VERSION 5.7 ;
BUSBITCHARS "[]" ;
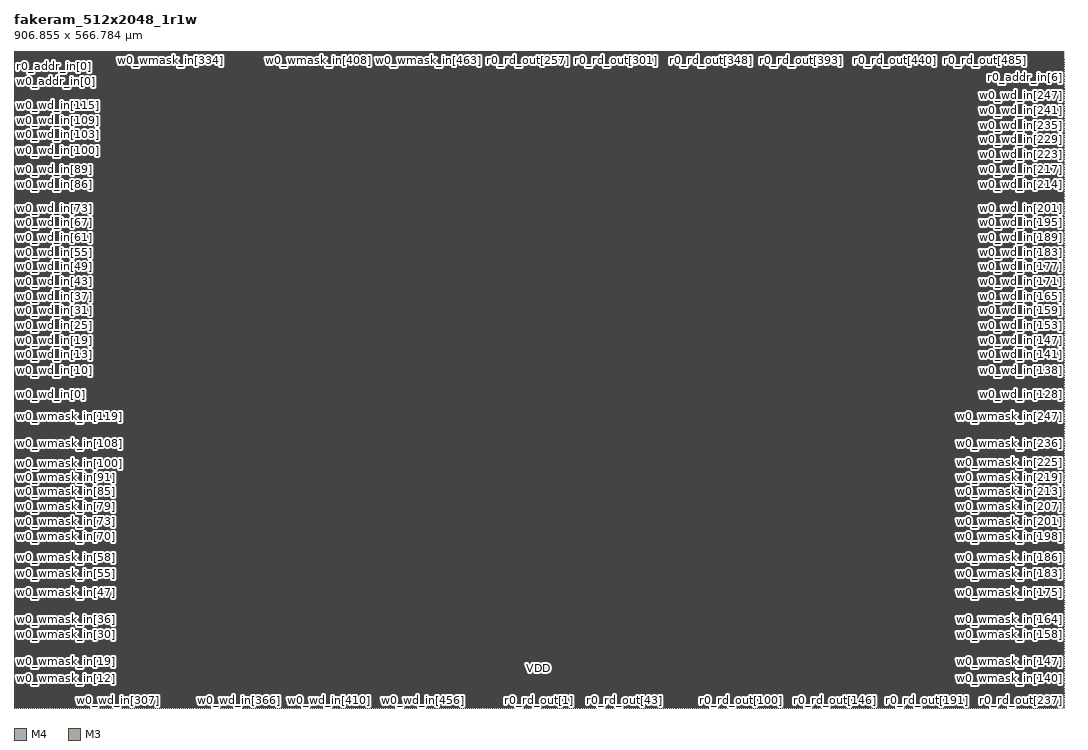
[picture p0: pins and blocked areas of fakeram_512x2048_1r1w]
MACRO fakeram_512x2048_1r1w
  FOREIGN fakeram_512x2048_1r1w 0 0 ;
  SYMMETRY X Y R90 ;
  SIZE 906.855 BY 566.784 ;
  CLASS BLOCK ;
  PIN w0_wmask_in[0]
    DIRECTION INPUT ;
    USE SIGNAL ;
    SHAPE ABUTMENT ;
    PORT
      LAYER M4 ;
      RECT 0.000 0.276 0.072 0.300 ;
    END
  END w0_wmask_in[0]
  PIN w0_wmask_in[1]
    DIRECTION INPUT ;
    USE SIGNAL ;
    SHAPE ABUTMENT ;
    PORT
      LAYER M4 ;
      RECT 0.000 2.388 0.072 2.412 ;
    END
  END w0_wmask_in[1]
  PIN w0_wmask_in[2]
    DIRECTION INPUT ;
    USE SIGNAL ;
    SHAPE ABUTMENT ;
    PORT
      LAYER M4 ;
      RECT 0.000 4.500 0.072 4.524 ;
    END
  END w0_wmask_in[2]
  PIN w0_wmask_in[3]
    DIRECTION INPUT ;
    USE SIGNAL ;
    SHAPE ABUTMENT ;
    PORT
      LAYER M4 ;
      RECT 0.000 6.612 0.072 6.636 ;
    END
  END w0_wmask_in[3]
  PIN w0_wmask_in[4]
    DIRECTION INPUT ;
    USE SIGNAL ;
    SHAPE ABUTMENT ;
    PORT
      LAYER M4 ;
      RECT 0.000 8.724 0.072 8.748 ;
    END
  END w0_wmask_in[4]
  PIN w0_wmask_in[5]
    DIRECTION INPUT ;
    USE SIGNAL ;
    SHAPE ABUTMENT ;
    PORT
      LAYER M4 ;
      RECT 0.000 10.836 0.072 10.860 ;
    END
  END w0_wmask_in[5]
  PIN w0_wmask_in[6]
    DIRECTION INPUT ;
    USE SIGNAL ;
    SHAPE ABUTMENT ;
    PORT
      LAYER M4 ;
      RECT 0.000 12.948 0.072 12.972 ;
    END
  END w0_wmask_in[6]
  PIN w0_wmask_in[7]
    DIRECTION INPUT ;
    USE SIGNAL ;
    SHAPE ABUTMENT ;
    PORT
      LAYER M4 ;
      RECT 0.000 15.060 0.072 15.084 ;
    END
  END w0_wmask_in[7]
  PIN w0_wmask_in[8]
    DIRECTION INPUT ;
    USE SIGNAL ;
    SHAPE ABUTMENT ;
    PORT
      LAYER M4 ;
      RECT 0.000 17.172 0.072 17.196 ;
    END
  END w0_wmask_in[8]
  PIN w0_wmask_in[9]
    DIRECTION INPUT ;
    USE SIGNAL ;
    SHAPE ABUTMENT ;
    PORT
      LAYER M4 ;
      RECT 0.000 19.284 0.072 19.308 ;
    END
  END w0_wmask_in[9]
  PIN w0_wmask_in[10]
    DIRECTION INPUT ;
    USE SIGNAL ;
    SHAPE ABUTMENT ;
    PORT
      LAYER M4 ;
      RECT 0.000 21.396 0.072 21.420 ;
    END
  END w0_wmask_in[10]
  PIN w0_wmask_in[11]
    DIRECTION INPUT ;
    USE SIGNAL ;
    SHAPE ABUTMENT ;
    PORT
      LAYER M4 ;
      RECT 0.000 23.508 0.072 23.532 ;
    END
  END w0_wmask_in[11]
  PIN w0_wmask_in[12]
    DIRECTION INPUT ;
    USE SIGNAL ;
    SHAPE ABUTMENT ;
    PORT
      LAYER M4 ;
      RECT 0.000 25.620 0.072 25.644 ;
    END
  END w0_wmask_in[12]
  PIN w0_wmask_in[13]
    DIRECTION INPUT ;
    USE SIGNAL ;
    SHAPE ABUTMENT ;
    PORT
      LAYER M4 ;
      RECT 0.000 27.732 0.072 27.756 ;
    END
  END w0_wmask_in[13]
  PIN w0_wmask_in[14]
    DIRECTION INPUT ;
    USE SIGNAL ;
    SHAPE ABUTMENT ;
    PORT
      LAYER M4 ;
      RECT 0.000 29.844 0.072 29.868 ;
    END
  END w0_wmask_in[14]
  PIN w0_wmask_in[15]
    DIRECTION INPUT ;
    USE SIGNAL ;
    SHAPE ABUTMENT ;
    PORT
      LAYER M4 ;
      RECT 0.000 31.956 0.072 31.980 ;
    END
  END w0_wmask_in[15]
  PIN w0_wmask_in[16]
    DIRECTION INPUT ;
    USE SIGNAL ;
    SHAPE ABUTMENT ;
    PORT
      LAYER M4 ;
      RECT 0.000 34.068 0.072 34.092 ;
    END
  END w0_wmask_in[16]
  PIN w0_wmask_in[17]
    DIRECTION INPUT ;
    USE SIGNAL ;
    SHAPE ABUTMENT ;
    PORT
      LAYER M4 ;
      RECT 0.000 36.180 0.072 36.204 ;
    END
  END w0_wmask_in[17]
  PIN w0_wmask_in[18]
    DIRECTION INPUT ;
    USE SIGNAL ;
    SHAPE ABUTMENT ;
    PORT
      LAYER M4 ;
      RECT 0.000 38.292 0.072 38.316 ;
    END
  END w0_wmask_in[18]
  PIN w0_wmask_in[19]
    DIRECTION INPUT ;
    USE SIGNAL ;
    SHAPE ABUTMENT ;
    PORT
      LAYER M4 ;
      RECT 0.000 40.404 0.072 40.428 ;
    END
  END w0_wmask_in[19]
  PIN w0_wmask_in[20]
    DIRECTION INPUT ;
    USE SIGNAL ;
    SHAPE ABUTMENT ;
    PORT
      LAYER M4 ;
      RECT 0.000 42.516 0.072 42.540 ;
    END
  END w0_wmask_in[20]
  PIN w0_wmask_in[21]
    DIRECTION INPUT ;
    USE SIGNAL ;
    SHAPE ABUTMENT ;
    PORT
      LAYER M4 ;
      RECT 0.000 44.628 0.072 44.652 ;
    END
  END w0_wmask_in[21]
  PIN w0_wmask_in[22]
    DIRECTION INPUT ;
    USE SIGNAL ;
    SHAPE ABUTMENT ;
    PORT
      LAYER M4 ;
      RECT 0.000 46.740 0.072 46.764 ;
    END
  END w0_wmask_in[22]
  PIN w0_wmask_in[23]
    DIRECTION INPUT ;
    USE SIGNAL ;
    SHAPE ABUTMENT ;
    PORT
      LAYER M4 ;
      RECT 0.000 48.852 0.072 48.876 ;
    END
  END w0_wmask_in[23]
  PIN w0_wmask_in[24]
    DIRECTION INPUT ;
    USE SIGNAL ;
    SHAPE ABUTMENT ;
    PORT
      LAYER M4 ;
      RECT 0.000 50.964 0.072 50.988 ;
    END
  END w0_wmask_in[24]
  PIN w0_wmask_in[25]
    DIRECTION INPUT ;
    USE SIGNAL ;
    SHAPE ABUTMENT ;
    PORT
      LAYER M4 ;
      RECT 0.000 53.076 0.072 53.100 ;
    END
  END w0_wmask_in[25]
  PIN w0_wmask_in[26]
    DIRECTION INPUT ;
    USE SIGNAL ;
    SHAPE ABUTMENT ;
    PORT
      LAYER M4 ;
      RECT 0.000 55.188 0.072 55.212 ;
    END
  END w0_wmask_in[26]
  PIN w0_wmask_in[27]
    DIRECTION INPUT ;
    USE SIGNAL ;
    SHAPE ABUTMENT ;
    PORT
      LAYER M4 ;
      RECT 0.000 57.300 0.072 57.324 ;
    END
  END w0_wmask_in[27]
  PIN w0_wmask_in[28]
    DIRECTION INPUT ;
    USE SIGNAL ;
    SHAPE ABUTMENT ;
    PORT
      LAYER M4 ;
      RECT 0.000 59.412 0.072 59.436 ;
    END
  END w0_wmask_in[28]
  PIN w0_wmask_in[29]
    DIRECTION INPUT ;
    USE SIGNAL ;
    SHAPE ABUTMENT ;
    PORT
      LAYER M4 ;
      RECT 0.000 61.524 0.072 61.548 ;
    END
  END w0_wmask_in[29]
  PIN w0_wmask_in[30]
    DIRECTION INPUT ;
    USE SIGNAL ;
    SHAPE ABUTMENT ;
    PORT
      LAYER M4 ;
      RECT 0.000 63.636 0.072 63.660 ;
    END
  END w0_wmask_in[30]
  PIN w0_wmask_in[31]
    DIRECTION INPUT ;
    USE SIGNAL ;
    SHAPE ABUTMENT ;
    PORT
      LAYER M4 ;
      RECT 0.000 65.748 0.072 65.772 ;
    END
  END w0_wmask_in[31]
  PIN w0_wmask_in[32]
    DIRECTION INPUT ;
    USE SIGNAL ;
    SHAPE ABUTMENT ;
    PORT
      LAYER M4 ;
      RECT 0.000 67.860 0.072 67.884 ;
    END
  END w0_wmask_in[32]
  PIN w0_wmask_in[33]
    DIRECTION INPUT ;
    USE SIGNAL ;
    SHAPE ABUTMENT ;
    PORT
      LAYER M4 ;
      RECT 0.000 69.972 0.072 69.996 ;
    END
  END w0_wmask_in[33]
  PIN w0_wmask_in[34]
    DIRECTION INPUT ;
    USE SIGNAL ;
    SHAPE ABUTMENT ;
    PORT
      LAYER M4 ;
      RECT 0.000 72.084 0.072 72.108 ;
    END
  END w0_wmask_in[34]
  PIN w0_wmask_in[35]
    DIRECTION INPUT ;
    USE SIGNAL ;
    SHAPE ABUTMENT ;
    PORT
      LAYER M4 ;
      RECT 0.000 74.196 0.072 74.220 ;
    END
  END w0_wmask_in[35]
  PIN w0_wmask_in[36]
    DIRECTION INPUT ;
    USE SIGNAL ;
    SHAPE ABUTMENT ;
    PORT
      LAYER M4 ;
      RECT 0.000 76.308 0.072 76.332 ;
    END
  END w0_wmask_in[36]
  PIN w0_wmask_in[37]
    DIRECTION INPUT ;
    USE SIGNAL ;
    SHAPE ABUTMENT ;
    PORT
      LAYER M4 ;
      RECT 0.000 78.420 0.072 78.444 ;
    END
  END w0_wmask_in[37]
  PIN w0_wmask_in[38]
    DIRECTION INPUT ;
    USE SIGNAL ;
    SHAPE ABUTMENT ;
    PORT
      LAYER M4 ;
      RECT 0.000 80.532 0.072 80.556 ;
    END
  END w0_wmask_in[38]
  PIN w0_wmask_in[39]
    DIRECTION INPUT ;
    USE SIGNAL ;
    SHAPE ABUTMENT ;
    PORT
      LAYER M4 ;
      RECT 0.000 82.644 0.072 82.668 ;
    END
  END w0_wmask_in[39]
  PIN w0_wmask_in[40]
    DIRECTION INPUT ;
    USE SIGNAL ;
    SHAPE ABUTMENT ;
    PORT
      LAYER M4 ;
      RECT 0.000 84.756 0.072 84.780 ;
    END
  END w0_wmask_in[40]
  PIN w0_wmask_in[41]
    DIRECTION INPUT ;
    USE SIGNAL ;
    SHAPE ABUTMENT ;
    PORT
      LAYER M4 ;
      RECT 0.000 86.868 0.072 86.892 ;
    END
  END w0_wmask_in[41]
  PIN w0_wmask_in[42]
    DIRECTION INPUT ;
    USE SIGNAL ;
    SHAPE ABUTMENT ;
    PORT
      LAYER M4 ;
      RECT 0.000 88.980 0.072 89.004 ;
    END
  END w0_wmask_in[42]
  PIN w0_wmask_in[43]
    DIRECTION INPUT ;
    USE SIGNAL ;
    SHAPE ABUTMENT ;
    PORT
      LAYER M4 ;
      RECT 0.000 91.092 0.072 91.116 ;
    END
  END w0_wmask_in[43]
  PIN w0_wmask_in[44]
    DIRECTION INPUT ;
    USE SIGNAL ;
    SHAPE ABUTMENT ;
    PORT
      LAYER M4 ;
      RECT 0.000 93.204 0.072 93.228 ;
    END
  END w0_wmask_in[44]
  PIN w0_wmask_in[45]
    DIRECTION INPUT ;
    USE SIGNAL ;
    SHAPE ABUTMENT ;
    PORT
      LAYER M4 ;
      RECT 0.000 95.316 0.072 95.340 ;
    END
  END w0_wmask_in[45]
  PIN w0_wmask_in[46]
    DIRECTION INPUT ;
    USE SIGNAL ;
    SHAPE ABUTMENT ;
    PORT
      LAYER M4 ;
      RECT 0.000 97.428 0.072 97.452 ;
    END
  END w0_wmask_in[46]
  PIN w0_wmask_in[47]
    DIRECTION INPUT ;
    USE SIGNAL ;
    SHAPE ABUTMENT ;
    PORT
      LAYER M4 ;
      RECT 0.000 99.540 0.072 99.564 ;
    END
  END w0_wmask_in[47]
  PIN w0_wmask_in[48]
    DIRECTION INPUT ;
    USE SIGNAL ;
    SHAPE ABUTMENT ;
    PORT
      LAYER M4 ;
      RECT 0.000 101.652 0.072 101.676 ;
    END
  END w0_wmask_in[48]
  PIN w0_wmask_in[49]
    DIRECTION INPUT ;
    USE SIGNAL ;
    SHAPE ABUTMENT ;
    PORT
      LAYER M4 ;
      RECT 0.000 103.764 0.072 103.788 ;
    END
  END w0_wmask_in[49]
  PIN w0_wmask_in[50]
    DIRECTION INPUT ;
    USE SIGNAL ;
    SHAPE ABUTMENT ;
    PORT
      LAYER M4 ;
      RECT 0.000 105.876 0.072 105.900 ;
    END
  END w0_wmask_in[50]
  PIN w0_wmask_in[51]
    DIRECTION INPUT ;
    USE SIGNAL ;
    SHAPE ABUTMENT ;
    PORT
      LAYER M4 ;
      RECT 0.000 107.988 0.072 108.012 ;
    END
  END w0_wmask_in[51]
  PIN w0_wmask_in[52]
    DIRECTION INPUT ;
    USE SIGNAL ;
    SHAPE ABUTMENT ;
    PORT
      LAYER M4 ;
      RECT 0.000 110.100 0.072 110.124 ;
    END
  END w0_wmask_in[52]
  PIN w0_wmask_in[53]
    DIRECTION INPUT ;
    USE SIGNAL ;
    SHAPE ABUTMENT ;
    PORT
      LAYER M4 ;
      RECT 0.000 112.212 0.072 112.236 ;
    END
  END w0_wmask_in[53]
  PIN w0_wmask_in[54]
    DIRECTION INPUT ;
    USE SIGNAL ;
    SHAPE ABUTMENT ;
    PORT
      LAYER M4 ;
      RECT 0.000 114.324 0.072 114.348 ;
    END
  END w0_wmask_in[54]
  PIN w0_wmask_in[55]
    DIRECTION INPUT ;
    USE SIGNAL ;
    SHAPE ABUTMENT ;
    PORT
      LAYER M4 ;
      RECT 0.000 116.436 0.072 116.460 ;
    END
  END w0_wmask_in[55]
  PIN w0_wmask_in[56]
    DIRECTION INPUT ;
    USE SIGNAL ;
    SHAPE ABUTMENT ;
    PORT
      LAYER M4 ;
      RECT 0.000 118.548 0.072 118.572 ;
    END
  END w0_wmask_in[56]
  PIN w0_wmask_in[57]
    DIRECTION INPUT ;
    USE SIGNAL ;
    SHAPE ABUTMENT ;
    PORT
      LAYER M4 ;
      RECT 0.000 120.660 0.072 120.684 ;
    END
  END w0_wmask_in[57]
  PIN w0_wmask_in[58]
    DIRECTION INPUT ;
    USE SIGNAL ;
    SHAPE ABUTMENT ;
    PORT
      LAYER M4 ;
      RECT 0.000 122.772 0.072 122.796 ;
    END
  END w0_wmask_in[58]
  PIN w0_wmask_in[59]
    DIRECTION INPUT ;
    USE SIGNAL ;
    SHAPE ABUTMENT ;
    PORT
      LAYER M4 ;
      RECT 0.000 124.884 0.072 124.908 ;
    END
  END w0_wmask_in[59]
  PIN w0_wmask_in[60]
    DIRECTION INPUT ;
    USE SIGNAL ;
    SHAPE ABUTMENT ;
    PORT
      LAYER M4 ;
      RECT 0.000 126.996 0.072 127.020 ;
    END
  END w0_wmask_in[60]
  PIN w0_wmask_in[61]
    DIRECTION INPUT ;
    USE SIGNAL ;
    SHAPE ABUTMENT ;
    PORT
      LAYER M4 ;
      RECT 0.000 129.108 0.072 129.132 ;
    END
  END w0_wmask_in[61]
  PIN w0_wmask_in[62]
    DIRECTION INPUT ;
    USE SIGNAL ;
    SHAPE ABUTMENT ;
    PORT
      LAYER M4 ;
      RECT 0.000 131.220 0.072 131.244 ;
    END
  END w0_wmask_in[62]
  PIN w0_wmask_in[63]
    DIRECTION INPUT ;
    USE SIGNAL ;
    SHAPE ABUTMENT ;
    PORT
      LAYER M4 ;
      RECT 0.000 133.332 0.072 133.356 ;
    END
  END w0_wmask_in[63]
  PIN w0_wmask_in[64]
    DIRECTION INPUT ;
    USE SIGNAL ;
    SHAPE ABUTMENT ;
    PORT
      LAYER M4 ;
      RECT 0.000 135.444 0.072 135.468 ;
    END
  END w0_wmask_in[64]
  PIN w0_wmask_in[65]
    DIRECTION INPUT ;
    USE SIGNAL ;
    SHAPE ABUTMENT ;
    PORT
      LAYER M4 ;
      RECT 0.000 137.556 0.072 137.580 ;
    END
  END w0_wmask_in[65]
  PIN w0_wmask_in[66]
    DIRECTION INPUT ;
    USE SIGNAL ;
    SHAPE ABUTMENT ;
    PORT
      LAYER M4 ;
      RECT 0.000 139.668 0.072 139.692 ;
    END
  END w0_wmask_in[66]
  PIN w0_wmask_in[67]
    DIRECTION INPUT ;
    USE SIGNAL ;
    SHAPE ABUTMENT ;
    PORT
      LAYER M4 ;
      RECT 0.000 141.780 0.072 141.804 ;
    END
  END w0_wmask_in[67]
  PIN w0_wmask_in[68]
    DIRECTION INPUT ;
    USE SIGNAL ;
    SHAPE ABUTMENT ;
    PORT
      LAYER M4 ;
      RECT 0.000 143.892 0.072 143.916 ;
    END
  END w0_wmask_in[68]
  PIN w0_wmask_in[69]
    DIRECTION INPUT ;
    USE SIGNAL ;
    SHAPE ABUTMENT ;
    PORT
      LAYER M4 ;
      RECT 0.000 146.004 0.072 146.028 ;
    END
  END w0_wmask_in[69]
  PIN w0_wmask_in[70]
    DIRECTION INPUT ;
    USE SIGNAL ;
    SHAPE ABUTMENT ;
    PORT
      LAYER M4 ;
      RECT 0.000 148.116 0.072 148.140 ;
    END
  END w0_wmask_in[70]
  PIN w0_wmask_in[71]
    DIRECTION INPUT ;
    USE SIGNAL ;
    SHAPE ABUTMENT ;
    PORT
      LAYER M4 ;
      RECT 0.000 150.228 0.072 150.252 ;
    END
  END w0_wmask_in[71]
  PIN w0_wmask_in[72]
    DIRECTION INPUT ;
    USE SIGNAL ;
    SHAPE ABUTMENT ;
    PORT
      LAYER M4 ;
      RECT 0.000 152.340 0.072 152.364 ;
    END
  END w0_wmask_in[72]
  PIN w0_wmask_in[73]
    DIRECTION INPUT ;
    USE SIGNAL ;
    SHAPE ABUTMENT ;
    PORT
      LAYER M4 ;
      RECT 0.000 154.452 0.072 154.476 ;
    END
  END w0_wmask_in[73]
  PIN w0_wmask_in[74]
    DIRECTION INPUT ;
    USE SIGNAL ;
    SHAPE ABUTMENT ;
    PORT
      LAYER M4 ;
      RECT 0.000 156.564 0.072 156.588 ;
    END
  END w0_wmask_in[74]
  PIN w0_wmask_in[75]
    DIRECTION INPUT ;
    USE SIGNAL ;
    SHAPE ABUTMENT ;
    PORT
      LAYER M4 ;
      RECT 0.000 158.676 0.072 158.700 ;
    END
  END w0_wmask_in[75]
  PIN w0_wmask_in[76]
    DIRECTION INPUT ;
    USE SIGNAL ;
    SHAPE ABUTMENT ;
    PORT
      LAYER M4 ;
      RECT 0.000 160.788 0.072 160.812 ;
    END
  END w0_wmask_in[76]
  PIN w0_wmask_in[77]
    DIRECTION INPUT ;
    USE SIGNAL ;
    SHAPE ABUTMENT ;
    PORT
      LAYER M4 ;
      RECT 0.000 162.900 0.072 162.924 ;
    END
  END w0_wmask_in[77]
  PIN w0_wmask_in[78]
    DIRECTION INPUT ;
    USE SIGNAL ;
    SHAPE ABUTMENT ;
    PORT
      LAYER M4 ;
      RECT 0.000 165.012 0.072 165.036 ;
    END
  END w0_wmask_in[78]
  PIN w0_wmask_in[79]
    DIRECTION INPUT ;
    USE SIGNAL ;
    SHAPE ABUTMENT ;
    PORT
      LAYER M4 ;
      RECT 0.000 167.124 0.072 167.148 ;
    END
  END w0_wmask_in[79]
  PIN w0_wmask_in[80]
    DIRECTION INPUT ;
    USE SIGNAL ;
    SHAPE ABUTMENT ;
    PORT
      LAYER M4 ;
      RECT 0.000 169.236 0.072 169.260 ;
    END
  END w0_wmask_in[80]
  PIN w0_wmask_in[81]
    DIRECTION INPUT ;
    USE SIGNAL ;
    SHAPE ABUTMENT ;
    PORT
      LAYER M4 ;
      RECT 0.000 171.348 0.072 171.372 ;
    END
  END w0_wmask_in[81]
  PIN w0_wmask_in[82]
    DIRECTION INPUT ;
    USE SIGNAL ;
    SHAPE ABUTMENT ;
    PORT
      LAYER M4 ;
      RECT 0.000 173.460 0.072 173.484 ;
    END
  END w0_wmask_in[82]
  PIN w0_wmask_in[83]
    DIRECTION INPUT ;
    USE SIGNAL ;
    SHAPE ABUTMENT ;
    PORT
      LAYER M4 ;
      RECT 0.000 175.572 0.072 175.596 ;
    END
  END w0_wmask_in[83]
  PIN w0_wmask_in[84]
    DIRECTION INPUT ;
    USE SIGNAL ;
    SHAPE ABUTMENT ;
    PORT
      LAYER M4 ;
      RECT 0.000 177.684 0.072 177.708 ;
    END
  END w0_wmask_in[84]
  PIN w0_wmask_in[85]
    DIRECTION INPUT ;
    USE SIGNAL ;
    SHAPE ABUTMENT ;
    PORT
      LAYER M4 ;
      RECT 0.000 179.796 0.072 179.820 ;
    END
  END w0_wmask_in[85]
  PIN w0_wmask_in[86]
    DIRECTION INPUT ;
    USE SIGNAL ;
    SHAPE ABUTMENT ;
    PORT
      LAYER M4 ;
      RECT 0.000 181.908 0.072 181.932 ;
    END
  END w0_wmask_in[86]
  PIN w0_wmask_in[87]
    DIRECTION INPUT ;
    USE SIGNAL ;
    SHAPE ABUTMENT ;
    PORT
      LAYER M4 ;
      RECT 0.000 184.020 0.072 184.044 ;
    END
  END w0_wmask_in[87]
  PIN w0_wmask_in[88]
    DIRECTION INPUT ;
    USE SIGNAL ;
    SHAPE ABUTMENT ;
    PORT
      LAYER M4 ;
      RECT 0.000 186.132 0.072 186.156 ;
    END
  END w0_wmask_in[88]
  PIN w0_wmask_in[89]
    DIRECTION INPUT ;
    USE SIGNAL ;
    SHAPE ABUTMENT ;
    PORT
      LAYER M4 ;
      RECT 0.000 188.244 0.072 188.268 ;
    END
  END w0_wmask_in[89]
  PIN w0_wmask_in[90]
    DIRECTION INPUT ;
    USE SIGNAL ;
    SHAPE ABUTMENT ;
    PORT
      LAYER M4 ;
      RECT 0.000 190.356 0.072 190.380 ;
    END
  END w0_wmask_in[90]
  PIN w0_wmask_in[91]
    DIRECTION INPUT ;
    USE SIGNAL ;
    SHAPE ABUTMENT ;
    PORT
      LAYER M4 ;
      RECT 0.000 192.468 0.072 192.492 ;
    END
  END w0_wmask_in[91]
  PIN w0_wmask_in[92]
    DIRECTION INPUT ;
    USE SIGNAL ;
    SHAPE ABUTMENT ;
    PORT
      LAYER M4 ;
      RECT 0.000 194.580 0.072 194.604 ;
    END
  END w0_wmask_in[92]
  PIN w0_wmask_in[93]
    DIRECTION INPUT ;
    USE SIGNAL ;
    SHAPE ABUTMENT ;
    PORT
      LAYER M4 ;
      RECT 0.000 196.692 0.072 196.716 ;
    END
  END w0_wmask_in[93]
  PIN w0_wmask_in[94]
    DIRECTION INPUT ;
    USE SIGNAL ;
    SHAPE ABUTMENT ;
    PORT
      LAYER M4 ;
      RECT 0.000 198.804 0.072 198.828 ;
    END
  END w0_wmask_in[94]
  PIN w0_wmask_in[95]
    DIRECTION INPUT ;
    USE SIGNAL ;
    SHAPE ABUTMENT ;
    PORT
      LAYER M4 ;
      RECT 0.000 200.916 0.072 200.940 ;
    END
  END w0_wmask_in[95]
  PIN w0_wmask_in[96]
    DIRECTION INPUT ;
    USE SIGNAL ;
    SHAPE ABUTMENT ;
    PORT
      LAYER M4 ;
      RECT 0.000 203.028 0.072 203.052 ;
    END
  END w0_wmask_in[96]
  PIN w0_wmask_in[97]
    DIRECTION INPUT ;
    USE SIGNAL ;
    SHAPE ABUTMENT ;
    PORT
      LAYER M4 ;
      RECT 0.000 205.140 0.072 205.164 ;
    END
  END w0_wmask_in[97]
  PIN w0_wmask_in[98]
    DIRECTION INPUT ;
    USE SIGNAL ;
    SHAPE ABUTMENT ;
    PORT
      LAYER M4 ;
      RECT 0.000 207.252 0.072 207.276 ;
    END
  END w0_wmask_in[98]
  PIN w0_wmask_in[99]
    DIRECTION INPUT ;
    USE SIGNAL ;
    SHAPE ABUTMENT ;
    PORT
      LAYER M4 ;
      RECT 0.000 209.364 0.072 209.388 ;
    END
  END w0_wmask_in[99]
  PIN w0_wmask_in[100]
    DIRECTION INPUT ;
    USE SIGNAL ;
    SHAPE ABUTMENT ;
    PORT
      LAYER M4 ;
      RECT 0.000 211.476 0.072 211.500 ;
    END
  END w0_wmask_in[100]
  PIN w0_wmask_in[101]
    DIRECTION INPUT ;
    USE SIGNAL ;
    SHAPE ABUTMENT ;
    PORT
      LAYER M4 ;
      RECT 0.000 213.588 0.072 213.612 ;
    END
  END w0_wmask_in[101]
  PIN w0_wmask_in[102]
    DIRECTION INPUT ;
    USE SIGNAL ;
    SHAPE ABUTMENT ;
    PORT
      LAYER M4 ;
      RECT 0.000 215.700 0.072 215.724 ;
    END
  END w0_wmask_in[102]
  PIN w0_wmask_in[103]
    DIRECTION INPUT ;
    USE SIGNAL ;
    SHAPE ABUTMENT ;
    PORT
      LAYER M4 ;
      RECT 0.000 217.812 0.072 217.836 ;
    END
  END w0_wmask_in[103]
  PIN w0_wmask_in[104]
    DIRECTION INPUT ;
    USE SIGNAL ;
    SHAPE ABUTMENT ;
    PORT
      LAYER M4 ;
      RECT 0.000 219.924 0.072 219.948 ;
    END
  END w0_wmask_in[104]
  PIN w0_wmask_in[105]
    DIRECTION INPUT ;
    USE SIGNAL ;
    SHAPE ABUTMENT ;
    PORT
      LAYER M4 ;
      RECT 0.000 222.036 0.072 222.060 ;
    END
  END w0_wmask_in[105]
  PIN w0_wmask_in[106]
    DIRECTION INPUT ;
    USE SIGNAL ;
    SHAPE ABUTMENT ;
    PORT
      LAYER M4 ;
      RECT 0.000 224.148 0.072 224.172 ;
    END
  END w0_wmask_in[106]
  PIN w0_wmask_in[107]
    DIRECTION INPUT ;
    USE SIGNAL ;
    SHAPE ABUTMENT ;
    PORT
      LAYER M4 ;
      RECT 0.000 226.260 0.072 226.284 ;
    END
  END w0_wmask_in[107]
  PIN w0_wmask_in[108]
    DIRECTION INPUT ;
    USE SIGNAL ;
    SHAPE ABUTMENT ;
    PORT
      LAYER M4 ;
      RECT 0.000 228.372 0.072 228.396 ;
    END
  END w0_wmask_in[108]
  PIN w0_wmask_in[109]
    DIRECTION INPUT ;
    USE SIGNAL ;
    SHAPE ABUTMENT ;
    PORT
      LAYER M4 ;
      RECT 0.000 230.484 0.072 230.508 ;
    END
  END w0_wmask_in[109]
  PIN w0_wmask_in[110]
    DIRECTION INPUT ;
    USE SIGNAL ;
    SHAPE ABUTMENT ;
    PORT
      LAYER M4 ;
      RECT 0.000 232.596 0.072 232.620 ;
    END
  END w0_wmask_in[110]
  PIN w0_wmask_in[111]
    DIRECTION INPUT ;
    USE SIGNAL ;
    SHAPE ABUTMENT ;
    PORT
      LAYER M4 ;
      RECT 0.000 234.708 0.072 234.732 ;
    END
  END w0_wmask_in[111]
  PIN w0_wmask_in[112]
    DIRECTION INPUT ;
    USE SIGNAL ;
    SHAPE ABUTMENT ;
    PORT
      LAYER M4 ;
      RECT 0.000 236.820 0.072 236.844 ;
    END
  END w0_wmask_in[112]
  PIN w0_wmask_in[113]
    DIRECTION INPUT ;
    USE SIGNAL ;
    SHAPE ABUTMENT ;
    PORT
      LAYER M4 ;
      RECT 0.000 238.932 0.072 238.956 ;
    END
  END w0_wmask_in[113]
  PIN w0_wmask_in[114]
    DIRECTION INPUT ;
    USE SIGNAL ;
    SHAPE ABUTMENT ;
    PORT
      LAYER M4 ;
      RECT 0.000 241.044 0.072 241.068 ;
    END
  END w0_wmask_in[114]
  PIN w0_wmask_in[115]
    DIRECTION INPUT ;
    USE SIGNAL ;
    SHAPE ABUTMENT ;
    PORT
      LAYER M4 ;
      RECT 0.000 243.156 0.072 243.180 ;
    END
  END w0_wmask_in[115]
  PIN w0_wmask_in[116]
    DIRECTION INPUT ;
    USE SIGNAL ;
    SHAPE ABUTMENT ;
    PORT
      LAYER M4 ;
      RECT 0.000 245.268 0.072 245.292 ;
    END
  END w0_wmask_in[116]
  PIN w0_wmask_in[117]
    DIRECTION INPUT ;
    USE SIGNAL ;
    SHAPE ABUTMENT ;
    PORT
      LAYER M4 ;
      RECT 0.000 247.380 0.072 247.404 ;
    END
  END w0_wmask_in[117]
  PIN w0_wmask_in[118]
    DIRECTION INPUT ;
    USE SIGNAL ;
    SHAPE ABUTMENT ;
    PORT
      LAYER M4 ;
      RECT 0.000 249.492 0.072 249.516 ;
    END
  END w0_wmask_in[118]
  PIN w0_wmask_in[119]
    DIRECTION INPUT ;
    USE SIGNAL ;
    SHAPE ABUTMENT ;
    PORT
      LAYER M4 ;
      RECT 0.000 251.604 0.072 251.628 ;
    END
  END w0_wmask_in[119]
  PIN w0_wmask_in[120]
    DIRECTION INPUT ;
    USE SIGNAL ;
    SHAPE ABUTMENT ;
    PORT
      LAYER M4 ;
      RECT 0.000 253.716 0.072 253.740 ;
    END
  END w0_wmask_in[120]
  PIN w0_wmask_in[121]
    DIRECTION INPUT ;
    USE SIGNAL ;
    SHAPE ABUTMENT ;
    PORT
      LAYER M4 ;
      RECT 0.000 255.828 0.072 255.852 ;
    END
  END w0_wmask_in[121]
  PIN w0_wmask_in[122]
    DIRECTION INPUT ;
    USE SIGNAL ;
    SHAPE ABUTMENT ;
    PORT
      LAYER M4 ;
      RECT 0.000 257.940 0.072 257.964 ;
    END
  END w0_wmask_in[122]
  PIN w0_wmask_in[123]
    DIRECTION INPUT ;
    USE SIGNAL ;
    SHAPE ABUTMENT ;
    PORT
      LAYER M4 ;
      RECT 0.000 260.052 0.072 260.076 ;
    END
  END w0_wmask_in[123]
  PIN w0_wmask_in[124]
    DIRECTION INPUT ;
    USE SIGNAL ;
    SHAPE ABUTMENT ;
    PORT
      LAYER M4 ;
      RECT 0.000 262.164 0.072 262.188 ;
    END
  END w0_wmask_in[124]
  PIN w0_wmask_in[125]
    DIRECTION INPUT ;
    USE SIGNAL ;
    SHAPE ABUTMENT ;
    PORT
      LAYER M4 ;
      RECT 0.000 264.276 0.072 264.300 ;
    END
  END w0_wmask_in[125]
  PIN w0_wmask_in[126]
    DIRECTION INPUT ;
    USE SIGNAL ;
    SHAPE ABUTMENT ;
    PORT
      LAYER M4 ;
      RECT 0.000 266.388 0.072 266.412 ;
    END
  END w0_wmask_in[126]
  PIN w0_wmask_in[127]
    DIRECTION INPUT ;
    USE SIGNAL ;
    SHAPE ABUTMENT ;
    PORT
      LAYER M4 ;
      RECT 0.000 268.500 0.072 268.524 ;
    END
  END w0_wmask_in[127]
  PIN w0_wmask_in[128]
    DIRECTION INPUT ;
    USE SIGNAL ;
    SHAPE ABUTMENT ;
    PORT
      LAYER M4 ;
      RECT 906.783 0.276 906.855 0.300 ;
    END
  END w0_wmask_in[128]
  PIN w0_wmask_in[129]
    DIRECTION INPUT ;
    USE SIGNAL ;
    SHAPE ABUTMENT ;
    PORT
      LAYER M4 ;
      RECT 906.783 2.388 906.855 2.412 ;
    END
  END w0_wmask_in[129]
  PIN w0_wmask_in[130]
    DIRECTION INPUT ;
    USE SIGNAL ;
    SHAPE ABUTMENT ;
    PORT
      LAYER M4 ;
      RECT 906.783 4.500 906.855 4.524 ;
    END
  END w0_wmask_in[130]
  PIN w0_wmask_in[131]
    DIRECTION INPUT ;
    USE SIGNAL ;
    SHAPE ABUTMENT ;
    PORT
      LAYER M4 ;
      RECT 906.783 6.612 906.855 6.636 ;
    END
  END w0_wmask_in[131]
  PIN w0_wmask_in[132]
    DIRECTION INPUT ;
    USE SIGNAL ;
    SHAPE ABUTMENT ;
    PORT
      LAYER M4 ;
      RECT 906.783 8.724 906.855 8.748 ;
    END
  END w0_wmask_in[132]
  PIN w0_wmask_in[133]
    DIRECTION INPUT ;
    USE SIGNAL ;
    SHAPE ABUTMENT ;
    PORT
      LAYER M4 ;
      RECT 906.783 10.836 906.855 10.860 ;
    END
  END w0_wmask_in[133]
  PIN w0_wmask_in[134]
    DIRECTION INPUT ;
    USE SIGNAL ;
    SHAPE ABUTMENT ;
    PORT
      LAYER M4 ;
      RECT 906.783 12.948 906.855 12.972 ;
    END
  END w0_wmask_in[134]
  PIN w0_wmask_in[135]
    DIRECTION INPUT ;
    USE SIGNAL ;
    SHAPE ABUTMENT ;
    PORT
      LAYER M4 ;
      RECT 906.783 15.060 906.855 15.084 ;
    END
  END w0_wmask_in[135]
  PIN w0_wmask_in[136]
    DIRECTION INPUT ;
    USE SIGNAL ;
    SHAPE ABUTMENT ;
    PORT
      LAYER M4 ;
      RECT 906.783 17.172 906.855 17.196 ;
    END
  END w0_wmask_in[136]
  PIN w0_wmask_in[137]
    DIRECTION INPUT ;
    USE SIGNAL ;
    SHAPE ABUTMENT ;
    PORT
      LAYER M4 ;
      RECT 906.783 19.284 906.855 19.308 ;
    END
  END w0_wmask_in[137]
  PIN w0_wmask_in[138]
    DIRECTION INPUT ;
    USE SIGNAL ;
    SHAPE ABUTMENT ;
    PORT
      LAYER M4 ;
      RECT 906.783 21.396 906.855 21.420 ;
    END
  END w0_wmask_in[138]
  PIN w0_wmask_in[139]
    DIRECTION INPUT ;
    USE SIGNAL ;
    SHAPE ABUTMENT ;
    PORT
      LAYER M4 ;
      RECT 906.783 23.508 906.855 23.532 ;
    END
  END w0_wmask_in[139]
  PIN w0_wmask_in[140]
    DIRECTION INPUT ;
    USE SIGNAL ;
    SHAPE ABUTMENT ;
    PORT
      LAYER M4 ;
      RECT 906.783 25.620 906.855 25.644 ;
    END
  END w0_wmask_in[140]
  PIN w0_wmask_in[141]
    DIRECTION INPUT ;
    USE SIGNAL ;
    SHAPE ABUTMENT ;
    PORT
      LAYER M4 ;
      RECT 906.783 27.732 906.855 27.756 ;
    END
  END w0_wmask_in[141]
  PIN w0_wmask_in[142]
    DIRECTION INPUT ;
    USE SIGNAL ;
    SHAPE ABUTMENT ;
    PORT
      LAYER M4 ;
      RECT 906.783 29.844 906.855 29.868 ;
    END
  END w0_wmask_in[142]
  PIN w0_wmask_in[143]
    DIRECTION INPUT ;
    USE SIGNAL ;
    SHAPE ABUTMENT ;
    PORT
      LAYER M4 ;
      RECT 906.783 31.956 906.855 31.980 ;
    END
  END w0_wmask_in[143]
  PIN w0_wmask_in[144]
    DIRECTION INPUT ;
    USE SIGNAL ;
    SHAPE ABUTMENT ;
    PORT
      LAYER M4 ;
      RECT 906.783 34.068 906.855 34.092 ;
    END
  END w0_wmask_in[144]
  PIN w0_wmask_in[145]
    DIRECTION INPUT ;
    USE SIGNAL ;
    SHAPE ABUTMENT ;
    PORT
      LAYER M4 ;
      RECT 906.783 36.180 906.855 36.204 ;
    END
  END w0_wmask_in[145]
  PIN w0_wmask_in[146]
    DIRECTION INPUT ;
    USE SIGNAL ;
    SHAPE ABUTMENT ;
    PORT
      LAYER M4 ;
      RECT 906.783 38.292 906.855 38.316 ;
    END
  END w0_wmask_in[146]
  PIN w0_wmask_in[147]
    DIRECTION INPUT ;
    USE SIGNAL ;
    SHAPE ABUTMENT ;
    PORT
      LAYER M4 ;
      RECT 906.783 40.404 906.855 40.428 ;
    END
  END w0_wmask_in[147]
  PIN w0_wmask_in[148]
    DIRECTION INPUT ;
    USE SIGNAL ;
    SHAPE ABUTMENT ;
    PORT
      LAYER M4 ;
      RECT 906.783 42.516 906.855 42.540 ;
    END
  END w0_wmask_in[148]
  PIN w0_wmask_in[149]
    DIRECTION INPUT ;
    USE SIGNAL ;
    SHAPE ABUTMENT ;
    PORT
      LAYER M4 ;
      RECT 906.783 44.628 906.855 44.652 ;
    END
  END w0_wmask_in[149]
  PIN w0_wmask_in[150]
    DIRECTION INPUT ;
    USE SIGNAL ;
    SHAPE ABUTMENT ;
    PORT
      LAYER M4 ;
      RECT 906.783 46.740 906.855 46.764 ;
    END
  END w0_wmask_in[150]
  PIN w0_wmask_in[151]
    DIRECTION INPUT ;
    USE SIGNAL ;
    SHAPE ABUTMENT ;
    PORT
      LAYER M4 ;
      RECT 906.783 48.852 906.855 48.876 ;
    END
  END w0_wmask_in[151]
  PIN w0_wmask_in[152]
    DIRECTION INPUT ;
    USE SIGNAL ;
    SHAPE ABUTMENT ;
    PORT
      LAYER M4 ;
      RECT 906.783 50.964 906.855 50.988 ;
    END
  END w0_wmask_in[152]
  PIN w0_wmask_in[153]
    DIRECTION INPUT ;
    USE SIGNAL ;
    SHAPE ABUTMENT ;
    PORT
      LAYER M4 ;
      RECT 906.783 53.076 906.855 53.100 ;
    END
  END w0_wmask_in[153]
  PIN w0_wmask_in[154]
    DIRECTION INPUT ;
    USE SIGNAL ;
    SHAPE ABUTMENT ;
    PORT
      LAYER M4 ;
      RECT 906.783 55.188 906.855 55.212 ;
    END
  END w0_wmask_in[154]
  PIN w0_wmask_in[155]
    DIRECTION INPUT ;
    USE SIGNAL ;
    SHAPE ABUTMENT ;
    PORT
      LAYER M4 ;
      RECT 906.783 57.300 906.855 57.324 ;
    END
  END w0_wmask_in[155]
  PIN w0_wmask_in[156]
    DIRECTION INPUT ;
    USE SIGNAL ;
    SHAPE ABUTMENT ;
    PORT
      LAYER M4 ;
      RECT 906.783 59.412 906.855 59.436 ;
    END
  END w0_wmask_in[156]
  PIN w0_wmask_in[157]
    DIRECTION INPUT ;
    USE SIGNAL ;
    SHAPE ABUTMENT ;
    PORT
      LAYER M4 ;
      RECT 906.783 61.524 906.855 61.548 ;
    END
  END w0_wmask_in[157]
  PIN w0_wmask_in[158]
    DIRECTION INPUT ;
    USE SIGNAL ;
    SHAPE ABUTMENT ;
    PORT
      LAYER M4 ;
      RECT 906.783 63.636 906.855 63.660 ;
    END
  END w0_wmask_in[158]
  PIN w0_wmask_in[159]
    DIRECTION INPUT ;
    USE SIGNAL ;
    SHAPE ABUTMENT ;
    PORT
      LAYER M4 ;
      RECT 906.783 65.748 906.855 65.772 ;
    END
  END w0_wmask_in[159]
  PIN w0_wmask_in[160]
    DIRECTION INPUT ;
    USE SIGNAL ;
    SHAPE ABUTMENT ;
    PORT
      LAYER M4 ;
      RECT 906.783 67.860 906.855 67.884 ;
    END
  END w0_wmask_in[160]
  PIN w0_wmask_in[161]
    DIRECTION INPUT ;
    USE SIGNAL ;
    SHAPE ABUTMENT ;
    PORT
      LAYER M4 ;
      RECT 906.783 69.972 906.855 69.996 ;
    END
  END w0_wmask_in[161]
  PIN w0_wmask_in[162]
    DIRECTION INPUT ;
    USE SIGNAL ;
    SHAPE ABUTMENT ;
    PORT
      LAYER M4 ;
      RECT 906.783 72.084 906.855 72.108 ;
    END
  END w0_wmask_in[162]
  PIN w0_wmask_in[163]
    DIRECTION INPUT ;
    USE SIGNAL ;
    SHAPE ABUTMENT ;
    PORT
      LAYER M4 ;
      RECT 906.783 74.196 906.855 74.220 ;
    END
  END w0_wmask_in[163]
  PIN w0_wmask_in[164]
    DIRECTION INPUT ;
    USE SIGNAL ;
    SHAPE ABUTMENT ;
    PORT
      LAYER M4 ;
      RECT 906.783 76.308 906.855 76.332 ;
    END
  END w0_wmask_in[164]
  PIN w0_wmask_in[165]
    DIRECTION INPUT ;
    USE SIGNAL ;
    SHAPE ABUTMENT ;
    PORT
      LAYER M4 ;
      RECT 906.783 78.420 906.855 78.444 ;
    END
  END w0_wmask_in[165]
  PIN w0_wmask_in[166]
    DIRECTION INPUT ;
    USE SIGNAL ;
    SHAPE ABUTMENT ;
    PORT
      LAYER M4 ;
      RECT 906.783 80.532 906.855 80.556 ;
    END
  END w0_wmask_in[166]
  PIN w0_wmask_in[167]
    DIRECTION INPUT ;
    USE SIGNAL ;
    SHAPE ABUTMENT ;
    PORT
      LAYER M4 ;
      RECT 906.783 82.644 906.855 82.668 ;
    END
  END w0_wmask_in[167]
  PIN w0_wmask_in[168]
    DIRECTION INPUT ;
    USE SIGNAL ;
    SHAPE ABUTMENT ;
    PORT
      LAYER M4 ;
      RECT 906.783 84.756 906.855 84.780 ;
    END
  END w0_wmask_in[168]
  PIN w0_wmask_in[169]
    DIRECTION INPUT ;
    USE SIGNAL ;
    SHAPE ABUTMENT ;
    PORT
      LAYER M4 ;
      RECT 906.783 86.868 906.855 86.892 ;
    END
  END w0_wmask_in[169]
  PIN w0_wmask_in[170]
    DIRECTION INPUT ;
    USE SIGNAL ;
    SHAPE ABUTMENT ;
    PORT
      LAYER M4 ;
      RECT 906.783 88.980 906.855 89.004 ;
    END
  END w0_wmask_in[170]
  PIN w0_wmask_in[171]
    DIRECTION INPUT ;
    USE SIGNAL ;
    SHAPE ABUTMENT ;
    PORT
      LAYER M4 ;
      RECT 906.783 91.092 906.855 91.116 ;
    END
  END w0_wmask_in[171]
  PIN w0_wmask_in[172]
    DIRECTION INPUT ;
    USE SIGNAL ;
    SHAPE ABUTMENT ;
    PORT
      LAYER M4 ;
      RECT 906.783 93.204 906.855 93.228 ;
    END
  END w0_wmask_in[172]
  PIN w0_wmask_in[173]
    DIRECTION INPUT ;
    USE SIGNAL ;
    SHAPE ABUTMENT ;
    PORT
      LAYER M4 ;
      RECT 906.783 95.316 906.855 95.340 ;
    END
  END w0_wmask_in[173]
  PIN w0_wmask_in[174]
    DIRECTION INPUT ;
    USE SIGNAL ;
    SHAPE ABUTMENT ;
    PORT
      LAYER M4 ;
      RECT 906.783 97.428 906.855 97.452 ;
    END
  END w0_wmask_in[174]
  PIN w0_wmask_in[175]
    DIRECTION INPUT ;
    USE SIGNAL ;
    SHAPE ABUTMENT ;
    PORT
      LAYER M4 ;
      RECT 906.783 99.540 906.855 99.564 ;
    END
  END w0_wmask_in[175]
  PIN w0_wmask_in[176]
    DIRECTION INPUT ;
    USE SIGNAL ;
    SHAPE ABUTMENT ;
    PORT
      LAYER M4 ;
      RECT 906.783 101.652 906.855 101.676 ;
    END
  END w0_wmask_in[176]
  PIN w0_wmask_in[177]
    DIRECTION INPUT ;
    USE SIGNAL ;
    SHAPE ABUTMENT ;
    PORT
      LAYER M4 ;
      RECT 906.783 103.764 906.855 103.788 ;
    END
  END w0_wmask_in[177]
  PIN w0_wmask_in[178]
    DIRECTION INPUT ;
    USE SIGNAL ;
    SHAPE ABUTMENT ;
    PORT
      LAYER M4 ;
      RECT 906.783 105.876 906.855 105.900 ;
    END
  END w0_wmask_in[178]
  PIN w0_wmask_in[179]
    DIRECTION INPUT ;
    USE SIGNAL ;
    SHAPE ABUTMENT ;
    PORT
      LAYER M4 ;
      RECT 906.783 107.988 906.855 108.012 ;
    END
  END w0_wmask_in[179]
  PIN w0_wmask_in[180]
    DIRECTION INPUT ;
    USE SIGNAL ;
    SHAPE ABUTMENT ;
    PORT
      LAYER M4 ;
      RECT 906.783 110.100 906.855 110.124 ;
    END
  END w0_wmask_in[180]
  PIN w0_wmask_in[181]
    DIRECTION INPUT ;
    USE SIGNAL ;
    SHAPE ABUTMENT ;
    PORT
      LAYER M4 ;
      RECT 906.783 112.212 906.855 112.236 ;
    END
  END w0_wmask_in[181]
  PIN w0_wmask_in[182]
    DIRECTION INPUT ;
    USE SIGNAL ;
    SHAPE ABUTMENT ;
    PORT
      LAYER M4 ;
      RECT 906.783 114.324 906.855 114.348 ;
    END
  END w0_wmask_in[182]
  PIN w0_wmask_in[183]
    DIRECTION INPUT ;
    USE SIGNAL ;
    SHAPE ABUTMENT ;
    PORT
      LAYER M4 ;
      RECT 906.783 116.436 906.855 116.460 ;
    END
  END w0_wmask_in[183]
  PIN w0_wmask_in[184]
    DIRECTION INPUT ;
    USE SIGNAL ;
    SHAPE ABUTMENT ;
    PORT
      LAYER M4 ;
      RECT 906.783 118.548 906.855 118.572 ;
    END
  END w0_wmask_in[184]
  PIN w0_wmask_in[185]
    DIRECTION INPUT ;
    USE SIGNAL ;
    SHAPE ABUTMENT ;
    PORT
      LAYER M4 ;
      RECT 906.783 120.660 906.855 120.684 ;
    END
  END w0_wmask_in[185]
  PIN w0_wmask_in[186]
    DIRECTION INPUT ;
    USE SIGNAL ;
    SHAPE ABUTMENT ;
    PORT
      LAYER M4 ;
      RECT 906.783 122.772 906.855 122.796 ;
    END
  END w0_wmask_in[186]
  PIN w0_wmask_in[187]
    DIRECTION INPUT ;
    USE SIGNAL ;
    SHAPE ABUTMENT ;
    PORT
      LAYER M4 ;
      RECT 906.783 124.884 906.855 124.908 ;
    END
  END w0_wmask_in[187]
  PIN w0_wmask_in[188]
    DIRECTION INPUT ;
    USE SIGNAL ;
    SHAPE ABUTMENT ;
    PORT
      LAYER M4 ;
      RECT 906.783 126.996 906.855 127.020 ;
    END
  END w0_wmask_in[188]
  PIN w0_wmask_in[189]
    DIRECTION INPUT ;
    USE SIGNAL ;
    SHAPE ABUTMENT ;
    PORT
      LAYER M4 ;
      RECT 906.783 129.108 906.855 129.132 ;
    END
  END w0_wmask_in[189]
  PIN w0_wmask_in[190]
    DIRECTION INPUT ;
    USE SIGNAL ;
    SHAPE ABUTMENT ;
    PORT
      LAYER M4 ;
      RECT 906.783 131.220 906.855 131.244 ;
    END
  END w0_wmask_in[190]
  PIN w0_wmask_in[191]
    DIRECTION INPUT ;
    USE SIGNAL ;
    SHAPE ABUTMENT ;
    PORT
      LAYER M4 ;
      RECT 906.783 133.332 906.855 133.356 ;
    END
  END w0_wmask_in[191]
  PIN w0_wmask_in[192]
    DIRECTION INPUT ;
    USE SIGNAL ;
    SHAPE ABUTMENT ;
    PORT
      LAYER M4 ;
      RECT 906.783 135.444 906.855 135.468 ;
    END
  END w0_wmask_in[192]
  PIN w0_wmask_in[193]
    DIRECTION INPUT ;
    USE SIGNAL ;
    SHAPE ABUTMENT ;
    PORT
      LAYER M4 ;
      RECT 906.783 137.556 906.855 137.580 ;
    END
  END w0_wmask_in[193]
  PIN w0_wmask_in[194]
    DIRECTION INPUT ;
    USE SIGNAL ;
    SHAPE ABUTMENT ;
    PORT
      LAYER M4 ;
      RECT 906.783 139.668 906.855 139.692 ;
    END
  END w0_wmask_in[194]
  PIN w0_wmask_in[195]
    DIRECTION INPUT ;
    USE SIGNAL ;
    SHAPE ABUTMENT ;
    PORT
      LAYER M4 ;
      RECT 906.783 141.780 906.855 141.804 ;
    END
  END w0_wmask_in[195]
  PIN w0_wmask_in[196]
    DIRECTION INPUT ;
    USE SIGNAL ;
    SHAPE ABUTMENT ;
    PORT
      LAYER M4 ;
      RECT 906.783 143.892 906.855 143.916 ;
    END
  END w0_wmask_in[196]
  PIN w0_wmask_in[197]
    DIRECTION INPUT ;
    USE SIGNAL ;
    SHAPE ABUTMENT ;
    PORT
      LAYER M4 ;
      RECT 906.783 146.004 906.855 146.028 ;
    END
  END w0_wmask_in[197]
  PIN w0_wmask_in[198]
    DIRECTION INPUT ;
    USE SIGNAL ;
    SHAPE ABUTMENT ;
    PORT
      LAYER M4 ;
      RECT 906.783 148.116 906.855 148.140 ;
    END
  END w0_wmask_in[198]
  PIN w0_wmask_in[199]
    DIRECTION INPUT ;
    USE SIGNAL ;
    SHAPE ABUTMENT ;
    PORT
      LAYER M4 ;
      RECT 906.783 150.228 906.855 150.252 ;
    END
  END w0_wmask_in[199]
  PIN w0_wmask_in[200]
    DIRECTION INPUT ;
    USE SIGNAL ;
    SHAPE ABUTMENT ;
    PORT
      LAYER M4 ;
      RECT 906.783 152.340 906.855 152.364 ;
    END
  END w0_wmask_in[200]
  PIN w0_wmask_in[201]
    DIRECTION INPUT ;
    USE SIGNAL ;
    SHAPE ABUTMENT ;
    PORT
      LAYER M4 ;
      RECT 906.783 154.452 906.855 154.476 ;
    END
  END w0_wmask_in[201]
  PIN w0_wmask_in[202]
    DIRECTION INPUT ;
    USE SIGNAL ;
    SHAPE ABUTMENT ;
    PORT
      LAYER M4 ;
      RECT 906.783 156.564 906.855 156.588 ;
    END
  END w0_wmask_in[202]
  PIN w0_wmask_in[203]
    DIRECTION INPUT ;
    USE SIGNAL ;
    SHAPE ABUTMENT ;
    PORT
      LAYER M4 ;
      RECT 906.783 158.676 906.855 158.700 ;
    END
  END w0_wmask_in[203]
  PIN w0_wmask_in[204]
    DIRECTION INPUT ;
    USE SIGNAL ;
    SHAPE ABUTMENT ;
    PORT
      LAYER M4 ;
      RECT 906.783 160.788 906.855 160.812 ;
    END
  END w0_wmask_in[204]
  PIN w0_wmask_in[205]
    DIRECTION INPUT ;
    USE SIGNAL ;
    SHAPE ABUTMENT ;
    PORT
      LAYER M4 ;
      RECT 906.783 162.900 906.855 162.924 ;
    END
  END w0_wmask_in[205]
  PIN w0_wmask_in[206]
    DIRECTION INPUT ;
    USE SIGNAL ;
    SHAPE ABUTMENT ;
    PORT
      LAYER M4 ;
      RECT 906.783 165.012 906.855 165.036 ;
    END
  END w0_wmask_in[206]
  PIN w0_wmask_in[207]
    DIRECTION INPUT ;
    USE SIGNAL ;
    SHAPE ABUTMENT ;
    PORT
      LAYER M4 ;
      RECT 906.783 167.124 906.855 167.148 ;
    END
  END w0_wmask_in[207]
  PIN w0_wmask_in[208]
    DIRECTION INPUT ;
    USE SIGNAL ;
    SHAPE ABUTMENT ;
    PORT
      LAYER M4 ;
      RECT 906.783 169.236 906.855 169.260 ;
    END
  END w0_wmask_in[208]
  PIN w0_wmask_in[209]
    DIRECTION INPUT ;
    USE SIGNAL ;
    SHAPE ABUTMENT ;
    PORT
      LAYER M4 ;
      RECT 906.783 171.348 906.855 171.372 ;
    END
  END w0_wmask_in[209]
  PIN w0_wmask_in[210]
    DIRECTION INPUT ;
    USE SIGNAL ;
    SHAPE ABUTMENT ;
    PORT
      LAYER M4 ;
      RECT 906.783 173.460 906.855 173.484 ;
    END
  END w0_wmask_in[210]
  PIN w0_wmask_in[211]
    DIRECTION INPUT ;
    USE SIGNAL ;
    SHAPE ABUTMENT ;
    PORT
      LAYER M4 ;
      RECT 906.783 175.572 906.855 175.596 ;
    END
  END w0_wmask_in[211]
  PIN w0_wmask_in[212]
    DIRECTION INPUT ;
    USE SIGNAL ;
    SHAPE ABUTMENT ;
    PORT
      LAYER M4 ;
      RECT 906.783 177.684 906.855 177.708 ;
    END
  END w0_wmask_in[212]
  PIN w0_wmask_in[213]
    DIRECTION INPUT ;
    USE SIGNAL ;
    SHAPE ABUTMENT ;
    PORT
      LAYER M4 ;
      RECT 906.783 179.796 906.855 179.820 ;
    END
  END w0_wmask_in[213]
  PIN w0_wmask_in[214]
    DIRECTION INPUT ;
    USE SIGNAL ;
    SHAPE ABUTMENT ;
    PORT
      LAYER M4 ;
      RECT 906.783 181.908 906.855 181.932 ;
    END
  END w0_wmask_in[214]
  PIN w0_wmask_in[215]
    DIRECTION INPUT ;
    USE SIGNAL ;
    SHAPE ABUTMENT ;
    PORT
      LAYER M4 ;
      RECT 906.783 184.020 906.855 184.044 ;
    END
  END w0_wmask_in[215]
  PIN w0_wmask_in[216]
    DIRECTION INPUT ;
    USE SIGNAL ;
    SHAPE ABUTMENT ;
    PORT
      LAYER M4 ;
      RECT 906.783 186.132 906.855 186.156 ;
    END
  END w0_wmask_in[216]
  PIN w0_wmask_in[217]
    DIRECTION INPUT ;
    USE SIGNAL ;
    SHAPE ABUTMENT ;
    PORT
      LAYER M4 ;
      RECT 906.783 188.244 906.855 188.268 ;
    END
  END w0_wmask_in[217]
  PIN w0_wmask_in[218]
    DIRECTION INPUT ;
    USE SIGNAL ;
    SHAPE ABUTMENT ;
    PORT
      LAYER M4 ;
      RECT 906.783 190.356 906.855 190.380 ;
    END
  END w0_wmask_in[218]
  PIN w0_wmask_in[219]
    DIRECTION INPUT ;
    USE SIGNAL ;
    SHAPE ABUTMENT ;
    PORT
      LAYER M4 ;
      RECT 906.783 192.468 906.855 192.492 ;
    END
  END w0_wmask_in[219]
  PIN w0_wmask_in[220]
    DIRECTION INPUT ;
    USE SIGNAL ;
    SHAPE ABUTMENT ;
    PORT
      LAYER M4 ;
      RECT 906.783 194.580 906.855 194.604 ;
    END
  END w0_wmask_in[220]
  PIN w0_wmask_in[221]
    DIRECTION INPUT ;
    USE SIGNAL ;
    SHAPE ABUTMENT ;
    PORT
      LAYER M4 ;
      RECT 906.783 196.692 906.855 196.716 ;
    END
  END w0_wmask_in[221]
  PIN w0_wmask_in[222]
    DIRECTION INPUT ;
    USE SIGNAL ;
    SHAPE ABUTMENT ;
    PORT
      LAYER M4 ;
      RECT 906.783 198.804 906.855 198.828 ;
    END
  END w0_wmask_in[222]
  PIN w0_wmask_in[223]
    DIRECTION INPUT ;
    USE SIGNAL ;
    SHAPE ABUTMENT ;
    PORT
      LAYER M4 ;
      RECT 906.783 200.916 906.855 200.940 ;
    END
  END w0_wmask_in[223]
  PIN w0_wmask_in[224]
    DIRECTION INPUT ;
    USE SIGNAL ;
    SHAPE ABUTMENT ;
    PORT
      LAYER M4 ;
      RECT 906.783 203.028 906.855 203.052 ;
    END
  END w0_wmask_in[224]
  PIN w0_wmask_in[225]
    DIRECTION INPUT ;
    USE SIGNAL ;
    SHAPE ABUTMENT ;
    PORT
      LAYER M4 ;
      RECT 906.783 205.140 906.855 205.164 ;
    END
  END w0_wmask_in[225]
  PIN w0_wmask_in[226]
    DIRECTION INPUT ;
    USE SIGNAL ;
    SHAPE ABUTMENT ;
    PORT
      LAYER M4 ;
      RECT 906.783 207.252 906.855 207.276 ;
    END
  END w0_wmask_in[226]
  PIN w0_wmask_in[227]
    DIRECTION INPUT ;
    USE SIGNAL ;
    SHAPE ABUTMENT ;
    PORT
      LAYER M4 ;
      RECT 906.783 209.364 906.855 209.388 ;
    END
  END w0_wmask_in[227]
  PIN w0_wmask_in[228]
    DIRECTION INPUT ;
    USE SIGNAL ;
    SHAPE ABUTMENT ;
    PORT
      LAYER M4 ;
      RECT 906.783 211.476 906.855 211.500 ;
    END
  END w0_wmask_in[228]
  PIN w0_wmask_in[229]
    DIRECTION INPUT ;
    USE SIGNAL ;
    SHAPE ABUTMENT ;
    PORT
      LAYER M4 ;
      RECT 906.783 213.588 906.855 213.612 ;
    END
  END w0_wmask_in[229]
  PIN w0_wmask_in[230]
    DIRECTION INPUT ;
    USE SIGNAL ;
    SHAPE ABUTMENT ;
    PORT
      LAYER M4 ;
      RECT 906.783 215.700 906.855 215.724 ;
    END
  END w0_wmask_in[230]
  PIN w0_wmask_in[231]
    DIRECTION INPUT ;
    USE SIGNAL ;
    SHAPE ABUTMENT ;
    PORT
      LAYER M4 ;
      RECT 906.783 217.812 906.855 217.836 ;
    END
  END w0_wmask_in[231]
  PIN w0_wmask_in[232]
    DIRECTION INPUT ;
    USE SIGNAL ;
    SHAPE ABUTMENT ;
    PORT
      LAYER M4 ;
      RECT 906.783 219.924 906.855 219.948 ;
    END
  END w0_wmask_in[232]
  PIN w0_wmask_in[233]
    DIRECTION INPUT ;
    USE SIGNAL ;
    SHAPE ABUTMENT ;
    PORT
      LAYER M4 ;
      RECT 906.783 222.036 906.855 222.060 ;
    END
  END w0_wmask_in[233]
  PIN w0_wmask_in[234]
    DIRECTION INPUT ;
    USE SIGNAL ;
    SHAPE ABUTMENT ;
    PORT
      LAYER M4 ;
      RECT 906.783 224.148 906.855 224.172 ;
    END
  END w0_wmask_in[234]
  PIN w0_wmask_in[235]
    DIRECTION INPUT ;
    USE SIGNAL ;
    SHAPE ABUTMENT ;
    PORT
      LAYER M4 ;
      RECT 906.783 226.260 906.855 226.284 ;
    END
  END w0_wmask_in[235]
  PIN w0_wmask_in[236]
    DIRECTION INPUT ;
    USE SIGNAL ;
    SHAPE ABUTMENT ;
    PORT
      LAYER M4 ;
      RECT 906.783 228.372 906.855 228.396 ;
    END
  END w0_wmask_in[236]
  PIN w0_wmask_in[237]
    DIRECTION INPUT ;
    USE SIGNAL ;
    SHAPE ABUTMENT ;
    PORT
      LAYER M4 ;
      RECT 906.783 230.484 906.855 230.508 ;
    END
  END w0_wmask_in[237]
  PIN w0_wmask_in[238]
    DIRECTION INPUT ;
    USE SIGNAL ;
    SHAPE ABUTMENT ;
    PORT
      LAYER M4 ;
      RECT 906.783 232.596 906.855 232.620 ;
    END
  END w0_wmask_in[238]
  PIN w0_wmask_in[239]
    DIRECTION INPUT ;
    USE SIGNAL ;
    SHAPE ABUTMENT ;
    PORT
      LAYER M4 ;
      RECT 906.783 234.708 906.855 234.732 ;
    END
  END w0_wmask_in[239]
  PIN w0_wmask_in[240]
    DIRECTION INPUT ;
    USE SIGNAL ;
    SHAPE ABUTMENT ;
    PORT
      LAYER M4 ;
      RECT 906.783 236.820 906.855 236.844 ;
    END
  END w0_wmask_in[240]
  PIN w0_wmask_in[241]
    DIRECTION INPUT ;
    USE SIGNAL ;
    SHAPE ABUTMENT ;
    PORT
      LAYER M4 ;
      RECT 906.783 238.932 906.855 238.956 ;
    END
  END w0_wmask_in[241]
  PIN w0_wmask_in[242]
    DIRECTION INPUT ;
    USE SIGNAL ;
    SHAPE ABUTMENT ;
    PORT
      LAYER M4 ;
      RECT 906.783 241.044 906.855 241.068 ;
    END
  END w0_wmask_in[242]
  PIN w0_wmask_in[243]
    DIRECTION INPUT ;
    USE SIGNAL ;
    SHAPE ABUTMENT ;
    PORT
      LAYER M4 ;
      RECT 906.783 243.156 906.855 243.180 ;
    END
  END w0_wmask_in[243]
  PIN w0_wmask_in[244]
    DIRECTION INPUT ;
    USE SIGNAL ;
    SHAPE ABUTMENT ;
    PORT
      LAYER M4 ;
      RECT 906.783 245.268 906.855 245.292 ;
    END
  END w0_wmask_in[244]
  PIN w0_wmask_in[245]
    DIRECTION INPUT ;
    USE SIGNAL ;
    SHAPE ABUTMENT ;
    PORT
      LAYER M4 ;
      RECT 906.783 247.380 906.855 247.404 ;
    END
  END w0_wmask_in[245]
  PIN w0_wmask_in[246]
    DIRECTION INPUT ;
    USE SIGNAL ;
    SHAPE ABUTMENT ;
    PORT
      LAYER M4 ;
      RECT 906.783 249.492 906.855 249.516 ;
    END
  END w0_wmask_in[246]
  PIN w0_wmask_in[247]
    DIRECTION INPUT ;
    USE SIGNAL ;
    SHAPE ABUTMENT ;
    PORT
      LAYER M4 ;
      RECT 906.783 251.604 906.855 251.628 ;
    END
  END w0_wmask_in[247]
  PIN w0_wmask_in[248]
    DIRECTION INPUT ;
    USE SIGNAL ;
    SHAPE ABUTMENT ;
    PORT
      LAYER M4 ;
      RECT 906.783 253.716 906.855 253.740 ;
    END
  END w0_wmask_in[248]
  PIN w0_wmask_in[249]
    DIRECTION INPUT ;
    USE SIGNAL ;
    SHAPE ABUTMENT ;
    PORT
      LAYER M4 ;
      RECT 906.783 255.828 906.855 255.852 ;
    END
  END w0_wmask_in[249]
  PIN w0_wmask_in[250]
    DIRECTION INPUT ;
    USE SIGNAL ;
    SHAPE ABUTMENT ;
    PORT
      LAYER M4 ;
      RECT 906.783 257.940 906.855 257.964 ;
    END
  END w0_wmask_in[250]
  PIN w0_wmask_in[251]
    DIRECTION INPUT ;
    USE SIGNAL ;
    SHAPE ABUTMENT ;
    PORT
      LAYER M4 ;
      RECT 906.783 260.052 906.855 260.076 ;
    END
  END w0_wmask_in[251]
  PIN w0_wmask_in[252]
    DIRECTION INPUT ;
    USE SIGNAL ;
    SHAPE ABUTMENT ;
    PORT
      LAYER M4 ;
      RECT 906.783 262.164 906.855 262.188 ;
    END
  END w0_wmask_in[252]
  PIN w0_wmask_in[253]
    DIRECTION INPUT ;
    USE SIGNAL ;
    SHAPE ABUTMENT ;
    PORT
      LAYER M4 ;
      RECT 906.783 264.276 906.855 264.300 ;
    END
  END w0_wmask_in[253]
  PIN w0_wmask_in[254]
    DIRECTION INPUT ;
    USE SIGNAL ;
    SHAPE ABUTMENT ;
    PORT
      LAYER M4 ;
      RECT 906.783 266.388 906.855 266.412 ;
    END
  END w0_wmask_in[254]
  PIN w0_wmask_in[255]
    DIRECTION INPUT ;
    USE SIGNAL ;
    SHAPE ABUTMENT ;
    PORT
      LAYER M4 ;
      RECT 906.783 268.500 906.855 268.524 ;
    END
  END w0_wmask_in[255]
  PIN w0_wmask_in[256]
    DIRECTION INPUT ;
    USE SIGNAL ;
    SHAPE ABUTMENT ;
    PORT
      LAYER M3 ;
      RECT 0.207 566.730 0.225 566.784 ;
    END
  END w0_wmask_in[256]
  PIN w0_wmask_in[257]
    DIRECTION INPUT ;
    USE SIGNAL ;
    SHAPE ABUTMENT ;
    PORT
      LAYER M3 ;
      RECT 1.935 566.730 1.953 566.784 ;
    END
  END w0_wmask_in[257]
  PIN w0_wmask_in[258]
    DIRECTION INPUT ;
    USE SIGNAL ;
    SHAPE ABUTMENT ;
    PORT
      LAYER M3 ;
      RECT 3.663 566.730 3.681 566.784 ;
    END
  END w0_wmask_in[258]
  PIN w0_wmask_in[259]
    DIRECTION INPUT ;
    USE SIGNAL ;
    SHAPE ABUTMENT ;
    PORT
      LAYER M3 ;
      RECT 5.391 566.730 5.409 566.784 ;
    END
  END w0_wmask_in[259]
  PIN w0_wmask_in[260]
    DIRECTION INPUT ;
    USE SIGNAL ;
    SHAPE ABUTMENT ;
    PORT
      LAYER M3 ;
      RECT 7.119 566.730 7.137 566.784 ;
    END
  END w0_wmask_in[260]
  PIN w0_wmask_in[261]
    DIRECTION INPUT ;
    USE SIGNAL ;
    SHAPE ABUTMENT ;
    PORT
      LAYER M3 ;
      RECT 8.847 566.730 8.865 566.784 ;
    END
  END w0_wmask_in[261]
  PIN w0_wmask_in[262]
    DIRECTION INPUT ;
    USE SIGNAL ;
    SHAPE ABUTMENT ;
    PORT
      LAYER M3 ;
      RECT 10.575 566.730 10.593 566.784 ;
    END
  END w0_wmask_in[262]
  PIN w0_wmask_in[263]
    DIRECTION INPUT ;
    USE SIGNAL ;
    SHAPE ABUTMENT ;
    PORT
      LAYER M3 ;
      RECT 12.303 566.730 12.321 566.784 ;
    END
  END w0_wmask_in[263]
  PIN w0_wmask_in[264]
    DIRECTION INPUT ;
    USE SIGNAL ;
    SHAPE ABUTMENT ;
    PORT
      LAYER M3 ;
      RECT 14.031 566.730 14.049 566.784 ;
    END
  END w0_wmask_in[264]
  PIN w0_wmask_in[265]
    DIRECTION INPUT ;
    USE SIGNAL ;
    SHAPE ABUTMENT ;
    PORT
      LAYER M3 ;
      RECT 15.759 566.730 15.777 566.784 ;
    END
  END w0_wmask_in[265]
  PIN w0_wmask_in[266]
    DIRECTION INPUT ;
    USE SIGNAL ;
    SHAPE ABUTMENT ;
    PORT
      LAYER M3 ;
      RECT 17.487 566.730 17.505 566.784 ;
    END
  END w0_wmask_in[266]
  PIN w0_wmask_in[267]
    DIRECTION INPUT ;
    USE SIGNAL ;
    SHAPE ABUTMENT ;
    PORT
      LAYER M3 ;
      RECT 19.215 566.730 19.233 566.784 ;
    END
  END w0_wmask_in[267]
  PIN w0_wmask_in[268]
    DIRECTION INPUT ;
    USE SIGNAL ;
    SHAPE ABUTMENT ;
    PORT
      LAYER M3 ;
      RECT 20.943 566.730 20.961 566.784 ;
    END
  END w0_wmask_in[268]
  PIN w0_wmask_in[269]
    DIRECTION INPUT ;
    USE SIGNAL ;
    SHAPE ABUTMENT ;
    PORT
      LAYER M3 ;
      RECT 22.671 566.730 22.689 566.784 ;
    END
  END w0_wmask_in[269]
  PIN w0_wmask_in[270]
    DIRECTION INPUT ;
    USE SIGNAL ;
    SHAPE ABUTMENT ;
    PORT
      LAYER M3 ;
      RECT 24.399 566.730 24.417 566.784 ;
    END
  END w0_wmask_in[270]
  PIN w0_wmask_in[271]
    DIRECTION INPUT ;
    USE SIGNAL ;
    SHAPE ABUTMENT ;
    PORT
      LAYER M3 ;
      RECT 26.127 566.730 26.145 566.784 ;
    END
  END w0_wmask_in[271]
  PIN w0_wmask_in[272]
    DIRECTION INPUT ;
    USE SIGNAL ;
    SHAPE ABUTMENT ;
    PORT
      LAYER M3 ;
      RECT 27.855 566.730 27.873 566.784 ;
    END
  END w0_wmask_in[272]
  PIN w0_wmask_in[273]
    DIRECTION INPUT ;
    USE SIGNAL ;
    SHAPE ABUTMENT ;
    PORT
      LAYER M3 ;
      RECT 29.583 566.730 29.601 566.784 ;
    END
  END w0_wmask_in[273]
  PIN w0_wmask_in[274]
    DIRECTION INPUT ;
    USE SIGNAL ;
    SHAPE ABUTMENT ;
    PORT
      LAYER M3 ;
      RECT 31.311 566.730 31.329 566.784 ;
    END
  END w0_wmask_in[274]
  PIN w0_wmask_in[275]
    DIRECTION INPUT ;
    USE SIGNAL ;
    SHAPE ABUTMENT ;
    PORT
      LAYER M3 ;
      RECT 33.039 566.730 33.057 566.784 ;
    END
  END w0_wmask_in[275]
  PIN w0_wmask_in[276]
    DIRECTION INPUT ;
    USE SIGNAL ;
    SHAPE ABUTMENT ;
    PORT
      LAYER M3 ;
      RECT 34.767 566.730 34.785 566.784 ;
    END
  END w0_wmask_in[276]
  PIN w0_wmask_in[277]
    DIRECTION INPUT ;
    USE SIGNAL ;
    SHAPE ABUTMENT ;
    PORT
      LAYER M3 ;
      RECT 36.495 566.730 36.513 566.784 ;
    END
  END w0_wmask_in[277]
  PIN w0_wmask_in[278]
    DIRECTION INPUT ;
    USE SIGNAL ;
    SHAPE ABUTMENT ;
    PORT
      LAYER M3 ;
      RECT 38.223 566.730 38.241 566.784 ;
    END
  END w0_wmask_in[278]
  PIN w0_wmask_in[279]
    DIRECTION INPUT ;
    USE SIGNAL ;
    SHAPE ABUTMENT ;
    PORT
      LAYER M3 ;
      RECT 39.951 566.730 39.969 566.784 ;
    END
  END w0_wmask_in[279]
  PIN w0_wmask_in[280]
    DIRECTION INPUT ;
    USE SIGNAL ;
    SHAPE ABUTMENT ;
    PORT
      LAYER M3 ;
      RECT 41.679 566.730 41.697 566.784 ;
    END
  END w0_wmask_in[280]
  PIN w0_wmask_in[281]
    DIRECTION INPUT ;
    USE SIGNAL ;
    SHAPE ABUTMENT ;
    PORT
      LAYER M3 ;
      RECT 43.407 566.730 43.425 566.784 ;
    END
  END w0_wmask_in[281]
  PIN w0_wmask_in[282]
    DIRECTION INPUT ;
    USE SIGNAL ;
    SHAPE ABUTMENT ;
    PORT
      LAYER M3 ;
      RECT 45.135 566.730 45.153 566.784 ;
    END
  END w0_wmask_in[282]
  PIN w0_wmask_in[283]
    DIRECTION INPUT ;
    USE SIGNAL ;
    SHAPE ABUTMENT ;
    PORT
      LAYER M3 ;
      RECT 46.863 566.730 46.881 566.784 ;
    END
  END w0_wmask_in[283]
  PIN w0_wmask_in[284]
    DIRECTION INPUT ;
    USE SIGNAL ;
    SHAPE ABUTMENT ;
    PORT
      LAYER M3 ;
      RECT 48.591 566.730 48.609 566.784 ;
    END
  END w0_wmask_in[284]
  PIN w0_wmask_in[285]
    DIRECTION INPUT ;
    USE SIGNAL ;
    SHAPE ABUTMENT ;
    PORT
      LAYER M3 ;
      RECT 50.319 566.730 50.337 566.784 ;
    END
  END w0_wmask_in[285]
  PIN w0_wmask_in[286]
    DIRECTION INPUT ;
    USE SIGNAL ;
    SHAPE ABUTMENT ;
    PORT
      LAYER M3 ;
      RECT 52.047 566.730 52.065 566.784 ;
    END
  END w0_wmask_in[286]
  PIN w0_wmask_in[287]
    DIRECTION INPUT ;
    USE SIGNAL ;
    SHAPE ABUTMENT ;
    PORT
      LAYER M3 ;
      RECT 53.775 566.730 53.793 566.784 ;
    END
  END w0_wmask_in[287]
  PIN w0_wmask_in[288]
    DIRECTION INPUT ;
    USE SIGNAL ;
    SHAPE ABUTMENT ;
    PORT
      LAYER M3 ;
      RECT 55.503 566.730 55.521 566.784 ;
    END
  END w0_wmask_in[288]
  PIN w0_wmask_in[289]
    DIRECTION INPUT ;
    USE SIGNAL ;
    SHAPE ABUTMENT ;
    PORT
      LAYER M3 ;
      RECT 57.231 566.730 57.249 566.784 ;
    END
  END w0_wmask_in[289]
  PIN w0_wmask_in[290]
    DIRECTION INPUT ;
    USE SIGNAL ;
    SHAPE ABUTMENT ;
    PORT
      LAYER M3 ;
      RECT 58.959 566.730 58.977 566.784 ;
    END
  END w0_wmask_in[290]
  PIN w0_wmask_in[291]
    DIRECTION INPUT ;
    USE SIGNAL ;
    SHAPE ABUTMENT ;
    PORT
      LAYER M3 ;
      RECT 60.687 566.730 60.705 566.784 ;
    END
  END w0_wmask_in[291]
  PIN w0_wmask_in[292]
    DIRECTION INPUT ;
    USE SIGNAL ;
    SHAPE ABUTMENT ;
    PORT
      LAYER M3 ;
      RECT 62.415 566.730 62.433 566.784 ;
    END
  END w0_wmask_in[292]
  PIN w0_wmask_in[293]
    DIRECTION INPUT ;
    USE SIGNAL ;
    SHAPE ABUTMENT ;
    PORT
      LAYER M3 ;
      RECT 64.143 566.730 64.161 566.784 ;
    END
  END w0_wmask_in[293]
  PIN w0_wmask_in[294]
    DIRECTION INPUT ;
    USE SIGNAL ;
    SHAPE ABUTMENT ;
    PORT
      LAYER M3 ;
      RECT 65.871 566.730 65.889 566.784 ;
    END
  END w0_wmask_in[294]
  PIN w0_wmask_in[295]
    DIRECTION INPUT ;
    USE SIGNAL ;
    SHAPE ABUTMENT ;
    PORT
      LAYER M3 ;
      RECT 67.599 566.730 67.617 566.784 ;
    END
  END w0_wmask_in[295]
  PIN w0_wmask_in[296]
    DIRECTION INPUT ;
    USE SIGNAL ;
    SHAPE ABUTMENT ;
    PORT
      LAYER M3 ;
      RECT 69.327 566.730 69.345 566.784 ;
    END
  END w0_wmask_in[296]
  PIN w0_wmask_in[297]
    DIRECTION INPUT ;
    USE SIGNAL ;
    SHAPE ABUTMENT ;
    PORT
      LAYER M3 ;
      RECT 71.055 566.730 71.073 566.784 ;
    END
  END w0_wmask_in[297]
  PIN w0_wmask_in[298]
    DIRECTION INPUT ;
    USE SIGNAL ;
    SHAPE ABUTMENT ;
    PORT
      LAYER M3 ;
      RECT 72.783 566.730 72.801 566.784 ;
    END
  END w0_wmask_in[298]
  PIN w0_wmask_in[299]
    DIRECTION INPUT ;
    USE SIGNAL ;
    SHAPE ABUTMENT ;
    PORT
      LAYER M3 ;
      RECT 74.511 566.730 74.529 566.784 ;
    END
  END w0_wmask_in[299]
  PIN w0_wmask_in[300]
    DIRECTION INPUT ;
    USE SIGNAL ;
    SHAPE ABUTMENT ;
    PORT
      LAYER M3 ;
      RECT 76.239 566.730 76.257 566.784 ;
    END
  END w0_wmask_in[300]
  PIN w0_wmask_in[301]
    DIRECTION INPUT ;
    USE SIGNAL ;
    SHAPE ABUTMENT ;
    PORT
      LAYER M3 ;
      RECT 77.967 566.730 77.985 566.784 ;
    END
  END w0_wmask_in[301]
  PIN w0_wmask_in[302]
    DIRECTION INPUT ;
    USE SIGNAL ;
    SHAPE ABUTMENT ;
    PORT
      LAYER M3 ;
      RECT 79.695 566.730 79.713 566.784 ;
    END
  END w0_wmask_in[302]
  PIN w0_wmask_in[303]
    DIRECTION INPUT ;
    USE SIGNAL ;
    SHAPE ABUTMENT ;
    PORT
      LAYER M3 ;
      RECT 81.423 566.730 81.441 566.784 ;
    END
  END w0_wmask_in[303]
  PIN w0_wmask_in[304]
    DIRECTION INPUT ;
    USE SIGNAL ;
    SHAPE ABUTMENT ;
    PORT
      LAYER M3 ;
      RECT 83.151 566.730 83.169 566.784 ;
    END
  END w0_wmask_in[304]
  PIN w0_wmask_in[305]
    DIRECTION INPUT ;
    USE SIGNAL ;
    SHAPE ABUTMENT ;
    PORT
      LAYER M3 ;
      RECT 84.879 566.730 84.897 566.784 ;
    END
  END w0_wmask_in[305]
  PIN w0_wmask_in[306]
    DIRECTION INPUT ;
    USE SIGNAL ;
    SHAPE ABUTMENT ;
    PORT
      LAYER M3 ;
      RECT 86.607 566.730 86.625 566.784 ;
    END
  END w0_wmask_in[306]
  PIN w0_wmask_in[307]
    DIRECTION INPUT ;
    USE SIGNAL ;
    SHAPE ABUTMENT ;
    PORT
      LAYER M3 ;
      RECT 88.335 566.730 88.353 566.784 ;
    END
  END w0_wmask_in[307]
  PIN w0_wmask_in[308]
    DIRECTION INPUT ;
    USE SIGNAL ;
    SHAPE ABUTMENT ;
    PORT
      LAYER M3 ;
      RECT 90.063 566.730 90.081 566.784 ;
    END
  END w0_wmask_in[308]
  PIN w0_wmask_in[309]
    DIRECTION INPUT ;
    USE SIGNAL ;
    SHAPE ABUTMENT ;
    PORT
      LAYER M3 ;
      RECT 91.791 566.730 91.809 566.784 ;
    END
  END w0_wmask_in[309]
  PIN w0_wmask_in[310]
    DIRECTION INPUT ;
    USE SIGNAL ;
    SHAPE ABUTMENT ;
    PORT
      LAYER M3 ;
      RECT 93.519 566.730 93.537 566.784 ;
    END
  END w0_wmask_in[310]
  PIN w0_wmask_in[311]
    DIRECTION INPUT ;
    USE SIGNAL ;
    SHAPE ABUTMENT ;
    PORT
      LAYER M3 ;
      RECT 95.247 566.730 95.265 566.784 ;
    END
  END w0_wmask_in[311]
  PIN w0_wmask_in[312]
    DIRECTION INPUT ;
    USE SIGNAL ;
    SHAPE ABUTMENT ;
    PORT
      LAYER M3 ;
      RECT 96.975 566.730 96.993 566.784 ;
    END
  END w0_wmask_in[312]
  PIN w0_wmask_in[313]
    DIRECTION INPUT ;
    USE SIGNAL ;
    SHAPE ABUTMENT ;
    PORT
      LAYER M3 ;
      RECT 98.703 566.730 98.721 566.784 ;
    END
  END w0_wmask_in[313]
  PIN w0_wmask_in[314]
    DIRECTION INPUT ;
    USE SIGNAL ;
    SHAPE ABUTMENT ;
    PORT
      LAYER M3 ;
      RECT 100.431 566.730 100.449 566.784 ;
    END
  END w0_wmask_in[314]
  PIN w0_wmask_in[315]
    DIRECTION INPUT ;
    USE SIGNAL ;
    SHAPE ABUTMENT ;
    PORT
      LAYER M3 ;
      RECT 102.159 566.730 102.177 566.784 ;
    END
  END w0_wmask_in[315]
  PIN w0_wmask_in[316]
    DIRECTION INPUT ;
    USE SIGNAL ;
    SHAPE ABUTMENT ;
    PORT
      LAYER M3 ;
      RECT 103.887 566.730 103.905 566.784 ;
    END
  END w0_wmask_in[316]
  PIN w0_wmask_in[317]
    DIRECTION INPUT ;
    USE SIGNAL ;
    SHAPE ABUTMENT ;
    PORT
      LAYER M3 ;
      RECT 105.615 566.730 105.633 566.784 ;
    END
  END w0_wmask_in[317]
  PIN w0_wmask_in[318]
    DIRECTION INPUT ;
    USE SIGNAL ;
    SHAPE ABUTMENT ;
    PORT
      LAYER M3 ;
      RECT 107.343 566.730 107.361 566.784 ;
    END
  END w0_wmask_in[318]
  PIN w0_wmask_in[319]
    DIRECTION INPUT ;
    USE SIGNAL ;
    SHAPE ABUTMENT ;
    PORT
      LAYER M3 ;
      RECT 109.071 566.730 109.089 566.784 ;
    END
  END w0_wmask_in[319]
  PIN w0_wmask_in[320]
    DIRECTION INPUT ;
    USE SIGNAL ;
    SHAPE ABUTMENT ;
    PORT
      LAYER M3 ;
      RECT 110.799 566.730 110.817 566.784 ;
    END
  END w0_wmask_in[320]
  PIN w0_wmask_in[321]
    DIRECTION INPUT ;
    USE SIGNAL ;
    SHAPE ABUTMENT ;
    PORT
      LAYER M3 ;
      RECT 112.527 566.730 112.545 566.784 ;
    END
  END w0_wmask_in[321]
  PIN w0_wmask_in[322]
    DIRECTION INPUT ;
    USE SIGNAL ;
    SHAPE ABUTMENT ;
    PORT
      LAYER M3 ;
      RECT 114.255 566.730 114.273 566.784 ;
    END
  END w0_wmask_in[322]
  PIN w0_wmask_in[323]
    DIRECTION INPUT ;
    USE SIGNAL ;
    SHAPE ABUTMENT ;
    PORT
      LAYER M3 ;
      RECT 115.983 566.730 116.001 566.784 ;
    END
  END w0_wmask_in[323]
  PIN w0_wmask_in[324]
    DIRECTION INPUT ;
    USE SIGNAL ;
    SHAPE ABUTMENT ;
    PORT
      LAYER M3 ;
      RECT 117.711 566.730 117.729 566.784 ;
    END
  END w0_wmask_in[324]
  PIN w0_wmask_in[325]
    DIRECTION INPUT ;
    USE SIGNAL ;
    SHAPE ABUTMENT ;
    PORT
      LAYER M3 ;
      RECT 119.439 566.730 119.457 566.784 ;
    END
  END w0_wmask_in[325]
  PIN w0_wmask_in[326]
    DIRECTION INPUT ;
    USE SIGNAL ;
    SHAPE ABUTMENT ;
    PORT
      LAYER M3 ;
      RECT 121.167 566.730 121.185 566.784 ;
    END
  END w0_wmask_in[326]
  PIN w0_wmask_in[327]
    DIRECTION INPUT ;
    USE SIGNAL ;
    SHAPE ABUTMENT ;
    PORT
      LAYER M3 ;
      RECT 122.895 566.730 122.913 566.784 ;
    END
  END w0_wmask_in[327]
  PIN w0_wmask_in[328]
    DIRECTION INPUT ;
    USE SIGNAL ;
    SHAPE ABUTMENT ;
    PORT
      LAYER M3 ;
      RECT 124.623 566.730 124.641 566.784 ;
    END
  END w0_wmask_in[328]
  PIN w0_wmask_in[329]
    DIRECTION INPUT ;
    USE SIGNAL ;
    SHAPE ABUTMENT ;
    PORT
      LAYER M3 ;
      RECT 126.351 566.730 126.369 566.784 ;
    END
  END w0_wmask_in[329]
  PIN w0_wmask_in[330]
    DIRECTION INPUT ;
    USE SIGNAL ;
    SHAPE ABUTMENT ;
    PORT
      LAYER M3 ;
      RECT 128.079 566.730 128.097 566.784 ;
    END
  END w0_wmask_in[330]
  PIN w0_wmask_in[331]
    DIRECTION INPUT ;
    USE SIGNAL ;
    SHAPE ABUTMENT ;
    PORT
      LAYER M3 ;
      RECT 129.807 566.730 129.825 566.784 ;
    END
  END w0_wmask_in[331]
  PIN w0_wmask_in[332]
    DIRECTION INPUT ;
    USE SIGNAL ;
    SHAPE ABUTMENT ;
    PORT
      LAYER M3 ;
      RECT 131.535 566.730 131.553 566.784 ;
    END
  END w0_wmask_in[332]
  PIN w0_wmask_in[333]
    DIRECTION INPUT ;
    USE SIGNAL ;
    SHAPE ABUTMENT ;
    PORT
      LAYER M3 ;
      RECT 133.263 566.730 133.281 566.784 ;
    END
  END w0_wmask_in[333]
  PIN w0_wmask_in[334]
    DIRECTION INPUT ;
    USE SIGNAL ;
    SHAPE ABUTMENT ;
    PORT
      LAYER M3 ;
      RECT 134.991 566.730 135.009 566.784 ;
    END
  END w0_wmask_in[334]
  PIN w0_wmask_in[335]
    DIRECTION INPUT ;
    USE SIGNAL ;
    SHAPE ABUTMENT ;
    PORT
      LAYER M3 ;
      RECT 136.719 566.730 136.737 566.784 ;
    END
  END w0_wmask_in[335]
  PIN w0_wmask_in[336]
    DIRECTION INPUT ;
    USE SIGNAL ;
    SHAPE ABUTMENT ;
    PORT
      LAYER M3 ;
      RECT 138.447 566.730 138.465 566.784 ;
    END
  END w0_wmask_in[336]
  PIN w0_wmask_in[337]
    DIRECTION INPUT ;
    USE SIGNAL ;
    SHAPE ABUTMENT ;
    PORT
      LAYER M3 ;
      RECT 140.175 566.730 140.193 566.784 ;
    END
  END w0_wmask_in[337]
  PIN w0_wmask_in[338]
    DIRECTION INPUT ;
    USE SIGNAL ;
    SHAPE ABUTMENT ;
    PORT
      LAYER M3 ;
      RECT 141.903 566.730 141.921 566.784 ;
    END
  END w0_wmask_in[338]
  PIN w0_wmask_in[339]
    DIRECTION INPUT ;
    USE SIGNAL ;
    SHAPE ABUTMENT ;
    PORT
      LAYER M3 ;
      RECT 143.631 566.730 143.649 566.784 ;
    END
  END w0_wmask_in[339]
  PIN w0_wmask_in[340]
    DIRECTION INPUT ;
    USE SIGNAL ;
    SHAPE ABUTMENT ;
    PORT
      LAYER M3 ;
      RECT 145.359 566.730 145.377 566.784 ;
    END
  END w0_wmask_in[340]
  PIN w0_wmask_in[341]
    DIRECTION INPUT ;
    USE SIGNAL ;
    SHAPE ABUTMENT ;
    PORT
      LAYER M3 ;
      RECT 147.087 566.730 147.105 566.784 ;
    END
  END w0_wmask_in[341]
  PIN w0_wmask_in[342]
    DIRECTION INPUT ;
    USE SIGNAL ;
    SHAPE ABUTMENT ;
    PORT
      LAYER M3 ;
      RECT 148.815 566.730 148.833 566.784 ;
    END
  END w0_wmask_in[342]
  PIN w0_wmask_in[343]
    DIRECTION INPUT ;
    USE SIGNAL ;
    SHAPE ABUTMENT ;
    PORT
      LAYER M3 ;
      RECT 150.543 566.730 150.561 566.784 ;
    END
  END w0_wmask_in[343]
  PIN w0_wmask_in[344]
    DIRECTION INPUT ;
    USE SIGNAL ;
    SHAPE ABUTMENT ;
    PORT
      LAYER M3 ;
      RECT 152.271 566.730 152.289 566.784 ;
    END
  END w0_wmask_in[344]
  PIN w0_wmask_in[345]
    DIRECTION INPUT ;
    USE SIGNAL ;
    SHAPE ABUTMENT ;
    PORT
      LAYER M3 ;
      RECT 153.999 566.730 154.017 566.784 ;
    END
  END w0_wmask_in[345]
  PIN w0_wmask_in[346]
    DIRECTION INPUT ;
    USE SIGNAL ;
    SHAPE ABUTMENT ;
    PORT
      LAYER M3 ;
      RECT 155.727 566.730 155.745 566.784 ;
    END
  END w0_wmask_in[346]
  PIN w0_wmask_in[347]
    DIRECTION INPUT ;
    USE SIGNAL ;
    SHAPE ABUTMENT ;
    PORT
      LAYER M3 ;
      RECT 157.455 566.730 157.473 566.784 ;
    END
  END w0_wmask_in[347]
  PIN w0_wmask_in[348]
    DIRECTION INPUT ;
    USE SIGNAL ;
    SHAPE ABUTMENT ;
    PORT
      LAYER M3 ;
      RECT 159.183 566.730 159.201 566.784 ;
    END
  END w0_wmask_in[348]
  PIN w0_wmask_in[349]
    DIRECTION INPUT ;
    USE SIGNAL ;
    SHAPE ABUTMENT ;
    PORT
      LAYER M3 ;
      RECT 160.911 566.730 160.929 566.784 ;
    END
  END w0_wmask_in[349]
  PIN w0_wmask_in[350]
    DIRECTION INPUT ;
    USE SIGNAL ;
    SHAPE ABUTMENT ;
    PORT
      LAYER M3 ;
      RECT 162.639 566.730 162.657 566.784 ;
    END
  END w0_wmask_in[350]
  PIN w0_wmask_in[351]
    DIRECTION INPUT ;
    USE SIGNAL ;
    SHAPE ABUTMENT ;
    PORT
      LAYER M3 ;
      RECT 164.367 566.730 164.385 566.784 ;
    END
  END w0_wmask_in[351]
  PIN w0_wmask_in[352]
    DIRECTION INPUT ;
    USE SIGNAL ;
    SHAPE ABUTMENT ;
    PORT
      LAYER M3 ;
      RECT 166.095 566.730 166.113 566.784 ;
    END
  END w0_wmask_in[352]
  PIN w0_wmask_in[353]
    DIRECTION INPUT ;
    USE SIGNAL ;
    SHAPE ABUTMENT ;
    PORT
      LAYER M3 ;
      RECT 167.823 566.730 167.841 566.784 ;
    END
  END w0_wmask_in[353]
  PIN w0_wmask_in[354]
    DIRECTION INPUT ;
    USE SIGNAL ;
    SHAPE ABUTMENT ;
    PORT
      LAYER M3 ;
      RECT 169.551 566.730 169.569 566.784 ;
    END
  END w0_wmask_in[354]
  PIN w0_wmask_in[355]
    DIRECTION INPUT ;
    USE SIGNAL ;
    SHAPE ABUTMENT ;
    PORT
      LAYER M3 ;
      RECT 171.279 566.730 171.297 566.784 ;
    END
  END w0_wmask_in[355]
  PIN w0_wmask_in[356]
    DIRECTION INPUT ;
    USE SIGNAL ;
    SHAPE ABUTMENT ;
    PORT
      LAYER M3 ;
      RECT 173.007 566.730 173.025 566.784 ;
    END
  END w0_wmask_in[356]
  PIN w0_wmask_in[357]
    DIRECTION INPUT ;
    USE SIGNAL ;
    SHAPE ABUTMENT ;
    PORT
      LAYER M3 ;
      RECT 174.735 566.730 174.753 566.784 ;
    END
  END w0_wmask_in[357]
  PIN w0_wmask_in[358]
    DIRECTION INPUT ;
    USE SIGNAL ;
    SHAPE ABUTMENT ;
    PORT
      LAYER M3 ;
      RECT 176.463 566.730 176.481 566.784 ;
    END
  END w0_wmask_in[358]
  PIN w0_wmask_in[359]
    DIRECTION INPUT ;
    USE SIGNAL ;
    SHAPE ABUTMENT ;
    PORT
      LAYER M3 ;
      RECT 178.191 566.730 178.209 566.784 ;
    END
  END w0_wmask_in[359]
  PIN w0_wmask_in[360]
    DIRECTION INPUT ;
    USE SIGNAL ;
    SHAPE ABUTMENT ;
    PORT
      LAYER M3 ;
      RECT 179.919 566.730 179.937 566.784 ;
    END
  END w0_wmask_in[360]
  PIN w0_wmask_in[361]
    DIRECTION INPUT ;
    USE SIGNAL ;
    SHAPE ABUTMENT ;
    PORT
      LAYER M3 ;
      RECT 181.647 566.730 181.665 566.784 ;
    END
  END w0_wmask_in[361]
  PIN w0_wmask_in[362]
    DIRECTION INPUT ;
    USE SIGNAL ;
    SHAPE ABUTMENT ;
    PORT
      LAYER M3 ;
      RECT 183.375 566.730 183.393 566.784 ;
    END
  END w0_wmask_in[362]
  PIN w0_wmask_in[363]
    DIRECTION INPUT ;
    USE SIGNAL ;
    SHAPE ABUTMENT ;
    PORT
      LAYER M3 ;
      RECT 185.103 566.730 185.121 566.784 ;
    END
  END w0_wmask_in[363]
  PIN w0_wmask_in[364]
    DIRECTION INPUT ;
    USE SIGNAL ;
    SHAPE ABUTMENT ;
    PORT
      LAYER M3 ;
      RECT 186.831 566.730 186.849 566.784 ;
    END
  END w0_wmask_in[364]
  PIN w0_wmask_in[365]
    DIRECTION INPUT ;
    USE SIGNAL ;
    SHAPE ABUTMENT ;
    PORT
      LAYER M3 ;
      RECT 188.559 566.730 188.577 566.784 ;
    END
  END w0_wmask_in[365]
  PIN w0_wmask_in[366]
    DIRECTION INPUT ;
    USE SIGNAL ;
    SHAPE ABUTMENT ;
    PORT
      LAYER M3 ;
      RECT 190.287 566.730 190.305 566.784 ;
    END
  END w0_wmask_in[366]
  PIN w0_wmask_in[367]
    DIRECTION INPUT ;
    USE SIGNAL ;
    SHAPE ABUTMENT ;
    PORT
      LAYER M3 ;
      RECT 192.015 566.730 192.033 566.784 ;
    END
  END w0_wmask_in[367]
  PIN w0_wmask_in[368]
    DIRECTION INPUT ;
    USE SIGNAL ;
    SHAPE ABUTMENT ;
    PORT
      LAYER M3 ;
      RECT 193.743 566.730 193.761 566.784 ;
    END
  END w0_wmask_in[368]
  PIN w0_wmask_in[369]
    DIRECTION INPUT ;
    USE SIGNAL ;
    SHAPE ABUTMENT ;
    PORT
      LAYER M3 ;
      RECT 195.471 566.730 195.489 566.784 ;
    END
  END w0_wmask_in[369]
  PIN w0_wmask_in[370]
    DIRECTION INPUT ;
    USE SIGNAL ;
    SHAPE ABUTMENT ;
    PORT
      LAYER M3 ;
      RECT 197.199 566.730 197.217 566.784 ;
    END
  END w0_wmask_in[370]
  PIN w0_wmask_in[371]
    DIRECTION INPUT ;
    USE SIGNAL ;
    SHAPE ABUTMENT ;
    PORT
      LAYER M3 ;
      RECT 198.927 566.730 198.945 566.784 ;
    END
  END w0_wmask_in[371]
  PIN w0_wmask_in[372]
    DIRECTION INPUT ;
    USE SIGNAL ;
    SHAPE ABUTMENT ;
    PORT
      LAYER M3 ;
      RECT 200.655 566.730 200.673 566.784 ;
    END
  END w0_wmask_in[372]
  PIN w0_wmask_in[373]
    DIRECTION INPUT ;
    USE SIGNAL ;
    SHAPE ABUTMENT ;
    PORT
      LAYER M3 ;
      RECT 202.383 566.730 202.401 566.784 ;
    END
  END w0_wmask_in[373]
  PIN w0_wmask_in[374]
    DIRECTION INPUT ;
    USE SIGNAL ;
    SHAPE ABUTMENT ;
    PORT
      LAYER M3 ;
      RECT 204.111 566.730 204.129 566.784 ;
    END
  END w0_wmask_in[374]
  PIN w0_wmask_in[375]
    DIRECTION INPUT ;
    USE SIGNAL ;
    SHAPE ABUTMENT ;
    PORT
      LAYER M3 ;
      RECT 205.839 566.730 205.857 566.784 ;
    END
  END w0_wmask_in[375]
  PIN w0_wmask_in[376]
    DIRECTION INPUT ;
    USE SIGNAL ;
    SHAPE ABUTMENT ;
    PORT
      LAYER M3 ;
      RECT 207.567 566.730 207.585 566.784 ;
    END
  END w0_wmask_in[376]
  PIN w0_wmask_in[377]
    DIRECTION INPUT ;
    USE SIGNAL ;
    SHAPE ABUTMENT ;
    PORT
      LAYER M3 ;
      RECT 209.295 566.730 209.313 566.784 ;
    END
  END w0_wmask_in[377]
  PIN w0_wmask_in[378]
    DIRECTION INPUT ;
    USE SIGNAL ;
    SHAPE ABUTMENT ;
    PORT
      LAYER M3 ;
      RECT 211.023 566.730 211.041 566.784 ;
    END
  END w0_wmask_in[378]
  PIN w0_wmask_in[379]
    DIRECTION INPUT ;
    USE SIGNAL ;
    SHAPE ABUTMENT ;
    PORT
      LAYER M3 ;
      RECT 212.751 566.730 212.769 566.784 ;
    END
  END w0_wmask_in[379]
  PIN w0_wmask_in[380]
    DIRECTION INPUT ;
    USE SIGNAL ;
    SHAPE ABUTMENT ;
    PORT
      LAYER M3 ;
      RECT 214.479 566.730 214.497 566.784 ;
    END
  END w0_wmask_in[380]
  PIN w0_wmask_in[381]
    DIRECTION INPUT ;
    USE SIGNAL ;
    SHAPE ABUTMENT ;
    PORT
      LAYER M3 ;
      RECT 216.207 566.730 216.225 566.784 ;
    END
  END w0_wmask_in[381]
  PIN w0_wmask_in[382]
    DIRECTION INPUT ;
    USE SIGNAL ;
    SHAPE ABUTMENT ;
    PORT
      LAYER M3 ;
      RECT 217.935 566.730 217.953 566.784 ;
    END
  END w0_wmask_in[382]
  PIN w0_wmask_in[383]
    DIRECTION INPUT ;
    USE SIGNAL ;
    SHAPE ABUTMENT ;
    PORT
      LAYER M3 ;
      RECT 219.663 566.730 219.681 566.784 ;
    END
  END w0_wmask_in[383]
  PIN w0_wmask_in[384]
    DIRECTION INPUT ;
    USE SIGNAL ;
    SHAPE ABUTMENT ;
    PORT
      LAYER M3 ;
      RECT 221.391 566.730 221.409 566.784 ;
    END
  END w0_wmask_in[384]
  PIN w0_wmask_in[385]
    DIRECTION INPUT ;
    USE SIGNAL ;
    SHAPE ABUTMENT ;
    PORT
      LAYER M3 ;
      RECT 223.119 566.730 223.137 566.784 ;
    END
  END w0_wmask_in[385]
  PIN w0_wmask_in[386]
    DIRECTION INPUT ;
    USE SIGNAL ;
    SHAPE ABUTMENT ;
    PORT
      LAYER M3 ;
      RECT 224.847 566.730 224.865 566.784 ;
    END
  END w0_wmask_in[386]
  PIN w0_wmask_in[387]
    DIRECTION INPUT ;
    USE SIGNAL ;
    SHAPE ABUTMENT ;
    PORT
      LAYER M3 ;
      RECT 226.575 566.730 226.593 566.784 ;
    END
  END w0_wmask_in[387]
  PIN w0_wmask_in[388]
    DIRECTION INPUT ;
    USE SIGNAL ;
    SHAPE ABUTMENT ;
    PORT
      LAYER M3 ;
      RECT 228.303 566.730 228.321 566.784 ;
    END
  END w0_wmask_in[388]
  PIN w0_wmask_in[389]
    DIRECTION INPUT ;
    USE SIGNAL ;
    SHAPE ABUTMENT ;
    PORT
      LAYER M3 ;
      RECT 230.031 566.730 230.049 566.784 ;
    END
  END w0_wmask_in[389]
  PIN w0_wmask_in[390]
    DIRECTION INPUT ;
    USE SIGNAL ;
    SHAPE ABUTMENT ;
    PORT
      LAYER M3 ;
      RECT 231.759 566.730 231.777 566.784 ;
    END
  END w0_wmask_in[390]
  PIN w0_wmask_in[391]
    DIRECTION INPUT ;
    USE SIGNAL ;
    SHAPE ABUTMENT ;
    PORT
      LAYER M3 ;
      RECT 233.487 566.730 233.505 566.784 ;
    END
  END w0_wmask_in[391]
  PIN w0_wmask_in[392]
    DIRECTION INPUT ;
    USE SIGNAL ;
    SHAPE ABUTMENT ;
    PORT
      LAYER M3 ;
      RECT 235.215 566.730 235.233 566.784 ;
    END
  END w0_wmask_in[392]
  PIN w0_wmask_in[393]
    DIRECTION INPUT ;
    USE SIGNAL ;
    SHAPE ABUTMENT ;
    PORT
      LAYER M3 ;
      RECT 236.943 566.730 236.961 566.784 ;
    END
  END w0_wmask_in[393]
  PIN w0_wmask_in[394]
    DIRECTION INPUT ;
    USE SIGNAL ;
    SHAPE ABUTMENT ;
    PORT
      LAYER M3 ;
      RECT 238.671 566.730 238.689 566.784 ;
    END
  END w0_wmask_in[394]
  PIN w0_wmask_in[395]
    DIRECTION INPUT ;
    USE SIGNAL ;
    SHAPE ABUTMENT ;
    PORT
      LAYER M3 ;
      RECT 240.399 566.730 240.417 566.784 ;
    END
  END w0_wmask_in[395]
  PIN w0_wmask_in[396]
    DIRECTION INPUT ;
    USE SIGNAL ;
    SHAPE ABUTMENT ;
    PORT
      LAYER M3 ;
      RECT 242.127 566.730 242.145 566.784 ;
    END
  END w0_wmask_in[396]
  PIN w0_wmask_in[397]
    DIRECTION INPUT ;
    USE SIGNAL ;
    SHAPE ABUTMENT ;
    PORT
      LAYER M3 ;
      RECT 243.855 566.730 243.873 566.784 ;
    END
  END w0_wmask_in[397]
  PIN w0_wmask_in[398]
    DIRECTION INPUT ;
    USE SIGNAL ;
    SHAPE ABUTMENT ;
    PORT
      LAYER M3 ;
      RECT 245.583 566.730 245.601 566.784 ;
    END
  END w0_wmask_in[398]
  PIN w0_wmask_in[399]
    DIRECTION INPUT ;
    USE SIGNAL ;
    SHAPE ABUTMENT ;
    PORT
      LAYER M3 ;
      RECT 247.311 566.730 247.329 566.784 ;
    END
  END w0_wmask_in[399]
  PIN w0_wmask_in[400]
    DIRECTION INPUT ;
    USE SIGNAL ;
    SHAPE ABUTMENT ;
    PORT
      LAYER M3 ;
      RECT 249.039 566.730 249.057 566.784 ;
    END
  END w0_wmask_in[400]
  PIN w0_wmask_in[401]
    DIRECTION INPUT ;
    USE SIGNAL ;
    SHAPE ABUTMENT ;
    PORT
      LAYER M3 ;
      RECT 250.767 566.730 250.785 566.784 ;
    END
  END w0_wmask_in[401]
  PIN w0_wmask_in[402]
    DIRECTION INPUT ;
    USE SIGNAL ;
    SHAPE ABUTMENT ;
    PORT
      LAYER M3 ;
      RECT 252.495 566.730 252.513 566.784 ;
    END
  END w0_wmask_in[402]
  PIN w0_wmask_in[403]
    DIRECTION INPUT ;
    USE SIGNAL ;
    SHAPE ABUTMENT ;
    PORT
      LAYER M3 ;
      RECT 254.223 566.730 254.241 566.784 ;
    END
  END w0_wmask_in[403]
  PIN w0_wmask_in[404]
    DIRECTION INPUT ;
    USE SIGNAL ;
    SHAPE ABUTMENT ;
    PORT
      LAYER M3 ;
      RECT 255.951 566.730 255.969 566.784 ;
    END
  END w0_wmask_in[404]
  PIN w0_wmask_in[405]
    DIRECTION INPUT ;
    USE SIGNAL ;
    SHAPE ABUTMENT ;
    PORT
      LAYER M3 ;
      RECT 257.679 566.730 257.697 566.784 ;
    END
  END w0_wmask_in[405]
  PIN w0_wmask_in[406]
    DIRECTION INPUT ;
    USE SIGNAL ;
    SHAPE ABUTMENT ;
    PORT
      LAYER M3 ;
      RECT 259.407 566.730 259.425 566.784 ;
    END
  END w0_wmask_in[406]
  PIN w0_wmask_in[407]
    DIRECTION INPUT ;
    USE SIGNAL ;
    SHAPE ABUTMENT ;
    PORT
      LAYER M3 ;
      RECT 261.135 566.730 261.153 566.784 ;
    END
  END w0_wmask_in[407]
  PIN w0_wmask_in[408]
    DIRECTION INPUT ;
    USE SIGNAL ;
    SHAPE ABUTMENT ;
    PORT
      LAYER M3 ;
      RECT 262.863 566.730 262.881 566.784 ;
    END
  END w0_wmask_in[408]
  PIN w0_wmask_in[409]
    DIRECTION INPUT ;
    USE SIGNAL ;
    SHAPE ABUTMENT ;
    PORT
      LAYER M3 ;
      RECT 264.591 566.730 264.609 566.784 ;
    END
  END w0_wmask_in[409]
  PIN w0_wmask_in[410]
    DIRECTION INPUT ;
    USE SIGNAL ;
    SHAPE ABUTMENT ;
    PORT
      LAYER M3 ;
      RECT 266.319 566.730 266.337 566.784 ;
    END
  END w0_wmask_in[410]
  PIN w0_wmask_in[411]
    DIRECTION INPUT ;
    USE SIGNAL ;
    SHAPE ABUTMENT ;
    PORT
      LAYER M3 ;
      RECT 268.047 566.730 268.065 566.784 ;
    END
  END w0_wmask_in[411]
  PIN w0_wmask_in[412]
    DIRECTION INPUT ;
    USE SIGNAL ;
    SHAPE ABUTMENT ;
    PORT
      LAYER M3 ;
      RECT 269.775 566.730 269.793 566.784 ;
    END
  END w0_wmask_in[412]
  PIN w0_wmask_in[413]
    DIRECTION INPUT ;
    USE SIGNAL ;
    SHAPE ABUTMENT ;
    PORT
      LAYER M3 ;
      RECT 271.503 566.730 271.521 566.784 ;
    END
  END w0_wmask_in[413]
  PIN w0_wmask_in[414]
    DIRECTION INPUT ;
    USE SIGNAL ;
    SHAPE ABUTMENT ;
    PORT
      LAYER M3 ;
      RECT 273.231 566.730 273.249 566.784 ;
    END
  END w0_wmask_in[414]
  PIN w0_wmask_in[415]
    DIRECTION INPUT ;
    USE SIGNAL ;
    SHAPE ABUTMENT ;
    PORT
      LAYER M3 ;
      RECT 274.959 566.730 274.977 566.784 ;
    END
  END w0_wmask_in[415]
  PIN w0_wmask_in[416]
    DIRECTION INPUT ;
    USE SIGNAL ;
    SHAPE ABUTMENT ;
    PORT
      LAYER M3 ;
      RECT 276.687 566.730 276.705 566.784 ;
    END
  END w0_wmask_in[416]
  PIN w0_wmask_in[417]
    DIRECTION INPUT ;
    USE SIGNAL ;
    SHAPE ABUTMENT ;
    PORT
      LAYER M3 ;
      RECT 278.415 566.730 278.433 566.784 ;
    END
  END w0_wmask_in[417]
  PIN w0_wmask_in[418]
    DIRECTION INPUT ;
    USE SIGNAL ;
    SHAPE ABUTMENT ;
    PORT
      LAYER M3 ;
      RECT 280.143 566.730 280.161 566.784 ;
    END
  END w0_wmask_in[418]
  PIN w0_wmask_in[419]
    DIRECTION INPUT ;
    USE SIGNAL ;
    SHAPE ABUTMENT ;
    PORT
      LAYER M3 ;
      RECT 281.871 566.730 281.889 566.784 ;
    END
  END w0_wmask_in[419]
  PIN w0_wmask_in[420]
    DIRECTION INPUT ;
    USE SIGNAL ;
    SHAPE ABUTMENT ;
    PORT
      LAYER M3 ;
      RECT 283.599 566.730 283.617 566.784 ;
    END
  END w0_wmask_in[420]
  PIN w0_wmask_in[421]
    DIRECTION INPUT ;
    USE SIGNAL ;
    SHAPE ABUTMENT ;
    PORT
      LAYER M3 ;
      RECT 285.327 566.730 285.345 566.784 ;
    END
  END w0_wmask_in[421]
  PIN w0_wmask_in[422]
    DIRECTION INPUT ;
    USE SIGNAL ;
    SHAPE ABUTMENT ;
    PORT
      LAYER M3 ;
      RECT 287.055 566.730 287.073 566.784 ;
    END
  END w0_wmask_in[422]
  PIN w0_wmask_in[423]
    DIRECTION INPUT ;
    USE SIGNAL ;
    SHAPE ABUTMENT ;
    PORT
      LAYER M3 ;
      RECT 288.783 566.730 288.801 566.784 ;
    END
  END w0_wmask_in[423]
  PIN w0_wmask_in[424]
    DIRECTION INPUT ;
    USE SIGNAL ;
    SHAPE ABUTMENT ;
    PORT
      LAYER M3 ;
      RECT 290.511 566.730 290.529 566.784 ;
    END
  END w0_wmask_in[424]
  PIN w0_wmask_in[425]
    DIRECTION INPUT ;
    USE SIGNAL ;
    SHAPE ABUTMENT ;
    PORT
      LAYER M3 ;
      RECT 292.239 566.730 292.257 566.784 ;
    END
  END w0_wmask_in[425]
  PIN w0_wmask_in[426]
    DIRECTION INPUT ;
    USE SIGNAL ;
    SHAPE ABUTMENT ;
    PORT
      LAYER M3 ;
      RECT 293.967 566.730 293.985 566.784 ;
    END
  END w0_wmask_in[426]
  PIN w0_wmask_in[427]
    DIRECTION INPUT ;
    USE SIGNAL ;
    SHAPE ABUTMENT ;
    PORT
      LAYER M3 ;
      RECT 295.695 566.730 295.713 566.784 ;
    END
  END w0_wmask_in[427]
  PIN w0_wmask_in[428]
    DIRECTION INPUT ;
    USE SIGNAL ;
    SHAPE ABUTMENT ;
    PORT
      LAYER M3 ;
      RECT 297.423 566.730 297.441 566.784 ;
    END
  END w0_wmask_in[428]
  PIN w0_wmask_in[429]
    DIRECTION INPUT ;
    USE SIGNAL ;
    SHAPE ABUTMENT ;
    PORT
      LAYER M3 ;
      RECT 299.151 566.730 299.169 566.784 ;
    END
  END w0_wmask_in[429]
  PIN w0_wmask_in[430]
    DIRECTION INPUT ;
    USE SIGNAL ;
    SHAPE ABUTMENT ;
    PORT
      LAYER M3 ;
      RECT 300.879 566.730 300.897 566.784 ;
    END
  END w0_wmask_in[430]
  PIN w0_wmask_in[431]
    DIRECTION INPUT ;
    USE SIGNAL ;
    SHAPE ABUTMENT ;
    PORT
      LAYER M3 ;
      RECT 302.607 566.730 302.625 566.784 ;
    END
  END w0_wmask_in[431]
  PIN w0_wmask_in[432]
    DIRECTION INPUT ;
    USE SIGNAL ;
    SHAPE ABUTMENT ;
    PORT
      LAYER M3 ;
      RECT 304.335 566.730 304.353 566.784 ;
    END
  END w0_wmask_in[432]
  PIN w0_wmask_in[433]
    DIRECTION INPUT ;
    USE SIGNAL ;
    SHAPE ABUTMENT ;
    PORT
      LAYER M3 ;
      RECT 306.063 566.730 306.081 566.784 ;
    END
  END w0_wmask_in[433]
  PIN w0_wmask_in[434]
    DIRECTION INPUT ;
    USE SIGNAL ;
    SHAPE ABUTMENT ;
    PORT
      LAYER M3 ;
      RECT 307.791 566.730 307.809 566.784 ;
    END
  END w0_wmask_in[434]
  PIN w0_wmask_in[435]
    DIRECTION INPUT ;
    USE SIGNAL ;
    SHAPE ABUTMENT ;
    PORT
      LAYER M3 ;
      RECT 309.519 566.730 309.537 566.784 ;
    END
  END w0_wmask_in[435]
  PIN w0_wmask_in[436]
    DIRECTION INPUT ;
    USE SIGNAL ;
    SHAPE ABUTMENT ;
    PORT
      LAYER M3 ;
      RECT 311.247 566.730 311.265 566.784 ;
    END
  END w0_wmask_in[436]
  PIN w0_wmask_in[437]
    DIRECTION INPUT ;
    USE SIGNAL ;
    SHAPE ABUTMENT ;
    PORT
      LAYER M3 ;
      RECT 312.975 566.730 312.993 566.784 ;
    END
  END w0_wmask_in[437]
  PIN w0_wmask_in[438]
    DIRECTION INPUT ;
    USE SIGNAL ;
    SHAPE ABUTMENT ;
    PORT
      LAYER M3 ;
      RECT 314.703 566.730 314.721 566.784 ;
    END
  END w0_wmask_in[438]
  PIN w0_wmask_in[439]
    DIRECTION INPUT ;
    USE SIGNAL ;
    SHAPE ABUTMENT ;
    PORT
      LAYER M3 ;
      RECT 316.431 566.730 316.449 566.784 ;
    END
  END w0_wmask_in[439]
  PIN w0_wmask_in[440]
    DIRECTION INPUT ;
    USE SIGNAL ;
    SHAPE ABUTMENT ;
    PORT
      LAYER M3 ;
      RECT 318.159 566.730 318.177 566.784 ;
    END
  END w0_wmask_in[440]
  PIN w0_wmask_in[441]
    DIRECTION INPUT ;
    USE SIGNAL ;
    SHAPE ABUTMENT ;
    PORT
      LAYER M3 ;
      RECT 319.887 566.730 319.905 566.784 ;
    END
  END w0_wmask_in[441]
  PIN w0_wmask_in[442]
    DIRECTION INPUT ;
    USE SIGNAL ;
    SHAPE ABUTMENT ;
    PORT
      LAYER M3 ;
      RECT 321.615 566.730 321.633 566.784 ;
    END
  END w0_wmask_in[442]
  PIN w0_wmask_in[443]
    DIRECTION INPUT ;
    USE SIGNAL ;
    SHAPE ABUTMENT ;
    PORT
      LAYER M3 ;
      RECT 323.343 566.730 323.361 566.784 ;
    END
  END w0_wmask_in[443]
  PIN w0_wmask_in[444]
    DIRECTION INPUT ;
    USE SIGNAL ;
    SHAPE ABUTMENT ;
    PORT
      LAYER M3 ;
      RECT 325.071 566.730 325.089 566.784 ;
    END
  END w0_wmask_in[444]
  PIN w0_wmask_in[445]
    DIRECTION INPUT ;
    USE SIGNAL ;
    SHAPE ABUTMENT ;
    PORT
      LAYER M3 ;
      RECT 326.799 566.730 326.817 566.784 ;
    END
  END w0_wmask_in[445]
  PIN w0_wmask_in[446]
    DIRECTION INPUT ;
    USE SIGNAL ;
    SHAPE ABUTMENT ;
    PORT
      LAYER M3 ;
      RECT 328.527 566.730 328.545 566.784 ;
    END
  END w0_wmask_in[446]
  PIN w0_wmask_in[447]
    DIRECTION INPUT ;
    USE SIGNAL ;
    SHAPE ABUTMENT ;
    PORT
      LAYER M3 ;
      RECT 330.255 566.730 330.273 566.784 ;
    END
  END w0_wmask_in[447]
  PIN w0_wmask_in[448]
    DIRECTION INPUT ;
    USE SIGNAL ;
    SHAPE ABUTMENT ;
    PORT
      LAYER M3 ;
      RECT 331.983 566.730 332.001 566.784 ;
    END
  END w0_wmask_in[448]
  PIN w0_wmask_in[449]
    DIRECTION INPUT ;
    USE SIGNAL ;
    SHAPE ABUTMENT ;
    PORT
      LAYER M3 ;
      RECT 333.711 566.730 333.729 566.784 ;
    END
  END w0_wmask_in[449]
  PIN w0_wmask_in[450]
    DIRECTION INPUT ;
    USE SIGNAL ;
    SHAPE ABUTMENT ;
    PORT
      LAYER M3 ;
      RECT 335.439 566.730 335.457 566.784 ;
    END
  END w0_wmask_in[450]
  PIN w0_wmask_in[451]
    DIRECTION INPUT ;
    USE SIGNAL ;
    SHAPE ABUTMENT ;
    PORT
      LAYER M3 ;
      RECT 337.167 566.730 337.185 566.784 ;
    END
  END w0_wmask_in[451]
  PIN w0_wmask_in[452]
    DIRECTION INPUT ;
    USE SIGNAL ;
    SHAPE ABUTMENT ;
    PORT
      LAYER M3 ;
      RECT 338.895 566.730 338.913 566.784 ;
    END
  END w0_wmask_in[452]
  PIN w0_wmask_in[453]
    DIRECTION INPUT ;
    USE SIGNAL ;
    SHAPE ABUTMENT ;
    PORT
      LAYER M3 ;
      RECT 340.623 566.730 340.641 566.784 ;
    END
  END w0_wmask_in[453]
  PIN w0_wmask_in[454]
    DIRECTION INPUT ;
    USE SIGNAL ;
    SHAPE ABUTMENT ;
    PORT
      LAYER M3 ;
      RECT 342.351 566.730 342.369 566.784 ;
    END
  END w0_wmask_in[454]
  PIN w0_wmask_in[455]
    DIRECTION INPUT ;
    USE SIGNAL ;
    SHAPE ABUTMENT ;
    PORT
      LAYER M3 ;
      RECT 344.079 566.730 344.097 566.784 ;
    END
  END w0_wmask_in[455]
  PIN w0_wmask_in[456]
    DIRECTION INPUT ;
    USE SIGNAL ;
    SHAPE ABUTMENT ;
    PORT
      LAYER M3 ;
      RECT 345.807 566.730 345.825 566.784 ;
    END
  END w0_wmask_in[456]
  PIN w0_wmask_in[457]
    DIRECTION INPUT ;
    USE SIGNAL ;
    SHAPE ABUTMENT ;
    PORT
      LAYER M3 ;
      RECT 347.535 566.730 347.553 566.784 ;
    END
  END w0_wmask_in[457]
  PIN w0_wmask_in[458]
    DIRECTION INPUT ;
    USE SIGNAL ;
    SHAPE ABUTMENT ;
    PORT
      LAYER M3 ;
      RECT 349.263 566.730 349.281 566.784 ;
    END
  END w0_wmask_in[458]
  PIN w0_wmask_in[459]
    DIRECTION INPUT ;
    USE SIGNAL ;
    SHAPE ABUTMENT ;
    PORT
      LAYER M3 ;
      RECT 350.991 566.730 351.009 566.784 ;
    END
  END w0_wmask_in[459]
  PIN w0_wmask_in[460]
    DIRECTION INPUT ;
    USE SIGNAL ;
    SHAPE ABUTMENT ;
    PORT
      LAYER M3 ;
      RECT 352.719 566.730 352.737 566.784 ;
    END
  END w0_wmask_in[460]
  PIN w0_wmask_in[461]
    DIRECTION INPUT ;
    USE SIGNAL ;
    SHAPE ABUTMENT ;
    PORT
      LAYER M3 ;
      RECT 354.447 566.730 354.465 566.784 ;
    END
  END w0_wmask_in[461]
  PIN w0_wmask_in[462]
    DIRECTION INPUT ;
    USE SIGNAL ;
    SHAPE ABUTMENT ;
    PORT
      LAYER M3 ;
      RECT 356.175 566.730 356.193 566.784 ;
    END
  END w0_wmask_in[462]
  PIN w0_wmask_in[463]
    DIRECTION INPUT ;
    USE SIGNAL ;
    SHAPE ABUTMENT ;
    PORT
      LAYER M3 ;
      RECT 357.903 566.730 357.921 566.784 ;
    END
  END w0_wmask_in[463]
  PIN w0_wmask_in[464]
    DIRECTION INPUT ;
    USE SIGNAL ;
    SHAPE ABUTMENT ;
    PORT
      LAYER M3 ;
      RECT 359.631 566.730 359.649 566.784 ;
    END
  END w0_wmask_in[464]
  PIN w0_wmask_in[465]
    DIRECTION INPUT ;
    USE SIGNAL ;
    SHAPE ABUTMENT ;
    PORT
      LAYER M3 ;
      RECT 361.359 566.730 361.377 566.784 ;
    END
  END w0_wmask_in[465]
  PIN w0_wmask_in[466]
    DIRECTION INPUT ;
    USE SIGNAL ;
    SHAPE ABUTMENT ;
    PORT
      LAYER M3 ;
      RECT 363.087 566.730 363.105 566.784 ;
    END
  END w0_wmask_in[466]
  PIN w0_wmask_in[467]
    DIRECTION INPUT ;
    USE SIGNAL ;
    SHAPE ABUTMENT ;
    PORT
      LAYER M3 ;
      RECT 364.815 566.730 364.833 566.784 ;
    END
  END w0_wmask_in[467]
  PIN w0_wmask_in[468]
    DIRECTION INPUT ;
    USE SIGNAL ;
    SHAPE ABUTMENT ;
    PORT
      LAYER M3 ;
      RECT 366.543 566.730 366.561 566.784 ;
    END
  END w0_wmask_in[468]
  PIN w0_wmask_in[469]
    DIRECTION INPUT ;
    USE SIGNAL ;
    SHAPE ABUTMENT ;
    PORT
      LAYER M3 ;
      RECT 368.271 566.730 368.289 566.784 ;
    END
  END w0_wmask_in[469]
  PIN w0_wmask_in[470]
    DIRECTION INPUT ;
    USE SIGNAL ;
    SHAPE ABUTMENT ;
    PORT
      LAYER M3 ;
      RECT 369.999 566.730 370.017 566.784 ;
    END
  END w0_wmask_in[470]
  PIN w0_wmask_in[471]
    DIRECTION INPUT ;
    USE SIGNAL ;
    SHAPE ABUTMENT ;
    PORT
      LAYER M3 ;
      RECT 371.727 566.730 371.745 566.784 ;
    END
  END w0_wmask_in[471]
  PIN w0_wmask_in[472]
    DIRECTION INPUT ;
    USE SIGNAL ;
    SHAPE ABUTMENT ;
    PORT
      LAYER M3 ;
      RECT 373.455 566.730 373.473 566.784 ;
    END
  END w0_wmask_in[472]
  PIN w0_wmask_in[473]
    DIRECTION INPUT ;
    USE SIGNAL ;
    SHAPE ABUTMENT ;
    PORT
      LAYER M3 ;
      RECT 375.183 566.730 375.201 566.784 ;
    END
  END w0_wmask_in[473]
  PIN w0_wmask_in[474]
    DIRECTION INPUT ;
    USE SIGNAL ;
    SHAPE ABUTMENT ;
    PORT
      LAYER M3 ;
      RECT 376.911 566.730 376.929 566.784 ;
    END
  END w0_wmask_in[474]
  PIN w0_wmask_in[475]
    DIRECTION INPUT ;
    USE SIGNAL ;
    SHAPE ABUTMENT ;
    PORT
      LAYER M3 ;
      RECT 378.639 566.730 378.657 566.784 ;
    END
  END w0_wmask_in[475]
  PIN w0_wmask_in[476]
    DIRECTION INPUT ;
    USE SIGNAL ;
    SHAPE ABUTMENT ;
    PORT
      LAYER M3 ;
      RECT 380.367 566.730 380.385 566.784 ;
    END
  END w0_wmask_in[476]
  PIN w0_wmask_in[477]
    DIRECTION INPUT ;
    USE SIGNAL ;
    SHAPE ABUTMENT ;
    PORT
      LAYER M3 ;
      RECT 382.095 566.730 382.113 566.784 ;
    END
  END w0_wmask_in[477]
  PIN w0_wmask_in[478]
    DIRECTION INPUT ;
    USE SIGNAL ;
    SHAPE ABUTMENT ;
    PORT
      LAYER M3 ;
      RECT 383.823 566.730 383.841 566.784 ;
    END
  END w0_wmask_in[478]
  PIN w0_wmask_in[479]
    DIRECTION INPUT ;
    USE SIGNAL ;
    SHAPE ABUTMENT ;
    PORT
      LAYER M3 ;
      RECT 385.551 566.730 385.569 566.784 ;
    END
  END w0_wmask_in[479]
  PIN w0_wmask_in[480]
    DIRECTION INPUT ;
    USE SIGNAL ;
    SHAPE ABUTMENT ;
    PORT
      LAYER M3 ;
      RECT 387.279 566.730 387.297 566.784 ;
    END
  END w0_wmask_in[480]
  PIN w0_wmask_in[481]
    DIRECTION INPUT ;
    USE SIGNAL ;
    SHAPE ABUTMENT ;
    PORT
      LAYER M3 ;
      RECT 389.007 566.730 389.025 566.784 ;
    END
  END w0_wmask_in[481]
  PIN w0_wmask_in[482]
    DIRECTION INPUT ;
    USE SIGNAL ;
    SHAPE ABUTMENT ;
    PORT
      LAYER M3 ;
      RECT 390.735 566.730 390.753 566.784 ;
    END
  END w0_wmask_in[482]
  PIN w0_wmask_in[483]
    DIRECTION INPUT ;
    USE SIGNAL ;
    SHAPE ABUTMENT ;
    PORT
      LAYER M3 ;
      RECT 392.463 566.730 392.481 566.784 ;
    END
  END w0_wmask_in[483]
  PIN w0_wmask_in[484]
    DIRECTION INPUT ;
    USE SIGNAL ;
    SHAPE ABUTMENT ;
    PORT
      LAYER M3 ;
      RECT 394.191 566.730 394.209 566.784 ;
    END
  END w0_wmask_in[484]
  PIN w0_wmask_in[485]
    DIRECTION INPUT ;
    USE SIGNAL ;
    SHAPE ABUTMENT ;
    PORT
      LAYER M3 ;
      RECT 395.919 566.730 395.937 566.784 ;
    END
  END w0_wmask_in[485]
  PIN w0_wmask_in[486]
    DIRECTION INPUT ;
    USE SIGNAL ;
    SHAPE ABUTMENT ;
    PORT
      LAYER M3 ;
      RECT 397.647 566.730 397.665 566.784 ;
    END
  END w0_wmask_in[486]
  PIN w0_wmask_in[487]
    DIRECTION INPUT ;
    USE SIGNAL ;
    SHAPE ABUTMENT ;
    PORT
      LAYER M3 ;
      RECT 399.375 566.730 399.393 566.784 ;
    END
  END w0_wmask_in[487]
  PIN w0_wmask_in[488]
    DIRECTION INPUT ;
    USE SIGNAL ;
    SHAPE ABUTMENT ;
    PORT
      LAYER M3 ;
      RECT 401.103 566.730 401.121 566.784 ;
    END
  END w0_wmask_in[488]
  PIN w0_wmask_in[489]
    DIRECTION INPUT ;
    USE SIGNAL ;
    SHAPE ABUTMENT ;
    PORT
      LAYER M3 ;
      RECT 402.831 566.730 402.849 566.784 ;
    END
  END w0_wmask_in[489]
  PIN w0_wmask_in[490]
    DIRECTION INPUT ;
    USE SIGNAL ;
    SHAPE ABUTMENT ;
    PORT
      LAYER M3 ;
      RECT 404.559 566.730 404.577 566.784 ;
    END
  END w0_wmask_in[490]
  PIN w0_wmask_in[491]
    DIRECTION INPUT ;
    USE SIGNAL ;
    SHAPE ABUTMENT ;
    PORT
      LAYER M3 ;
      RECT 406.287 566.730 406.305 566.784 ;
    END
  END w0_wmask_in[491]
  PIN w0_wmask_in[492]
    DIRECTION INPUT ;
    USE SIGNAL ;
    SHAPE ABUTMENT ;
    PORT
      LAYER M3 ;
      RECT 408.015 566.730 408.033 566.784 ;
    END
  END w0_wmask_in[492]
  PIN w0_wmask_in[493]
    DIRECTION INPUT ;
    USE SIGNAL ;
    SHAPE ABUTMENT ;
    PORT
      LAYER M3 ;
      RECT 409.743 566.730 409.761 566.784 ;
    END
  END w0_wmask_in[493]
  PIN w0_wmask_in[494]
    DIRECTION INPUT ;
    USE SIGNAL ;
    SHAPE ABUTMENT ;
    PORT
      LAYER M3 ;
      RECT 411.471 566.730 411.489 566.784 ;
    END
  END w0_wmask_in[494]
  PIN w0_wmask_in[495]
    DIRECTION INPUT ;
    USE SIGNAL ;
    SHAPE ABUTMENT ;
    PORT
      LAYER M3 ;
      RECT 413.199 566.730 413.217 566.784 ;
    END
  END w0_wmask_in[495]
  PIN w0_wmask_in[496]
    DIRECTION INPUT ;
    USE SIGNAL ;
    SHAPE ABUTMENT ;
    PORT
      LAYER M3 ;
      RECT 414.927 566.730 414.945 566.784 ;
    END
  END w0_wmask_in[496]
  PIN w0_wmask_in[497]
    DIRECTION INPUT ;
    USE SIGNAL ;
    SHAPE ABUTMENT ;
    PORT
      LAYER M3 ;
      RECT 416.655 566.730 416.673 566.784 ;
    END
  END w0_wmask_in[497]
  PIN w0_wmask_in[498]
    DIRECTION INPUT ;
    USE SIGNAL ;
    SHAPE ABUTMENT ;
    PORT
      LAYER M3 ;
      RECT 418.383 566.730 418.401 566.784 ;
    END
  END w0_wmask_in[498]
  PIN w0_wmask_in[499]
    DIRECTION INPUT ;
    USE SIGNAL ;
    SHAPE ABUTMENT ;
    PORT
      LAYER M3 ;
      RECT 420.111 566.730 420.129 566.784 ;
    END
  END w0_wmask_in[499]
  PIN w0_wmask_in[500]
    DIRECTION INPUT ;
    USE SIGNAL ;
    SHAPE ABUTMENT ;
    PORT
      LAYER M3 ;
      RECT 421.839 566.730 421.857 566.784 ;
    END
  END w0_wmask_in[500]
  PIN w0_wmask_in[501]
    DIRECTION INPUT ;
    USE SIGNAL ;
    SHAPE ABUTMENT ;
    PORT
      LAYER M3 ;
      RECT 423.567 566.730 423.585 566.784 ;
    END
  END w0_wmask_in[501]
  PIN w0_wmask_in[502]
    DIRECTION INPUT ;
    USE SIGNAL ;
    SHAPE ABUTMENT ;
    PORT
      LAYER M3 ;
      RECT 425.295 566.730 425.313 566.784 ;
    END
  END w0_wmask_in[502]
  PIN w0_wmask_in[503]
    DIRECTION INPUT ;
    USE SIGNAL ;
    SHAPE ABUTMENT ;
    PORT
      LAYER M3 ;
      RECT 427.023 566.730 427.041 566.784 ;
    END
  END w0_wmask_in[503]
  PIN w0_wmask_in[504]
    DIRECTION INPUT ;
    USE SIGNAL ;
    SHAPE ABUTMENT ;
    PORT
      LAYER M3 ;
      RECT 428.751 566.730 428.769 566.784 ;
    END
  END w0_wmask_in[504]
  PIN w0_wmask_in[505]
    DIRECTION INPUT ;
    USE SIGNAL ;
    SHAPE ABUTMENT ;
    PORT
      LAYER M3 ;
      RECT 430.479 566.730 430.497 566.784 ;
    END
  END w0_wmask_in[505]
  PIN w0_wmask_in[506]
    DIRECTION INPUT ;
    USE SIGNAL ;
    SHAPE ABUTMENT ;
    PORT
      LAYER M3 ;
      RECT 432.207 566.730 432.225 566.784 ;
    END
  END w0_wmask_in[506]
  PIN w0_wmask_in[507]
    DIRECTION INPUT ;
    USE SIGNAL ;
    SHAPE ABUTMENT ;
    PORT
      LAYER M3 ;
      RECT 433.935 566.730 433.953 566.784 ;
    END
  END w0_wmask_in[507]
  PIN w0_wmask_in[508]
    DIRECTION INPUT ;
    USE SIGNAL ;
    SHAPE ABUTMENT ;
    PORT
      LAYER M3 ;
      RECT 435.663 566.730 435.681 566.784 ;
    END
  END w0_wmask_in[508]
  PIN w0_wmask_in[509]
    DIRECTION INPUT ;
    USE SIGNAL ;
    SHAPE ABUTMENT ;
    PORT
      LAYER M3 ;
      RECT 437.391 566.730 437.409 566.784 ;
    END
  END w0_wmask_in[509]
  PIN w0_wmask_in[510]
    DIRECTION INPUT ;
    USE SIGNAL ;
    SHAPE ABUTMENT ;
    PORT
      LAYER M3 ;
      RECT 439.119 566.730 439.137 566.784 ;
    END
  END w0_wmask_in[510]
  PIN w0_wmask_in[511]
    DIRECTION INPUT ;
    USE SIGNAL ;
    SHAPE ABUTMENT ;
    PORT
      LAYER M3 ;
      RECT 440.847 566.730 440.865 566.784 ;
    END
  END w0_wmask_in[511]
  PIN w0_wd_in[0]
    DIRECTION INPUT ;
    USE SIGNAL ;
    SHAPE ABUTMENT ;
    PORT
      LAYER M4 ;
      RECT 0.000 270.612 0.072 270.636 ;
    END
  END w0_wd_in[0]
  PIN w0_wd_in[1]
    DIRECTION INPUT ;
    USE SIGNAL ;
    SHAPE ABUTMENT ;
    PORT
      LAYER M4 ;
      RECT 0.000 272.724 0.072 272.748 ;
    END
  END w0_wd_in[1]
  PIN w0_wd_in[2]
    DIRECTION INPUT ;
    USE SIGNAL ;
    SHAPE ABUTMENT ;
    PORT
      LAYER M4 ;
      RECT 0.000 274.836 0.072 274.860 ;
    END
  END w0_wd_in[2]
  PIN w0_wd_in[3]
    DIRECTION INPUT ;
    USE SIGNAL ;
    SHAPE ABUTMENT ;
    PORT
      LAYER M4 ;
      RECT 0.000 276.948 0.072 276.972 ;
    END
  END w0_wd_in[3]
  PIN w0_wd_in[4]
    DIRECTION INPUT ;
    USE SIGNAL ;
    SHAPE ABUTMENT ;
    PORT
      LAYER M4 ;
      RECT 0.000 279.060 0.072 279.084 ;
    END
  END w0_wd_in[4]
  PIN w0_wd_in[5]
    DIRECTION INPUT ;
    USE SIGNAL ;
    SHAPE ABUTMENT ;
    PORT
      LAYER M4 ;
      RECT 0.000 281.172 0.072 281.196 ;
    END
  END w0_wd_in[5]
  PIN w0_wd_in[6]
    DIRECTION INPUT ;
    USE SIGNAL ;
    SHAPE ABUTMENT ;
    PORT
      LAYER M4 ;
      RECT 0.000 283.284 0.072 283.308 ;
    END
  END w0_wd_in[6]
  PIN w0_wd_in[7]
    DIRECTION INPUT ;
    USE SIGNAL ;
    SHAPE ABUTMENT ;
    PORT
      LAYER M4 ;
      RECT 0.000 285.396 0.072 285.420 ;
    END
  END w0_wd_in[7]
  PIN w0_wd_in[8]
    DIRECTION INPUT ;
    USE SIGNAL ;
    SHAPE ABUTMENT ;
    PORT
      LAYER M4 ;
      RECT 0.000 287.508 0.072 287.532 ;
    END
  END w0_wd_in[8]
  PIN w0_wd_in[9]
    DIRECTION INPUT ;
    USE SIGNAL ;
    SHAPE ABUTMENT ;
    PORT
      LAYER M4 ;
      RECT 0.000 289.620 0.072 289.644 ;
    END
  END w0_wd_in[9]
  PIN w0_wd_in[10]
    DIRECTION INPUT ;
    USE SIGNAL ;
    SHAPE ABUTMENT ;
    PORT
      LAYER M4 ;
      RECT 0.000 291.732 0.072 291.756 ;
    END
  END w0_wd_in[10]
  PIN w0_wd_in[11]
    DIRECTION INPUT ;
    USE SIGNAL ;
    SHAPE ABUTMENT ;
    PORT
      LAYER M4 ;
      RECT 0.000 293.844 0.072 293.868 ;
    END
  END w0_wd_in[11]
  PIN w0_wd_in[12]
    DIRECTION INPUT ;
    USE SIGNAL ;
    SHAPE ABUTMENT ;
    PORT
      LAYER M4 ;
      RECT 0.000 295.956 0.072 295.980 ;
    END
  END w0_wd_in[12]
  PIN w0_wd_in[13]
    DIRECTION INPUT ;
    USE SIGNAL ;
    SHAPE ABUTMENT ;
    PORT
      LAYER M4 ;
      RECT 0.000 298.068 0.072 298.092 ;
    END
  END w0_wd_in[13]
  PIN w0_wd_in[14]
    DIRECTION INPUT ;
    USE SIGNAL ;
    SHAPE ABUTMENT ;
    PORT
      LAYER M4 ;
      RECT 0.000 300.180 0.072 300.204 ;
    END
  END w0_wd_in[14]
  PIN w0_wd_in[15]
    DIRECTION INPUT ;
    USE SIGNAL ;
    SHAPE ABUTMENT ;
    PORT
      LAYER M4 ;
      RECT 0.000 302.292 0.072 302.316 ;
    END
  END w0_wd_in[15]
  PIN w0_wd_in[16]
    DIRECTION INPUT ;
    USE SIGNAL ;
    SHAPE ABUTMENT ;
    PORT
      LAYER M4 ;
      RECT 0.000 304.404 0.072 304.428 ;
    END
  END w0_wd_in[16]
  PIN w0_wd_in[17]
    DIRECTION INPUT ;
    USE SIGNAL ;
    SHAPE ABUTMENT ;
    PORT
      LAYER M4 ;
      RECT 0.000 306.516 0.072 306.540 ;
    END
  END w0_wd_in[17]
  PIN w0_wd_in[18]
    DIRECTION INPUT ;
    USE SIGNAL ;
    SHAPE ABUTMENT ;
    PORT
      LAYER M4 ;
      RECT 0.000 308.628 0.072 308.652 ;
    END
  END w0_wd_in[18]
  PIN w0_wd_in[19]
    DIRECTION INPUT ;
    USE SIGNAL ;
    SHAPE ABUTMENT ;
    PORT
      LAYER M4 ;
      RECT 0.000 310.740 0.072 310.764 ;
    END
  END w0_wd_in[19]
  PIN w0_wd_in[20]
    DIRECTION INPUT ;
    USE SIGNAL ;
    SHAPE ABUTMENT ;
    PORT
      LAYER M4 ;
      RECT 0.000 312.852 0.072 312.876 ;
    END
  END w0_wd_in[20]
  PIN w0_wd_in[21]
    DIRECTION INPUT ;
    USE SIGNAL ;
    SHAPE ABUTMENT ;
    PORT
      LAYER M4 ;
      RECT 0.000 314.964 0.072 314.988 ;
    END
  END w0_wd_in[21]
  PIN w0_wd_in[22]
    DIRECTION INPUT ;
    USE SIGNAL ;
    SHAPE ABUTMENT ;
    PORT
      LAYER M4 ;
      RECT 0.000 317.076 0.072 317.100 ;
    END
  END w0_wd_in[22]
  PIN w0_wd_in[23]
    DIRECTION INPUT ;
    USE SIGNAL ;
    SHAPE ABUTMENT ;
    PORT
      LAYER M4 ;
      RECT 0.000 319.188 0.072 319.212 ;
    END
  END w0_wd_in[23]
  PIN w0_wd_in[24]
    DIRECTION INPUT ;
    USE SIGNAL ;
    SHAPE ABUTMENT ;
    PORT
      LAYER M4 ;
      RECT 0.000 321.300 0.072 321.324 ;
    END
  END w0_wd_in[24]
  PIN w0_wd_in[25]
    DIRECTION INPUT ;
    USE SIGNAL ;
    SHAPE ABUTMENT ;
    PORT
      LAYER M4 ;
      RECT 0.000 323.412 0.072 323.436 ;
    END
  END w0_wd_in[25]
  PIN w0_wd_in[26]
    DIRECTION INPUT ;
    USE SIGNAL ;
    SHAPE ABUTMENT ;
    PORT
      LAYER M4 ;
      RECT 0.000 325.524 0.072 325.548 ;
    END
  END w0_wd_in[26]
  PIN w0_wd_in[27]
    DIRECTION INPUT ;
    USE SIGNAL ;
    SHAPE ABUTMENT ;
    PORT
      LAYER M4 ;
      RECT 0.000 327.636 0.072 327.660 ;
    END
  END w0_wd_in[27]
  PIN w0_wd_in[28]
    DIRECTION INPUT ;
    USE SIGNAL ;
    SHAPE ABUTMENT ;
    PORT
      LAYER M4 ;
      RECT 0.000 329.748 0.072 329.772 ;
    END
  END w0_wd_in[28]
  PIN w0_wd_in[29]
    DIRECTION INPUT ;
    USE SIGNAL ;
    SHAPE ABUTMENT ;
    PORT
      LAYER M4 ;
      RECT 0.000 331.860 0.072 331.884 ;
    END
  END w0_wd_in[29]
  PIN w0_wd_in[30]
    DIRECTION INPUT ;
    USE SIGNAL ;
    SHAPE ABUTMENT ;
    PORT
      LAYER M4 ;
      RECT 0.000 333.972 0.072 333.996 ;
    END
  END w0_wd_in[30]
  PIN w0_wd_in[31]
    DIRECTION INPUT ;
    USE SIGNAL ;
    SHAPE ABUTMENT ;
    PORT
      LAYER M4 ;
      RECT 0.000 336.084 0.072 336.108 ;
    END
  END w0_wd_in[31]
  PIN w0_wd_in[32]
    DIRECTION INPUT ;
    USE SIGNAL ;
    SHAPE ABUTMENT ;
    PORT
      LAYER M4 ;
      RECT 0.000 338.196 0.072 338.220 ;
    END
  END w0_wd_in[32]
  PIN w0_wd_in[33]
    DIRECTION INPUT ;
    USE SIGNAL ;
    SHAPE ABUTMENT ;
    PORT
      LAYER M4 ;
      RECT 0.000 340.308 0.072 340.332 ;
    END
  END w0_wd_in[33]
  PIN w0_wd_in[34]
    DIRECTION INPUT ;
    USE SIGNAL ;
    SHAPE ABUTMENT ;
    PORT
      LAYER M4 ;
      RECT 0.000 342.420 0.072 342.444 ;
    END
  END w0_wd_in[34]
  PIN w0_wd_in[35]
    DIRECTION INPUT ;
    USE SIGNAL ;
    SHAPE ABUTMENT ;
    PORT
      LAYER M4 ;
      RECT 0.000 344.532 0.072 344.556 ;
    END
  END w0_wd_in[35]
  PIN w0_wd_in[36]
    DIRECTION INPUT ;
    USE SIGNAL ;
    SHAPE ABUTMENT ;
    PORT
      LAYER M4 ;
      RECT 0.000 346.644 0.072 346.668 ;
    END
  END w0_wd_in[36]
  PIN w0_wd_in[37]
    DIRECTION INPUT ;
    USE SIGNAL ;
    SHAPE ABUTMENT ;
    PORT
      LAYER M4 ;
      RECT 0.000 348.756 0.072 348.780 ;
    END
  END w0_wd_in[37]
  PIN w0_wd_in[38]
    DIRECTION INPUT ;
    USE SIGNAL ;
    SHAPE ABUTMENT ;
    PORT
      LAYER M4 ;
      RECT 0.000 350.868 0.072 350.892 ;
    END
  END w0_wd_in[38]
  PIN w0_wd_in[39]
    DIRECTION INPUT ;
    USE SIGNAL ;
    SHAPE ABUTMENT ;
    PORT
      LAYER M4 ;
      RECT 0.000 352.980 0.072 353.004 ;
    END
  END w0_wd_in[39]
  PIN w0_wd_in[40]
    DIRECTION INPUT ;
    USE SIGNAL ;
    SHAPE ABUTMENT ;
    PORT
      LAYER M4 ;
      RECT 0.000 355.092 0.072 355.116 ;
    END
  END w0_wd_in[40]
  PIN w0_wd_in[41]
    DIRECTION INPUT ;
    USE SIGNAL ;
    SHAPE ABUTMENT ;
    PORT
      LAYER M4 ;
      RECT 0.000 357.204 0.072 357.228 ;
    END
  END w0_wd_in[41]
  PIN w0_wd_in[42]
    DIRECTION INPUT ;
    USE SIGNAL ;
    SHAPE ABUTMENT ;
    PORT
      LAYER M4 ;
      RECT 0.000 359.316 0.072 359.340 ;
    END
  END w0_wd_in[42]
  PIN w0_wd_in[43]
    DIRECTION INPUT ;
    USE SIGNAL ;
    SHAPE ABUTMENT ;
    PORT
      LAYER M4 ;
      RECT 0.000 361.428 0.072 361.452 ;
    END
  END w0_wd_in[43]
  PIN w0_wd_in[44]
    DIRECTION INPUT ;
    USE SIGNAL ;
    SHAPE ABUTMENT ;
    PORT
      LAYER M4 ;
      RECT 0.000 363.540 0.072 363.564 ;
    END
  END w0_wd_in[44]
  PIN w0_wd_in[45]
    DIRECTION INPUT ;
    USE SIGNAL ;
    SHAPE ABUTMENT ;
    PORT
      LAYER M4 ;
      RECT 0.000 365.652 0.072 365.676 ;
    END
  END w0_wd_in[45]
  PIN w0_wd_in[46]
    DIRECTION INPUT ;
    USE SIGNAL ;
    SHAPE ABUTMENT ;
    PORT
      LAYER M4 ;
      RECT 0.000 367.764 0.072 367.788 ;
    END
  END w0_wd_in[46]
  PIN w0_wd_in[47]
    DIRECTION INPUT ;
    USE SIGNAL ;
    SHAPE ABUTMENT ;
    PORT
      LAYER M4 ;
      RECT 0.000 369.876 0.072 369.900 ;
    END
  END w0_wd_in[47]
  PIN w0_wd_in[48]
    DIRECTION INPUT ;
    USE SIGNAL ;
    SHAPE ABUTMENT ;
    PORT
      LAYER M4 ;
      RECT 0.000 371.988 0.072 372.012 ;
    END
  END w0_wd_in[48]
  PIN w0_wd_in[49]
    DIRECTION INPUT ;
    USE SIGNAL ;
    SHAPE ABUTMENT ;
    PORT
      LAYER M4 ;
      RECT 0.000 374.100 0.072 374.124 ;
    END
  END w0_wd_in[49]
  PIN w0_wd_in[50]
    DIRECTION INPUT ;
    USE SIGNAL ;
    SHAPE ABUTMENT ;
    PORT
      LAYER M4 ;
      RECT 0.000 376.212 0.072 376.236 ;
    END
  END w0_wd_in[50]
  PIN w0_wd_in[51]
    DIRECTION INPUT ;
    USE SIGNAL ;
    SHAPE ABUTMENT ;
    PORT
      LAYER M4 ;
      RECT 0.000 378.324 0.072 378.348 ;
    END
  END w0_wd_in[51]
  PIN w0_wd_in[52]
    DIRECTION INPUT ;
    USE SIGNAL ;
    SHAPE ABUTMENT ;
    PORT
      LAYER M4 ;
      RECT 0.000 380.436 0.072 380.460 ;
    END
  END w0_wd_in[52]
  PIN w0_wd_in[53]
    DIRECTION INPUT ;
    USE SIGNAL ;
    SHAPE ABUTMENT ;
    PORT
      LAYER M4 ;
      RECT 0.000 382.548 0.072 382.572 ;
    END
  END w0_wd_in[53]
  PIN w0_wd_in[54]
    DIRECTION INPUT ;
    USE SIGNAL ;
    SHAPE ABUTMENT ;
    PORT
      LAYER M4 ;
      RECT 0.000 384.660 0.072 384.684 ;
    END
  END w0_wd_in[54]
  PIN w0_wd_in[55]
    DIRECTION INPUT ;
    USE SIGNAL ;
    SHAPE ABUTMENT ;
    PORT
      LAYER M4 ;
      RECT 0.000 386.772 0.072 386.796 ;
    END
  END w0_wd_in[55]
  PIN w0_wd_in[56]
    DIRECTION INPUT ;
    USE SIGNAL ;
    SHAPE ABUTMENT ;
    PORT
      LAYER M4 ;
      RECT 0.000 388.884 0.072 388.908 ;
    END
  END w0_wd_in[56]
  PIN w0_wd_in[57]
    DIRECTION INPUT ;
    USE SIGNAL ;
    SHAPE ABUTMENT ;
    PORT
      LAYER M4 ;
      RECT 0.000 390.996 0.072 391.020 ;
    END
  END w0_wd_in[57]
  PIN w0_wd_in[58]
    DIRECTION INPUT ;
    USE SIGNAL ;
    SHAPE ABUTMENT ;
    PORT
      LAYER M4 ;
      RECT 0.000 393.108 0.072 393.132 ;
    END
  END w0_wd_in[58]
  PIN w0_wd_in[59]
    DIRECTION INPUT ;
    USE SIGNAL ;
    SHAPE ABUTMENT ;
    PORT
      LAYER M4 ;
      RECT 0.000 395.220 0.072 395.244 ;
    END
  END w0_wd_in[59]
  PIN w0_wd_in[60]
    DIRECTION INPUT ;
    USE SIGNAL ;
    SHAPE ABUTMENT ;
    PORT
      LAYER M4 ;
      RECT 0.000 397.332 0.072 397.356 ;
    END
  END w0_wd_in[60]
  PIN w0_wd_in[61]
    DIRECTION INPUT ;
    USE SIGNAL ;
    SHAPE ABUTMENT ;
    PORT
      LAYER M4 ;
      RECT 0.000 399.444 0.072 399.468 ;
    END
  END w0_wd_in[61]
  PIN w0_wd_in[62]
    DIRECTION INPUT ;
    USE SIGNAL ;
    SHAPE ABUTMENT ;
    PORT
      LAYER M4 ;
      RECT 0.000 401.556 0.072 401.580 ;
    END
  END w0_wd_in[62]
  PIN w0_wd_in[63]
    DIRECTION INPUT ;
    USE SIGNAL ;
    SHAPE ABUTMENT ;
    PORT
      LAYER M4 ;
      RECT 0.000 403.668 0.072 403.692 ;
    END
  END w0_wd_in[63]
  PIN w0_wd_in[64]
    DIRECTION INPUT ;
    USE SIGNAL ;
    SHAPE ABUTMENT ;
    PORT
      LAYER M4 ;
      RECT 0.000 405.780 0.072 405.804 ;
    END
  END w0_wd_in[64]
  PIN w0_wd_in[65]
    DIRECTION INPUT ;
    USE SIGNAL ;
    SHAPE ABUTMENT ;
    PORT
      LAYER M4 ;
      RECT 0.000 407.892 0.072 407.916 ;
    END
  END w0_wd_in[65]
  PIN w0_wd_in[66]
    DIRECTION INPUT ;
    USE SIGNAL ;
    SHAPE ABUTMENT ;
    PORT
      LAYER M4 ;
      RECT 0.000 410.004 0.072 410.028 ;
    END
  END w0_wd_in[66]
  PIN w0_wd_in[67]
    DIRECTION INPUT ;
    USE SIGNAL ;
    SHAPE ABUTMENT ;
    PORT
      LAYER M4 ;
      RECT 0.000 412.116 0.072 412.140 ;
    END
  END w0_wd_in[67]
  PIN w0_wd_in[68]
    DIRECTION INPUT ;
    USE SIGNAL ;
    SHAPE ABUTMENT ;
    PORT
      LAYER M4 ;
      RECT 0.000 414.228 0.072 414.252 ;
    END
  END w0_wd_in[68]
  PIN w0_wd_in[69]
    DIRECTION INPUT ;
    USE SIGNAL ;
    SHAPE ABUTMENT ;
    PORT
      LAYER M4 ;
      RECT 0.000 416.340 0.072 416.364 ;
    END
  END w0_wd_in[69]
  PIN w0_wd_in[70]
    DIRECTION INPUT ;
    USE SIGNAL ;
    SHAPE ABUTMENT ;
    PORT
      LAYER M4 ;
      RECT 0.000 418.452 0.072 418.476 ;
    END
  END w0_wd_in[70]
  PIN w0_wd_in[71]
    DIRECTION INPUT ;
    USE SIGNAL ;
    SHAPE ABUTMENT ;
    PORT
      LAYER M4 ;
      RECT 0.000 420.564 0.072 420.588 ;
    END
  END w0_wd_in[71]
  PIN w0_wd_in[72]
    DIRECTION INPUT ;
    USE SIGNAL ;
    SHAPE ABUTMENT ;
    PORT
      LAYER M4 ;
      RECT 0.000 422.676 0.072 422.700 ;
    END
  END w0_wd_in[72]
  PIN w0_wd_in[73]
    DIRECTION INPUT ;
    USE SIGNAL ;
    SHAPE ABUTMENT ;
    PORT
      LAYER M4 ;
      RECT 0.000 424.788 0.072 424.812 ;
    END
  END w0_wd_in[73]
  PIN w0_wd_in[74]
    DIRECTION INPUT ;
    USE SIGNAL ;
    SHAPE ABUTMENT ;
    PORT
      LAYER M4 ;
      RECT 0.000 426.900 0.072 426.924 ;
    END
  END w0_wd_in[74]
  PIN w0_wd_in[75]
    DIRECTION INPUT ;
    USE SIGNAL ;
    SHAPE ABUTMENT ;
    PORT
      LAYER M4 ;
      RECT 0.000 429.012 0.072 429.036 ;
    END
  END w0_wd_in[75]
  PIN w0_wd_in[76]
    DIRECTION INPUT ;
    USE SIGNAL ;
    SHAPE ABUTMENT ;
    PORT
      LAYER M4 ;
      RECT 0.000 431.124 0.072 431.148 ;
    END
  END w0_wd_in[76]
  PIN w0_wd_in[77]
    DIRECTION INPUT ;
    USE SIGNAL ;
    SHAPE ABUTMENT ;
    PORT
      LAYER M4 ;
      RECT 0.000 433.236 0.072 433.260 ;
    END
  END w0_wd_in[77]
  PIN w0_wd_in[78]
    DIRECTION INPUT ;
    USE SIGNAL ;
    SHAPE ABUTMENT ;
    PORT
      LAYER M4 ;
      RECT 0.000 435.348 0.072 435.372 ;
    END
  END w0_wd_in[78]
  PIN w0_wd_in[79]
    DIRECTION INPUT ;
    USE SIGNAL ;
    SHAPE ABUTMENT ;
    PORT
      LAYER M4 ;
      RECT 0.000 437.460 0.072 437.484 ;
    END
  END w0_wd_in[79]
  PIN w0_wd_in[80]
    DIRECTION INPUT ;
    USE SIGNAL ;
    SHAPE ABUTMENT ;
    PORT
      LAYER M4 ;
      RECT 0.000 439.572 0.072 439.596 ;
    END
  END w0_wd_in[80]
  PIN w0_wd_in[81]
    DIRECTION INPUT ;
    USE SIGNAL ;
    SHAPE ABUTMENT ;
    PORT
      LAYER M4 ;
      RECT 0.000 441.684 0.072 441.708 ;
    END
  END w0_wd_in[81]
  PIN w0_wd_in[82]
    DIRECTION INPUT ;
    USE SIGNAL ;
    SHAPE ABUTMENT ;
    PORT
      LAYER M4 ;
      RECT 0.000 443.796 0.072 443.820 ;
    END
  END w0_wd_in[82]
  PIN w0_wd_in[83]
    DIRECTION INPUT ;
    USE SIGNAL ;
    SHAPE ABUTMENT ;
    PORT
      LAYER M4 ;
      RECT 0.000 445.908 0.072 445.932 ;
    END
  END w0_wd_in[83]
  PIN w0_wd_in[84]
    DIRECTION INPUT ;
    USE SIGNAL ;
    SHAPE ABUTMENT ;
    PORT
      LAYER M4 ;
      RECT 0.000 448.020 0.072 448.044 ;
    END
  END w0_wd_in[84]
  PIN w0_wd_in[85]
    DIRECTION INPUT ;
    USE SIGNAL ;
    SHAPE ABUTMENT ;
    PORT
      LAYER M4 ;
      RECT 0.000 450.132 0.072 450.156 ;
    END
  END w0_wd_in[85]
  PIN w0_wd_in[86]
    DIRECTION INPUT ;
    USE SIGNAL ;
    SHAPE ABUTMENT ;
    PORT
      LAYER M4 ;
      RECT 0.000 452.244 0.072 452.268 ;
    END
  END w0_wd_in[86]
  PIN w0_wd_in[87]
    DIRECTION INPUT ;
    USE SIGNAL ;
    SHAPE ABUTMENT ;
    PORT
      LAYER M4 ;
      RECT 0.000 454.356 0.072 454.380 ;
    END
  END w0_wd_in[87]
  PIN w0_wd_in[88]
    DIRECTION INPUT ;
    USE SIGNAL ;
    SHAPE ABUTMENT ;
    PORT
      LAYER M4 ;
      RECT 0.000 456.468 0.072 456.492 ;
    END
  END w0_wd_in[88]
  PIN w0_wd_in[89]
    DIRECTION INPUT ;
    USE SIGNAL ;
    SHAPE ABUTMENT ;
    PORT
      LAYER M4 ;
      RECT 0.000 458.580 0.072 458.604 ;
    END
  END w0_wd_in[89]
  PIN w0_wd_in[90]
    DIRECTION INPUT ;
    USE SIGNAL ;
    SHAPE ABUTMENT ;
    PORT
      LAYER M4 ;
      RECT 0.000 460.692 0.072 460.716 ;
    END
  END w0_wd_in[90]
  PIN w0_wd_in[91]
    DIRECTION INPUT ;
    USE SIGNAL ;
    SHAPE ABUTMENT ;
    PORT
      LAYER M4 ;
      RECT 0.000 462.804 0.072 462.828 ;
    END
  END w0_wd_in[91]
  PIN w0_wd_in[92]
    DIRECTION INPUT ;
    USE SIGNAL ;
    SHAPE ABUTMENT ;
    PORT
      LAYER M4 ;
      RECT 0.000 464.916 0.072 464.940 ;
    END
  END w0_wd_in[92]
  PIN w0_wd_in[93]
    DIRECTION INPUT ;
    USE SIGNAL ;
    SHAPE ABUTMENT ;
    PORT
      LAYER M4 ;
      RECT 0.000 467.028 0.072 467.052 ;
    END
  END w0_wd_in[93]
  PIN w0_wd_in[94]
    DIRECTION INPUT ;
    USE SIGNAL ;
    SHAPE ABUTMENT ;
    PORT
      LAYER M4 ;
      RECT 0.000 469.140 0.072 469.164 ;
    END
  END w0_wd_in[94]
  PIN w0_wd_in[95]
    DIRECTION INPUT ;
    USE SIGNAL ;
    SHAPE ABUTMENT ;
    PORT
      LAYER M4 ;
      RECT 0.000 471.252 0.072 471.276 ;
    END
  END w0_wd_in[95]
  PIN w0_wd_in[96]
    DIRECTION INPUT ;
    USE SIGNAL ;
    SHAPE ABUTMENT ;
    PORT
      LAYER M4 ;
      RECT 0.000 473.364 0.072 473.388 ;
    END
  END w0_wd_in[96]
  PIN w0_wd_in[97]
    DIRECTION INPUT ;
    USE SIGNAL ;
    SHAPE ABUTMENT ;
    PORT
      LAYER M4 ;
      RECT 0.000 475.476 0.072 475.500 ;
    END
  END w0_wd_in[97]
  PIN w0_wd_in[98]
    DIRECTION INPUT ;
    USE SIGNAL ;
    SHAPE ABUTMENT ;
    PORT
      LAYER M4 ;
      RECT 0.000 477.588 0.072 477.612 ;
    END
  END w0_wd_in[98]
  PIN w0_wd_in[99]
    DIRECTION INPUT ;
    USE SIGNAL ;
    SHAPE ABUTMENT ;
    PORT
      LAYER M4 ;
      RECT 0.000 479.700 0.072 479.724 ;
    END
  END w0_wd_in[99]
  PIN w0_wd_in[100]
    DIRECTION INPUT ;
    USE SIGNAL ;
    SHAPE ABUTMENT ;
    PORT
      LAYER M4 ;
      RECT 0.000 481.812 0.072 481.836 ;
    END
  END w0_wd_in[100]
  PIN w0_wd_in[101]
    DIRECTION INPUT ;
    USE SIGNAL ;
    SHAPE ABUTMENT ;
    PORT
      LAYER M4 ;
      RECT 0.000 483.924 0.072 483.948 ;
    END
  END w0_wd_in[101]
  PIN w0_wd_in[102]
    DIRECTION INPUT ;
    USE SIGNAL ;
    SHAPE ABUTMENT ;
    PORT
      LAYER M4 ;
      RECT 0.000 486.036 0.072 486.060 ;
    END
  END w0_wd_in[102]
  PIN w0_wd_in[103]
    DIRECTION INPUT ;
    USE SIGNAL ;
    SHAPE ABUTMENT ;
    PORT
      LAYER M4 ;
      RECT 0.000 488.148 0.072 488.172 ;
    END
  END w0_wd_in[103]
  PIN w0_wd_in[104]
    DIRECTION INPUT ;
    USE SIGNAL ;
    SHAPE ABUTMENT ;
    PORT
      LAYER M4 ;
      RECT 0.000 490.260 0.072 490.284 ;
    END
  END w0_wd_in[104]
  PIN w0_wd_in[105]
    DIRECTION INPUT ;
    USE SIGNAL ;
    SHAPE ABUTMENT ;
    PORT
      LAYER M4 ;
      RECT 0.000 492.372 0.072 492.396 ;
    END
  END w0_wd_in[105]
  PIN w0_wd_in[106]
    DIRECTION INPUT ;
    USE SIGNAL ;
    SHAPE ABUTMENT ;
    PORT
      LAYER M4 ;
      RECT 0.000 494.484 0.072 494.508 ;
    END
  END w0_wd_in[106]
  PIN w0_wd_in[107]
    DIRECTION INPUT ;
    USE SIGNAL ;
    SHAPE ABUTMENT ;
    PORT
      LAYER M4 ;
      RECT 0.000 496.596 0.072 496.620 ;
    END
  END w0_wd_in[107]
  PIN w0_wd_in[108]
    DIRECTION INPUT ;
    USE SIGNAL ;
    SHAPE ABUTMENT ;
    PORT
      LAYER M4 ;
      RECT 0.000 498.708 0.072 498.732 ;
    END
  END w0_wd_in[108]
  PIN w0_wd_in[109]
    DIRECTION INPUT ;
    USE SIGNAL ;
    SHAPE ABUTMENT ;
    PORT
      LAYER M4 ;
      RECT 0.000 500.820 0.072 500.844 ;
    END
  END w0_wd_in[109]
  PIN w0_wd_in[110]
    DIRECTION INPUT ;
    USE SIGNAL ;
    SHAPE ABUTMENT ;
    PORT
      LAYER M4 ;
      RECT 0.000 502.932 0.072 502.956 ;
    END
  END w0_wd_in[110]
  PIN w0_wd_in[111]
    DIRECTION INPUT ;
    USE SIGNAL ;
    SHAPE ABUTMENT ;
    PORT
      LAYER M4 ;
      RECT 0.000 505.044 0.072 505.068 ;
    END
  END w0_wd_in[111]
  PIN w0_wd_in[112]
    DIRECTION INPUT ;
    USE SIGNAL ;
    SHAPE ABUTMENT ;
    PORT
      LAYER M4 ;
      RECT 0.000 507.156 0.072 507.180 ;
    END
  END w0_wd_in[112]
  PIN w0_wd_in[113]
    DIRECTION INPUT ;
    USE SIGNAL ;
    SHAPE ABUTMENT ;
    PORT
      LAYER M4 ;
      RECT 0.000 509.268 0.072 509.292 ;
    END
  END w0_wd_in[113]
  PIN w0_wd_in[114]
    DIRECTION INPUT ;
    USE SIGNAL ;
    SHAPE ABUTMENT ;
    PORT
      LAYER M4 ;
      RECT 0.000 511.380 0.072 511.404 ;
    END
  END w0_wd_in[114]
  PIN w0_wd_in[115]
    DIRECTION INPUT ;
    USE SIGNAL ;
    SHAPE ABUTMENT ;
    PORT
      LAYER M4 ;
      RECT 0.000 513.492 0.072 513.516 ;
    END
  END w0_wd_in[115]
  PIN w0_wd_in[116]
    DIRECTION INPUT ;
    USE SIGNAL ;
    SHAPE ABUTMENT ;
    PORT
      LAYER M4 ;
      RECT 0.000 515.604 0.072 515.628 ;
    END
  END w0_wd_in[116]
  PIN w0_wd_in[117]
    DIRECTION INPUT ;
    USE SIGNAL ;
    SHAPE ABUTMENT ;
    PORT
      LAYER M4 ;
      RECT 0.000 517.716 0.072 517.740 ;
    END
  END w0_wd_in[117]
  PIN w0_wd_in[118]
    DIRECTION INPUT ;
    USE SIGNAL ;
    SHAPE ABUTMENT ;
    PORT
      LAYER M4 ;
      RECT 0.000 519.828 0.072 519.852 ;
    END
  END w0_wd_in[118]
  PIN w0_wd_in[119]
    DIRECTION INPUT ;
    USE SIGNAL ;
    SHAPE ABUTMENT ;
    PORT
      LAYER M4 ;
      RECT 0.000 521.940 0.072 521.964 ;
    END
  END w0_wd_in[119]
  PIN w0_wd_in[120]
    DIRECTION INPUT ;
    USE SIGNAL ;
    SHAPE ABUTMENT ;
    PORT
      LAYER M4 ;
      RECT 0.000 524.052 0.072 524.076 ;
    END
  END w0_wd_in[120]
  PIN w0_wd_in[121]
    DIRECTION INPUT ;
    USE SIGNAL ;
    SHAPE ABUTMENT ;
    PORT
      LAYER M4 ;
      RECT 0.000 526.164 0.072 526.188 ;
    END
  END w0_wd_in[121]
  PIN w0_wd_in[122]
    DIRECTION INPUT ;
    USE SIGNAL ;
    SHAPE ABUTMENT ;
    PORT
      LAYER M4 ;
      RECT 0.000 528.276 0.072 528.300 ;
    END
  END w0_wd_in[122]
  PIN w0_wd_in[123]
    DIRECTION INPUT ;
    USE SIGNAL ;
    SHAPE ABUTMENT ;
    PORT
      LAYER M4 ;
      RECT 0.000 530.388 0.072 530.412 ;
    END
  END w0_wd_in[123]
  PIN w0_wd_in[124]
    DIRECTION INPUT ;
    USE SIGNAL ;
    SHAPE ABUTMENT ;
    PORT
      LAYER M4 ;
      RECT 0.000 532.500 0.072 532.524 ;
    END
  END w0_wd_in[124]
  PIN w0_wd_in[125]
    DIRECTION INPUT ;
    USE SIGNAL ;
    SHAPE ABUTMENT ;
    PORT
      LAYER M4 ;
      RECT 0.000 534.612 0.072 534.636 ;
    END
  END w0_wd_in[125]
  PIN w0_wd_in[126]
    DIRECTION INPUT ;
    USE SIGNAL ;
    SHAPE ABUTMENT ;
    PORT
      LAYER M4 ;
      RECT 0.000 536.724 0.072 536.748 ;
    END
  END w0_wd_in[126]
  PIN w0_wd_in[127]
    DIRECTION INPUT ;
    USE SIGNAL ;
    SHAPE ABUTMENT ;
    PORT
      LAYER M4 ;
      RECT 0.000 538.836 0.072 538.860 ;
    END
  END w0_wd_in[127]
  PIN w0_wd_in[128]
    DIRECTION INPUT ;
    USE SIGNAL ;
    SHAPE ABUTMENT ;
    PORT
      LAYER M4 ;
      RECT 906.783 270.612 906.855 270.636 ;
    END
  END w0_wd_in[128]
  PIN w0_wd_in[129]
    DIRECTION INPUT ;
    USE SIGNAL ;
    SHAPE ABUTMENT ;
    PORT
      LAYER M4 ;
      RECT 906.783 272.724 906.855 272.748 ;
    END
  END w0_wd_in[129]
  PIN w0_wd_in[130]
    DIRECTION INPUT ;
    USE SIGNAL ;
    SHAPE ABUTMENT ;
    PORT
      LAYER M4 ;
      RECT 906.783 274.836 906.855 274.860 ;
    END
  END w0_wd_in[130]
  PIN w0_wd_in[131]
    DIRECTION INPUT ;
    USE SIGNAL ;
    SHAPE ABUTMENT ;
    PORT
      LAYER M4 ;
      RECT 906.783 276.948 906.855 276.972 ;
    END
  END w0_wd_in[131]
  PIN w0_wd_in[132]
    DIRECTION INPUT ;
    USE SIGNAL ;
    SHAPE ABUTMENT ;
    PORT
      LAYER M4 ;
      RECT 906.783 279.060 906.855 279.084 ;
    END
  END w0_wd_in[132]
  PIN w0_wd_in[133]
    DIRECTION INPUT ;
    USE SIGNAL ;
    SHAPE ABUTMENT ;
    PORT
      LAYER M4 ;
      RECT 906.783 281.172 906.855 281.196 ;
    END
  END w0_wd_in[133]
  PIN w0_wd_in[134]
    DIRECTION INPUT ;
    USE SIGNAL ;
    SHAPE ABUTMENT ;
    PORT
      LAYER M4 ;
      RECT 906.783 283.284 906.855 283.308 ;
    END
  END w0_wd_in[134]
  PIN w0_wd_in[135]
    DIRECTION INPUT ;
    USE SIGNAL ;
    SHAPE ABUTMENT ;
    PORT
      LAYER M4 ;
      RECT 906.783 285.396 906.855 285.420 ;
    END
  END w0_wd_in[135]
  PIN w0_wd_in[136]
    DIRECTION INPUT ;
    USE SIGNAL ;
    SHAPE ABUTMENT ;
    PORT
      LAYER M4 ;
      RECT 906.783 287.508 906.855 287.532 ;
    END
  END w0_wd_in[136]
  PIN w0_wd_in[137]
    DIRECTION INPUT ;
    USE SIGNAL ;
    SHAPE ABUTMENT ;
    PORT
      LAYER M4 ;
      RECT 906.783 289.620 906.855 289.644 ;
    END
  END w0_wd_in[137]
  PIN w0_wd_in[138]
    DIRECTION INPUT ;
    USE SIGNAL ;
    SHAPE ABUTMENT ;
    PORT
      LAYER M4 ;
      RECT 906.783 291.732 906.855 291.756 ;
    END
  END w0_wd_in[138]
  PIN w0_wd_in[139]
    DIRECTION INPUT ;
    USE SIGNAL ;
    SHAPE ABUTMENT ;
    PORT
      LAYER M4 ;
      RECT 906.783 293.844 906.855 293.868 ;
    END
  END w0_wd_in[139]
  PIN w0_wd_in[140]
    DIRECTION INPUT ;
    USE SIGNAL ;
    SHAPE ABUTMENT ;
    PORT
      LAYER M4 ;
      RECT 906.783 295.956 906.855 295.980 ;
    END
  END w0_wd_in[140]
  PIN w0_wd_in[141]
    DIRECTION INPUT ;
    USE SIGNAL ;
    SHAPE ABUTMENT ;
    PORT
      LAYER M4 ;
      RECT 906.783 298.068 906.855 298.092 ;
    END
  END w0_wd_in[141]
  PIN w0_wd_in[142]
    DIRECTION INPUT ;
    USE SIGNAL ;
    SHAPE ABUTMENT ;
    PORT
      LAYER M4 ;
      RECT 906.783 300.180 906.855 300.204 ;
    END
  END w0_wd_in[142]
  PIN w0_wd_in[143]
    DIRECTION INPUT ;
    USE SIGNAL ;
    SHAPE ABUTMENT ;
    PORT
      LAYER M4 ;
      RECT 906.783 302.292 906.855 302.316 ;
    END
  END w0_wd_in[143]
  PIN w0_wd_in[144]
    DIRECTION INPUT ;
    USE SIGNAL ;
    SHAPE ABUTMENT ;
    PORT
      LAYER M4 ;
      RECT 906.783 304.404 906.855 304.428 ;
    END
  END w0_wd_in[144]
  PIN w0_wd_in[145]
    DIRECTION INPUT ;
    USE SIGNAL ;
    SHAPE ABUTMENT ;
    PORT
      LAYER M4 ;
      RECT 906.783 306.516 906.855 306.540 ;
    END
  END w0_wd_in[145]
  PIN w0_wd_in[146]
    DIRECTION INPUT ;
    USE SIGNAL ;
    SHAPE ABUTMENT ;
    PORT
      LAYER M4 ;
      RECT 906.783 308.628 906.855 308.652 ;
    END
  END w0_wd_in[146]
  PIN w0_wd_in[147]
    DIRECTION INPUT ;
    USE SIGNAL ;
    SHAPE ABUTMENT ;
    PORT
      LAYER M4 ;
      RECT 906.783 310.740 906.855 310.764 ;
    END
  END w0_wd_in[147]
  PIN w0_wd_in[148]
    DIRECTION INPUT ;
    USE SIGNAL ;
    SHAPE ABUTMENT ;
    PORT
      LAYER M4 ;
      RECT 906.783 312.852 906.855 312.876 ;
    END
  END w0_wd_in[148]
  PIN w0_wd_in[149]
    DIRECTION INPUT ;
    USE SIGNAL ;
    SHAPE ABUTMENT ;
    PORT
      LAYER M4 ;
      RECT 906.783 314.964 906.855 314.988 ;
    END
  END w0_wd_in[149]
  PIN w0_wd_in[150]
    DIRECTION INPUT ;
    USE SIGNAL ;
    SHAPE ABUTMENT ;
    PORT
      LAYER M4 ;
      RECT 906.783 317.076 906.855 317.100 ;
    END
  END w0_wd_in[150]
  PIN w0_wd_in[151]
    DIRECTION INPUT ;
    USE SIGNAL ;
    SHAPE ABUTMENT ;
    PORT
      LAYER M4 ;
      RECT 906.783 319.188 906.855 319.212 ;
    END
  END w0_wd_in[151]
  PIN w0_wd_in[152]
    DIRECTION INPUT ;
    USE SIGNAL ;
    SHAPE ABUTMENT ;
    PORT
      LAYER M4 ;
      RECT 906.783 321.300 906.855 321.324 ;
    END
  END w0_wd_in[152]
  PIN w0_wd_in[153]
    DIRECTION INPUT ;
    USE SIGNAL ;
    SHAPE ABUTMENT ;
    PORT
      LAYER M4 ;
      RECT 906.783 323.412 906.855 323.436 ;
    END
  END w0_wd_in[153]
  PIN w0_wd_in[154]
    DIRECTION INPUT ;
    USE SIGNAL ;
    SHAPE ABUTMENT ;
    PORT
      LAYER M4 ;
      RECT 906.783 325.524 906.855 325.548 ;
    END
  END w0_wd_in[154]
  PIN w0_wd_in[155]
    DIRECTION INPUT ;
    USE SIGNAL ;
    SHAPE ABUTMENT ;
    PORT
      LAYER M4 ;
      RECT 906.783 327.636 906.855 327.660 ;
    END
  END w0_wd_in[155]
  PIN w0_wd_in[156]
    DIRECTION INPUT ;
    USE SIGNAL ;
    SHAPE ABUTMENT ;
    PORT
      LAYER M4 ;
      RECT 906.783 329.748 906.855 329.772 ;
    END
  END w0_wd_in[156]
  PIN w0_wd_in[157]
    DIRECTION INPUT ;
    USE SIGNAL ;
    SHAPE ABUTMENT ;
    PORT
      LAYER M4 ;
      RECT 906.783 331.860 906.855 331.884 ;
    END
  END w0_wd_in[157]
  PIN w0_wd_in[158]
    DIRECTION INPUT ;
    USE SIGNAL ;
    SHAPE ABUTMENT ;
    PORT
      LAYER M4 ;
      RECT 906.783 333.972 906.855 333.996 ;
    END
  END w0_wd_in[158]
  PIN w0_wd_in[159]
    DIRECTION INPUT ;
    USE SIGNAL ;
    SHAPE ABUTMENT ;
    PORT
      LAYER M4 ;
      RECT 906.783 336.084 906.855 336.108 ;
    END
  END w0_wd_in[159]
  PIN w0_wd_in[160]
    DIRECTION INPUT ;
    USE SIGNAL ;
    SHAPE ABUTMENT ;
    PORT
      LAYER M4 ;
      RECT 906.783 338.196 906.855 338.220 ;
    END
  END w0_wd_in[160]
  PIN w0_wd_in[161]
    DIRECTION INPUT ;
    USE SIGNAL ;
    SHAPE ABUTMENT ;
    PORT
      LAYER M4 ;
      RECT 906.783 340.308 906.855 340.332 ;
    END
  END w0_wd_in[161]
  PIN w0_wd_in[162]
    DIRECTION INPUT ;
    USE SIGNAL ;
    SHAPE ABUTMENT ;
    PORT
      LAYER M4 ;
      RECT 906.783 342.420 906.855 342.444 ;
    END
  END w0_wd_in[162]
  PIN w0_wd_in[163]
    DIRECTION INPUT ;
    USE SIGNAL ;
    SHAPE ABUTMENT ;
    PORT
      LAYER M4 ;
      RECT 906.783 344.532 906.855 344.556 ;
    END
  END w0_wd_in[163]
  PIN w0_wd_in[164]
    DIRECTION INPUT ;
    USE SIGNAL ;
    SHAPE ABUTMENT ;
    PORT
      LAYER M4 ;
      RECT 906.783 346.644 906.855 346.668 ;
    END
  END w0_wd_in[164]
  PIN w0_wd_in[165]
    DIRECTION INPUT ;
    USE SIGNAL ;
    SHAPE ABUTMENT ;
    PORT
      LAYER M4 ;
      RECT 906.783 348.756 906.855 348.780 ;
    END
  END w0_wd_in[165]
  PIN w0_wd_in[166]
    DIRECTION INPUT ;
    USE SIGNAL ;
    SHAPE ABUTMENT ;
    PORT
      LAYER M4 ;
      RECT 906.783 350.868 906.855 350.892 ;
    END
  END w0_wd_in[166]
  PIN w0_wd_in[167]
    DIRECTION INPUT ;
    USE SIGNAL ;
    SHAPE ABUTMENT ;
    PORT
      LAYER M4 ;
      RECT 906.783 352.980 906.855 353.004 ;
    END
  END w0_wd_in[167]
  PIN w0_wd_in[168]
    DIRECTION INPUT ;
    USE SIGNAL ;
    SHAPE ABUTMENT ;
    PORT
      LAYER M4 ;
      RECT 906.783 355.092 906.855 355.116 ;
    END
  END w0_wd_in[168]
  PIN w0_wd_in[169]
    DIRECTION INPUT ;
    USE SIGNAL ;
    SHAPE ABUTMENT ;
    PORT
      LAYER M4 ;
      RECT 906.783 357.204 906.855 357.228 ;
    END
  END w0_wd_in[169]
  PIN w0_wd_in[170]
    DIRECTION INPUT ;
    USE SIGNAL ;
    SHAPE ABUTMENT ;
    PORT
      LAYER M4 ;
      RECT 906.783 359.316 906.855 359.340 ;
    END
  END w0_wd_in[170]
  PIN w0_wd_in[171]
    DIRECTION INPUT ;
    USE SIGNAL ;
    SHAPE ABUTMENT ;
    PORT
      LAYER M4 ;
      RECT 906.783 361.428 906.855 361.452 ;
    END
  END w0_wd_in[171]
  PIN w0_wd_in[172]
    DIRECTION INPUT ;
    USE SIGNAL ;
    SHAPE ABUTMENT ;
    PORT
      LAYER M4 ;
      RECT 906.783 363.540 906.855 363.564 ;
    END
  END w0_wd_in[172]
  PIN w0_wd_in[173]
    DIRECTION INPUT ;
    USE SIGNAL ;
    SHAPE ABUTMENT ;
    PORT
      LAYER M4 ;
      RECT 906.783 365.652 906.855 365.676 ;
    END
  END w0_wd_in[173]
  PIN w0_wd_in[174]
    DIRECTION INPUT ;
    USE SIGNAL ;
    SHAPE ABUTMENT ;
    PORT
      LAYER M4 ;
      RECT 906.783 367.764 906.855 367.788 ;
    END
  END w0_wd_in[174]
  PIN w0_wd_in[175]
    DIRECTION INPUT ;
    USE SIGNAL ;
    SHAPE ABUTMENT ;
    PORT
      LAYER M4 ;
      RECT 906.783 369.876 906.855 369.900 ;
    END
  END w0_wd_in[175]
  PIN w0_wd_in[176]
    DIRECTION INPUT ;
    USE SIGNAL ;
    SHAPE ABUTMENT ;
    PORT
      LAYER M4 ;
      RECT 906.783 371.988 906.855 372.012 ;
    END
  END w0_wd_in[176]
  PIN w0_wd_in[177]
    DIRECTION INPUT ;
    USE SIGNAL ;
    SHAPE ABUTMENT ;
    PORT
      LAYER M4 ;
      RECT 906.783 374.100 906.855 374.124 ;
    END
  END w0_wd_in[177]
  PIN w0_wd_in[178]
    DIRECTION INPUT ;
    USE SIGNAL ;
    SHAPE ABUTMENT ;
    PORT
      LAYER M4 ;
      RECT 906.783 376.212 906.855 376.236 ;
    END
  END w0_wd_in[178]
  PIN w0_wd_in[179]
    DIRECTION INPUT ;
    USE SIGNAL ;
    SHAPE ABUTMENT ;
    PORT
      LAYER M4 ;
      RECT 906.783 378.324 906.855 378.348 ;
    END
  END w0_wd_in[179]
  PIN w0_wd_in[180]
    DIRECTION INPUT ;
    USE SIGNAL ;
    SHAPE ABUTMENT ;
    PORT
      LAYER M4 ;
      RECT 906.783 380.436 906.855 380.460 ;
    END
  END w0_wd_in[180]
  PIN w0_wd_in[181]
    DIRECTION INPUT ;
    USE SIGNAL ;
    SHAPE ABUTMENT ;
    PORT
      LAYER M4 ;
      RECT 906.783 382.548 906.855 382.572 ;
    END
  END w0_wd_in[181]
  PIN w0_wd_in[182]
    DIRECTION INPUT ;
    USE SIGNAL ;
    SHAPE ABUTMENT ;
    PORT
      LAYER M4 ;
      RECT 906.783 384.660 906.855 384.684 ;
    END
  END w0_wd_in[182]
  PIN w0_wd_in[183]
    DIRECTION INPUT ;
    USE SIGNAL ;
    SHAPE ABUTMENT ;
    PORT
      LAYER M4 ;
      RECT 906.783 386.772 906.855 386.796 ;
    END
  END w0_wd_in[183]
  PIN w0_wd_in[184]
    DIRECTION INPUT ;
    USE SIGNAL ;
    SHAPE ABUTMENT ;
    PORT
      LAYER M4 ;
      RECT 906.783 388.884 906.855 388.908 ;
    END
  END w0_wd_in[184]
  PIN w0_wd_in[185]
    DIRECTION INPUT ;
    USE SIGNAL ;
    SHAPE ABUTMENT ;
    PORT
      LAYER M4 ;
      RECT 906.783 390.996 906.855 391.020 ;
    END
  END w0_wd_in[185]
  PIN w0_wd_in[186]
    DIRECTION INPUT ;
    USE SIGNAL ;
    SHAPE ABUTMENT ;
    PORT
      LAYER M4 ;
      RECT 906.783 393.108 906.855 393.132 ;
    END
  END w0_wd_in[186]
  PIN w0_wd_in[187]
    DIRECTION INPUT ;
    USE SIGNAL ;
    SHAPE ABUTMENT ;
    PORT
      LAYER M4 ;
      RECT 906.783 395.220 906.855 395.244 ;
    END
  END w0_wd_in[187]
  PIN w0_wd_in[188]
    DIRECTION INPUT ;
    USE SIGNAL ;
    SHAPE ABUTMENT ;
    PORT
      LAYER M4 ;
      RECT 906.783 397.332 906.855 397.356 ;
    END
  END w0_wd_in[188]
  PIN w0_wd_in[189]
    DIRECTION INPUT ;
    USE SIGNAL ;
    SHAPE ABUTMENT ;
    PORT
      LAYER M4 ;
      RECT 906.783 399.444 906.855 399.468 ;
    END
  END w0_wd_in[189]
  PIN w0_wd_in[190]
    DIRECTION INPUT ;
    USE SIGNAL ;
    SHAPE ABUTMENT ;
    PORT
      LAYER M4 ;
      RECT 906.783 401.556 906.855 401.580 ;
    END
  END w0_wd_in[190]
  PIN w0_wd_in[191]
    DIRECTION INPUT ;
    USE SIGNAL ;
    SHAPE ABUTMENT ;
    PORT
      LAYER M4 ;
      RECT 906.783 403.668 906.855 403.692 ;
    END
  END w0_wd_in[191]
  PIN w0_wd_in[192]
    DIRECTION INPUT ;
    USE SIGNAL ;
    SHAPE ABUTMENT ;
    PORT
      LAYER M4 ;
      RECT 906.783 405.780 906.855 405.804 ;
    END
  END w0_wd_in[192]
  PIN w0_wd_in[193]
    DIRECTION INPUT ;
    USE SIGNAL ;
    SHAPE ABUTMENT ;
    PORT
      LAYER M4 ;
      RECT 906.783 407.892 906.855 407.916 ;
    END
  END w0_wd_in[193]
  PIN w0_wd_in[194]
    DIRECTION INPUT ;
    USE SIGNAL ;
    SHAPE ABUTMENT ;
    PORT
      LAYER M4 ;
      RECT 906.783 410.004 906.855 410.028 ;
    END
  END w0_wd_in[194]
  PIN w0_wd_in[195]
    DIRECTION INPUT ;
    USE SIGNAL ;
    SHAPE ABUTMENT ;
    PORT
      LAYER M4 ;
      RECT 906.783 412.116 906.855 412.140 ;
    END
  END w0_wd_in[195]
  PIN w0_wd_in[196]
    DIRECTION INPUT ;
    USE SIGNAL ;
    SHAPE ABUTMENT ;
    PORT
      LAYER M4 ;
      RECT 906.783 414.228 906.855 414.252 ;
    END
  END w0_wd_in[196]
  PIN w0_wd_in[197]
    DIRECTION INPUT ;
    USE SIGNAL ;
    SHAPE ABUTMENT ;
    PORT
      LAYER M4 ;
      RECT 906.783 416.340 906.855 416.364 ;
    END
  END w0_wd_in[197]
  PIN w0_wd_in[198]
    DIRECTION INPUT ;
    USE SIGNAL ;
    SHAPE ABUTMENT ;
    PORT
      LAYER M4 ;
      RECT 906.783 418.452 906.855 418.476 ;
    END
  END w0_wd_in[198]
  PIN w0_wd_in[199]
    DIRECTION INPUT ;
    USE SIGNAL ;
    SHAPE ABUTMENT ;
    PORT
      LAYER M4 ;
      RECT 906.783 420.564 906.855 420.588 ;
    END
  END w0_wd_in[199]
  PIN w0_wd_in[200]
    DIRECTION INPUT ;
    USE SIGNAL ;
    SHAPE ABUTMENT ;
    PORT
      LAYER M4 ;
      RECT 906.783 422.676 906.855 422.700 ;
    END
  END w0_wd_in[200]
  PIN w0_wd_in[201]
    DIRECTION INPUT ;
    USE SIGNAL ;
    SHAPE ABUTMENT ;
    PORT
      LAYER M4 ;
      RECT 906.783 424.788 906.855 424.812 ;
    END
  END w0_wd_in[201]
  PIN w0_wd_in[202]
    DIRECTION INPUT ;
    USE SIGNAL ;
    SHAPE ABUTMENT ;
    PORT
      LAYER M4 ;
      RECT 906.783 426.900 906.855 426.924 ;
    END
  END w0_wd_in[202]
  PIN w0_wd_in[203]
    DIRECTION INPUT ;
    USE SIGNAL ;
    SHAPE ABUTMENT ;
    PORT
      LAYER M4 ;
      RECT 906.783 429.012 906.855 429.036 ;
    END
  END w0_wd_in[203]
  PIN w0_wd_in[204]
    DIRECTION INPUT ;
    USE SIGNAL ;
    SHAPE ABUTMENT ;
    PORT
      LAYER M4 ;
      RECT 906.783 431.124 906.855 431.148 ;
    END
  END w0_wd_in[204]
  PIN w0_wd_in[205]
    DIRECTION INPUT ;
    USE SIGNAL ;
    SHAPE ABUTMENT ;
    PORT
      LAYER M4 ;
      RECT 906.783 433.236 906.855 433.260 ;
    END
  END w0_wd_in[205]
  PIN w0_wd_in[206]
    DIRECTION INPUT ;
    USE SIGNAL ;
    SHAPE ABUTMENT ;
    PORT
      LAYER M4 ;
      RECT 906.783 435.348 906.855 435.372 ;
    END
  END w0_wd_in[206]
  PIN w0_wd_in[207]
    DIRECTION INPUT ;
    USE SIGNAL ;
    SHAPE ABUTMENT ;
    PORT
      LAYER M4 ;
      RECT 906.783 437.460 906.855 437.484 ;
    END
  END w0_wd_in[207]
  PIN w0_wd_in[208]
    DIRECTION INPUT ;
    USE SIGNAL ;
    SHAPE ABUTMENT ;
    PORT
      LAYER M4 ;
      RECT 906.783 439.572 906.855 439.596 ;
    END
  END w0_wd_in[208]
  PIN w0_wd_in[209]
    DIRECTION INPUT ;
    USE SIGNAL ;
    SHAPE ABUTMENT ;
    PORT
      LAYER M4 ;
      RECT 906.783 441.684 906.855 441.708 ;
    END
  END w0_wd_in[209]
  PIN w0_wd_in[210]
    DIRECTION INPUT ;
    USE SIGNAL ;
    SHAPE ABUTMENT ;
    PORT
      LAYER M4 ;
      RECT 906.783 443.796 906.855 443.820 ;
    END
  END w0_wd_in[210]
  PIN w0_wd_in[211]
    DIRECTION INPUT ;
    USE SIGNAL ;
    SHAPE ABUTMENT ;
    PORT
      LAYER M4 ;
      RECT 906.783 445.908 906.855 445.932 ;
    END
  END w0_wd_in[211]
  PIN w0_wd_in[212]
    DIRECTION INPUT ;
    USE SIGNAL ;
    SHAPE ABUTMENT ;
    PORT
      LAYER M4 ;
      RECT 906.783 448.020 906.855 448.044 ;
    END
  END w0_wd_in[212]
  PIN w0_wd_in[213]
    DIRECTION INPUT ;
    USE SIGNAL ;
    SHAPE ABUTMENT ;
    PORT
      LAYER M4 ;
      RECT 906.783 450.132 906.855 450.156 ;
    END
  END w0_wd_in[213]
  PIN w0_wd_in[214]
    DIRECTION INPUT ;
    USE SIGNAL ;
    SHAPE ABUTMENT ;
    PORT
      LAYER M4 ;
      RECT 906.783 452.244 906.855 452.268 ;
    END
  END w0_wd_in[214]
  PIN w0_wd_in[215]
    DIRECTION INPUT ;
    USE SIGNAL ;
    SHAPE ABUTMENT ;
    PORT
      LAYER M4 ;
      RECT 906.783 454.356 906.855 454.380 ;
    END
  END w0_wd_in[215]
  PIN w0_wd_in[216]
    DIRECTION INPUT ;
    USE SIGNAL ;
    SHAPE ABUTMENT ;
    PORT
      LAYER M4 ;
      RECT 906.783 456.468 906.855 456.492 ;
    END
  END w0_wd_in[216]
  PIN w0_wd_in[217]
    DIRECTION INPUT ;
    USE SIGNAL ;
    SHAPE ABUTMENT ;
    PORT
      LAYER M4 ;
      RECT 906.783 458.580 906.855 458.604 ;
    END
  END w0_wd_in[217]
  PIN w0_wd_in[218]
    DIRECTION INPUT ;
    USE SIGNAL ;
    SHAPE ABUTMENT ;
    PORT
      LAYER M4 ;
      RECT 906.783 460.692 906.855 460.716 ;
    END
  END w0_wd_in[218]
  PIN w0_wd_in[219]
    DIRECTION INPUT ;
    USE SIGNAL ;
    SHAPE ABUTMENT ;
    PORT
      LAYER M4 ;
      RECT 906.783 462.804 906.855 462.828 ;
    END
  END w0_wd_in[219]
  PIN w0_wd_in[220]
    DIRECTION INPUT ;
    USE SIGNAL ;
    SHAPE ABUTMENT ;
    PORT
      LAYER M4 ;
      RECT 906.783 464.916 906.855 464.940 ;
    END
  END w0_wd_in[220]
  PIN w0_wd_in[221]
    DIRECTION INPUT ;
    USE SIGNAL ;
    SHAPE ABUTMENT ;
    PORT
      LAYER M4 ;
      RECT 906.783 467.028 906.855 467.052 ;
    END
  END w0_wd_in[221]
  PIN w0_wd_in[222]
    DIRECTION INPUT ;
    USE SIGNAL ;
    SHAPE ABUTMENT ;
    PORT
      LAYER M4 ;
      RECT 906.783 469.140 906.855 469.164 ;
    END
  END w0_wd_in[222]
  PIN w0_wd_in[223]
    DIRECTION INPUT ;
    USE SIGNAL ;
    SHAPE ABUTMENT ;
    PORT
      LAYER M4 ;
      RECT 906.783 471.252 906.855 471.276 ;
    END
  END w0_wd_in[223]
  PIN w0_wd_in[224]
    DIRECTION INPUT ;
    USE SIGNAL ;
    SHAPE ABUTMENT ;
    PORT
      LAYER M4 ;
      RECT 906.783 473.364 906.855 473.388 ;
    END
  END w0_wd_in[224]
  PIN w0_wd_in[225]
    DIRECTION INPUT ;
    USE SIGNAL ;
    SHAPE ABUTMENT ;
    PORT
      LAYER M4 ;
      RECT 906.783 475.476 906.855 475.500 ;
    END
  END w0_wd_in[225]
  PIN w0_wd_in[226]
    DIRECTION INPUT ;
    USE SIGNAL ;
    SHAPE ABUTMENT ;
    PORT
      LAYER M4 ;
      RECT 906.783 477.588 906.855 477.612 ;
    END
  END w0_wd_in[226]
  PIN w0_wd_in[227]
    DIRECTION INPUT ;
    USE SIGNAL ;
    SHAPE ABUTMENT ;
    PORT
      LAYER M4 ;
      RECT 906.783 479.700 906.855 479.724 ;
    END
  END w0_wd_in[227]
  PIN w0_wd_in[228]
    DIRECTION INPUT ;
    USE SIGNAL ;
    SHAPE ABUTMENT ;
    PORT
      LAYER M4 ;
      RECT 906.783 481.812 906.855 481.836 ;
    END
  END w0_wd_in[228]
  PIN w0_wd_in[229]
    DIRECTION INPUT ;
    USE SIGNAL ;
    SHAPE ABUTMENT ;
    PORT
      LAYER M4 ;
      RECT 906.783 483.924 906.855 483.948 ;
    END
  END w0_wd_in[229]
  PIN w0_wd_in[230]
    DIRECTION INPUT ;
    USE SIGNAL ;
    SHAPE ABUTMENT ;
    PORT
      LAYER M4 ;
      RECT 906.783 486.036 906.855 486.060 ;
    END
  END w0_wd_in[230]
  PIN w0_wd_in[231]
    DIRECTION INPUT ;
    USE SIGNAL ;
    SHAPE ABUTMENT ;
    PORT
      LAYER M4 ;
      RECT 906.783 488.148 906.855 488.172 ;
    END
  END w0_wd_in[231]
  PIN w0_wd_in[232]
    DIRECTION INPUT ;
    USE SIGNAL ;
    SHAPE ABUTMENT ;
    PORT
      LAYER M4 ;
      RECT 906.783 490.260 906.855 490.284 ;
    END
  END w0_wd_in[232]
  PIN w0_wd_in[233]
    DIRECTION INPUT ;
    USE SIGNAL ;
    SHAPE ABUTMENT ;
    PORT
      LAYER M4 ;
      RECT 906.783 492.372 906.855 492.396 ;
    END
  END w0_wd_in[233]
  PIN w0_wd_in[234]
    DIRECTION INPUT ;
    USE SIGNAL ;
    SHAPE ABUTMENT ;
    PORT
      LAYER M4 ;
      RECT 906.783 494.484 906.855 494.508 ;
    END
  END w0_wd_in[234]
  PIN w0_wd_in[235]
    DIRECTION INPUT ;
    USE SIGNAL ;
    SHAPE ABUTMENT ;
    PORT
      LAYER M4 ;
      RECT 906.783 496.596 906.855 496.620 ;
    END
  END w0_wd_in[235]
  PIN w0_wd_in[236]
    DIRECTION INPUT ;
    USE SIGNAL ;
    SHAPE ABUTMENT ;
    PORT
      LAYER M4 ;
      RECT 906.783 498.708 906.855 498.732 ;
    END
  END w0_wd_in[236]
  PIN w0_wd_in[237]
    DIRECTION INPUT ;
    USE SIGNAL ;
    SHAPE ABUTMENT ;
    PORT
      LAYER M4 ;
      RECT 906.783 500.820 906.855 500.844 ;
    END
  END w0_wd_in[237]
  PIN w0_wd_in[238]
    DIRECTION INPUT ;
    USE SIGNAL ;
    SHAPE ABUTMENT ;
    PORT
      LAYER M4 ;
      RECT 906.783 502.932 906.855 502.956 ;
    END
  END w0_wd_in[238]
  PIN w0_wd_in[239]
    DIRECTION INPUT ;
    USE SIGNAL ;
    SHAPE ABUTMENT ;
    PORT
      LAYER M4 ;
      RECT 906.783 505.044 906.855 505.068 ;
    END
  END w0_wd_in[239]
  PIN w0_wd_in[240]
    DIRECTION INPUT ;
    USE SIGNAL ;
    SHAPE ABUTMENT ;
    PORT
      LAYER M4 ;
      RECT 906.783 507.156 906.855 507.180 ;
    END
  END w0_wd_in[240]
  PIN w0_wd_in[241]
    DIRECTION INPUT ;
    USE SIGNAL ;
    SHAPE ABUTMENT ;
    PORT
      LAYER M4 ;
      RECT 906.783 509.268 906.855 509.292 ;
    END
  END w0_wd_in[241]
  PIN w0_wd_in[242]
    DIRECTION INPUT ;
    USE SIGNAL ;
    SHAPE ABUTMENT ;
    PORT
      LAYER M4 ;
      RECT 906.783 511.380 906.855 511.404 ;
    END
  END w0_wd_in[242]
  PIN w0_wd_in[243]
    DIRECTION INPUT ;
    USE SIGNAL ;
    SHAPE ABUTMENT ;
    PORT
      LAYER M4 ;
      RECT 906.783 513.492 906.855 513.516 ;
    END
  END w0_wd_in[243]
  PIN w0_wd_in[244]
    DIRECTION INPUT ;
    USE SIGNAL ;
    SHAPE ABUTMENT ;
    PORT
      LAYER M4 ;
      RECT 906.783 515.604 906.855 515.628 ;
    END
  END w0_wd_in[244]
  PIN w0_wd_in[245]
    DIRECTION INPUT ;
    USE SIGNAL ;
    SHAPE ABUTMENT ;
    PORT
      LAYER M4 ;
      RECT 906.783 517.716 906.855 517.740 ;
    END
  END w0_wd_in[245]
  PIN w0_wd_in[246]
    DIRECTION INPUT ;
    USE SIGNAL ;
    SHAPE ABUTMENT ;
    PORT
      LAYER M4 ;
      RECT 906.783 519.828 906.855 519.852 ;
    END
  END w0_wd_in[246]
  PIN w0_wd_in[247]
    DIRECTION INPUT ;
    USE SIGNAL ;
    SHAPE ABUTMENT ;
    PORT
      LAYER M4 ;
      RECT 906.783 521.940 906.855 521.964 ;
    END
  END w0_wd_in[247]
  PIN w0_wd_in[248]
    DIRECTION INPUT ;
    USE SIGNAL ;
    SHAPE ABUTMENT ;
    PORT
      LAYER M4 ;
      RECT 906.783 524.052 906.855 524.076 ;
    END
  END w0_wd_in[248]
  PIN w0_wd_in[249]
    DIRECTION INPUT ;
    USE SIGNAL ;
    SHAPE ABUTMENT ;
    PORT
      LAYER M4 ;
      RECT 906.783 526.164 906.855 526.188 ;
    END
  END w0_wd_in[249]
  PIN w0_wd_in[250]
    DIRECTION INPUT ;
    USE SIGNAL ;
    SHAPE ABUTMENT ;
    PORT
      LAYER M4 ;
      RECT 906.783 528.276 906.855 528.300 ;
    END
  END w0_wd_in[250]
  PIN w0_wd_in[251]
    DIRECTION INPUT ;
    USE SIGNAL ;
    SHAPE ABUTMENT ;
    PORT
      LAYER M4 ;
      RECT 906.783 530.388 906.855 530.412 ;
    END
  END w0_wd_in[251]
  PIN w0_wd_in[252]
    DIRECTION INPUT ;
    USE SIGNAL ;
    SHAPE ABUTMENT ;
    PORT
      LAYER M4 ;
      RECT 906.783 532.500 906.855 532.524 ;
    END
  END w0_wd_in[252]
  PIN w0_wd_in[253]
    DIRECTION INPUT ;
    USE SIGNAL ;
    SHAPE ABUTMENT ;
    PORT
      LAYER M4 ;
      RECT 906.783 534.612 906.855 534.636 ;
    END
  END w0_wd_in[253]
  PIN w0_wd_in[254]
    DIRECTION INPUT ;
    USE SIGNAL ;
    SHAPE ABUTMENT ;
    PORT
      LAYER M4 ;
      RECT 906.783 536.724 906.855 536.748 ;
    END
  END w0_wd_in[254]
  PIN w0_wd_in[255]
    DIRECTION INPUT ;
    USE SIGNAL ;
    SHAPE ABUTMENT ;
    PORT
      LAYER M4 ;
      RECT 906.783 538.836 906.855 538.860 ;
    END
  END w0_wd_in[255]
  PIN w0_wd_in[256]
    DIRECTION INPUT ;
    USE SIGNAL ;
    SHAPE ABUTMENT ;
    PORT
      LAYER M3 ;
      RECT 0.207 0.000 0.225 0.054 ;
    END
  END w0_wd_in[256]
  PIN w0_wd_in[257]
    DIRECTION INPUT ;
    USE SIGNAL ;
    SHAPE ABUTMENT ;
    PORT
      LAYER M3 ;
      RECT 1.971 0.000 1.989 0.054 ;
    END
  END w0_wd_in[257]
  PIN w0_wd_in[258]
    DIRECTION INPUT ;
    USE SIGNAL ;
    SHAPE ABUTMENT ;
    PORT
      LAYER M3 ;
      RECT 3.735 0.000 3.753 0.054 ;
    END
  END w0_wd_in[258]
  PIN w0_wd_in[259]
    DIRECTION INPUT ;
    USE SIGNAL ;
    SHAPE ABUTMENT ;
    PORT
      LAYER M3 ;
      RECT 5.499 0.000 5.517 0.054 ;
    END
  END w0_wd_in[259]
  PIN w0_wd_in[260]
    DIRECTION INPUT ;
    USE SIGNAL ;
    SHAPE ABUTMENT ;
    PORT
      LAYER M3 ;
      RECT 7.263 0.000 7.281 0.054 ;
    END
  END w0_wd_in[260]
  PIN w0_wd_in[261]
    DIRECTION INPUT ;
    USE SIGNAL ;
    SHAPE ABUTMENT ;
    PORT
      LAYER M3 ;
      RECT 9.027 0.000 9.045 0.054 ;
    END
  END w0_wd_in[261]
  PIN w0_wd_in[262]
    DIRECTION INPUT ;
    USE SIGNAL ;
    SHAPE ABUTMENT ;
    PORT
      LAYER M3 ;
      RECT 10.791 0.000 10.809 0.054 ;
    END
  END w0_wd_in[262]
  PIN w0_wd_in[263]
    DIRECTION INPUT ;
    USE SIGNAL ;
    SHAPE ABUTMENT ;
    PORT
      LAYER M3 ;
      RECT 12.555 0.000 12.573 0.054 ;
    END
  END w0_wd_in[263]
  PIN w0_wd_in[264]
    DIRECTION INPUT ;
    USE SIGNAL ;
    SHAPE ABUTMENT ;
    PORT
      LAYER M3 ;
      RECT 14.319 0.000 14.337 0.054 ;
    END
  END w0_wd_in[264]
  PIN w0_wd_in[265]
    DIRECTION INPUT ;
    USE SIGNAL ;
    SHAPE ABUTMENT ;
    PORT
      LAYER M3 ;
      RECT 16.083 0.000 16.101 0.054 ;
    END
  END w0_wd_in[265]
  PIN w0_wd_in[266]
    DIRECTION INPUT ;
    USE SIGNAL ;
    SHAPE ABUTMENT ;
    PORT
      LAYER M3 ;
      RECT 17.847 0.000 17.865 0.054 ;
    END
  END w0_wd_in[266]
  PIN w0_wd_in[267]
    DIRECTION INPUT ;
    USE SIGNAL ;
    SHAPE ABUTMENT ;
    PORT
      LAYER M3 ;
      RECT 19.611 0.000 19.629 0.054 ;
    END
  END w0_wd_in[267]
  PIN w0_wd_in[268]
    DIRECTION INPUT ;
    USE SIGNAL ;
    SHAPE ABUTMENT ;
    PORT
      LAYER M3 ;
      RECT 21.375 0.000 21.393 0.054 ;
    END
  END w0_wd_in[268]
  PIN w0_wd_in[269]
    DIRECTION INPUT ;
    USE SIGNAL ;
    SHAPE ABUTMENT ;
    PORT
      LAYER M3 ;
      RECT 23.139 0.000 23.157 0.054 ;
    END
  END w0_wd_in[269]
  PIN w0_wd_in[270]
    DIRECTION INPUT ;
    USE SIGNAL ;
    SHAPE ABUTMENT ;
    PORT
      LAYER M3 ;
      RECT 24.903 0.000 24.921 0.054 ;
    END
  END w0_wd_in[270]
  PIN w0_wd_in[271]
    DIRECTION INPUT ;
    USE SIGNAL ;
    SHAPE ABUTMENT ;
    PORT
      LAYER M3 ;
      RECT 26.667 0.000 26.685 0.054 ;
    END
  END w0_wd_in[271]
  PIN w0_wd_in[272]
    DIRECTION INPUT ;
    USE SIGNAL ;
    SHAPE ABUTMENT ;
    PORT
      LAYER M3 ;
      RECT 28.431 0.000 28.449 0.054 ;
    END
  END w0_wd_in[272]
  PIN w0_wd_in[273]
    DIRECTION INPUT ;
    USE SIGNAL ;
    SHAPE ABUTMENT ;
    PORT
      LAYER M3 ;
      RECT 30.195 0.000 30.213 0.054 ;
    END
  END w0_wd_in[273]
  PIN w0_wd_in[274]
    DIRECTION INPUT ;
    USE SIGNAL ;
    SHAPE ABUTMENT ;
    PORT
      LAYER M3 ;
      RECT 31.959 0.000 31.977 0.054 ;
    END
  END w0_wd_in[274]
  PIN w0_wd_in[275]
    DIRECTION INPUT ;
    USE SIGNAL ;
    SHAPE ABUTMENT ;
    PORT
      LAYER M3 ;
      RECT 33.723 0.000 33.741 0.054 ;
    END
  END w0_wd_in[275]
  PIN w0_wd_in[276]
    DIRECTION INPUT ;
    USE SIGNAL ;
    SHAPE ABUTMENT ;
    PORT
      LAYER M3 ;
      RECT 35.487 0.000 35.505 0.054 ;
    END
  END w0_wd_in[276]
  PIN w0_wd_in[277]
    DIRECTION INPUT ;
    USE SIGNAL ;
    SHAPE ABUTMENT ;
    PORT
      LAYER M3 ;
      RECT 37.251 0.000 37.269 0.054 ;
    END
  END w0_wd_in[277]
  PIN w0_wd_in[278]
    DIRECTION INPUT ;
    USE SIGNAL ;
    SHAPE ABUTMENT ;
    PORT
      LAYER M3 ;
      RECT 39.015 0.000 39.033 0.054 ;
    END
  END w0_wd_in[278]
  PIN w0_wd_in[279]
    DIRECTION INPUT ;
    USE SIGNAL ;
    SHAPE ABUTMENT ;
    PORT
      LAYER M3 ;
      RECT 40.779 0.000 40.797 0.054 ;
    END
  END w0_wd_in[279]
  PIN w0_wd_in[280]
    DIRECTION INPUT ;
    USE SIGNAL ;
    SHAPE ABUTMENT ;
    PORT
      LAYER M3 ;
      RECT 42.543 0.000 42.561 0.054 ;
    END
  END w0_wd_in[280]
  PIN w0_wd_in[281]
    DIRECTION INPUT ;
    USE SIGNAL ;
    SHAPE ABUTMENT ;
    PORT
      LAYER M3 ;
      RECT 44.307 0.000 44.325 0.054 ;
    END
  END w0_wd_in[281]
  PIN w0_wd_in[282]
    DIRECTION INPUT ;
    USE SIGNAL ;
    SHAPE ABUTMENT ;
    PORT
      LAYER M3 ;
      RECT 46.071 0.000 46.089 0.054 ;
    END
  END w0_wd_in[282]
  PIN w0_wd_in[283]
    DIRECTION INPUT ;
    USE SIGNAL ;
    SHAPE ABUTMENT ;
    PORT
      LAYER M3 ;
      RECT 47.835 0.000 47.853 0.054 ;
    END
  END w0_wd_in[283]
  PIN w0_wd_in[284]
    DIRECTION INPUT ;
    USE SIGNAL ;
    SHAPE ABUTMENT ;
    PORT
      LAYER M3 ;
      RECT 49.599 0.000 49.617 0.054 ;
    END
  END w0_wd_in[284]
  PIN w0_wd_in[285]
    DIRECTION INPUT ;
    USE SIGNAL ;
    SHAPE ABUTMENT ;
    PORT
      LAYER M3 ;
      RECT 51.363 0.000 51.381 0.054 ;
    END
  END w0_wd_in[285]
  PIN w0_wd_in[286]
    DIRECTION INPUT ;
    USE SIGNAL ;
    SHAPE ABUTMENT ;
    PORT
      LAYER M3 ;
      RECT 53.127 0.000 53.145 0.054 ;
    END
  END w0_wd_in[286]
  PIN w0_wd_in[287]
    DIRECTION INPUT ;
    USE SIGNAL ;
    SHAPE ABUTMENT ;
    PORT
      LAYER M3 ;
      RECT 54.891 0.000 54.909 0.054 ;
    END
  END w0_wd_in[287]
  PIN w0_wd_in[288]
    DIRECTION INPUT ;
    USE SIGNAL ;
    SHAPE ABUTMENT ;
    PORT
      LAYER M3 ;
      RECT 56.655 0.000 56.673 0.054 ;
    END
  END w0_wd_in[288]
  PIN w0_wd_in[289]
    DIRECTION INPUT ;
    USE SIGNAL ;
    SHAPE ABUTMENT ;
    PORT
      LAYER M3 ;
      RECT 58.419 0.000 58.437 0.054 ;
    END
  END w0_wd_in[289]
  PIN w0_wd_in[290]
    DIRECTION INPUT ;
    USE SIGNAL ;
    SHAPE ABUTMENT ;
    PORT
      LAYER M3 ;
      RECT 60.183 0.000 60.201 0.054 ;
    END
  END w0_wd_in[290]
  PIN w0_wd_in[291]
    DIRECTION INPUT ;
    USE SIGNAL ;
    SHAPE ABUTMENT ;
    PORT
      LAYER M3 ;
      RECT 61.947 0.000 61.965 0.054 ;
    END
  END w0_wd_in[291]
  PIN w0_wd_in[292]
    DIRECTION INPUT ;
    USE SIGNAL ;
    SHAPE ABUTMENT ;
    PORT
      LAYER M3 ;
      RECT 63.711 0.000 63.729 0.054 ;
    END
  END w0_wd_in[292]
  PIN w0_wd_in[293]
    DIRECTION INPUT ;
    USE SIGNAL ;
    SHAPE ABUTMENT ;
    PORT
      LAYER M3 ;
      RECT 65.475 0.000 65.493 0.054 ;
    END
  END w0_wd_in[293]
  PIN w0_wd_in[294]
    DIRECTION INPUT ;
    USE SIGNAL ;
    SHAPE ABUTMENT ;
    PORT
      LAYER M3 ;
      RECT 67.239 0.000 67.257 0.054 ;
    END
  END w0_wd_in[294]
  PIN w0_wd_in[295]
    DIRECTION INPUT ;
    USE SIGNAL ;
    SHAPE ABUTMENT ;
    PORT
      LAYER M3 ;
      RECT 69.003 0.000 69.021 0.054 ;
    END
  END w0_wd_in[295]
  PIN w0_wd_in[296]
    DIRECTION INPUT ;
    USE SIGNAL ;
    SHAPE ABUTMENT ;
    PORT
      LAYER M3 ;
      RECT 70.767 0.000 70.785 0.054 ;
    END
  END w0_wd_in[296]
  PIN w0_wd_in[297]
    DIRECTION INPUT ;
    USE SIGNAL ;
    SHAPE ABUTMENT ;
    PORT
      LAYER M3 ;
      RECT 72.531 0.000 72.549 0.054 ;
    END
  END w0_wd_in[297]
  PIN w0_wd_in[298]
    DIRECTION INPUT ;
    USE SIGNAL ;
    SHAPE ABUTMENT ;
    PORT
      LAYER M3 ;
      RECT 74.295 0.000 74.313 0.054 ;
    END
  END w0_wd_in[298]
  PIN w0_wd_in[299]
    DIRECTION INPUT ;
    USE SIGNAL ;
    SHAPE ABUTMENT ;
    PORT
      LAYER M3 ;
      RECT 76.059 0.000 76.077 0.054 ;
    END
  END w0_wd_in[299]
  PIN w0_wd_in[300]
    DIRECTION INPUT ;
    USE SIGNAL ;
    SHAPE ABUTMENT ;
    PORT
      LAYER M3 ;
      RECT 77.823 0.000 77.841 0.054 ;
    END
  END w0_wd_in[300]
  PIN w0_wd_in[301]
    DIRECTION INPUT ;
    USE SIGNAL ;
    SHAPE ABUTMENT ;
    PORT
      LAYER M3 ;
      RECT 79.587 0.000 79.605 0.054 ;
    END
  END w0_wd_in[301]
  PIN w0_wd_in[302]
    DIRECTION INPUT ;
    USE SIGNAL ;
    SHAPE ABUTMENT ;
    PORT
      LAYER M3 ;
      RECT 81.351 0.000 81.369 0.054 ;
    END
  END w0_wd_in[302]
  PIN w0_wd_in[303]
    DIRECTION INPUT ;
    USE SIGNAL ;
    SHAPE ABUTMENT ;
    PORT
      LAYER M3 ;
      RECT 83.115 0.000 83.133 0.054 ;
    END
  END w0_wd_in[303]
  PIN w0_wd_in[304]
    DIRECTION INPUT ;
    USE SIGNAL ;
    SHAPE ABUTMENT ;
    PORT
      LAYER M3 ;
      RECT 84.879 0.000 84.897 0.054 ;
    END
  END w0_wd_in[304]
  PIN w0_wd_in[305]
    DIRECTION INPUT ;
    USE SIGNAL ;
    SHAPE ABUTMENT ;
    PORT
      LAYER M3 ;
      RECT 86.643 0.000 86.661 0.054 ;
    END
  END w0_wd_in[305]
  PIN w0_wd_in[306]
    DIRECTION INPUT ;
    USE SIGNAL ;
    SHAPE ABUTMENT ;
    PORT
      LAYER M3 ;
      RECT 88.407 0.000 88.425 0.054 ;
    END
  END w0_wd_in[306]
  PIN w0_wd_in[307]
    DIRECTION INPUT ;
    USE SIGNAL ;
    SHAPE ABUTMENT ;
    PORT
      LAYER M3 ;
      RECT 90.171 0.000 90.189 0.054 ;
    END
  END w0_wd_in[307]
  PIN w0_wd_in[308]
    DIRECTION INPUT ;
    USE SIGNAL ;
    SHAPE ABUTMENT ;
    PORT
      LAYER M3 ;
      RECT 91.935 0.000 91.953 0.054 ;
    END
  END w0_wd_in[308]
  PIN w0_wd_in[309]
    DIRECTION INPUT ;
    USE SIGNAL ;
    SHAPE ABUTMENT ;
    PORT
      LAYER M3 ;
      RECT 93.699 0.000 93.717 0.054 ;
    END
  END w0_wd_in[309]
  PIN w0_wd_in[310]
    DIRECTION INPUT ;
    USE SIGNAL ;
    SHAPE ABUTMENT ;
    PORT
      LAYER M3 ;
      RECT 95.463 0.000 95.481 0.054 ;
    END
  END w0_wd_in[310]
  PIN w0_wd_in[311]
    DIRECTION INPUT ;
    USE SIGNAL ;
    SHAPE ABUTMENT ;
    PORT
      LAYER M3 ;
      RECT 97.227 0.000 97.245 0.054 ;
    END
  END w0_wd_in[311]
  PIN w0_wd_in[312]
    DIRECTION INPUT ;
    USE SIGNAL ;
    SHAPE ABUTMENT ;
    PORT
      LAYER M3 ;
      RECT 98.991 0.000 99.009 0.054 ;
    END
  END w0_wd_in[312]
  PIN w0_wd_in[313]
    DIRECTION INPUT ;
    USE SIGNAL ;
    SHAPE ABUTMENT ;
    PORT
      LAYER M3 ;
      RECT 100.755 0.000 100.773 0.054 ;
    END
  END w0_wd_in[313]
  PIN w0_wd_in[314]
    DIRECTION INPUT ;
    USE SIGNAL ;
    SHAPE ABUTMENT ;
    PORT
      LAYER M3 ;
      RECT 102.519 0.000 102.537 0.054 ;
    END
  END w0_wd_in[314]
  PIN w0_wd_in[315]
    DIRECTION INPUT ;
    USE SIGNAL ;
    SHAPE ABUTMENT ;
    PORT
      LAYER M3 ;
      RECT 104.283 0.000 104.301 0.054 ;
    END
  END w0_wd_in[315]
  PIN w0_wd_in[316]
    DIRECTION INPUT ;
    USE SIGNAL ;
    SHAPE ABUTMENT ;
    PORT
      LAYER M3 ;
      RECT 106.047 0.000 106.065 0.054 ;
    END
  END w0_wd_in[316]
  PIN w0_wd_in[317]
    DIRECTION INPUT ;
    USE SIGNAL ;
    SHAPE ABUTMENT ;
    PORT
      LAYER M3 ;
      RECT 107.811 0.000 107.829 0.054 ;
    END
  END w0_wd_in[317]
  PIN w0_wd_in[318]
    DIRECTION INPUT ;
    USE SIGNAL ;
    SHAPE ABUTMENT ;
    PORT
      LAYER M3 ;
      RECT 109.575 0.000 109.593 0.054 ;
    END
  END w0_wd_in[318]
  PIN w0_wd_in[319]
    DIRECTION INPUT ;
    USE SIGNAL ;
    SHAPE ABUTMENT ;
    PORT
      LAYER M3 ;
      RECT 111.339 0.000 111.357 0.054 ;
    END
  END w0_wd_in[319]
  PIN w0_wd_in[320]
    DIRECTION INPUT ;
    USE SIGNAL ;
    SHAPE ABUTMENT ;
    PORT
      LAYER M3 ;
      RECT 113.103 0.000 113.121 0.054 ;
    END
  END w0_wd_in[320]
  PIN w0_wd_in[321]
    DIRECTION INPUT ;
    USE SIGNAL ;
    SHAPE ABUTMENT ;
    PORT
      LAYER M3 ;
      RECT 114.867 0.000 114.885 0.054 ;
    END
  END w0_wd_in[321]
  PIN w0_wd_in[322]
    DIRECTION INPUT ;
    USE SIGNAL ;
    SHAPE ABUTMENT ;
    PORT
      LAYER M3 ;
      RECT 116.631 0.000 116.649 0.054 ;
    END
  END w0_wd_in[322]
  PIN w0_wd_in[323]
    DIRECTION INPUT ;
    USE SIGNAL ;
    SHAPE ABUTMENT ;
    PORT
      LAYER M3 ;
      RECT 118.395 0.000 118.413 0.054 ;
    END
  END w0_wd_in[323]
  PIN w0_wd_in[324]
    DIRECTION INPUT ;
    USE SIGNAL ;
    SHAPE ABUTMENT ;
    PORT
      LAYER M3 ;
      RECT 120.159 0.000 120.177 0.054 ;
    END
  END w0_wd_in[324]
  PIN w0_wd_in[325]
    DIRECTION INPUT ;
    USE SIGNAL ;
    SHAPE ABUTMENT ;
    PORT
      LAYER M3 ;
      RECT 121.923 0.000 121.941 0.054 ;
    END
  END w0_wd_in[325]
  PIN w0_wd_in[326]
    DIRECTION INPUT ;
    USE SIGNAL ;
    SHAPE ABUTMENT ;
    PORT
      LAYER M3 ;
      RECT 123.687 0.000 123.705 0.054 ;
    END
  END w0_wd_in[326]
  PIN w0_wd_in[327]
    DIRECTION INPUT ;
    USE SIGNAL ;
    SHAPE ABUTMENT ;
    PORT
      LAYER M3 ;
      RECT 125.451 0.000 125.469 0.054 ;
    END
  END w0_wd_in[327]
  PIN w0_wd_in[328]
    DIRECTION INPUT ;
    USE SIGNAL ;
    SHAPE ABUTMENT ;
    PORT
      LAYER M3 ;
      RECT 127.215 0.000 127.233 0.054 ;
    END
  END w0_wd_in[328]
  PIN w0_wd_in[329]
    DIRECTION INPUT ;
    USE SIGNAL ;
    SHAPE ABUTMENT ;
    PORT
      LAYER M3 ;
      RECT 128.979 0.000 128.997 0.054 ;
    END
  END w0_wd_in[329]
  PIN w0_wd_in[330]
    DIRECTION INPUT ;
    USE SIGNAL ;
    SHAPE ABUTMENT ;
    PORT
      LAYER M3 ;
      RECT 130.743 0.000 130.761 0.054 ;
    END
  END w0_wd_in[330]
  PIN w0_wd_in[331]
    DIRECTION INPUT ;
    USE SIGNAL ;
    SHAPE ABUTMENT ;
    PORT
      LAYER M3 ;
      RECT 132.507 0.000 132.525 0.054 ;
    END
  END w0_wd_in[331]
  PIN w0_wd_in[332]
    DIRECTION INPUT ;
    USE SIGNAL ;
    SHAPE ABUTMENT ;
    PORT
      LAYER M3 ;
      RECT 134.271 0.000 134.289 0.054 ;
    END
  END w0_wd_in[332]
  PIN w0_wd_in[333]
    DIRECTION INPUT ;
    USE SIGNAL ;
    SHAPE ABUTMENT ;
    PORT
      LAYER M3 ;
      RECT 136.035 0.000 136.053 0.054 ;
    END
  END w0_wd_in[333]
  PIN w0_wd_in[334]
    DIRECTION INPUT ;
    USE SIGNAL ;
    SHAPE ABUTMENT ;
    PORT
      LAYER M3 ;
      RECT 137.799 0.000 137.817 0.054 ;
    END
  END w0_wd_in[334]
  PIN w0_wd_in[335]
    DIRECTION INPUT ;
    USE SIGNAL ;
    SHAPE ABUTMENT ;
    PORT
      LAYER M3 ;
      RECT 139.563 0.000 139.581 0.054 ;
    END
  END w0_wd_in[335]
  PIN w0_wd_in[336]
    DIRECTION INPUT ;
    USE SIGNAL ;
    SHAPE ABUTMENT ;
    PORT
      LAYER M3 ;
      RECT 141.327 0.000 141.345 0.054 ;
    END
  END w0_wd_in[336]
  PIN w0_wd_in[337]
    DIRECTION INPUT ;
    USE SIGNAL ;
    SHAPE ABUTMENT ;
    PORT
      LAYER M3 ;
      RECT 143.091 0.000 143.109 0.054 ;
    END
  END w0_wd_in[337]
  PIN w0_wd_in[338]
    DIRECTION INPUT ;
    USE SIGNAL ;
    SHAPE ABUTMENT ;
    PORT
      LAYER M3 ;
      RECT 144.855 0.000 144.873 0.054 ;
    END
  END w0_wd_in[338]
  PIN w0_wd_in[339]
    DIRECTION INPUT ;
    USE SIGNAL ;
    SHAPE ABUTMENT ;
    PORT
      LAYER M3 ;
      RECT 146.619 0.000 146.637 0.054 ;
    END
  END w0_wd_in[339]
  PIN w0_wd_in[340]
    DIRECTION INPUT ;
    USE SIGNAL ;
    SHAPE ABUTMENT ;
    PORT
      LAYER M3 ;
      RECT 148.383 0.000 148.401 0.054 ;
    END
  END w0_wd_in[340]
  PIN w0_wd_in[341]
    DIRECTION INPUT ;
    USE SIGNAL ;
    SHAPE ABUTMENT ;
    PORT
      LAYER M3 ;
      RECT 150.147 0.000 150.165 0.054 ;
    END
  END w0_wd_in[341]
  PIN w0_wd_in[342]
    DIRECTION INPUT ;
    USE SIGNAL ;
    SHAPE ABUTMENT ;
    PORT
      LAYER M3 ;
      RECT 151.911 0.000 151.929 0.054 ;
    END
  END w0_wd_in[342]
  PIN w0_wd_in[343]
    DIRECTION INPUT ;
    USE SIGNAL ;
    SHAPE ABUTMENT ;
    PORT
      LAYER M3 ;
      RECT 153.675 0.000 153.693 0.054 ;
    END
  END w0_wd_in[343]
  PIN w0_wd_in[344]
    DIRECTION INPUT ;
    USE SIGNAL ;
    SHAPE ABUTMENT ;
    PORT
      LAYER M3 ;
      RECT 155.439 0.000 155.457 0.054 ;
    END
  END w0_wd_in[344]
  PIN w0_wd_in[345]
    DIRECTION INPUT ;
    USE SIGNAL ;
    SHAPE ABUTMENT ;
    PORT
      LAYER M3 ;
      RECT 157.203 0.000 157.221 0.054 ;
    END
  END w0_wd_in[345]
  PIN w0_wd_in[346]
    DIRECTION INPUT ;
    USE SIGNAL ;
    SHAPE ABUTMENT ;
    PORT
      LAYER M3 ;
      RECT 158.967 0.000 158.985 0.054 ;
    END
  END w0_wd_in[346]
  PIN w0_wd_in[347]
    DIRECTION INPUT ;
    USE SIGNAL ;
    SHAPE ABUTMENT ;
    PORT
      LAYER M3 ;
      RECT 160.731 0.000 160.749 0.054 ;
    END
  END w0_wd_in[347]
  PIN w0_wd_in[348]
    DIRECTION INPUT ;
    USE SIGNAL ;
    SHAPE ABUTMENT ;
    PORT
      LAYER M3 ;
      RECT 162.495 0.000 162.513 0.054 ;
    END
  END w0_wd_in[348]
  PIN w0_wd_in[349]
    DIRECTION INPUT ;
    USE SIGNAL ;
    SHAPE ABUTMENT ;
    PORT
      LAYER M3 ;
      RECT 164.259 0.000 164.277 0.054 ;
    END
  END w0_wd_in[349]
  PIN w0_wd_in[350]
    DIRECTION INPUT ;
    USE SIGNAL ;
    SHAPE ABUTMENT ;
    PORT
      LAYER M3 ;
      RECT 166.023 0.000 166.041 0.054 ;
    END
  END w0_wd_in[350]
  PIN w0_wd_in[351]
    DIRECTION INPUT ;
    USE SIGNAL ;
    SHAPE ABUTMENT ;
    PORT
      LAYER M3 ;
      RECT 167.787 0.000 167.805 0.054 ;
    END
  END w0_wd_in[351]
  PIN w0_wd_in[352]
    DIRECTION INPUT ;
    USE SIGNAL ;
    SHAPE ABUTMENT ;
    PORT
      LAYER M3 ;
      RECT 169.551 0.000 169.569 0.054 ;
    END
  END w0_wd_in[352]
  PIN w0_wd_in[353]
    DIRECTION INPUT ;
    USE SIGNAL ;
    SHAPE ABUTMENT ;
    PORT
      LAYER M3 ;
      RECT 171.315 0.000 171.333 0.054 ;
    END
  END w0_wd_in[353]
  PIN w0_wd_in[354]
    DIRECTION INPUT ;
    USE SIGNAL ;
    SHAPE ABUTMENT ;
    PORT
      LAYER M3 ;
      RECT 173.079 0.000 173.097 0.054 ;
    END
  END w0_wd_in[354]
  PIN w0_wd_in[355]
    DIRECTION INPUT ;
    USE SIGNAL ;
    SHAPE ABUTMENT ;
    PORT
      LAYER M3 ;
      RECT 174.843 0.000 174.861 0.054 ;
    END
  END w0_wd_in[355]
  PIN w0_wd_in[356]
    DIRECTION INPUT ;
    USE SIGNAL ;
    SHAPE ABUTMENT ;
    PORT
      LAYER M3 ;
      RECT 176.607 0.000 176.625 0.054 ;
    END
  END w0_wd_in[356]
  PIN w0_wd_in[357]
    DIRECTION INPUT ;
    USE SIGNAL ;
    SHAPE ABUTMENT ;
    PORT
      LAYER M3 ;
      RECT 178.371 0.000 178.389 0.054 ;
    END
  END w0_wd_in[357]
  PIN w0_wd_in[358]
    DIRECTION INPUT ;
    USE SIGNAL ;
    SHAPE ABUTMENT ;
    PORT
      LAYER M3 ;
      RECT 180.135 0.000 180.153 0.054 ;
    END
  END w0_wd_in[358]
  PIN w0_wd_in[359]
    DIRECTION INPUT ;
    USE SIGNAL ;
    SHAPE ABUTMENT ;
    PORT
      LAYER M3 ;
      RECT 181.899 0.000 181.917 0.054 ;
    END
  END w0_wd_in[359]
  PIN w0_wd_in[360]
    DIRECTION INPUT ;
    USE SIGNAL ;
    SHAPE ABUTMENT ;
    PORT
      LAYER M3 ;
      RECT 183.663 0.000 183.681 0.054 ;
    END
  END w0_wd_in[360]
  PIN w0_wd_in[361]
    DIRECTION INPUT ;
    USE SIGNAL ;
    SHAPE ABUTMENT ;
    PORT
      LAYER M3 ;
      RECT 185.427 0.000 185.445 0.054 ;
    END
  END w0_wd_in[361]
  PIN w0_wd_in[362]
    DIRECTION INPUT ;
    USE SIGNAL ;
    SHAPE ABUTMENT ;
    PORT
      LAYER M3 ;
      RECT 187.191 0.000 187.209 0.054 ;
    END
  END w0_wd_in[362]
  PIN w0_wd_in[363]
    DIRECTION INPUT ;
    USE SIGNAL ;
    SHAPE ABUTMENT ;
    PORT
      LAYER M3 ;
      RECT 188.955 0.000 188.973 0.054 ;
    END
  END w0_wd_in[363]
  PIN w0_wd_in[364]
    DIRECTION INPUT ;
    USE SIGNAL ;
    SHAPE ABUTMENT ;
    PORT
      LAYER M3 ;
      RECT 190.719 0.000 190.737 0.054 ;
    END
  END w0_wd_in[364]
  PIN w0_wd_in[365]
    DIRECTION INPUT ;
    USE SIGNAL ;
    SHAPE ABUTMENT ;
    PORT
      LAYER M3 ;
      RECT 192.483 0.000 192.501 0.054 ;
    END
  END w0_wd_in[365]
  PIN w0_wd_in[366]
    DIRECTION INPUT ;
    USE SIGNAL ;
    SHAPE ABUTMENT ;
    PORT
      LAYER M3 ;
      RECT 194.247 0.000 194.265 0.054 ;
    END
  END w0_wd_in[366]
  PIN w0_wd_in[367]
    DIRECTION INPUT ;
    USE SIGNAL ;
    SHAPE ABUTMENT ;
    PORT
      LAYER M3 ;
      RECT 196.011 0.000 196.029 0.054 ;
    END
  END w0_wd_in[367]
  PIN w0_wd_in[368]
    DIRECTION INPUT ;
    USE SIGNAL ;
    SHAPE ABUTMENT ;
    PORT
      LAYER M3 ;
      RECT 197.775 0.000 197.793 0.054 ;
    END
  END w0_wd_in[368]
  PIN w0_wd_in[369]
    DIRECTION INPUT ;
    USE SIGNAL ;
    SHAPE ABUTMENT ;
    PORT
      LAYER M3 ;
      RECT 199.539 0.000 199.557 0.054 ;
    END
  END w0_wd_in[369]
  PIN w0_wd_in[370]
    DIRECTION INPUT ;
    USE SIGNAL ;
    SHAPE ABUTMENT ;
    PORT
      LAYER M3 ;
      RECT 201.303 0.000 201.321 0.054 ;
    END
  END w0_wd_in[370]
  PIN w0_wd_in[371]
    DIRECTION INPUT ;
    USE SIGNAL ;
    SHAPE ABUTMENT ;
    PORT
      LAYER M3 ;
      RECT 203.067 0.000 203.085 0.054 ;
    END
  END w0_wd_in[371]
  PIN w0_wd_in[372]
    DIRECTION INPUT ;
    USE SIGNAL ;
    SHAPE ABUTMENT ;
    PORT
      LAYER M3 ;
      RECT 204.831 0.000 204.849 0.054 ;
    END
  END w0_wd_in[372]
  PIN w0_wd_in[373]
    DIRECTION INPUT ;
    USE SIGNAL ;
    SHAPE ABUTMENT ;
    PORT
      LAYER M3 ;
      RECT 206.595 0.000 206.613 0.054 ;
    END
  END w0_wd_in[373]
  PIN w0_wd_in[374]
    DIRECTION INPUT ;
    USE SIGNAL ;
    SHAPE ABUTMENT ;
    PORT
      LAYER M3 ;
      RECT 208.359 0.000 208.377 0.054 ;
    END
  END w0_wd_in[374]
  PIN w0_wd_in[375]
    DIRECTION INPUT ;
    USE SIGNAL ;
    SHAPE ABUTMENT ;
    PORT
      LAYER M3 ;
      RECT 210.123 0.000 210.141 0.054 ;
    END
  END w0_wd_in[375]
  PIN w0_wd_in[376]
    DIRECTION INPUT ;
    USE SIGNAL ;
    SHAPE ABUTMENT ;
    PORT
      LAYER M3 ;
      RECT 211.887 0.000 211.905 0.054 ;
    END
  END w0_wd_in[376]
  PIN w0_wd_in[377]
    DIRECTION INPUT ;
    USE SIGNAL ;
    SHAPE ABUTMENT ;
    PORT
      LAYER M3 ;
      RECT 213.651 0.000 213.669 0.054 ;
    END
  END w0_wd_in[377]
  PIN w0_wd_in[378]
    DIRECTION INPUT ;
    USE SIGNAL ;
    SHAPE ABUTMENT ;
    PORT
      LAYER M3 ;
      RECT 215.415 0.000 215.433 0.054 ;
    END
  END w0_wd_in[378]
  PIN w0_wd_in[379]
    DIRECTION INPUT ;
    USE SIGNAL ;
    SHAPE ABUTMENT ;
    PORT
      LAYER M3 ;
      RECT 217.179 0.000 217.197 0.054 ;
    END
  END w0_wd_in[379]
  PIN w0_wd_in[380]
    DIRECTION INPUT ;
    USE SIGNAL ;
    SHAPE ABUTMENT ;
    PORT
      LAYER M3 ;
      RECT 218.943 0.000 218.961 0.054 ;
    END
  END w0_wd_in[380]
  PIN w0_wd_in[381]
    DIRECTION INPUT ;
    USE SIGNAL ;
    SHAPE ABUTMENT ;
    PORT
      LAYER M3 ;
      RECT 220.707 0.000 220.725 0.054 ;
    END
  END w0_wd_in[381]
  PIN w0_wd_in[382]
    DIRECTION INPUT ;
    USE SIGNAL ;
    SHAPE ABUTMENT ;
    PORT
      LAYER M3 ;
      RECT 222.471 0.000 222.489 0.054 ;
    END
  END w0_wd_in[382]
  PIN w0_wd_in[383]
    DIRECTION INPUT ;
    USE SIGNAL ;
    SHAPE ABUTMENT ;
    PORT
      LAYER M3 ;
      RECT 224.235 0.000 224.253 0.054 ;
    END
  END w0_wd_in[383]
  PIN w0_wd_in[384]
    DIRECTION INPUT ;
    USE SIGNAL ;
    SHAPE ABUTMENT ;
    PORT
      LAYER M3 ;
      RECT 225.999 0.000 226.017 0.054 ;
    END
  END w0_wd_in[384]
  PIN w0_wd_in[385]
    DIRECTION INPUT ;
    USE SIGNAL ;
    SHAPE ABUTMENT ;
    PORT
      LAYER M3 ;
      RECT 227.763 0.000 227.781 0.054 ;
    END
  END w0_wd_in[385]
  PIN w0_wd_in[386]
    DIRECTION INPUT ;
    USE SIGNAL ;
    SHAPE ABUTMENT ;
    PORT
      LAYER M3 ;
      RECT 229.527 0.000 229.545 0.054 ;
    END
  END w0_wd_in[386]
  PIN w0_wd_in[387]
    DIRECTION INPUT ;
    USE SIGNAL ;
    SHAPE ABUTMENT ;
    PORT
      LAYER M3 ;
      RECT 231.291 0.000 231.309 0.054 ;
    END
  END w0_wd_in[387]
  PIN w0_wd_in[388]
    DIRECTION INPUT ;
    USE SIGNAL ;
    SHAPE ABUTMENT ;
    PORT
      LAYER M3 ;
      RECT 233.055 0.000 233.073 0.054 ;
    END
  END w0_wd_in[388]
  PIN w0_wd_in[389]
    DIRECTION INPUT ;
    USE SIGNAL ;
    SHAPE ABUTMENT ;
    PORT
      LAYER M3 ;
      RECT 234.819 0.000 234.837 0.054 ;
    END
  END w0_wd_in[389]
  PIN w0_wd_in[390]
    DIRECTION INPUT ;
    USE SIGNAL ;
    SHAPE ABUTMENT ;
    PORT
      LAYER M3 ;
      RECT 236.583 0.000 236.601 0.054 ;
    END
  END w0_wd_in[390]
  PIN w0_wd_in[391]
    DIRECTION INPUT ;
    USE SIGNAL ;
    SHAPE ABUTMENT ;
    PORT
      LAYER M3 ;
      RECT 238.347 0.000 238.365 0.054 ;
    END
  END w0_wd_in[391]
  PIN w0_wd_in[392]
    DIRECTION INPUT ;
    USE SIGNAL ;
    SHAPE ABUTMENT ;
    PORT
      LAYER M3 ;
      RECT 240.111 0.000 240.129 0.054 ;
    END
  END w0_wd_in[392]
  PIN w0_wd_in[393]
    DIRECTION INPUT ;
    USE SIGNAL ;
    SHAPE ABUTMENT ;
    PORT
      LAYER M3 ;
      RECT 241.875 0.000 241.893 0.054 ;
    END
  END w0_wd_in[393]
  PIN w0_wd_in[394]
    DIRECTION INPUT ;
    USE SIGNAL ;
    SHAPE ABUTMENT ;
    PORT
      LAYER M3 ;
      RECT 243.639 0.000 243.657 0.054 ;
    END
  END w0_wd_in[394]
  PIN w0_wd_in[395]
    DIRECTION INPUT ;
    USE SIGNAL ;
    SHAPE ABUTMENT ;
    PORT
      LAYER M3 ;
      RECT 245.403 0.000 245.421 0.054 ;
    END
  END w0_wd_in[395]
  PIN w0_wd_in[396]
    DIRECTION INPUT ;
    USE SIGNAL ;
    SHAPE ABUTMENT ;
    PORT
      LAYER M3 ;
      RECT 247.167 0.000 247.185 0.054 ;
    END
  END w0_wd_in[396]
  PIN w0_wd_in[397]
    DIRECTION INPUT ;
    USE SIGNAL ;
    SHAPE ABUTMENT ;
    PORT
      LAYER M3 ;
      RECT 248.931 0.000 248.949 0.054 ;
    END
  END w0_wd_in[397]
  PIN w0_wd_in[398]
    DIRECTION INPUT ;
    USE SIGNAL ;
    SHAPE ABUTMENT ;
    PORT
      LAYER M3 ;
      RECT 250.695 0.000 250.713 0.054 ;
    END
  END w0_wd_in[398]
  PIN w0_wd_in[399]
    DIRECTION INPUT ;
    USE SIGNAL ;
    SHAPE ABUTMENT ;
    PORT
      LAYER M3 ;
      RECT 252.459 0.000 252.477 0.054 ;
    END
  END w0_wd_in[399]
  PIN w0_wd_in[400]
    DIRECTION INPUT ;
    USE SIGNAL ;
    SHAPE ABUTMENT ;
    PORT
      LAYER M3 ;
      RECT 254.223 0.000 254.241 0.054 ;
    END
  END w0_wd_in[400]
  PIN w0_wd_in[401]
    DIRECTION INPUT ;
    USE SIGNAL ;
    SHAPE ABUTMENT ;
    PORT
      LAYER M3 ;
      RECT 255.987 0.000 256.005 0.054 ;
    END
  END w0_wd_in[401]
  PIN w0_wd_in[402]
    DIRECTION INPUT ;
    USE SIGNAL ;
    SHAPE ABUTMENT ;
    PORT
      LAYER M3 ;
      RECT 257.751 0.000 257.769 0.054 ;
    END
  END w0_wd_in[402]
  PIN w0_wd_in[403]
    DIRECTION INPUT ;
    USE SIGNAL ;
    SHAPE ABUTMENT ;
    PORT
      LAYER M3 ;
      RECT 259.515 0.000 259.533 0.054 ;
    END
  END w0_wd_in[403]
  PIN w0_wd_in[404]
    DIRECTION INPUT ;
    USE SIGNAL ;
    SHAPE ABUTMENT ;
    PORT
      LAYER M3 ;
      RECT 261.279 0.000 261.297 0.054 ;
    END
  END w0_wd_in[404]
  PIN w0_wd_in[405]
    DIRECTION INPUT ;
    USE SIGNAL ;
    SHAPE ABUTMENT ;
    PORT
      LAYER M3 ;
      RECT 263.043 0.000 263.061 0.054 ;
    END
  END w0_wd_in[405]
  PIN w0_wd_in[406]
    DIRECTION INPUT ;
    USE SIGNAL ;
    SHAPE ABUTMENT ;
    PORT
      LAYER M3 ;
      RECT 264.807 0.000 264.825 0.054 ;
    END
  END w0_wd_in[406]
  PIN w0_wd_in[407]
    DIRECTION INPUT ;
    USE SIGNAL ;
    SHAPE ABUTMENT ;
    PORT
      LAYER M3 ;
      RECT 266.571 0.000 266.589 0.054 ;
    END
  END w0_wd_in[407]
  PIN w0_wd_in[408]
    DIRECTION INPUT ;
    USE SIGNAL ;
    SHAPE ABUTMENT ;
    PORT
      LAYER M3 ;
      RECT 268.335 0.000 268.353 0.054 ;
    END
  END w0_wd_in[408]
  PIN w0_wd_in[409]
    DIRECTION INPUT ;
    USE SIGNAL ;
    SHAPE ABUTMENT ;
    PORT
      LAYER M3 ;
      RECT 270.099 0.000 270.117 0.054 ;
    END
  END w0_wd_in[409]
  PIN w0_wd_in[410]
    DIRECTION INPUT ;
    USE SIGNAL ;
    SHAPE ABUTMENT ;
    PORT
      LAYER M3 ;
      RECT 271.863 0.000 271.881 0.054 ;
    END
  END w0_wd_in[410]
  PIN w0_wd_in[411]
    DIRECTION INPUT ;
    USE SIGNAL ;
    SHAPE ABUTMENT ;
    PORT
      LAYER M3 ;
      RECT 273.627 0.000 273.645 0.054 ;
    END
  END w0_wd_in[411]
  PIN w0_wd_in[412]
    DIRECTION INPUT ;
    USE SIGNAL ;
    SHAPE ABUTMENT ;
    PORT
      LAYER M3 ;
      RECT 275.391 0.000 275.409 0.054 ;
    END
  END w0_wd_in[412]
  PIN w0_wd_in[413]
    DIRECTION INPUT ;
    USE SIGNAL ;
    SHAPE ABUTMENT ;
    PORT
      LAYER M3 ;
      RECT 277.155 0.000 277.173 0.054 ;
    END
  END w0_wd_in[413]
  PIN w0_wd_in[414]
    DIRECTION INPUT ;
    USE SIGNAL ;
    SHAPE ABUTMENT ;
    PORT
      LAYER M3 ;
      RECT 278.919 0.000 278.937 0.054 ;
    END
  END w0_wd_in[414]
  PIN w0_wd_in[415]
    DIRECTION INPUT ;
    USE SIGNAL ;
    SHAPE ABUTMENT ;
    PORT
      LAYER M3 ;
      RECT 280.683 0.000 280.701 0.054 ;
    END
  END w0_wd_in[415]
  PIN w0_wd_in[416]
    DIRECTION INPUT ;
    USE SIGNAL ;
    SHAPE ABUTMENT ;
    PORT
      LAYER M3 ;
      RECT 282.447 0.000 282.465 0.054 ;
    END
  END w0_wd_in[416]
  PIN w0_wd_in[417]
    DIRECTION INPUT ;
    USE SIGNAL ;
    SHAPE ABUTMENT ;
    PORT
      LAYER M3 ;
      RECT 284.211 0.000 284.229 0.054 ;
    END
  END w0_wd_in[417]
  PIN w0_wd_in[418]
    DIRECTION INPUT ;
    USE SIGNAL ;
    SHAPE ABUTMENT ;
    PORT
      LAYER M3 ;
      RECT 285.975 0.000 285.993 0.054 ;
    END
  END w0_wd_in[418]
  PIN w0_wd_in[419]
    DIRECTION INPUT ;
    USE SIGNAL ;
    SHAPE ABUTMENT ;
    PORT
      LAYER M3 ;
      RECT 287.739 0.000 287.757 0.054 ;
    END
  END w0_wd_in[419]
  PIN w0_wd_in[420]
    DIRECTION INPUT ;
    USE SIGNAL ;
    SHAPE ABUTMENT ;
    PORT
      LAYER M3 ;
      RECT 289.503 0.000 289.521 0.054 ;
    END
  END w0_wd_in[420]
  PIN w0_wd_in[421]
    DIRECTION INPUT ;
    USE SIGNAL ;
    SHAPE ABUTMENT ;
    PORT
      LAYER M3 ;
      RECT 291.267 0.000 291.285 0.054 ;
    END
  END w0_wd_in[421]
  PIN w0_wd_in[422]
    DIRECTION INPUT ;
    USE SIGNAL ;
    SHAPE ABUTMENT ;
    PORT
      LAYER M3 ;
      RECT 293.031 0.000 293.049 0.054 ;
    END
  END w0_wd_in[422]
  PIN w0_wd_in[423]
    DIRECTION INPUT ;
    USE SIGNAL ;
    SHAPE ABUTMENT ;
    PORT
      LAYER M3 ;
      RECT 294.795 0.000 294.813 0.054 ;
    END
  END w0_wd_in[423]
  PIN w0_wd_in[424]
    DIRECTION INPUT ;
    USE SIGNAL ;
    SHAPE ABUTMENT ;
    PORT
      LAYER M3 ;
      RECT 296.559 0.000 296.577 0.054 ;
    END
  END w0_wd_in[424]
  PIN w0_wd_in[425]
    DIRECTION INPUT ;
    USE SIGNAL ;
    SHAPE ABUTMENT ;
    PORT
      LAYER M3 ;
      RECT 298.323 0.000 298.341 0.054 ;
    END
  END w0_wd_in[425]
  PIN w0_wd_in[426]
    DIRECTION INPUT ;
    USE SIGNAL ;
    SHAPE ABUTMENT ;
    PORT
      LAYER M3 ;
      RECT 300.087 0.000 300.105 0.054 ;
    END
  END w0_wd_in[426]
  PIN w0_wd_in[427]
    DIRECTION INPUT ;
    USE SIGNAL ;
    SHAPE ABUTMENT ;
    PORT
      LAYER M3 ;
      RECT 301.851 0.000 301.869 0.054 ;
    END
  END w0_wd_in[427]
  PIN w0_wd_in[428]
    DIRECTION INPUT ;
    USE SIGNAL ;
    SHAPE ABUTMENT ;
    PORT
      LAYER M3 ;
      RECT 303.615 0.000 303.633 0.054 ;
    END
  END w0_wd_in[428]
  PIN w0_wd_in[429]
    DIRECTION INPUT ;
    USE SIGNAL ;
    SHAPE ABUTMENT ;
    PORT
      LAYER M3 ;
      RECT 305.379 0.000 305.397 0.054 ;
    END
  END w0_wd_in[429]
  PIN w0_wd_in[430]
    DIRECTION INPUT ;
    USE SIGNAL ;
    SHAPE ABUTMENT ;
    PORT
      LAYER M3 ;
      RECT 307.143 0.000 307.161 0.054 ;
    END
  END w0_wd_in[430]
  PIN w0_wd_in[431]
    DIRECTION INPUT ;
    USE SIGNAL ;
    SHAPE ABUTMENT ;
    PORT
      LAYER M3 ;
      RECT 308.907 0.000 308.925 0.054 ;
    END
  END w0_wd_in[431]
  PIN w0_wd_in[432]
    DIRECTION INPUT ;
    USE SIGNAL ;
    SHAPE ABUTMENT ;
    PORT
      LAYER M3 ;
      RECT 310.671 0.000 310.689 0.054 ;
    END
  END w0_wd_in[432]
  PIN w0_wd_in[433]
    DIRECTION INPUT ;
    USE SIGNAL ;
    SHAPE ABUTMENT ;
    PORT
      LAYER M3 ;
      RECT 312.435 0.000 312.453 0.054 ;
    END
  END w0_wd_in[433]
  PIN w0_wd_in[434]
    DIRECTION INPUT ;
    USE SIGNAL ;
    SHAPE ABUTMENT ;
    PORT
      LAYER M3 ;
      RECT 314.199 0.000 314.217 0.054 ;
    END
  END w0_wd_in[434]
  PIN w0_wd_in[435]
    DIRECTION INPUT ;
    USE SIGNAL ;
    SHAPE ABUTMENT ;
    PORT
      LAYER M3 ;
      RECT 315.963 0.000 315.981 0.054 ;
    END
  END w0_wd_in[435]
  PIN w0_wd_in[436]
    DIRECTION INPUT ;
    USE SIGNAL ;
    SHAPE ABUTMENT ;
    PORT
      LAYER M3 ;
      RECT 317.727 0.000 317.745 0.054 ;
    END
  END w0_wd_in[436]
  PIN w0_wd_in[437]
    DIRECTION INPUT ;
    USE SIGNAL ;
    SHAPE ABUTMENT ;
    PORT
      LAYER M3 ;
      RECT 319.491 0.000 319.509 0.054 ;
    END
  END w0_wd_in[437]
  PIN w0_wd_in[438]
    DIRECTION INPUT ;
    USE SIGNAL ;
    SHAPE ABUTMENT ;
    PORT
      LAYER M3 ;
      RECT 321.255 0.000 321.273 0.054 ;
    END
  END w0_wd_in[438]
  PIN w0_wd_in[439]
    DIRECTION INPUT ;
    USE SIGNAL ;
    SHAPE ABUTMENT ;
    PORT
      LAYER M3 ;
      RECT 323.019 0.000 323.037 0.054 ;
    END
  END w0_wd_in[439]
  PIN w0_wd_in[440]
    DIRECTION INPUT ;
    USE SIGNAL ;
    SHAPE ABUTMENT ;
    PORT
      LAYER M3 ;
      RECT 324.783 0.000 324.801 0.054 ;
    END
  END w0_wd_in[440]
  PIN w0_wd_in[441]
    DIRECTION INPUT ;
    USE SIGNAL ;
    SHAPE ABUTMENT ;
    PORT
      LAYER M3 ;
      RECT 326.547 0.000 326.565 0.054 ;
    END
  END w0_wd_in[441]
  PIN w0_wd_in[442]
    DIRECTION INPUT ;
    USE SIGNAL ;
    SHAPE ABUTMENT ;
    PORT
      LAYER M3 ;
      RECT 328.311 0.000 328.329 0.054 ;
    END
  END w0_wd_in[442]
  PIN w0_wd_in[443]
    DIRECTION INPUT ;
    USE SIGNAL ;
    SHAPE ABUTMENT ;
    PORT
      LAYER M3 ;
      RECT 330.075 0.000 330.093 0.054 ;
    END
  END w0_wd_in[443]
  PIN w0_wd_in[444]
    DIRECTION INPUT ;
    USE SIGNAL ;
    SHAPE ABUTMENT ;
    PORT
      LAYER M3 ;
      RECT 331.839 0.000 331.857 0.054 ;
    END
  END w0_wd_in[444]
  PIN w0_wd_in[445]
    DIRECTION INPUT ;
    USE SIGNAL ;
    SHAPE ABUTMENT ;
    PORT
      LAYER M3 ;
      RECT 333.603 0.000 333.621 0.054 ;
    END
  END w0_wd_in[445]
  PIN w0_wd_in[446]
    DIRECTION INPUT ;
    USE SIGNAL ;
    SHAPE ABUTMENT ;
    PORT
      LAYER M3 ;
      RECT 335.367 0.000 335.385 0.054 ;
    END
  END w0_wd_in[446]
  PIN w0_wd_in[447]
    DIRECTION INPUT ;
    USE SIGNAL ;
    SHAPE ABUTMENT ;
    PORT
      LAYER M3 ;
      RECT 337.131 0.000 337.149 0.054 ;
    END
  END w0_wd_in[447]
  PIN w0_wd_in[448]
    DIRECTION INPUT ;
    USE SIGNAL ;
    SHAPE ABUTMENT ;
    PORT
      LAYER M3 ;
      RECT 338.895 0.000 338.913 0.054 ;
    END
  END w0_wd_in[448]
  PIN w0_wd_in[449]
    DIRECTION INPUT ;
    USE SIGNAL ;
    SHAPE ABUTMENT ;
    PORT
      LAYER M3 ;
      RECT 340.659 0.000 340.677 0.054 ;
    END
  END w0_wd_in[449]
  PIN w0_wd_in[450]
    DIRECTION INPUT ;
    USE SIGNAL ;
    SHAPE ABUTMENT ;
    PORT
      LAYER M3 ;
      RECT 342.423 0.000 342.441 0.054 ;
    END
  END w0_wd_in[450]
  PIN w0_wd_in[451]
    DIRECTION INPUT ;
    USE SIGNAL ;
    SHAPE ABUTMENT ;
    PORT
      LAYER M3 ;
      RECT 344.187 0.000 344.205 0.054 ;
    END
  END w0_wd_in[451]
  PIN w0_wd_in[452]
    DIRECTION INPUT ;
    USE SIGNAL ;
    SHAPE ABUTMENT ;
    PORT
      LAYER M3 ;
      RECT 345.951 0.000 345.969 0.054 ;
    END
  END w0_wd_in[452]
  PIN w0_wd_in[453]
    DIRECTION INPUT ;
    USE SIGNAL ;
    SHAPE ABUTMENT ;
    PORT
      LAYER M3 ;
      RECT 347.715 0.000 347.733 0.054 ;
    END
  END w0_wd_in[453]
  PIN w0_wd_in[454]
    DIRECTION INPUT ;
    USE SIGNAL ;
    SHAPE ABUTMENT ;
    PORT
      LAYER M3 ;
      RECT 349.479 0.000 349.497 0.054 ;
    END
  END w0_wd_in[454]
  PIN w0_wd_in[455]
    DIRECTION INPUT ;
    USE SIGNAL ;
    SHAPE ABUTMENT ;
    PORT
      LAYER M3 ;
      RECT 351.243 0.000 351.261 0.054 ;
    END
  END w0_wd_in[455]
  PIN w0_wd_in[456]
    DIRECTION INPUT ;
    USE SIGNAL ;
    SHAPE ABUTMENT ;
    PORT
      LAYER M3 ;
      RECT 353.007 0.000 353.025 0.054 ;
    END
  END w0_wd_in[456]
  PIN w0_wd_in[457]
    DIRECTION INPUT ;
    USE SIGNAL ;
    SHAPE ABUTMENT ;
    PORT
      LAYER M3 ;
      RECT 354.771 0.000 354.789 0.054 ;
    END
  END w0_wd_in[457]
  PIN w0_wd_in[458]
    DIRECTION INPUT ;
    USE SIGNAL ;
    SHAPE ABUTMENT ;
    PORT
      LAYER M3 ;
      RECT 356.535 0.000 356.553 0.054 ;
    END
  END w0_wd_in[458]
  PIN w0_wd_in[459]
    DIRECTION INPUT ;
    USE SIGNAL ;
    SHAPE ABUTMENT ;
    PORT
      LAYER M3 ;
      RECT 358.299 0.000 358.317 0.054 ;
    END
  END w0_wd_in[459]
  PIN w0_wd_in[460]
    DIRECTION INPUT ;
    USE SIGNAL ;
    SHAPE ABUTMENT ;
    PORT
      LAYER M3 ;
      RECT 360.063 0.000 360.081 0.054 ;
    END
  END w0_wd_in[460]
  PIN w0_wd_in[461]
    DIRECTION INPUT ;
    USE SIGNAL ;
    SHAPE ABUTMENT ;
    PORT
      LAYER M3 ;
      RECT 361.827 0.000 361.845 0.054 ;
    END
  END w0_wd_in[461]
  PIN w0_wd_in[462]
    DIRECTION INPUT ;
    USE SIGNAL ;
    SHAPE ABUTMENT ;
    PORT
      LAYER M3 ;
      RECT 363.591 0.000 363.609 0.054 ;
    END
  END w0_wd_in[462]
  PIN w0_wd_in[463]
    DIRECTION INPUT ;
    USE SIGNAL ;
    SHAPE ABUTMENT ;
    PORT
      LAYER M3 ;
      RECT 365.355 0.000 365.373 0.054 ;
    END
  END w0_wd_in[463]
  PIN w0_wd_in[464]
    DIRECTION INPUT ;
    USE SIGNAL ;
    SHAPE ABUTMENT ;
    PORT
      LAYER M3 ;
      RECT 367.119 0.000 367.137 0.054 ;
    END
  END w0_wd_in[464]
  PIN w0_wd_in[465]
    DIRECTION INPUT ;
    USE SIGNAL ;
    SHAPE ABUTMENT ;
    PORT
      LAYER M3 ;
      RECT 368.883 0.000 368.901 0.054 ;
    END
  END w0_wd_in[465]
  PIN w0_wd_in[466]
    DIRECTION INPUT ;
    USE SIGNAL ;
    SHAPE ABUTMENT ;
    PORT
      LAYER M3 ;
      RECT 370.647 0.000 370.665 0.054 ;
    END
  END w0_wd_in[466]
  PIN w0_wd_in[467]
    DIRECTION INPUT ;
    USE SIGNAL ;
    SHAPE ABUTMENT ;
    PORT
      LAYER M3 ;
      RECT 372.411 0.000 372.429 0.054 ;
    END
  END w0_wd_in[467]
  PIN w0_wd_in[468]
    DIRECTION INPUT ;
    USE SIGNAL ;
    SHAPE ABUTMENT ;
    PORT
      LAYER M3 ;
      RECT 374.175 0.000 374.193 0.054 ;
    END
  END w0_wd_in[468]
  PIN w0_wd_in[469]
    DIRECTION INPUT ;
    USE SIGNAL ;
    SHAPE ABUTMENT ;
    PORT
      LAYER M3 ;
      RECT 375.939 0.000 375.957 0.054 ;
    END
  END w0_wd_in[469]
  PIN w0_wd_in[470]
    DIRECTION INPUT ;
    USE SIGNAL ;
    SHAPE ABUTMENT ;
    PORT
      LAYER M3 ;
      RECT 377.703 0.000 377.721 0.054 ;
    END
  END w0_wd_in[470]
  PIN w0_wd_in[471]
    DIRECTION INPUT ;
    USE SIGNAL ;
    SHAPE ABUTMENT ;
    PORT
      LAYER M3 ;
      RECT 379.467 0.000 379.485 0.054 ;
    END
  END w0_wd_in[471]
  PIN w0_wd_in[472]
    DIRECTION INPUT ;
    USE SIGNAL ;
    SHAPE ABUTMENT ;
    PORT
      LAYER M3 ;
      RECT 381.231 0.000 381.249 0.054 ;
    END
  END w0_wd_in[472]
  PIN w0_wd_in[473]
    DIRECTION INPUT ;
    USE SIGNAL ;
    SHAPE ABUTMENT ;
    PORT
      LAYER M3 ;
      RECT 382.995 0.000 383.013 0.054 ;
    END
  END w0_wd_in[473]
  PIN w0_wd_in[474]
    DIRECTION INPUT ;
    USE SIGNAL ;
    SHAPE ABUTMENT ;
    PORT
      LAYER M3 ;
      RECT 384.759 0.000 384.777 0.054 ;
    END
  END w0_wd_in[474]
  PIN w0_wd_in[475]
    DIRECTION INPUT ;
    USE SIGNAL ;
    SHAPE ABUTMENT ;
    PORT
      LAYER M3 ;
      RECT 386.523 0.000 386.541 0.054 ;
    END
  END w0_wd_in[475]
  PIN w0_wd_in[476]
    DIRECTION INPUT ;
    USE SIGNAL ;
    SHAPE ABUTMENT ;
    PORT
      LAYER M3 ;
      RECT 388.287 0.000 388.305 0.054 ;
    END
  END w0_wd_in[476]
  PIN w0_wd_in[477]
    DIRECTION INPUT ;
    USE SIGNAL ;
    SHAPE ABUTMENT ;
    PORT
      LAYER M3 ;
      RECT 390.051 0.000 390.069 0.054 ;
    END
  END w0_wd_in[477]
  PIN w0_wd_in[478]
    DIRECTION INPUT ;
    USE SIGNAL ;
    SHAPE ABUTMENT ;
    PORT
      LAYER M3 ;
      RECT 391.815 0.000 391.833 0.054 ;
    END
  END w0_wd_in[478]
  PIN w0_wd_in[479]
    DIRECTION INPUT ;
    USE SIGNAL ;
    SHAPE ABUTMENT ;
    PORT
      LAYER M3 ;
      RECT 393.579 0.000 393.597 0.054 ;
    END
  END w0_wd_in[479]
  PIN w0_wd_in[480]
    DIRECTION INPUT ;
    USE SIGNAL ;
    SHAPE ABUTMENT ;
    PORT
      LAYER M3 ;
      RECT 395.343 0.000 395.361 0.054 ;
    END
  END w0_wd_in[480]
  PIN w0_wd_in[481]
    DIRECTION INPUT ;
    USE SIGNAL ;
    SHAPE ABUTMENT ;
    PORT
      LAYER M3 ;
      RECT 397.107 0.000 397.125 0.054 ;
    END
  END w0_wd_in[481]
  PIN w0_wd_in[482]
    DIRECTION INPUT ;
    USE SIGNAL ;
    SHAPE ABUTMENT ;
    PORT
      LAYER M3 ;
      RECT 398.871 0.000 398.889 0.054 ;
    END
  END w0_wd_in[482]
  PIN w0_wd_in[483]
    DIRECTION INPUT ;
    USE SIGNAL ;
    SHAPE ABUTMENT ;
    PORT
      LAYER M3 ;
      RECT 400.635 0.000 400.653 0.054 ;
    END
  END w0_wd_in[483]
  PIN w0_wd_in[484]
    DIRECTION INPUT ;
    USE SIGNAL ;
    SHAPE ABUTMENT ;
    PORT
      LAYER M3 ;
      RECT 402.399 0.000 402.417 0.054 ;
    END
  END w0_wd_in[484]
  PIN w0_wd_in[485]
    DIRECTION INPUT ;
    USE SIGNAL ;
    SHAPE ABUTMENT ;
    PORT
      LAYER M3 ;
      RECT 404.163 0.000 404.181 0.054 ;
    END
  END w0_wd_in[485]
  PIN w0_wd_in[486]
    DIRECTION INPUT ;
    USE SIGNAL ;
    SHAPE ABUTMENT ;
    PORT
      LAYER M3 ;
      RECT 405.927 0.000 405.945 0.054 ;
    END
  END w0_wd_in[486]
  PIN w0_wd_in[487]
    DIRECTION INPUT ;
    USE SIGNAL ;
    SHAPE ABUTMENT ;
    PORT
      LAYER M3 ;
      RECT 407.691 0.000 407.709 0.054 ;
    END
  END w0_wd_in[487]
  PIN w0_wd_in[488]
    DIRECTION INPUT ;
    USE SIGNAL ;
    SHAPE ABUTMENT ;
    PORT
      LAYER M3 ;
      RECT 409.455 0.000 409.473 0.054 ;
    END
  END w0_wd_in[488]
  PIN w0_wd_in[489]
    DIRECTION INPUT ;
    USE SIGNAL ;
    SHAPE ABUTMENT ;
    PORT
      LAYER M3 ;
      RECT 411.219 0.000 411.237 0.054 ;
    END
  END w0_wd_in[489]
  PIN w0_wd_in[490]
    DIRECTION INPUT ;
    USE SIGNAL ;
    SHAPE ABUTMENT ;
    PORT
      LAYER M3 ;
      RECT 412.983 0.000 413.001 0.054 ;
    END
  END w0_wd_in[490]
  PIN w0_wd_in[491]
    DIRECTION INPUT ;
    USE SIGNAL ;
    SHAPE ABUTMENT ;
    PORT
      LAYER M3 ;
      RECT 414.747 0.000 414.765 0.054 ;
    END
  END w0_wd_in[491]
  PIN w0_wd_in[492]
    DIRECTION INPUT ;
    USE SIGNAL ;
    SHAPE ABUTMENT ;
    PORT
      LAYER M3 ;
      RECT 416.511 0.000 416.529 0.054 ;
    END
  END w0_wd_in[492]
  PIN w0_wd_in[493]
    DIRECTION INPUT ;
    USE SIGNAL ;
    SHAPE ABUTMENT ;
    PORT
      LAYER M3 ;
      RECT 418.275 0.000 418.293 0.054 ;
    END
  END w0_wd_in[493]
  PIN w0_wd_in[494]
    DIRECTION INPUT ;
    USE SIGNAL ;
    SHAPE ABUTMENT ;
    PORT
      LAYER M3 ;
      RECT 420.039 0.000 420.057 0.054 ;
    END
  END w0_wd_in[494]
  PIN w0_wd_in[495]
    DIRECTION INPUT ;
    USE SIGNAL ;
    SHAPE ABUTMENT ;
    PORT
      LAYER M3 ;
      RECT 421.803 0.000 421.821 0.054 ;
    END
  END w0_wd_in[495]
  PIN w0_wd_in[496]
    DIRECTION INPUT ;
    USE SIGNAL ;
    SHAPE ABUTMENT ;
    PORT
      LAYER M3 ;
      RECT 423.567 0.000 423.585 0.054 ;
    END
  END w0_wd_in[496]
  PIN w0_wd_in[497]
    DIRECTION INPUT ;
    USE SIGNAL ;
    SHAPE ABUTMENT ;
    PORT
      LAYER M3 ;
      RECT 425.331 0.000 425.349 0.054 ;
    END
  END w0_wd_in[497]
  PIN w0_wd_in[498]
    DIRECTION INPUT ;
    USE SIGNAL ;
    SHAPE ABUTMENT ;
    PORT
      LAYER M3 ;
      RECT 427.095 0.000 427.113 0.054 ;
    END
  END w0_wd_in[498]
  PIN w0_wd_in[499]
    DIRECTION INPUT ;
    USE SIGNAL ;
    SHAPE ABUTMENT ;
    PORT
      LAYER M3 ;
      RECT 428.859 0.000 428.877 0.054 ;
    END
  END w0_wd_in[499]
  PIN w0_wd_in[500]
    DIRECTION INPUT ;
    USE SIGNAL ;
    SHAPE ABUTMENT ;
    PORT
      LAYER M3 ;
      RECT 430.623 0.000 430.641 0.054 ;
    END
  END w0_wd_in[500]
  PIN w0_wd_in[501]
    DIRECTION INPUT ;
    USE SIGNAL ;
    SHAPE ABUTMENT ;
    PORT
      LAYER M3 ;
      RECT 432.387 0.000 432.405 0.054 ;
    END
  END w0_wd_in[501]
  PIN w0_wd_in[502]
    DIRECTION INPUT ;
    USE SIGNAL ;
    SHAPE ABUTMENT ;
    PORT
      LAYER M3 ;
      RECT 434.151 0.000 434.169 0.054 ;
    END
  END w0_wd_in[502]
  PIN w0_wd_in[503]
    DIRECTION INPUT ;
    USE SIGNAL ;
    SHAPE ABUTMENT ;
    PORT
      LAYER M3 ;
      RECT 435.915 0.000 435.933 0.054 ;
    END
  END w0_wd_in[503]
  PIN w0_wd_in[504]
    DIRECTION INPUT ;
    USE SIGNAL ;
    SHAPE ABUTMENT ;
    PORT
      LAYER M3 ;
      RECT 437.679 0.000 437.697 0.054 ;
    END
  END w0_wd_in[504]
  PIN w0_wd_in[505]
    DIRECTION INPUT ;
    USE SIGNAL ;
    SHAPE ABUTMENT ;
    PORT
      LAYER M3 ;
      RECT 439.443 0.000 439.461 0.054 ;
    END
  END w0_wd_in[505]
  PIN w0_wd_in[506]
    DIRECTION INPUT ;
    USE SIGNAL ;
    SHAPE ABUTMENT ;
    PORT
      LAYER M3 ;
      RECT 441.207 0.000 441.225 0.054 ;
    END
  END w0_wd_in[506]
  PIN w0_wd_in[507]
    DIRECTION INPUT ;
    USE SIGNAL ;
    SHAPE ABUTMENT ;
    PORT
      LAYER M3 ;
      RECT 442.971 0.000 442.989 0.054 ;
    END
  END w0_wd_in[507]
  PIN w0_wd_in[508]
    DIRECTION INPUT ;
    USE SIGNAL ;
    SHAPE ABUTMENT ;
    PORT
      LAYER M3 ;
      RECT 444.735 0.000 444.753 0.054 ;
    END
  END w0_wd_in[508]
  PIN w0_wd_in[509]
    DIRECTION INPUT ;
    USE SIGNAL ;
    SHAPE ABUTMENT ;
    PORT
      LAYER M3 ;
      RECT 446.499 0.000 446.517 0.054 ;
    END
  END w0_wd_in[509]
  PIN w0_wd_in[510]
    DIRECTION INPUT ;
    USE SIGNAL ;
    SHAPE ABUTMENT ;
    PORT
      LAYER M3 ;
      RECT 448.263 0.000 448.281 0.054 ;
    END
  END w0_wd_in[510]
  PIN w0_wd_in[511]
    DIRECTION INPUT ;
    USE SIGNAL ;
    SHAPE ABUTMENT ;
    PORT
      LAYER M3 ;
      RECT 450.027 0.000 450.045 0.054 ;
    END
  END w0_wd_in[511]
  PIN r0_rd_out[0]
    DIRECTION OUTPUT ;
    USE SIGNAL ;
    SHAPE ABUTMENT ;
    PORT
      LAYER M3 ;
      RECT 451.791 0.000 451.809 0.054 ;
    END
  END r0_rd_out[0]
  PIN r0_rd_out[1]
    DIRECTION OUTPUT ;
    USE SIGNAL ;
    SHAPE ABUTMENT ;
    PORT
      LAYER M3 ;
      RECT 453.555 0.000 453.573 0.054 ;
    END
  END r0_rd_out[1]
  PIN r0_rd_out[2]
    DIRECTION OUTPUT ;
    USE SIGNAL ;
    SHAPE ABUTMENT ;
    PORT
      LAYER M3 ;
      RECT 455.319 0.000 455.337 0.054 ;
    END
  END r0_rd_out[2]
  PIN r0_rd_out[3]
    DIRECTION OUTPUT ;
    USE SIGNAL ;
    SHAPE ABUTMENT ;
    PORT
      LAYER M3 ;
      RECT 457.083 0.000 457.101 0.054 ;
    END
  END r0_rd_out[3]
  PIN r0_rd_out[4]
    DIRECTION OUTPUT ;
    USE SIGNAL ;
    SHAPE ABUTMENT ;
    PORT
      LAYER M3 ;
      RECT 458.847 0.000 458.865 0.054 ;
    END
  END r0_rd_out[4]
  PIN r0_rd_out[5]
    DIRECTION OUTPUT ;
    USE SIGNAL ;
    SHAPE ABUTMENT ;
    PORT
      LAYER M3 ;
      RECT 460.611 0.000 460.629 0.054 ;
    END
  END r0_rd_out[5]
  PIN r0_rd_out[6]
    DIRECTION OUTPUT ;
    USE SIGNAL ;
    SHAPE ABUTMENT ;
    PORT
      LAYER M3 ;
      RECT 462.375 0.000 462.393 0.054 ;
    END
  END r0_rd_out[6]
  PIN r0_rd_out[7]
    DIRECTION OUTPUT ;
    USE SIGNAL ;
    SHAPE ABUTMENT ;
    PORT
      LAYER M3 ;
      RECT 464.139 0.000 464.157 0.054 ;
    END
  END r0_rd_out[7]
  PIN r0_rd_out[8]
    DIRECTION OUTPUT ;
    USE SIGNAL ;
    SHAPE ABUTMENT ;
    PORT
      LAYER M3 ;
      RECT 465.903 0.000 465.921 0.054 ;
    END
  END r0_rd_out[8]
  PIN r0_rd_out[9]
    DIRECTION OUTPUT ;
    USE SIGNAL ;
    SHAPE ABUTMENT ;
    PORT
      LAYER M3 ;
      RECT 467.667 0.000 467.685 0.054 ;
    END
  END r0_rd_out[9]
  PIN r0_rd_out[10]
    DIRECTION OUTPUT ;
    USE SIGNAL ;
    SHAPE ABUTMENT ;
    PORT
      LAYER M3 ;
      RECT 469.431 0.000 469.449 0.054 ;
    END
  END r0_rd_out[10]
  PIN r0_rd_out[11]
    DIRECTION OUTPUT ;
    USE SIGNAL ;
    SHAPE ABUTMENT ;
    PORT
      LAYER M3 ;
      RECT 471.195 0.000 471.213 0.054 ;
    END
  END r0_rd_out[11]
  PIN r0_rd_out[12]
    DIRECTION OUTPUT ;
    USE SIGNAL ;
    SHAPE ABUTMENT ;
    PORT
      LAYER M3 ;
      RECT 472.959 0.000 472.977 0.054 ;
    END
  END r0_rd_out[12]
  PIN r0_rd_out[13]
    DIRECTION OUTPUT ;
    USE SIGNAL ;
    SHAPE ABUTMENT ;
    PORT
      LAYER M3 ;
      RECT 474.723 0.000 474.741 0.054 ;
    END
  END r0_rd_out[13]
  PIN r0_rd_out[14]
    DIRECTION OUTPUT ;
    USE SIGNAL ;
    SHAPE ABUTMENT ;
    PORT
      LAYER M3 ;
      RECT 476.487 0.000 476.505 0.054 ;
    END
  END r0_rd_out[14]
  PIN r0_rd_out[15]
    DIRECTION OUTPUT ;
    USE SIGNAL ;
    SHAPE ABUTMENT ;
    PORT
      LAYER M3 ;
      RECT 478.251 0.000 478.269 0.054 ;
    END
  END r0_rd_out[15]
  PIN r0_rd_out[16]
    DIRECTION OUTPUT ;
    USE SIGNAL ;
    SHAPE ABUTMENT ;
    PORT
      LAYER M3 ;
      RECT 480.015 0.000 480.033 0.054 ;
    END
  END r0_rd_out[16]
  PIN r0_rd_out[17]
    DIRECTION OUTPUT ;
    USE SIGNAL ;
    SHAPE ABUTMENT ;
    PORT
      LAYER M3 ;
      RECT 481.779 0.000 481.797 0.054 ;
    END
  END r0_rd_out[17]
  PIN r0_rd_out[18]
    DIRECTION OUTPUT ;
    USE SIGNAL ;
    SHAPE ABUTMENT ;
    PORT
      LAYER M3 ;
      RECT 483.543 0.000 483.561 0.054 ;
    END
  END r0_rd_out[18]
  PIN r0_rd_out[19]
    DIRECTION OUTPUT ;
    USE SIGNAL ;
    SHAPE ABUTMENT ;
    PORT
      LAYER M3 ;
      RECT 485.307 0.000 485.325 0.054 ;
    END
  END r0_rd_out[19]
  PIN r0_rd_out[20]
    DIRECTION OUTPUT ;
    USE SIGNAL ;
    SHAPE ABUTMENT ;
    PORT
      LAYER M3 ;
      RECT 487.071 0.000 487.089 0.054 ;
    END
  END r0_rd_out[20]
  PIN r0_rd_out[21]
    DIRECTION OUTPUT ;
    USE SIGNAL ;
    SHAPE ABUTMENT ;
    PORT
      LAYER M3 ;
      RECT 488.835 0.000 488.853 0.054 ;
    END
  END r0_rd_out[21]
  PIN r0_rd_out[22]
    DIRECTION OUTPUT ;
    USE SIGNAL ;
    SHAPE ABUTMENT ;
    PORT
      LAYER M3 ;
      RECT 490.599 0.000 490.617 0.054 ;
    END
  END r0_rd_out[22]
  PIN r0_rd_out[23]
    DIRECTION OUTPUT ;
    USE SIGNAL ;
    SHAPE ABUTMENT ;
    PORT
      LAYER M3 ;
      RECT 492.363 0.000 492.381 0.054 ;
    END
  END r0_rd_out[23]
  PIN r0_rd_out[24]
    DIRECTION OUTPUT ;
    USE SIGNAL ;
    SHAPE ABUTMENT ;
    PORT
      LAYER M3 ;
      RECT 494.127 0.000 494.145 0.054 ;
    END
  END r0_rd_out[24]
  PIN r0_rd_out[25]
    DIRECTION OUTPUT ;
    USE SIGNAL ;
    SHAPE ABUTMENT ;
    PORT
      LAYER M3 ;
      RECT 495.891 0.000 495.909 0.054 ;
    END
  END r0_rd_out[25]
  PIN r0_rd_out[26]
    DIRECTION OUTPUT ;
    USE SIGNAL ;
    SHAPE ABUTMENT ;
    PORT
      LAYER M3 ;
      RECT 497.655 0.000 497.673 0.054 ;
    END
  END r0_rd_out[26]
  PIN r0_rd_out[27]
    DIRECTION OUTPUT ;
    USE SIGNAL ;
    SHAPE ABUTMENT ;
    PORT
      LAYER M3 ;
      RECT 499.419 0.000 499.437 0.054 ;
    END
  END r0_rd_out[27]
  PIN r0_rd_out[28]
    DIRECTION OUTPUT ;
    USE SIGNAL ;
    SHAPE ABUTMENT ;
    PORT
      LAYER M3 ;
      RECT 501.183 0.000 501.201 0.054 ;
    END
  END r0_rd_out[28]
  PIN r0_rd_out[29]
    DIRECTION OUTPUT ;
    USE SIGNAL ;
    SHAPE ABUTMENT ;
    PORT
      LAYER M3 ;
      RECT 502.947 0.000 502.965 0.054 ;
    END
  END r0_rd_out[29]
  PIN r0_rd_out[30]
    DIRECTION OUTPUT ;
    USE SIGNAL ;
    SHAPE ABUTMENT ;
    PORT
      LAYER M3 ;
      RECT 504.711 0.000 504.729 0.054 ;
    END
  END r0_rd_out[30]
  PIN r0_rd_out[31]
    DIRECTION OUTPUT ;
    USE SIGNAL ;
    SHAPE ABUTMENT ;
    PORT
      LAYER M3 ;
      RECT 506.475 0.000 506.493 0.054 ;
    END
  END r0_rd_out[31]
  PIN r0_rd_out[32]
    DIRECTION OUTPUT ;
    USE SIGNAL ;
    SHAPE ABUTMENT ;
    PORT
      LAYER M3 ;
      RECT 508.239 0.000 508.257 0.054 ;
    END
  END r0_rd_out[32]
  PIN r0_rd_out[33]
    DIRECTION OUTPUT ;
    USE SIGNAL ;
    SHAPE ABUTMENT ;
    PORT
      LAYER M3 ;
      RECT 510.003 0.000 510.021 0.054 ;
    END
  END r0_rd_out[33]
  PIN r0_rd_out[34]
    DIRECTION OUTPUT ;
    USE SIGNAL ;
    SHAPE ABUTMENT ;
    PORT
      LAYER M3 ;
      RECT 511.767 0.000 511.785 0.054 ;
    END
  END r0_rd_out[34]
  PIN r0_rd_out[35]
    DIRECTION OUTPUT ;
    USE SIGNAL ;
    SHAPE ABUTMENT ;
    PORT
      LAYER M3 ;
      RECT 513.531 0.000 513.549 0.054 ;
    END
  END r0_rd_out[35]
  PIN r0_rd_out[36]
    DIRECTION OUTPUT ;
    USE SIGNAL ;
    SHAPE ABUTMENT ;
    PORT
      LAYER M3 ;
      RECT 515.295 0.000 515.313 0.054 ;
    END
  END r0_rd_out[36]
  PIN r0_rd_out[37]
    DIRECTION OUTPUT ;
    USE SIGNAL ;
    SHAPE ABUTMENT ;
    PORT
      LAYER M3 ;
      RECT 517.059 0.000 517.077 0.054 ;
    END
  END r0_rd_out[37]
  PIN r0_rd_out[38]
    DIRECTION OUTPUT ;
    USE SIGNAL ;
    SHAPE ABUTMENT ;
    PORT
      LAYER M3 ;
      RECT 518.823 0.000 518.841 0.054 ;
    END
  END r0_rd_out[38]
  PIN r0_rd_out[39]
    DIRECTION OUTPUT ;
    USE SIGNAL ;
    SHAPE ABUTMENT ;
    PORT
      LAYER M3 ;
      RECT 520.587 0.000 520.605 0.054 ;
    END
  END r0_rd_out[39]
  PIN r0_rd_out[40]
    DIRECTION OUTPUT ;
    USE SIGNAL ;
    SHAPE ABUTMENT ;
    PORT
      LAYER M3 ;
      RECT 522.351 0.000 522.369 0.054 ;
    END
  END r0_rd_out[40]
  PIN r0_rd_out[41]
    DIRECTION OUTPUT ;
    USE SIGNAL ;
    SHAPE ABUTMENT ;
    PORT
      LAYER M3 ;
      RECT 524.115 0.000 524.133 0.054 ;
    END
  END r0_rd_out[41]
  PIN r0_rd_out[42]
    DIRECTION OUTPUT ;
    USE SIGNAL ;
    SHAPE ABUTMENT ;
    PORT
      LAYER M3 ;
      RECT 525.879 0.000 525.897 0.054 ;
    END
  END r0_rd_out[42]
  PIN r0_rd_out[43]
    DIRECTION OUTPUT ;
    USE SIGNAL ;
    SHAPE ABUTMENT ;
    PORT
      LAYER M3 ;
      RECT 527.643 0.000 527.661 0.054 ;
    END
  END r0_rd_out[43]
  PIN r0_rd_out[44]
    DIRECTION OUTPUT ;
    USE SIGNAL ;
    SHAPE ABUTMENT ;
    PORT
      LAYER M3 ;
      RECT 529.407 0.000 529.425 0.054 ;
    END
  END r0_rd_out[44]
  PIN r0_rd_out[45]
    DIRECTION OUTPUT ;
    USE SIGNAL ;
    SHAPE ABUTMENT ;
    PORT
      LAYER M3 ;
      RECT 531.171 0.000 531.189 0.054 ;
    END
  END r0_rd_out[45]
  PIN r0_rd_out[46]
    DIRECTION OUTPUT ;
    USE SIGNAL ;
    SHAPE ABUTMENT ;
    PORT
      LAYER M3 ;
      RECT 532.935 0.000 532.953 0.054 ;
    END
  END r0_rd_out[46]
  PIN r0_rd_out[47]
    DIRECTION OUTPUT ;
    USE SIGNAL ;
    SHAPE ABUTMENT ;
    PORT
      LAYER M3 ;
      RECT 534.699 0.000 534.717 0.054 ;
    END
  END r0_rd_out[47]
  PIN r0_rd_out[48]
    DIRECTION OUTPUT ;
    USE SIGNAL ;
    SHAPE ABUTMENT ;
    PORT
      LAYER M3 ;
      RECT 536.463 0.000 536.481 0.054 ;
    END
  END r0_rd_out[48]
  PIN r0_rd_out[49]
    DIRECTION OUTPUT ;
    USE SIGNAL ;
    SHAPE ABUTMENT ;
    PORT
      LAYER M3 ;
      RECT 538.227 0.000 538.245 0.054 ;
    END
  END r0_rd_out[49]
  PIN r0_rd_out[50]
    DIRECTION OUTPUT ;
    USE SIGNAL ;
    SHAPE ABUTMENT ;
    PORT
      LAYER M3 ;
      RECT 539.991 0.000 540.009 0.054 ;
    END
  END r0_rd_out[50]
  PIN r0_rd_out[51]
    DIRECTION OUTPUT ;
    USE SIGNAL ;
    SHAPE ABUTMENT ;
    PORT
      LAYER M3 ;
      RECT 541.755 0.000 541.773 0.054 ;
    END
  END r0_rd_out[51]
  PIN r0_rd_out[52]
    DIRECTION OUTPUT ;
    USE SIGNAL ;
    SHAPE ABUTMENT ;
    PORT
      LAYER M3 ;
      RECT 543.519 0.000 543.537 0.054 ;
    END
  END r0_rd_out[52]
  PIN r0_rd_out[53]
    DIRECTION OUTPUT ;
    USE SIGNAL ;
    SHAPE ABUTMENT ;
    PORT
      LAYER M3 ;
      RECT 545.283 0.000 545.301 0.054 ;
    END
  END r0_rd_out[53]
  PIN r0_rd_out[54]
    DIRECTION OUTPUT ;
    USE SIGNAL ;
    SHAPE ABUTMENT ;
    PORT
      LAYER M3 ;
      RECT 547.047 0.000 547.065 0.054 ;
    END
  END r0_rd_out[54]
  PIN r0_rd_out[55]
    DIRECTION OUTPUT ;
    USE SIGNAL ;
    SHAPE ABUTMENT ;
    PORT
      LAYER M3 ;
      RECT 548.811 0.000 548.829 0.054 ;
    END
  END r0_rd_out[55]
  PIN r0_rd_out[56]
    DIRECTION OUTPUT ;
    USE SIGNAL ;
    SHAPE ABUTMENT ;
    PORT
      LAYER M3 ;
      RECT 550.575 0.000 550.593 0.054 ;
    END
  END r0_rd_out[56]
  PIN r0_rd_out[57]
    DIRECTION OUTPUT ;
    USE SIGNAL ;
    SHAPE ABUTMENT ;
    PORT
      LAYER M3 ;
      RECT 552.339 0.000 552.357 0.054 ;
    END
  END r0_rd_out[57]
  PIN r0_rd_out[58]
    DIRECTION OUTPUT ;
    USE SIGNAL ;
    SHAPE ABUTMENT ;
    PORT
      LAYER M3 ;
      RECT 554.103 0.000 554.121 0.054 ;
    END
  END r0_rd_out[58]
  PIN r0_rd_out[59]
    DIRECTION OUTPUT ;
    USE SIGNAL ;
    SHAPE ABUTMENT ;
    PORT
      LAYER M3 ;
      RECT 555.867 0.000 555.885 0.054 ;
    END
  END r0_rd_out[59]
  PIN r0_rd_out[60]
    DIRECTION OUTPUT ;
    USE SIGNAL ;
    SHAPE ABUTMENT ;
    PORT
      LAYER M3 ;
      RECT 557.631 0.000 557.649 0.054 ;
    END
  END r0_rd_out[60]
  PIN r0_rd_out[61]
    DIRECTION OUTPUT ;
    USE SIGNAL ;
    SHAPE ABUTMENT ;
    PORT
      LAYER M3 ;
      RECT 559.395 0.000 559.413 0.054 ;
    END
  END r0_rd_out[61]
  PIN r0_rd_out[62]
    DIRECTION OUTPUT ;
    USE SIGNAL ;
    SHAPE ABUTMENT ;
    PORT
      LAYER M3 ;
      RECT 561.159 0.000 561.177 0.054 ;
    END
  END r0_rd_out[62]
  PIN r0_rd_out[63]
    DIRECTION OUTPUT ;
    USE SIGNAL ;
    SHAPE ABUTMENT ;
    PORT
      LAYER M3 ;
      RECT 562.923 0.000 562.941 0.054 ;
    END
  END r0_rd_out[63]
  PIN r0_rd_out[64]
    DIRECTION OUTPUT ;
    USE SIGNAL ;
    SHAPE ABUTMENT ;
    PORT
      LAYER M3 ;
      RECT 564.687 0.000 564.705 0.054 ;
    END
  END r0_rd_out[64]
  PIN r0_rd_out[65]
    DIRECTION OUTPUT ;
    USE SIGNAL ;
    SHAPE ABUTMENT ;
    PORT
      LAYER M3 ;
      RECT 566.451 0.000 566.469 0.054 ;
    END
  END r0_rd_out[65]
  PIN r0_rd_out[66]
    DIRECTION OUTPUT ;
    USE SIGNAL ;
    SHAPE ABUTMENT ;
    PORT
      LAYER M3 ;
      RECT 568.215 0.000 568.233 0.054 ;
    END
  END r0_rd_out[66]
  PIN r0_rd_out[67]
    DIRECTION OUTPUT ;
    USE SIGNAL ;
    SHAPE ABUTMENT ;
    PORT
      LAYER M3 ;
      RECT 569.979 0.000 569.997 0.054 ;
    END
  END r0_rd_out[67]
  PIN r0_rd_out[68]
    DIRECTION OUTPUT ;
    USE SIGNAL ;
    SHAPE ABUTMENT ;
    PORT
      LAYER M3 ;
      RECT 571.743 0.000 571.761 0.054 ;
    END
  END r0_rd_out[68]
  PIN r0_rd_out[69]
    DIRECTION OUTPUT ;
    USE SIGNAL ;
    SHAPE ABUTMENT ;
    PORT
      LAYER M3 ;
      RECT 573.507 0.000 573.525 0.054 ;
    END
  END r0_rd_out[69]
  PIN r0_rd_out[70]
    DIRECTION OUTPUT ;
    USE SIGNAL ;
    SHAPE ABUTMENT ;
    PORT
      LAYER M3 ;
      RECT 575.271 0.000 575.289 0.054 ;
    END
  END r0_rd_out[70]
  PIN r0_rd_out[71]
    DIRECTION OUTPUT ;
    USE SIGNAL ;
    SHAPE ABUTMENT ;
    PORT
      LAYER M3 ;
      RECT 577.035 0.000 577.053 0.054 ;
    END
  END r0_rd_out[71]
  PIN r0_rd_out[72]
    DIRECTION OUTPUT ;
    USE SIGNAL ;
    SHAPE ABUTMENT ;
    PORT
      LAYER M3 ;
      RECT 578.799 0.000 578.817 0.054 ;
    END
  END r0_rd_out[72]
  PIN r0_rd_out[73]
    DIRECTION OUTPUT ;
    USE SIGNAL ;
    SHAPE ABUTMENT ;
    PORT
      LAYER M3 ;
      RECT 580.563 0.000 580.581 0.054 ;
    END
  END r0_rd_out[73]
  PIN r0_rd_out[74]
    DIRECTION OUTPUT ;
    USE SIGNAL ;
    SHAPE ABUTMENT ;
    PORT
      LAYER M3 ;
      RECT 582.327 0.000 582.345 0.054 ;
    END
  END r0_rd_out[74]
  PIN r0_rd_out[75]
    DIRECTION OUTPUT ;
    USE SIGNAL ;
    SHAPE ABUTMENT ;
    PORT
      LAYER M3 ;
      RECT 584.091 0.000 584.109 0.054 ;
    END
  END r0_rd_out[75]
  PIN r0_rd_out[76]
    DIRECTION OUTPUT ;
    USE SIGNAL ;
    SHAPE ABUTMENT ;
    PORT
      LAYER M3 ;
      RECT 585.855 0.000 585.873 0.054 ;
    END
  END r0_rd_out[76]
  PIN r0_rd_out[77]
    DIRECTION OUTPUT ;
    USE SIGNAL ;
    SHAPE ABUTMENT ;
    PORT
      LAYER M3 ;
      RECT 587.619 0.000 587.637 0.054 ;
    END
  END r0_rd_out[77]
  PIN r0_rd_out[78]
    DIRECTION OUTPUT ;
    USE SIGNAL ;
    SHAPE ABUTMENT ;
    PORT
      LAYER M3 ;
      RECT 589.383 0.000 589.401 0.054 ;
    END
  END r0_rd_out[78]
  PIN r0_rd_out[79]
    DIRECTION OUTPUT ;
    USE SIGNAL ;
    SHAPE ABUTMENT ;
    PORT
      LAYER M3 ;
      RECT 591.147 0.000 591.165 0.054 ;
    END
  END r0_rd_out[79]
  PIN r0_rd_out[80]
    DIRECTION OUTPUT ;
    USE SIGNAL ;
    SHAPE ABUTMENT ;
    PORT
      LAYER M3 ;
      RECT 592.911 0.000 592.929 0.054 ;
    END
  END r0_rd_out[80]
  PIN r0_rd_out[81]
    DIRECTION OUTPUT ;
    USE SIGNAL ;
    SHAPE ABUTMENT ;
    PORT
      LAYER M3 ;
      RECT 594.675 0.000 594.693 0.054 ;
    END
  END r0_rd_out[81]
  PIN r0_rd_out[82]
    DIRECTION OUTPUT ;
    USE SIGNAL ;
    SHAPE ABUTMENT ;
    PORT
      LAYER M3 ;
      RECT 596.439 0.000 596.457 0.054 ;
    END
  END r0_rd_out[82]
  PIN r0_rd_out[83]
    DIRECTION OUTPUT ;
    USE SIGNAL ;
    SHAPE ABUTMENT ;
    PORT
      LAYER M3 ;
      RECT 598.203 0.000 598.221 0.054 ;
    END
  END r0_rd_out[83]
  PIN r0_rd_out[84]
    DIRECTION OUTPUT ;
    USE SIGNAL ;
    SHAPE ABUTMENT ;
    PORT
      LAYER M3 ;
      RECT 599.967 0.000 599.985 0.054 ;
    END
  END r0_rd_out[84]
  PIN r0_rd_out[85]
    DIRECTION OUTPUT ;
    USE SIGNAL ;
    SHAPE ABUTMENT ;
    PORT
      LAYER M3 ;
      RECT 601.731 0.000 601.749 0.054 ;
    END
  END r0_rd_out[85]
  PIN r0_rd_out[86]
    DIRECTION OUTPUT ;
    USE SIGNAL ;
    SHAPE ABUTMENT ;
    PORT
      LAYER M3 ;
      RECT 603.495 0.000 603.513 0.054 ;
    END
  END r0_rd_out[86]
  PIN r0_rd_out[87]
    DIRECTION OUTPUT ;
    USE SIGNAL ;
    SHAPE ABUTMENT ;
    PORT
      LAYER M3 ;
      RECT 605.259 0.000 605.277 0.054 ;
    END
  END r0_rd_out[87]
  PIN r0_rd_out[88]
    DIRECTION OUTPUT ;
    USE SIGNAL ;
    SHAPE ABUTMENT ;
    PORT
      LAYER M3 ;
      RECT 607.023 0.000 607.041 0.054 ;
    END
  END r0_rd_out[88]
  PIN r0_rd_out[89]
    DIRECTION OUTPUT ;
    USE SIGNAL ;
    SHAPE ABUTMENT ;
    PORT
      LAYER M3 ;
      RECT 608.787 0.000 608.805 0.054 ;
    END
  END r0_rd_out[89]
  PIN r0_rd_out[90]
    DIRECTION OUTPUT ;
    USE SIGNAL ;
    SHAPE ABUTMENT ;
    PORT
      LAYER M3 ;
      RECT 610.551 0.000 610.569 0.054 ;
    END
  END r0_rd_out[90]
  PIN r0_rd_out[91]
    DIRECTION OUTPUT ;
    USE SIGNAL ;
    SHAPE ABUTMENT ;
    PORT
      LAYER M3 ;
      RECT 612.315 0.000 612.333 0.054 ;
    END
  END r0_rd_out[91]
  PIN r0_rd_out[92]
    DIRECTION OUTPUT ;
    USE SIGNAL ;
    SHAPE ABUTMENT ;
    PORT
      LAYER M3 ;
      RECT 614.079 0.000 614.097 0.054 ;
    END
  END r0_rd_out[92]
  PIN r0_rd_out[93]
    DIRECTION OUTPUT ;
    USE SIGNAL ;
    SHAPE ABUTMENT ;
    PORT
      LAYER M3 ;
      RECT 615.843 0.000 615.861 0.054 ;
    END
  END r0_rd_out[93]
  PIN r0_rd_out[94]
    DIRECTION OUTPUT ;
    USE SIGNAL ;
    SHAPE ABUTMENT ;
    PORT
      LAYER M3 ;
      RECT 617.607 0.000 617.625 0.054 ;
    END
  END r0_rd_out[94]
  PIN r0_rd_out[95]
    DIRECTION OUTPUT ;
    USE SIGNAL ;
    SHAPE ABUTMENT ;
    PORT
      LAYER M3 ;
      RECT 619.371 0.000 619.389 0.054 ;
    END
  END r0_rd_out[95]
  PIN r0_rd_out[96]
    DIRECTION OUTPUT ;
    USE SIGNAL ;
    SHAPE ABUTMENT ;
    PORT
      LAYER M3 ;
      RECT 621.135 0.000 621.153 0.054 ;
    END
  END r0_rd_out[96]
  PIN r0_rd_out[97]
    DIRECTION OUTPUT ;
    USE SIGNAL ;
    SHAPE ABUTMENT ;
    PORT
      LAYER M3 ;
      RECT 622.899 0.000 622.917 0.054 ;
    END
  END r0_rd_out[97]
  PIN r0_rd_out[98]
    DIRECTION OUTPUT ;
    USE SIGNAL ;
    SHAPE ABUTMENT ;
    PORT
      LAYER M3 ;
      RECT 624.663 0.000 624.681 0.054 ;
    END
  END r0_rd_out[98]
  PIN r0_rd_out[99]
    DIRECTION OUTPUT ;
    USE SIGNAL ;
    SHAPE ABUTMENT ;
    PORT
      LAYER M3 ;
      RECT 626.427 0.000 626.445 0.054 ;
    END
  END r0_rd_out[99]
  PIN r0_rd_out[100]
    DIRECTION OUTPUT ;
    USE SIGNAL ;
    SHAPE ABUTMENT ;
    PORT
      LAYER M3 ;
      RECT 628.191 0.000 628.209 0.054 ;
    END
  END r0_rd_out[100]
  PIN r0_rd_out[101]
    DIRECTION OUTPUT ;
    USE SIGNAL ;
    SHAPE ABUTMENT ;
    PORT
      LAYER M3 ;
      RECT 629.955 0.000 629.973 0.054 ;
    END
  END r0_rd_out[101]
  PIN r0_rd_out[102]
    DIRECTION OUTPUT ;
    USE SIGNAL ;
    SHAPE ABUTMENT ;
    PORT
      LAYER M3 ;
      RECT 631.719 0.000 631.737 0.054 ;
    END
  END r0_rd_out[102]
  PIN r0_rd_out[103]
    DIRECTION OUTPUT ;
    USE SIGNAL ;
    SHAPE ABUTMENT ;
    PORT
      LAYER M3 ;
      RECT 633.483 0.000 633.501 0.054 ;
    END
  END r0_rd_out[103]
  PIN r0_rd_out[104]
    DIRECTION OUTPUT ;
    USE SIGNAL ;
    SHAPE ABUTMENT ;
    PORT
      LAYER M3 ;
      RECT 635.247 0.000 635.265 0.054 ;
    END
  END r0_rd_out[104]
  PIN r0_rd_out[105]
    DIRECTION OUTPUT ;
    USE SIGNAL ;
    SHAPE ABUTMENT ;
    PORT
      LAYER M3 ;
      RECT 637.011 0.000 637.029 0.054 ;
    END
  END r0_rd_out[105]
  PIN r0_rd_out[106]
    DIRECTION OUTPUT ;
    USE SIGNAL ;
    SHAPE ABUTMENT ;
    PORT
      LAYER M3 ;
      RECT 638.775 0.000 638.793 0.054 ;
    END
  END r0_rd_out[106]
  PIN r0_rd_out[107]
    DIRECTION OUTPUT ;
    USE SIGNAL ;
    SHAPE ABUTMENT ;
    PORT
      LAYER M3 ;
      RECT 640.539 0.000 640.557 0.054 ;
    END
  END r0_rd_out[107]
  PIN r0_rd_out[108]
    DIRECTION OUTPUT ;
    USE SIGNAL ;
    SHAPE ABUTMENT ;
    PORT
      LAYER M3 ;
      RECT 642.303 0.000 642.321 0.054 ;
    END
  END r0_rd_out[108]
  PIN r0_rd_out[109]
    DIRECTION OUTPUT ;
    USE SIGNAL ;
    SHAPE ABUTMENT ;
    PORT
      LAYER M3 ;
      RECT 644.067 0.000 644.085 0.054 ;
    END
  END r0_rd_out[109]
  PIN r0_rd_out[110]
    DIRECTION OUTPUT ;
    USE SIGNAL ;
    SHAPE ABUTMENT ;
    PORT
      LAYER M3 ;
      RECT 645.831 0.000 645.849 0.054 ;
    END
  END r0_rd_out[110]
  PIN r0_rd_out[111]
    DIRECTION OUTPUT ;
    USE SIGNAL ;
    SHAPE ABUTMENT ;
    PORT
      LAYER M3 ;
      RECT 647.595 0.000 647.613 0.054 ;
    END
  END r0_rd_out[111]
  PIN r0_rd_out[112]
    DIRECTION OUTPUT ;
    USE SIGNAL ;
    SHAPE ABUTMENT ;
    PORT
      LAYER M3 ;
      RECT 649.359 0.000 649.377 0.054 ;
    END
  END r0_rd_out[112]
  PIN r0_rd_out[113]
    DIRECTION OUTPUT ;
    USE SIGNAL ;
    SHAPE ABUTMENT ;
    PORT
      LAYER M3 ;
      RECT 651.123 0.000 651.141 0.054 ;
    END
  END r0_rd_out[113]
  PIN r0_rd_out[114]
    DIRECTION OUTPUT ;
    USE SIGNAL ;
    SHAPE ABUTMENT ;
    PORT
      LAYER M3 ;
      RECT 652.887 0.000 652.905 0.054 ;
    END
  END r0_rd_out[114]
  PIN r0_rd_out[115]
    DIRECTION OUTPUT ;
    USE SIGNAL ;
    SHAPE ABUTMENT ;
    PORT
      LAYER M3 ;
      RECT 654.651 0.000 654.669 0.054 ;
    END
  END r0_rd_out[115]
  PIN r0_rd_out[116]
    DIRECTION OUTPUT ;
    USE SIGNAL ;
    SHAPE ABUTMENT ;
    PORT
      LAYER M3 ;
      RECT 656.415 0.000 656.433 0.054 ;
    END
  END r0_rd_out[116]
  PIN r0_rd_out[117]
    DIRECTION OUTPUT ;
    USE SIGNAL ;
    SHAPE ABUTMENT ;
    PORT
      LAYER M3 ;
      RECT 658.179 0.000 658.197 0.054 ;
    END
  END r0_rd_out[117]
  PIN r0_rd_out[118]
    DIRECTION OUTPUT ;
    USE SIGNAL ;
    SHAPE ABUTMENT ;
    PORT
      LAYER M3 ;
      RECT 659.943 0.000 659.961 0.054 ;
    END
  END r0_rd_out[118]
  PIN r0_rd_out[119]
    DIRECTION OUTPUT ;
    USE SIGNAL ;
    SHAPE ABUTMENT ;
    PORT
      LAYER M3 ;
      RECT 661.707 0.000 661.725 0.054 ;
    END
  END r0_rd_out[119]
  PIN r0_rd_out[120]
    DIRECTION OUTPUT ;
    USE SIGNAL ;
    SHAPE ABUTMENT ;
    PORT
      LAYER M3 ;
      RECT 663.471 0.000 663.489 0.054 ;
    END
  END r0_rd_out[120]
  PIN r0_rd_out[121]
    DIRECTION OUTPUT ;
    USE SIGNAL ;
    SHAPE ABUTMENT ;
    PORT
      LAYER M3 ;
      RECT 665.235 0.000 665.253 0.054 ;
    END
  END r0_rd_out[121]
  PIN r0_rd_out[122]
    DIRECTION OUTPUT ;
    USE SIGNAL ;
    SHAPE ABUTMENT ;
    PORT
      LAYER M3 ;
      RECT 666.999 0.000 667.017 0.054 ;
    END
  END r0_rd_out[122]
  PIN r0_rd_out[123]
    DIRECTION OUTPUT ;
    USE SIGNAL ;
    SHAPE ABUTMENT ;
    PORT
      LAYER M3 ;
      RECT 668.763 0.000 668.781 0.054 ;
    END
  END r0_rd_out[123]
  PIN r0_rd_out[124]
    DIRECTION OUTPUT ;
    USE SIGNAL ;
    SHAPE ABUTMENT ;
    PORT
      LAYER M3 ;
      RECT 670.527 0.000 670.545 0.054 ;
    END
  END r0_rd_out[124]
  PIN r0_rd_out[125]
    DIRECTION OUTPUT ;
    USE SIGNAL ;
    SHAPE ABUTMENT ;
    PORT
      LAYER M3 ;
      RECT 672.291 0.000 672.309 0.054 ;
    END
  END r0_rd_out[125]
  PIN r0_rd_out[126]
    DIRECTION OUTPUT ;
    USE SIGNAL ;
    SHAPE ABUTMENT ;
    PORT
      LAYER M3 ;
      RECT 674.055 0.000 674.073 0.054 ;
    END
  END r0_rd_out[126]
  PIN r0_rd_out[127]
    DIRECTION OUTPUT ;
    USE SIGNAL ;
    SHAPE ABUTMENT ;
    PORT
      LAYER M3 ;
      RECT 675.819 0.000 675.837 0.054 ;
    END
  END r0_rd_out[127]
  PIN r0_rd_out[128]
    DIRECTION OUTPUT ;
    USE SIGNAL ;
    SHAPE ABUTMENT ;
    PORT
      LAYER M3 ;
      RECT 677.583 0.000 677.601 0.054 ;
    END
  END r0_rd_out[128]
  PIN r0_rd_out[129]
    DIRECTION OUTPUT ;
    USE SIGNAL ;
    SHAPE ABUTMENT ;
    PORT
      LAYER M3 ;
      RECT 679.347 0.000 679.365 0.054 ;
    END
  END r0_rd_out[129]
  PIN r0_rd_out[130]
    DIRECTION OUTPUT ;
    USE SIGNAL ;
    SHAPE ABUTMENT ;
    PORT
      LAYER M3 ;
      RECT 681.111 0.000 681.129 0.054 ;
    END
  END r0_rd_out[130]
  PIN r0_rd_out[131]
    DIRECTION OUTPUT ;
    USE SIGNAL ;
    SHAPE ABUTMENT ;
    PORT
      LAYER M3 ;
      RECT 682.875 0.000 682.893 0.054 ;
    END
  END r0_rd_out[131]
  PIN r0_rd_out[132]
    DIRECTION OUTPUT ;
    USE SIGNAL ;
    SHAPE ABUTMENT ;
    PORT
      LAYER M3 ;
      RECT 684.639 0.000 684.657 0.054 ;
    END
  END r0_rd_out[132]
  PIN r0_rd_out[133]
    DIRECTION OUTPUT ;
    USE SIGNAL ;
    SHAPE ABUTMENT ;
    PORT
      LAYER M3 ;
      RECT 686.403 0.000 686.421 0.054 ;
    END
  END r0_rd_out[133]
  PIN r0_rd_out[134]
    DIRECTION OUTPUT ;
    USE SIGNAL ;
    SHAPE ABUTMENT ;
    PORT
      LAYER M3 ;
      RECT 688.167 0.000 688.185 0.054 ;
    END
  END r0_rd_out[134]
  PIN r0_rd_out[135]
    DIRECTION OUTPUT ;
    USE SIGNAL ;
    SHAPE ABUTMENT ;
    PORT
      LAYER M3 ;
      RECT 689.931 0.000 689.949 0.054 ;
    END
  END r0_rd_out[135]
  PIN r0_rd_out[136]
    DIRECTION OUTPUT ;
    USE SIGNAL ;
    SHAPE ABUTMENT ;
    PORT
      LAYER M3 ;
      RECT 691.695 0.000 691.713 0.054 ;
    END
  END r0_rd_out[136]
  PIN r0_rd_out[137]
    DIRECTION OUTPUT ;
    USE SIGNAL ;
    SHAPE ABUTMENT ;
    PORT
      LAYER M3 ;
      RECT 693.459 0.000 693.477 0.054 ;
    END
  END r0_rd_out[137]
  PIN r0_rd_out[138]
    DIRECTION OUTPUT ;
    USE SIGNAL ;
    SHAPE ABUTMENT ;
    PORT
      LAYER M3 ;
      RECT 695.223 0.000 695.241 0.054 ;
    END
  END r0_rd_out[138]
  PIN r0_rd_out[139]
    DIRECTION OUTPUT ;
    USE SIGNAL ;
    SHAPE ABUTMENT ;
    PORT
      LAYER M3 ;
      RECT 696.987 0.000 697.005 0.054 ;
    END
  END r0_rd_out[139]
  PIN r0_rd_out[140]
    DIRECTION OUTPUT ;
    USE SIGNAL ;
    SHAPE ABUTMENT ;
    PORT
      LAYER M3 ;
      RECT 698.751 0.000 698.769 0.054 ;
    END
  END r0_rd_out[140]
  PIN r0_rd_out[141]
    DIRECTION OUTPUT ;
    USE SIGNAL ;
    SHAPE ABUTMENT ;
    PORT
      LAYER M3 ;
      RECT 700.515 0.000 700.533 0.054 ;
    END
  END r0_rd_out[141]
  PIN r0_rd_out[142]
    DIRECTION OUTPUT ;
    USE SIGNAL ;
    SHAPE ABUTMENT ;
    PORT
      LAYER M3 ;
      RECT 702.279 0.000 702.297 0.054 ;
    END
  END r0_rd_out[142]
  PIN r0_rd_out[143]
    DIRECTION OUTPUT ;
    USE SIGNAL ;
    SHAPE ABUTMENT ;
    PORT
      LAYER M3 ;
      RECT 704.043 0.000 704.061 0.054 ;
    END
  END r0_rd_out[143]
  PIN r0_rd_out[144]
    DIRECTION OUTPUT ;
    USE SIGNAL ;
    SHAPE ABUTMENT ;
    PORT
      LAYER M3 ;
      RECT 705.807 0.000 705.825 0.054 ;
    END
  END r0_rd_out[144]
  PIN r0_rd_out[145]
    DIRECTION OUTPUT ;
    USE SIGNAL ;
    SHAPE ABUTMENT ;
    PORT
      LAYER M3 ;
      RECT 707.571 0.000 707.589 0.054 ;
    END
  END r0_rd_out[145]
  PIN r0_rd_out[146]
    DIRECTION OUTPUT ;
    USE SIGNAL ;
    SHAPE ABUTMENT ;
    PORT
      LAYER M3 ;
      RECT 709.335 0.000 709.353 0.054 ;
    END
  END r0_rd_out[146]
  PIN r0_rd_out[147]
    DIRECTION OUTPUT ;
    USE SIGNAL ;
    SHAPE ABUTMENT ;
    PORT
      LAYER M3 ;
      RECT 711.099 0.000 711.117 0.054 ;
    END
  END r0_rd_out[147]
  PIN r0_rd_out[148]
    DIRECTION OUTPUT ;
    USE SIGNAL ;
    SHAPE ABUTMENT ;
    PORT
      LAYER M3 ;
      RECT 712.863 0.000 712.881 0.054 ;
    END
  END r0_rd_out[148]
  PIN r0_rd_out[149]
    DIRECTION OUTPUT ;
    USE SIGNAL ;
    SHAPE ABUTMENT ;
    PORT
      LAYER M3 ;
      RECT 714.627 0.000 714.645 0.054 ;
    END
  END r0_rd_out[149]
  PIN r0_rd_out[150]
    DIRECTION OUTPUT ;
    USE SIGNAL ;
    SHAPE ABUTMENT ;
    PORT
      LAYER M3 ;
      RECT 716.391 0.000 716.409 0.054 ;
    END
  END r0_rd_out[150]
  PIN r0_rd_out[151]
    DIRECTION OUTPUT ;
    USE SIGNAL ;
    SHAPE ABUTMENT ;
    PORT
      LAYER M3 ;
      RECT 718.155 0.000 718.173 0.054 ;
    END
  END r0_rd_out[151]
  PIN r0_rd_out[152]
    DIRECTION OUTPUT ;
    USE SIGNAL ;
    SHAPE ABUTMENT ;
    PORT
      LAYER M3 ;
      RECT 719.919 0.000 719.937 0.054 ;
    END
  END r0_rd_out[152]
  PIN r0_rd_out[153]
    DIRECTION OUTPUT ;
    USE SIGNAL ;
    SHAPE ABUTMENT ;
    PORT
      LAYER M3 ;
      RECT 721.683 0.000 721.701 0.054 ;
    END
  END r0_rd_out[153]
  PIN r0_rd_out[154]
    DIRECTION OUTPUT ;
    USE SIGNAL ;
    SHAPE ABUTMENT ;
    PORT
      LAYER M3 ;
      RECT 723.447 0.000 723.465 0.054 ;
    END
  END r0_rd_out[154]
  PIN r0_rd_out[155]
    DIRECTION OUTPUT ;
    USE SIGNAL ;
    SHAPE ABUTMENT ;
    PORT
      LAYER M3 ;
      RECT 725.211 0.000 725.229 0.054 ;
    END
  END r0_rd_out[155]
  PIN r0_rd_out[156]
    DIRECTION OUTPUT ;
    USE SIGNAL ;
    SHAPE ABUTMENT ;
    PORT
      LAYER M3 ;
      RECT 726.975 0.000 726.993 0.054 ;
    END
  END r0_rd_out[156]
  PIN r0_rd_out[157]
    DIRECTION OUTPUT ;
    USE SIGNAL ;
    SHAPE ABUTMENT ;
    PORT
      LAYER M3 ;
      RECT 728.739 0.000 728.757 0.054 ;
    END
  END r0_rd_out[157]
  PIN r0_rd_out[158]
    DIRECTION OUTPUT ;
    USE SIGNAL ;
    SHAPE ABUTMENT ;
    PORT
      LAYER M3 ;
      RECT 730.503 0.000 730.521 0.054 ;
    END
  END r0_rd_out[158]
  PIN r0_rd_out[159]
    DIRECTION OUTPUT ;
    USE SIGNAL ;
    SHAPE ABUTMENT ;
    PORT
      LAYER M3 ;
      RECT 732.267 0.000 732.285 0.054 ;
    END
  END r0_rd_out[159]
  PIN r0_rd_out[160]
    DIRECTION OUTPUT ;
    USE SIGNAL ;
    SHAPE ABUTMENT ;
    PORT
      LAYER M3 ;
      RECT 734.031 0.000 734.049 0.054 ;
    END
  END r0_rd_out[160]
  PIN r0_rd_out[161]
    DIRECTION OUTPUT ;
    USE SIGNAL ;
    SHAPE ABUTMENT ;
    PORT
      LAYER M3 ;
      RECT 735.795 0.000 735.813 0.054 ;
    END
  END r0_rd_out[161]
  PIN r0_rd_out[162]
    DIRECTION OUTPUT ;
    USE SIGNAL ;
    SHAPE ABUTMENT ;
    PORT
      LAYER M3 ;
      RECT 737.559 0.000 737.577 0.054 ;
    END
  END r0_rd_out[162]
  PIN r0_rd_out[163]
    DIRECTION OUTPUT ;
    USE SIGNAL ;
    SHAPE ABUTMENT ;
    PORT
      LAYER M3 ;
      RECT 739.323 0.000 739.341 0.054 ;
    END
  END r0_rd_out[163]
  PIN r0_rd_out[164]
    DIRECTION OUTPUT ;
    USE SIGNAL ;
    SHAPE ABUTMENT ;
    PORT
      LAYER M3 ;
      RECT 741.087 0.000 741.105 0.054 ;
    END
  END r0_rd_out[164]
  PIN r0_rd_out[165]
    DIRECTION OUTPUT ;
    USE SIGNAL ;
    SHAPE ABUTMENT ;
    PORT
      LAYER M3 ;
      RECT 742.851 0.000 742.869 0.054 ;
    END
  END r0_rd_out[165]
  PIN r0_rd_out[166]
    DIRECTION OUTPUT ;
    USE SIGNAL ;
    SHAPE ABUTMENT ;
    PORT
      LAYER M3 ;
      RECT 744.615 0.000 744.633 0.054 ;
    END
  END r0_rd_out[166]
  PIN r0_rd_out[167]
    DIRECTION OUTPUT ;
    USE SIGNAL ;
    SHAPE ABUTMENT ;
    PORT
      LAYER M3 ;
      RECT 746.379 0.000 746.397 0.054 ;
    END
  END r0_rd_out[167]
  PIN r0_rd_out[168]
    DIRECTION OUTPUT ;
    USE SIGNAL ;
    SHAPE ABUTMENT ;
    PORT
      LAYER M3 ;
      RECT 748.143 0.000 748.161 0.054 ;
    END
  END r0_rd_out[168]
  PIN r0_rd_out[169]
    DIRECTION OUTPUT ;
    USE SIGNAL ;
    SHAPE ABUTMENT ;
    PORT
      LAYER M3 ;
      RECT 749.907 0.000 749.925 0.054 ;
    END
  END r0_rd_out[169]
  PIN r0_rd_out[170]
    DIRECTION OUTPUT ;
    USE SIGNAL ;
    SHAPE ABUTMENT ;
    PORT
      LAYER M3 ;
      RECT 751.671 0.000 751.689 0.054 ;
    END
  END r0_rd_out[170]
  PIN r0_rd_out[171]
    DIRECTION OUTPUT ;
    USE SIGNAL ;
    SHAPE ABUTMENT ;
    PORT
      LAYER M3 ;
      RECT 753.435 0.000 753.453 0.054 ;
    END
  END r0_rd_out[171]
  PIN r0_rd_out[172]
    DIRECTION OUTPUT ;
    USE SIGNAL ;
    SHAPE ABUTMENT ;
    PORT
      LAYER M3 ;
      RECT 755.199 0.000 755.217 0.054 ;
    END
  END r0_rd_out[172]
  PIN r0_rd_out[173]
    DIRECTION OUTPUT ;
    USE SIGNAL ;
    SHAPE ABUTMENT ;
    PORT
      LAYER M3 ;
      RECT 756.963 0.000 756.981 0.054 ;
    END
  END r0_rd_out[173]
  PIN r0_rd_out[174]
    DIRECTION OUTPUT ;
    USE SIGNAL ;
    SHAPE ABUTMENT ;
    PORT
      LAYER M3 ;
      RECT 758.727 0.000 758.745 0.054 ;
    END
  END r0_rd_out[174]
  PIN r0_rd_out[175]
    DIRECTION OUTPUT ;
    USE SIGNAL ;
    SHAPE ABUTMENT ;
    PORT
      LAYER M3 ;
      RECT 760.491 0.000 760.509 0.054 ;
    END
  END r0_rd_out[175]
  PIN r0_rd_out[176]
    DIRECTION OUTPUT ;
    USE SIGNAL ;
    SHAPE ABUTMENT ;
    PORT
      LAYER M3 ;
      RECT 762.255 0.000 762.273 0.054 ;
    END
  END r0_rd_out[176]
  PIN r0_rd_out[177]
    DIRECTION OUTPUT ;
    USE SIGNAL ;
    SHAPE ABUTMENT ;
    PORT
      LAYER M3 ;
      RECT 764.019 0.000 764.037 0.054 ;
    END
  END r0_rd_out[177]
  PIN r0_rd_out[178]
    DIRECTION OUTPUT ;
    USE SIGNAL ;
    SHAPE ABUTMENT ;
    PORT
      LAYER M3 ;
      RECT 765.783 0.000 765.801 0.054 ;
    END
  END r0_rd_out[178]
  PIN r0_rd_out[179]
    DIRECTION OUTPUT ;
    USE SIGNAL ;
    SHAPE ABUTMENT ;
    PORT
      LAYER M3 ;
      RECT 767.547 0.000 767.565 0.054 ;
    END
  END r0_rd_out[179]
  PIN r0_rd_out[180]
    DIRECTION OUTPUT ;
    USE SIGNAL ;
    SHAPE ABUTMENT ;
    PORT
      LAYER M3 ;
      RECT 769.311 0.000 769.329 0.054 ;
    END
  END r0_rd_out[180]
  PIN r0_rd_out[181]
    DIRECTION OUTPUT ;
    USE SIGNAL ;
    SHAPE ABUTMENT ;
    PORT
      LAYER M3 ;
      RECT 771.075 0.000 771.093 0.054 ;
    END
  END r0_rd_out[181]
  PIN r0_rd_out[182]
    DIRECTION OUTPUT ;
    USE SIGNAL ;
    SHAPE ABUTMENT ;
    PORT
      LAYER M3 ;
      RECT 772.839 0.000 772.857 0.054 ;
    END
  END r0_rd_out[182]
  PIN r0_rd_out[183]
    DIRECTION OUTPUT ;
    USE SIGNAL ;
    SHAPE ABUTMENT ;
    PORT
      LAYER M3 ;
      RECT 774.603 0.000 774.621 0.054 ;
    END
  END r0_rd_out[183]
  PIN r0_rd_out[184]
    DIRECTION OUTPUT ;
    USE SIGNAL ;
    SHAPE ABUTMENT ;
    PORT
      LAYER M3 ;
      RECT 776.367 0.000 776.385 0.054 ;
    END
  END r0_rd_out[184]
  PIN r0_rd_out[185]
    DIRECTION OUTPUT ;
    USE SIGNAL ;
    SHAPE ABUTMENT ;
    PORT
      LAYER M3 ;
      RECT 778.131 0.000 778.149 0.054 ;
    END
  END r0_rd_out[185]
  PIN r0_rd_out[186]
    DIRECTION OUTPUT ;
    USE SIGNAL ;
    SHAPE ABUTMENT ;
    PORT
      LAYER M3 ;
      RECT 779.895 0.000 779.913 0.054 ;
    END
  END r0_rd_out[186]
  PIN r0_rd_out[187]
    DIRECTION OUTPUT ;
    USE SIGNAL ;
    SHAPE ABUTMENT ;
    PORT
      LAYER M3 ;
      RECT 781.659 0.000 781.677 0.054 ;
    END
  END r0_rd_out[187]
  PIN r0_rd_out[188]
    DIRECTION OUTPUT ;
    USE SIGNAL ;
    SHAPE ABUTMENT ;
    PORT
      LAYER M3 ;
      RECT 783.423 0.000 783.441 0.054 ;
    END
  END r0_rd_out[188]
  PIN r0_rd_out[189]
    DIRECTION OUTPUT ;
    USE SIGNAL ;
    SHAPE ABUTMENT ;
    PORT
      LAYER M3 ;
      RECT 785.187 0.000 785.205 0.054 ;
    END
  END r0_rd_out[189]
  PIN r0_rd_out[190]
    DIRECTION OUTPUT ;
    USE SIGNAL ;
    SHAPE ABUTMENT ;
    PORT
      LAYER M3 ;
      RECT 786.951 0.000 786.969 0.054 ;
    END
  END r0_rd_out[190]
  PIN r0_rd_out[191]
    DIRECTION OUTPUT ;
    USE SIGNAL ;
    SHAPE ABUTMENT ;
    PORT
      LAYER M3 ;
      RECT 788.715 0.000 788.733 0.054 ;
    END
  END r0_rd_out[191]
  PIN r0_rd_out[192]
    DIRECTION OUTPUT ;
    USE SIGNAL ;
    SHAPE ABUTMENT ;
    PORT
      LAYER M3 ;
      RECT 790.479 0.000 790.497 0.054 ;
    END
  END r0_rd_out[192]
  PIN r0_rd_out[193]
    DIRECTION OUTPUT ;
    USE SIGNAL ;
    SHAPE ABUTMENT ;
    PORT
      LAYER M3 ;
      RECT 792.243 0.000 792.261 0.054 ;
    END
  END r0_rd_out[193]
  PIN r0_rd_out[194]
    DIRECTION OUTPUT ;
    USE SIGNAL ;
    SHAPE ABUTMENT ;
    PORT
      LAYER M3 ;
      RECT 794.007 0.000 794.025 0.054 ;
    END
  END r0_rd_out[194]
  PIN r0_rd_out[195]
    DIRECTION OUTPUT ;
    USE SIGNAL ;
    SHAPE ABUTMENT ;
    PORT
      LAYER M3 ;
      RECT 795.771 0.000 795.789 0.054 ;
    END
  END r0_rd_out[195]
  PIN r0_rd_out[196]
    DIRECTION OUTPUT ;
    USE SIGNAL ;
    SHAPE ABUTMENT ;
    PORT
      LAYER M3 ;
      RECT 797.535 0.000 797.553 0.054 ;
    END
  END r0_rd_out[196]
  PIN r0_rd_out[197]
    DIRECTION OUTPUT ;
    USE SIGNAL ;
    SHAPE ABUTMENT ;
    PORT
      LAYER M3 ;
      RECT 799.299 0.000 799.317 0.054 ;
    END
  END r0_rd_out[197]
  PIN r0_rd_out[198]
    DIRECTION OUTPUT ;
    USE SIGNAL ;
    SHAPE ABUTMENT ;
    PORT
      LAYER M3 ;
      RECT 801.063 0.000 801.081 0.054 ;
    END
  END r0_rd_out[198]
  PIN r0_rd_out[199]
    DIRECTION OUTPUT ;
    USE SIGNAL ;
    SHAPE ABUTMENT ;
    PORT
      LAYER M3 ;
      RECT 802.827 0.000 802.845 0.054 ;
    END
  END r0_rd_out[199]
  PIN r0_rd_out[200]
    DIRECTION OUTPUT ;
    USE SIGNAL ;
    SHAPE ABUTMENT ;
    PORT
      LAYER M3 ;
      RECT 804.591 0.000 804.609 0.054 ;
    END
  END r0_rd_out[200]
  PIN r0_rd_out[201]
    DIRECTION OUTPUT ;
    USE SIGNAL ;
    SHAPE ABUTMENT ;
    PORT
      LAYER M3 ;
      RECT 806.355 0.000 806.373 0.054 ;
    END
  END r0_rd_out[201]
  PIN r0_rd_out[202]
    DIRECTION OUTPUT ;
    USE SIGNAL ;
    SHAPE ABUTMENT ;
    PORT
      LAYER M3 ;
      RECT 808.119 0.000 808.137 0.054 ;
    END
  END r0_rd_out[202]
  PIN r0_rd_out[203]
    DIRECTION OUTPUT ;
    USE SIGNAL ;
    SHAPE ABUTMENT ;
    PORT
      LAYER M3 ;
      RECT 809.883 0.000 809.901 0.054 ;
    END
  END r0_rd_out[203]
  PIN r0_rd_out[204]
    DIRECTION OUTPUT ;
    USE SIGNAL ;
    SHAPE ABUTMENT ;
    PORT
      LAYER M3 ;
      RECT 811.647 0.000 811.665 0.054 ;
    END
  END r0_rd_out[204]
  PIN r0_rd_out[205]
    DIRECTION OUTPUT ;
    USE SIGNAL ;
    SHAPE ABUTMENT ;
    PORT
      LAYER M3 ;
      RECT 813.411 0.000 813.429 0.054 ;
    END
  END r0_rd_out[205]
  PIN r0_rd_out[206]
    DIRECTION OUTPUT ;
    USE SIGNAL ;
    SHAPE ABUTMENT ;
    PORT
      LAYER M3 ;
      RECT 815.175 0.000 815.193 0.054 ;
    END
  END r0_rd_out[206]
  PIN r0_rd_out[207]
    DIRECTION OUTPUT ;
    USE SIGNAL ;
    SHAPE ABUTMENT ;
    PORT
      LAYER M3 ;
      RECT 816.939 0.000 816.957 0.054 ;
    END
  END r0_rd_out[207]
  PIN r0_rd_out[208]
    DIRECTION OUTPUT ;
    USE SIGNAL ;
    SHAPE ABUTMENT ;
    PORT
      LAYER M3 ;
      RECT 818.703 0.000 818.721 0.054 ;
    END
  END r0_rd_out[208]
  PIN r0_rd_out[209]
    DIRECTION OUTPUT ;
    USE SIGNAL ;
    SHAPE ABUTMENT ;
    PORT
      LAYER M3 ;
      RECT 820.467 0.000 820.485 0.054 ;
    END
  END r0_rd_out[209]
  PIN r0_rd_out[210]
    DIRECTION OUTPUT ;
    USE SIGNAL ;
    SHAPE ABUTMENT ;
    PORT
      LAYER M3 ;
      RECT 822.231 0.000 822.249 0.054 ;
    END
  END r0_rd_out[210]
  PIN r0_rd_out[211]
    DIRECTION OUTPUT ;
    USE SIGNAL ;
    SHAPE ABUTMENT ;
    PORT
      LAYER M3 ;
      RECT 823.995 0.000 824.013 0.054 ;
    END
  END r0_rd_out[211]
  PIN r0_rd_out[212]
    DIRECTION OUTPUT ;
    USE SIGNAL ;
    SHAPE ABUTMENT ;
    PORT
      LAYER M3 ;
      RECT 825.759 0.000 825.777 0.054 ;
    END
  END r0_rd_out[212]
  PIN r0_rd_out[213]
    DIRECTION OUTPUT ;
    USE SIGNAL ;
    SHAPE ABUTMENT ;
    PORT
      LAYER M3 ;
      RECT 827.523 0.000 827.541 0.054 ;
    END
  END r0_rd_out[213]
  PIN r0_rd_out[214]
    DIRECTION OUTPUT ;
    USE SIGNAL ;
    SHAPE ABUTMENT ;
    PORT
      LAYER M3 ;
      RECT 829.287 0.000 829.305 0.054 ;
    END
  END r0_rd_out[214]
  PIN r0_rd_out[215]
    DIRECTION OUTPUT ;
    USE SIGNAL ;
    SHAPE ABUTMENT ;
    PORT
      LAYER M3 ;
      RECT 831.051 0.000 831.069 0.054 ;
    END
  END r0_rd_out[215]
  PIN r0_rd_out[216]
    DIRECTION OUTPUT ;
    USE SIGNAL ;
    SHAPE ABUTMENT ;
    PORT
      LAYER M3 ;
      RECT 832.815 0.000 832.833 0.054 ;
    END
  END r0_rd_out[216]
  PIN r0_rd_out[217]
    DIRECTION OUTPUT ;
    USE SIGNAL ;
    SHAPE ABUTMENT ;
    PORT
      LAYER M3 ;
      RECT 834.579 0.000 834.597 0.054 ;
    END
  END r0_rd_out[217]
  PIN r0_rd_out[218]
    DIRECTION OUTPUT ;
    USE SIGNAL ;
    SHAPE ABUTMENT ;
    PORT
      LAYER M3 ;
      RECT 836.343 0.000 836.361 0.054 ;
    END
  END r0_rd_out[218]
  PIN r0_rd_out[219]
    DIRECTION OUTPUT ;
    USE SIGNAL ;
    SHAPE ABUTMENT ;
    PORT
      LAYER M3 ;
      RECT 838.107 0.000 838.125 0.054 ;
    END
  END r0_rd_out[219]
  PIN r0_rd_out[220]
    DIRECTION OUTPUT ;
    USE SIGNAL ;
    SHAPE ABUTMENT ;
    PORT
      LAYER M3 ;
      RECT 839.871 0.000 839.889 0.054 ;
    END
  END r0_rd_out[220]
  PIN r0_rd_out[221]
    DIRECTION OUTPUT ;
    USE SIGNAL ;
    SHAPE ABUTMENT ;
    PORT
      LAYER M3 ;
      RECT 841.635 0.000 841.653 0.054 ;
    END
  END r0_rd_out[221]
  PIN r0_rd_out[222]
    DIRECTION OUTPUT ;
    USE SIGNAL ;
    SHAPE ABUTMENT ;
    PORT
      LAYER M3 ;
      RECT 843.399 0.000 843.417 0.054 ;
    END
  END r0_rd_out[222]
  PIN r0_rd_out[223]
    DIRECTION OUTPUT ;
    USE SIGNAL ;
    SHAPE ABUTMENT ;
    PORT
      LAYER M3 ;
      RECT 845.163 0.000 845.181 0.054 ;
    END
  END r0_rd_out[223]
  PIN r0_rd_out[224]
    DIRECTION OUTPUT ;
    USE SIGNAL ;
    SHAPE ABUTMENT ;
    PORT
      LAYER M3 ;
      RECT 846.927 0.000 846.945 0.054 ;
    END
  END r0_rd_out[224]
  PIN r0_rd_out[225]
    DIRECTION OUTPUT ;
    USE SIGNAL ;
    SHAPE ABUTMENT ;
    PORT
      LAYER M3 ;
      RECT 848.691 0.000 848.709 0.054 ;
    END
  END r0_rd_out[225]
  PIN r0_rd_out[226]
    DIRECTION OUTPUT ;
    USE SIGNAL ;
    SHAPE ABUTMENT ;
    PORT
      LAYER M3 ;
      RECT 850.455 0.000 850.473 0.054 ;
    END
  END r0_rd_out[226]
  PIN r0_rd_out[227]
    DIRECTION OUTPUT ;
    USE SIGNAL ;
    SHAPE ABUTMENT ;
    PORT
      LAYER M3 ;
      RECT 852.219 0.000 852.237 0.054 ;
    END
  END r0_rd_out[227]
  PIN r0_rd_out[228]
    DIRECTION OUTPUT ;
    USE SIGNAL ;
    SHAPE ABUTMENT ;
    PORT
      LAYER M3 ;
      RECT 853.983 0.000 854.001 0.054 ;
    END
  END r0_rd_out[228]
  PIN r0_rd_out[229]
    DIRECTION OUTPUT ;
    USE SIGNAL ;
    SHAPE ABUTMENT ;
    PORT
      LAYER M3 ;
      RECT 855.747 0.000 855.765 0.054 ;
    END
  END r0_rd_out[229]
  PIN r0_rd_out[230]
    DIRECTION OUTPUT ;
    USE SIGNAL ;
    SHAPE ABUTMENT ;
    PORT
      LAYER M3 ;
      RECT 857.511 0.000 857.529 0.054 ;
    END
  END r0_rd_out[230]
  PIN r0_rd_out[231]
    DIRECTION OUTPUT ;
    USE SIGNAL ;
    SHAPE ABUTMENT ;
    PORT
      LAYER M3 ;
      RECT 859.275 0.000 859.293 0.054 ;
    END
  END r0_rd_out[231]
  PIN r0_rd_out[232]
    DIRECTION OUTPUT ;
    USE SIGNAL ;
    SHAPE ABUTMENT ;
    PORT
      LAYER M3 ;
      RECT 861.039 0.000 861.057 0.054 ;
    END
  END r0_rd_out[232]
  PIN r0_rd_out[233]
    DIRECTION OUTPUT ;
    USE SIGNAL ;
    SHAPE ABUTMENT ;
    PORT
      LAYER M3 ;
      RECT 862.803 0.000 862.821 0.054 ;
    END
  END r0_rd_out[233]
  PIN r0_rd_out[234]
    DIRECTION OUTPUT ;
    USE SIGNAL ;
    SHAPE ABUTMENT ;
    PORT
      LAYER M3 ;
      RECT 864.567 0.000 864.585 0.054 ;
    END
  END r0_rd_out[234]
  PIN r0_rd_out[235]
    DIRECTION OUTPUT ;
    USE SIGNAL ;
    SHAPE ABUTMENT ;
    PORT
      LAYER M3 ;
      RECT 866.331 0.000 866.349 0.054 ;
    END
  END r0_rd_out[235]
  PIN r0_rd_out[236]
    DIRECTION OUTPUT ;
    USE SIGNAL ;
    SHAPE ABUTMENT ;
    PORT
      LAYER M3 ;
      RECT 868.095 0.000 868.113 0.054 ;
    END
  END r0_rd_out[236]
  PIN r0_rd_out[237]
    DIRECTION OUTPUT ;
    USE SIGNAL ;
    SHAPE ABUTMENT ;
    PORT
      LAYER M3 ;
      RECT 869.859 0.000 869.877 0.054 ;
    END
  END r0_rd_out[237]
  PIN r0_rd_out[238]
    DIRECTION OUTPUT ;
    USE SIGNAL ;
    SHAPE ABUTMENT ;
    PORT
      LAYER M3 ;
      RECT 871.623 0.000 871.641 0.054 ;
    END
  END r0_rd_out[238]
  PIN r0_rd_out[239]
    DIRECTION OUTPUT ;
    USE SIGNAL ;
    SHAPE ABUTMENT ;
    PORT
      LAYER M3 ;
      RECT 873.387 0.000 873.405 0.054 ;
    END
  END r0_rd_out[239]
  PIN r0_rd_out[240]
    DIRECTION OUTPUT ;
    USE SIGNAL ;
    SHAPE ABUTMENT ;
    PORT
      LAYER M3 ;
      RECT 875.151 0.000 875.169 0.054 ;
    END
  END r0_rd_out[240]
  PIN r0_rd_out[241]
    DIRECTION OUTPUT ;
    USE SIGNAL ;
    SHAPE ABUTMENT ;
    PORT
      LAYER M3 ;
      RECT 876.915 0.000 876.933 0.054 ;
    END
  END r0_rd_out[241]
  PIN r0_rd_out[242]
    DIRECTION OUTPUT ;
    USE SIGNAL ;
    SHAPE ABUTMENT ;
    PORT
      LAYER M3 ;
      RECT 878.679 0.000 878.697 0.054 ;
    END
  END r0_rd_out[242]
  PIN r0_rd_out[243]
    DIRECTION OUTPUT ;
    USE SIGNAL ;
    SHAPE ABUTMENT ;
    PORT
      LAYER M3 ;
      RECT 880.443 0.000 880.461 0.054 ;
    END
  END r0_rd_out[243]
  PIN r0_rd_out[244]
    DIRECTION OUTPUT ;
    USE SIGNAL ;
    SHAPE ABUTMENT ;
    PORT
      LAYER M3 ;
      RECT 882.207 0.000 882.225 0.054 ;
    END
  END r0_rd_out[244]
  PIN r0_rd_out[245]
    DIRECTION OUTPUT ;
    USE SIGNAL ;
    SHAPE ABUTMENT ;
    PORT
      LAYER M3 ;
      RECT 883.971 0.000 883.989 0.054 ;
    END
  END r0_rd_out[245]
  PIN r0_rd_out[246]
    DIRECTION OUTPUT ;
    USE SIGNAL ;
    SHAPE ABUTMENT ;
    PORT
      LAYER M3 ;
      RECT 885.735 0.000 885.753 0.054 ;
    END
  END r0_rd_out[246]
  PIN r0_rd_out[247]
    DIRECTION OUTPUT ;
    USE SIGNAL ;
    SHAPE ABUTMENT ;
    PORT
      LAYER M3 ;
      RECT 887.499 0.000 887.517 0.054 ;
    END
  END r0_rd_out[247]
  PIN r0_rd_out[248]
    DIRECTION OUTPUT ;
    USE SIGNAL ;
    SHAPE ABUTMENT ;
    PORT
      LAYER M3 ;
      RECT 889.263 0.000 889.281 0.054 ;
    END
  END r0_rd_out[248]
  PIN r0_rd_out[249]
    DIRECTION OUTPUT ;
    USE SIGNAL ;
    SHAPE ABUTMENT ;
    PORT
      LAYER M3 ;
      RECT 891.027 0.000 891.045 0.054 ;
    END
  END r0_rd_out[249]
  PIN r0_rd_out[250]
    DIRECTION OUTPUT ;
    USE SIGNAL ;
    SHAPE ABUTMENT ;
    PORT
      LAYER M3 ;
      RECT 892.791 0.000 892.809 0.054 ;
    END
  END r0_rd_out[250]
  PIN r0_rd_out[251]
    DIRECTION OUTPUT ;
    USE SIGNAL ;
    SHAPE ABUTMENT ;
    PORT
      LAYER M3 ;
      RECT 894.555 0.000 894.573 0.054 ;
    END
  END r0_rd_out[251]
  PIN r0_rd_out[252]
    DIRECTION OUTPUT ;
    USE SIGNAL ;
    SHAPE ABUTMENT ;
    PORT
      LAYER M3 ;
      RECT 896.319 0.000 896.337 0.054 ;
    END
  END r0_rd_out[252]
  PIN r0_rd_out[253]
    DIRECTION OUTPUT ;
    USE SIGNAL ;
    SHAPE ABUTMENT ;
    PORT
      LAYER M3 ;
      RECT 898.083 0.000 898.101 0.054 ;
    END
  END r0_rd_out[253]
  PIN r0_rd_out[254]
    DIRECTION OUTPUT ;
    USE SIGNAL ;
    SHAPE ABUTMENT ;
    PORT
      LAYER M3 ;
      RECT 899.847 0.000 899.865 0.054 ;
    END
  END r0_rd_out[254]
  PIN r0_rd_out[255]
    DIRECTION OUTPUT ;
    USE SIGNAL ;
    SHAPE ABUTMENT ;
    PORT
      LAYER M3 ;
      RECT 901.611 0.000 901.629 0.054 ;
    END
  END r0_rd_out[255]
  PIN r0_rd_out[256]
    DIRECTION OUTPUT ;
    USE SIGNAL ;
    SHAPE ABUTMENT ;
    PORT
      LAYER M3 ;
      RECT 442.575 566.730 442.593 566.784 ;
    END
  END r0_rd_out[256]
  PIN r0_rd_out[257]
    DIRECTION OUTPUT ;
    USE SIGNAL ;
    SHAPE ABUTMENT ;
    PORT
      LAYER M3 ;
      RECT 444.303 566.730 444.321 566.784 ;
    END
  END r0_rd_out[257]
  PIN r0_rd_out[258]
    DIRECTION OUTPUT ;
    USE SIGNAL ;
    SHAPE ABUTMENT ;
    PORT
      LAYER M3 ;
      RECT 446.031 566.730 446.049 566.784 ;
    END
  END r0_rd_out[258]
  PIN r0_rd_out[259]
    DIRECTION OUTPUT ;
    USE SIGNAL ;
    SHAPE ABUTMENT ;
    PORT
      LAYER M3 ;
      RECT 447.759 566.730 447.777 566.784 ;
    END
  END r0_rd_out[259]
  PIN r0_rd_out[260]
    DIRECTION OUTPUT ;
    USE SIGNAL ;
    SHAPE ABUTMENT ;
    PORT
      LAYER M3 ;
      RECT 449.487 566.730 449.505 566.784 ;
    END
  END r0_rd_out[260]
  PIN r0_rd_out[261]
    DIRECTION OUTPUT ;
    USE SIGNAL ;
    SHAPE ABUTMENT ;
    PORT
      LAYER M3 ;
      RECT 451.215 566.730 451.233 566.784 ;
    END
  END r0_rd_out[261]
  PIN r0_rd_out[262]
    DIRECTION OUTPUT ;
    USE SIGNAL ;
    SHAPE ABUTMENT ;
    PORT
      LAYER M3 ;
      RECT 452.943 566.730 452.961 566.784 ;
    END
  END r0_rd_out[262]
  PIN r0_rd_out[263]
    DIRECTION OUTPUT ;
    USE SIGNAL ;
    SHAPE ABUTMENT ;
    PORT
      LAYER M3 ;
      RECT 454.671 566.730 454.689 566.784 ;
    END
  END r0_rd_out[263]
  PIN r0_rd_out[264]
    DIRECTION OUTPUT ;
    USE SIGNAL ;
    SHAPE ABUTMENT ;
    PORT
      LAYER M3 ;
      RECT 456.399 566.730 456.417 566.784 ;
    END
  END r0_rd_out[264]
  PIN r0_rd_out[265]
    DIRECTION OUTPUT ;
    USE SIGNAL ;
    SHAPE ABUTMENT ;
    PORT
      LAYER M3 ;
      RECT 458.127 566.730 458.145 566.784 ;
    END
  END r0_rd_out[265]
  PIN r0_rd_out[266]
    DIRECTION OUTPUT ;
    USE SIGNAL ;
    SHAPE ABUTMENT ;
    PORT
      LAYER M3 ;
      RECT 459.855 566.730 459.873 566.784 ;
    END
  END r0_rd_out[266]
  PIN r0_rd_out[267]
    DIRECTION OUTPUT ;
    USE SIGNAL ;
    SHAPE ABUTMENT ;
    PORT
      LAYER M3 ;
      RECT 461.583 566.730 461.601 566.784 ;
    END
  END r0_rd_out[267]
  PIN r0_rd_out[268]
    DIRECTION OUTPUT ;
    USE SIGNAL ;
    SHAPE ABUTMENT ;
    PORT
      LAYER M3 ;
      RECT 463.311 566.730 463.329 566.784 ;
    END
  END r0_rd_out[268]
  PIN r0_rd_out[269]
    DIRECTION OUTPUT ;
    USE SIGNAL ;
    SHAPE ABUTMENT ;
    PORT
      LAYER M3 ;
      RECT 465.039 566.730 465.057 566.784 ;
    END
  END r0_rd_out[269]
  PIN r0_rd_out[270]
    DIRECTION OUTPUT ;
    USE SIGNAL ;
    SHAPE ABUTMENT ;
    PORT
      LAYER M3 ;
      RECT 466.767 566.730 466.785 566.784 ;
    END
  END r0_rd_out[270]
  PIN r0_rd_out[271]
    DIRECTION OUTPUT ;
    USE SIGNAL ;
    SHAPE ABUTMENT ;
    PORT
      LAYER M3 ;
      RECT 468.495 566.730 468.513 566.784 ;
    END
  END r0_rd_out[271]
  PIN r0_rd_out[272]
    DIRECTION OUTPUT ;
    USE SIGNAL ;
    SHAPE ABUTMENT ;
    PORT
      LAYER M3 ;
      RECT 470.223 566.730 470.241 566.784 ;
    END
  END r0_rd_out[272]
  PIN r0_rd_out[273]
    DIRECTION OUTPUT ;
    USE SIGNAL ;
    SHAPE ABUTMENT ;
    PORT
      LAYER M3 ;
      RECT 471.951 566.730 471.969 566.784 ;
    END
  END r0_rd_out[273]
  PIN r0_rd_out[274]
    DIRECTION OUTPUT ;
    USE SIGNAL ;
    SHAPE ABUTMENT ;
    PORT
      LAYER M3 ;
      RECT 473.679 566.730 473.697 566.784 ;
    END
  END r0_rd_out[274]
  PIN r0_rd_out[275]
    DIRECTION OUTPUT ;
    USE SIGNAL ;
    SHAPE ABUTMENT ;
    PORT
      LAYER M3 ;
      RECT 475.407 566.730 475.425 566.784 ;
    END
  END r0_rd_out[275]
  PIN r0_rd_out[276]
    DIRECTION OUTPUT ;
    USE SIGNAL ;
    SHAPE ABUTMENT ;
    PORT
      LAYER M3 ;
      RECT 477.135 566.730 477.153 566.784 ;
    END
  END r0_rd_out[276]
  PIN r0_rd_out[277]
    DIRECTION OUTPUT ;
    USE SIGNAL ;
    SHAPE ABUTMENT ;
    PORT
      LAYER M3 ;
      RECT 478.863 566.730 478.881 566.784 ;
    END
  END r0_rd_out[277]
  PIN r0_rd_out[278]
    DIRECTION OUTPUT ;
    USE SIGNAL ;
    SHAPE ABUTMENT ;
    PORT
      LAYER M3 ;
      RECT 480.591 566.730 480.609 566.784 ;
    END
  END r0_rd_out[278]
  PIN r0_rd_out[279]
    DIRECTION OUTPUT ;
    USE SIGNAL ;
    SHAPE ABUTMENT ;
    PORT
      LAYER M3 ;
      RECT 482.319 566.730 482.337 566.784 ;
    END
  END r0_rd_out[279]
  PIN r0_rd_out[280]
    DIRECTION OUTPUT ;
    USE SIGNAL ;
    SHAPE ABUTMENT ;
    PORT
      LAYER M3 ;
      RECT 484.047 566.730 484.065 566.784 ;
    END
  END r0_rd_out[280]
  PIN r0_rd_out[281]
    DIRECTION OUTPUT ;
    USE SIGNAL ;
    SHAPE ABUTMENT ;
    PORT
      LAYER M3 ;
      RECT 485.775 566.730 485.793 566.784 ;
    END
  END r0_rd_out[281]
  PIN r0_rd_out[282]
    DIRECTION OUTPUT ;
    USE SIGNAL ;
    SHAPE ABUTMENT ;
    PORT
      LAYER M3 ;
      RECT 487.503 566.730 487.521 566.784 ;
    END
  END r0_rd_out[282]
  PIN r0_rd_out[283]
    DIRECTION OUTPUT ;
    USE SIGNAL ;
    SHAPE ABUTMENT ;
    PORT
      LAYER M3 ;
      RECT 489.231 566.730 489.249 566.784 ;
    END
  END r0_rd_out[283]
  PIN r0_rd_out[284]
    DIRECTION OUTPUT ;
    USE SIGNAL ;
    SHAPE ABUTMENT ;
    PORT
      LAYER M3 ;
      RECT 490.959 566.730 490.977 566.784 ;
    END
  END r0_rd_out[284]
  PIN r0_rd_out[285]
    DIRECTION OUTPUT ;
    USE SIGNAL ;
    SHAPE ABUTMENT ;
    PORT
      LAYER M3 ;
      RECT 492.687 566.730 492.705 566.784 ;
    END
  END r0_rd_out[285]
  PIN r0_rd_out[286]
    DIRECTION OUTPUT ;
    USE SIGNAL ;
    SHAPE ABUTMENT ;
    PORT
      LAYER M3 ;
      RECT 494.415 566.730 494.433 566.784 ;
    END
  END r0_rd_out[286]
  PIN r0_rd_out[287]
    DIRECTION OUTPUT ;
    USE SIGNAL ;
    SHAPE ABUTMENT ;
    PORT
      LAYER M3 ;
      RECT 496.143 566.730 496.161 566.784 ;
    END
  END r0_rd_out[287]
  PIN r0_rd_out[288]
    DIRECTION OUTPUT ;
    USE SIGNAL ;
    SHAPE ABUTMENT ;
    PORT
      LAYER M3 ;
      RECT 497.871 566.730 497.889 566.784 ;
    END
  END r0_rd_out[288]
  PIN r0_rd_out[289]
    DIRECTION OUTPUT ;
    USE SIGNAL ;
    SHAPE ABUTMENT ;
    PORT
      LAYER M3 ;
      RECT 499.599 566.730 499.617 566.784 ;
    END
  END r0_rd_out[289]
  PIN r0_rd_out[290]
    DIRECTION OUTPUT ;
    USE SIGNAL ;
    SHAPE ABUTMENT ;
    PORT
      LAYER M3 ;
      RECT 501.327 566.730 501.345 566.784 ;
    END
  END r0_rd_out[290]
  PIN r0_rd_out[291]
    DIRECTION OUTPUT ;
    USE SIGNAL ;
    SHAPE ABUTMENT ;
    PORT
      LAYER M3 ;
      RECT 503.055 566.730 503.073 566.784 ;
    END
  END r0_rd_out[291]
  PIN r0_rd_out[292]
    DIRECTION OUTPUT ;
    USE SIGNAL ;
    SHAPE ABUTMENT ;
    PORT
      LAYER M3 ;
      RECT 504.783 566.730 504.801 566.784 ;
    END
  END r0_rd_out[292]
  PIN r0_rd_out[293]
    DIRECTION OUTPUT ;
    USE SIGNAL ;
    SHAPE ABUTMENT ;
    PORT
      LAYER M3 ;
      RECT 506.511 566.730 506.529 566.784 ;
    END
  END r0_rd_out[293]
  PIN r0_rd_out[294]
    DIRECTION OUTPUT ;
    USE SIGNAL ;
    SHAPE ABUTMENT ;
    PORT
      LAYER M3 ;
      RECT 508.239 566.730 508.257 566.784 ;
    END
  END r0_rd_out[294]
  PIN r0_rd_out[295]
    DIRECTION OUTPUT ;
    USE SIGNAL ;
    SHAPE ABUTMENT ;
    PORT
      LAYER M3 ;
      RECT 509.967 566.730 509.985 566.784 ;
    END
  END r0_rd_out[295]
  PIN r0_rd_out[296]
    DIRECTION OUTPUT ;
    USE SIGNAL ;
    SHAPE ABUTMENT ;
    PORT
      LAYER M3 ;
      RECT 511.695 566.730 511.713 566.784 ;
    END
  END r0_rd_out[296]
  PIN r0_rd_out[297]
    DIRECTION OUTPUT ;
    USE SIGNAL ;
    SHAPE ABUTMENT ;
    PORT
      LAYER M3 ;
      RECT 513.423 566.730 513.441 566.784 ;
    END
  END r0_rd_out[297]
  PIN r0_rd_out[298]
    DIRECTION OUTPUT ;
    USE SIGNAL ;
    SHAPE ABUTMENT ;
    PORT
      LAYER M3 ;
      RECT 515.151 566.730 515.169 566.784 ;
    END
  END r0_rd_out[298]
  PIN r0_rd_out[299]
    DIRECTION OUTPUT ;
    USE SIGNAL ;
    SHAPE ABUTMENT ;
    PORT
      LAYER M3 ;
      RECT 516.879 566.730 516.897 566.784 ;
    END
  END r0_rd_out[299]
  PIN r0_rd_out[300]
    DIRECTION OUTPUT ;
    USE SIGNAL ;
    SHAPE ABUTMENT ;
    PORT
      LAYER M3 ;
      RECT 518.607 566.730 518.625 566.784 ;
    END
  END r0_rd_out[300]
  PIN r0_rd_out[301]
    DIRECTION OUTPUT ;
    USE SIGNAL ;
    SHAPE ABUTMENT ;
    PORT
      LAYER M3 ;
      RECT 520.335 566.730 520.353 566.784 ;
    END
  END r0_rd_out[301]
  PIN r0_rd_out[302]
    DIRECTION OUTPUT ;
    USE SIGNAL ;
    SHAPE ABUTMENT ;
    PORT
      LAYER M3 ;
      RECT 522.063 566.730 522.081 566.784 ;
    END
  END r0_rd_out[302]
  PIN r0_rd_out[303]
    DIRECTION OUTPUT ;
    USE SIGNAL ;
    SHAPE ABUTMENT ;
    PORT
      LAYER M3 ;
      RECT 523.791 566.730 523.809 566.784 ;
    END
  END r0_rd_out[303]
  PIN r0_rd_out[304]
    DIRECTION OUTPUT ;
    USE SIGNAL ;
    SHAPE ABUTMENT ;
    PORT
      LAYER M3 ;
      RECT 525.519 566.730 525.537 566.784 ;
    END
  END r0_rd_out[304]
  PIN r0_rd_out[305]
    DIRECTION OUTPUT ;
    USE SIGNAL ;
    SHAPE ABUTMENT ;
    PORT
      LAYER M3 ;
      RECT 527.247 566.730 527.265 566.784 ;
    END
  END r0_rd_out[305]
  PIN r0_rd_out[306]
    DIRECTION OUTPUT ;
    USE SIGNAL ;
    SHAPE ABUTMENT ;
    PORT
      LAYER M3 ;
      RECT 528.975 566.730 528.993 566.784 ;
    END
  END r0_rd_out[306]
  PIN r0_rd_out[307]
    DIRECTION OUTPUT ;
    USE SIGNAL ;
    SHAPE ABUTMENT ;
    PORT
      LAYER M3 ;
      RECT 530.703 566.730 530.721 566.784 ;
    END
  END r0_rd_out[307]
  PIN r0_rd_out[308]
    DIRECTION OUTPUT ;
    USE SIGNAL ;
    SHAPE ABUTMENT ;
    PORT
      LAYER M3 ;
      RECT 532.431 566.730 532.449 566.784 ;
    END
  END r0_rd_out[308]
  PIN r0_rd_out[309]
    DIRECTION OUTPUT ;
    USE SIGNAL ;
    SHAPE ABUTMENT ;
    PORT
      LAYER M3 ;
      RECT 534.159 566.730 534.177 566.784 ;
    END
  END r0_rd_out[309]
  PIN r0_rd_out[310]
    DIRECTION OUTPUT ;
    USE SIGNAL ;
    SHAPE ABUTMENT ;
    PORT
      LAYER M3 ;
      RECT 535.887 566.730 535.905 566.784 ;
    END
  END r0_rd_out[310]
  PIN r0_rd_out[311]
    DIRECTION OUTPUT ;
    USE SIGNAL ;
    SHAPE ABUTMENT ;
    PORT
      LAYER M3 ;
      RECT 537.615 566.730 537.633 566.784 ;
    END
  END r0_rd_out[311]
  PIN r0_rd_out[312]
    DIRECTION OUTPUT ;
    USE SIGNAL ;
    SHAPE ABUTMENT ;
    PORT
      LAYER M3 ;
      RECT 539.343 566.730 539.361 566.784 ;
    END
  END r0_rd_out[312]
  PIN r0_rd_out[313]
    DIRECTION OUTPUT ;
    USE SIGNAL ;
    SHAPE ABUTMENT ;
    PORT
      LAYER M3 ;
      RECT 541.071 566.730 541.089 566.784 ;
    END
  END r0_rd_out[313]
  PIN r0_rd_out[314]
    DIRECTION OUTPUT ;
    USE SIGNAL ;
    SHAPE ABUTMENT ;
    PORT
      LAYER M3 ;
      RECT 542.799 566.730 542.817 566.784 ;
    END
  END r0_rd_out[314]
  PIN r0_rd_out[315]
    DIRECTION OUTPUT ;
    USE SIGNAL ;
    SHAPE ABUTMENT ;
    PORT
      LAYER M3 ;
      RECT 544.527 566.730 544.545 566.784 ;
    END
  END r0_rd_out[315]
  PIN r0_rd_out[316]
    DIRECTION OUTPUT ;
    USE SIGNAL ;
    SHAPE ABUTMENT ;
    PORT
      LAYER M3 ;
      RECT 546.255 566.730 546.273 566.784 ;
    END
  END r0_rd_out[316]
  PIN r0_rd_out[317]
    DIRECTION OUTPUT ;
    USE SIGNAL ;
    SHAPE ABUTMENT ;
    PORT
      LAYER M3 ;
      RECT 547.983 566.730 548.001 566.784 ;
    END
  END r0_rd_out[317]
  PIN r0_rd_out[318]
    DIRECTION OUTPUT ;
    USE SIGNAL ;
    SHAPE ABUTMENT ;
    PORT
      LAYER M3 ;
      RECT 549.711 566.730 549.729 566.784 ;
    END
  END r0_rd_out[318]
  PIN r0_rd_out[319]
    DIRECTION OUTPUT ;
    USE SIGNAL ;
    SHAPE ABUTMENT ;
    PORT
      LAYER M3 ;
      RECT 551.439 566.730 551.457 566.784 ;
    END
  END r0_rd_out[319]
  PIN r0_rd_out[320]
    DIRECTION OUTPUT ;
    USE SIGNAL ;
    SHAPE ABUTMENT ;
    PORT
      LAYER M3 ;
      RECT 553.167 566.730 553.185 566.784 ;
    END
  END r0_rd_out[320]
  PIN r0_rd_out[321]
    DIRECTION OUTPUT ;
    USE SIGNAL ;
    SHAPE ABUTMENT ;
    PORT
      LAYER M3 ;
      RECT 554.895 566.730 554.913 566.784 ;
    END
  END r0_rd_out[321]
  PIN r0_rd_out[322]
    DIRECTION OUTPUT ;
    USE SIGNAL ;
    SHAPE ABUTMENT ;
    PORT
      LAYER M3 ;
      RECT 556.623 566.730 556.641 566.784 ;
    END
  END r0_rd_out[322]
  PIN r0_rd_out[323]
    DIRECTION OUTPUT ;
    USE SIGNAL ;
    SHAPE ABUTMENT ;
    PORT
      LAYER M3 ;
      RECT 558.351 566.730 558.369 566.784 ;
    END
  END r0_rd_out[323]
  PIN r0_rd_out[324]
    DIRECTION OUTPUT ;
    USE SIGNAL ;
    SHAPE ABUTMENT ;
    PORT
      LAYER M3 ;
      RECT 560.079 566.730 560.097 566.784 ;
    END
  END r0_rd_out[324]
  PIN r0_rd_out[325]
    DIRECTION OUTPUT ;
    USE SIGNAL ;
    SHAPE ABUTMENT ;
    PORT
      LAYER M3 ;
      RECT 561.807 566.730 561.825 566.784 ;
    END
  END r0_rd_out[325]
  PIN r0_rd_out[326]
    DIRECTION OUTPUT ;
    USE SIGNAL ;
    SHAPE ABUTMENT ;
    PORT
      LAYER M3 ;
      RECT 563.535 566.730 563.553 566.784 ;
    END
  END r0_rd_out[326]
  PIN r0_rd_out[327]
    DIRECTION OUTPUT ;
    USE SIGNAL ;
    SHAPE ABUTMENT ;
    PORT
      LAYER M3 ;
      RECT 565.263 566.730 565.281 566.784 ;
    END
  END r0_rd_out[327]
  PIN r0_rd_out[328]
    DIRECTION OUTPUT ;
    USE SIGNAL ;
    SHAPE ABUTMENT ;
    PORT
      LAYER M3 ;
      RECT 566.991 566.730 567.009 566.784 ;
    END
  END r0_rd_out[328]
  PIN r0_rd_out[329]
    DIRECTION OUTPUT ;
    USE SIGNAL ;
    SHAPE ABUTMENT ;
    PORT
      LAYER M3 ;
      RECT 568.719 566.730 568.737 566.784 ;
    END
  END r0_rd_out[329]
  PIN r0_rd_out[330]
    DIRECTION OUTPUT ;
    USE SIGNAL ;
    SHAPE ABUTMENT ;
    PORT
      LAYER M3 ;
      RECT 570.447 566.730 570.465 566.784 ;
    END
  END r0_rd_out[330]
  PIN r0_rd_out[331]
    DIRECTION OUTPUT ;
    USE SIGNAL ;
    SHAPE ABUTMENT ;
    PORT
      LAYER M3 ;
      RECT 572.175 566.730 572.193 566.784 ;
    END
  END r0_rd_out[331]
  PIN r0_rd_out[332]
    DIRECTION OUTPUT ;
    USE SIGNAL ;
    SHAPE ABUTMENT ;
    PORT
      LAYER M3 ;
      RECT 573.903 566.730 573.921 566.784 ;
    END
  END r0_rd_out[332]
  PIN r0_rd_out[333]
    DIRECTION OUTPUT ;
    USE SIGNAL ;
    SHAPE ABUTMENT ;
    PORT
      LAYER M3 ;
      RECT 575.631 566.730 575.649 566.784 ;
    END
  END r0_rd_out[333]
  PIN r0_rd_out[334]
    DIRECTION OUTPUT ;
    USE SIGNAL ;
    SHAPE ABUTMENT ;
    PORT
      LAYER M3 ;
      RECT 577.359 566.730 577.377 566.784 ;
    END
  END r0_rd_out[334]
  PIN r0_rd_out[335]
    DIRECTION OUTPUT ;
    USE SIGNAL ;
    SHAPE ABUTMENT ;
    PORT
      LAYER M3 ;
      RECT 579.087 566.730 579.105 566.784 ;
    END
  END r0_rd_out[335]
  PIN r0_rd_out[336]
    DIRECTION OUTPUT ;
    USE SIGNAL ;
    SHAPE ABUTMENT ;
    PORT
      LAYER M3 ;
      RECT 580.815 566.730 580.833 566.784 ;
    END
  END r0_rd_out[336]
  PIN r0_rd_out[337]
    DIRECTION OUTPUT ;
    USE SIGNAL ;
    SHAPE ABUTMENT ;
    PORT
      LAYER M3 ;
      RECT 582.543 566.730 582.561 566.784 ;
    END
  END r0_rd_out[337]
  PIN r0_rd_out[338]
    DIRECTION OUTPUT ;
    USE SIGNAL ;
    SHAPE ABUTMENT ;
    PORT
      LAYER M3 ;
      RECT 584.271 566.730 584.289 566.784 ;
    END
  END r0_rd_out[338]
  PIN r0_rd_out[339]
    DIRECTION OUTPUT ;
    USE SIGNAL ;
    SHAPE ABUTMENT ;
    PORT
      LAYER M3 ;
      RECT 585.999 566.730 586.017 566.784 ;
    END
  END r0_rd_out[339]
  PIN r0_rd_out[340]
    DIRECTION OUTPUT ;
    USE SIGNAL ;
    SHAPE ABUTMENT ;
    PORT
      LAYER M3 ;
      RECT 587.727 566.730 587.745 566.784 ;
    END
  END r0_rd_out[340]
  PIN r0_rd_out[341]
    DIRECTION OUTPUT ;
    USE SIGNAL ;
    SHAPE ABUTMENT ;
    PORT
      LAYER M3 ;
      RECT 589.455 566.730 589.473 566.784 ;
    END
  END r0_rd_out[341]
  PIN r0_rd_out[342]
    DIRECTION OUTPUT ;
    USE SIGNAL ;
    SHAPE ABUTMENT ;
    PORT
      LAYER M3 ;
      RECT 591.183 566.730 591.201 566.784 ;
    END
  END r0_rd_out[342]
  PIN r0_rd_out[343]
    DIRECTION OUTPUT ;
    USE SIGNAL ;
    SHAPE ABUTMENT ;
    PORT
      LAYER M3 ;
      RECT 592.911 566.730 592.929 566.784 ;
    END
  END r0_rd_out[343]
  PIN r0_rd_out[344]
    DIRECTION OUTPUT ;
    USE SIGNAL ;
    SHAPE ABUTMENT ;
    PORT
      LAYER M3 ;
      RECT 594.639 566.730 594.657 566.784 ;
    END
  END r0_rd_out[344]
  PIN r0_rd_out[345]
    DIRECTION OUTPUT ;
    USE SIGNAL ;
    SHAPE ABUTMENT ;
    PORT
      LAYER M3 ;
      RECT 596.367 566.730 596.385 566.784 ;
    END
  END r0_rd_out[345]
  PIN r0_rd_out[346]
    DIRECTION OUTPUT ;
    USE SIGNAL ;
    SHAPE ABUTMENT ;
    PORT
      LAYER M3 ;
      RECT 598.095 566.730 598.113 566.784 ;
    END
  END r0_rd_out[346]
  PIN r0_rd_out[347]
    DIRECTION OUTPUT ;
    USE SIGNAL ;
    SHAPE ABUTMENT ;
    PORT
      LAYER M3 ;
      RECT 599.823 566.730 599.841 566.784 ;
    END
  END r0_rd_out[347]
  PIN r0_rd_out[348]
    DIRECTION OUTPUT ;
    USE SIGNAL ;
    SHAPE ABUTMENT ;
    PORT
      LAYER M3 ;
      RECT 601.551 566.730 601.569 566.784 ;
    END
  END r0_rd_out[348]
  PIN r0_rd_out[349]
    DIRECTION OUTPUT ;
    USE SIGNAL ;
    SHAPE ABUTMENT ;
    PORT
      LAYER M3 ;
      RECT 603.279 566.730 603.297 566.784 ;
    END
  END r0_rd_out[349]
  PIN r0_rd_out[350]
    DIRECTION OUTPUT ;
    USE SIGNAL ;
    SHAPE ABUTMENT ;
    PORT
      LAYER M3 ;
      RECT 605.007 566.730 605.025 566.784 ;
    END
  END r0_rd_out[350]
  PIN r0_rd_out[351]
    DIRECTION OUTPUT ;
    USE SIGNAL ;
    SHAPE ABUTMENT ;
    PORT
      LAYER M3 ;
      RECT 606.735 566.730 606.753 566.784 ;
    END
  END r0_rd_out[351]
  PIN r0_rd_out[352]
    DIRECTION OUTPUT ;
    USE SIGNAL ;
    SHAPE ABUTMENT ;
    PORT
      LAYER M3 ;
      RECT 608.463 566.730 608.481 566.784 ;
    END
  END r0_rd_out[352]
  PIN r0_rd_out[353]
    DIRECTION OUTPUT ;
    USE SIGNAL ;
    SHAPE ABUTMENT ;
    PORT
      LAYER M3 ;
      RECT 610.191 566.730 610.209 566.784 ;
    END
  END r0_rd_out[353]
  PIN r0_rd_out[354]
    DIRECTION OUTPUT ;
    USE SIGNAL ;
    SHAPE ABUTMENT ;
    PORT
      LAYER M3 ;
      RECT 611.919 566.730 611.937 566.784 ;
    END
  END r0_rd_out[354]
  PIN r0_rd_out[355]
    DIRECTION OUTPUT ;
    USE SIGNAL ;
    SHAPE ABUTMENT ;
    PORT
      LAYER M3 ;
      RECT 613.647 566.730 613.665 566.784 ;
    END
  END r0_rd_out[355]
  PIN r0_rd_out[356]
    DIRECTION OUTPUT ;
    USE SIGNAL ;
    SHAPE ABUTMENT ;
    PORT
      LAYER M3 ;
      RECT 615.375 566.730 615.393 566.784 ;
    END
  END r0_rd_out[356]
  PIN r0_rd_out[357]
    DIRECTION OUTPUT ;
    USE SIGNAL ;
    SHAPE ABUTMENT ;
    PORT
      LAYER M3 ;
      RECT 617.103 566.730 617.121 566.784 ;
    END
  END r0_rd_out[357]
  PIN r0_rd_out[358]
    DIRECTION OUTPUT ;
    USE SIGNAL ;
    SHAPE ABUTMENT ;
    PORT
      LAYER M3 ;
      RECT 618.831 566.730 618.849 566.784 ;
    END
  END r0_rd_out[358]
  PIN r0_rd_out[359]
    DIRECTION OUTPUT ;
    USE SIGNAL ;
    SHAPE ABUTMENT ;
    PORT
      LAYER M3 ;
      RECT 620.559 566.730 620.577 566.784 ;
    END
  END r0_rd_out[359]
  PIN r0_rd_out[360]
    DIRECTION OUTPUT ;
    USE SIGNAL ;
    SHAPE ABUTMENT ;
    PORT
      LAYER M3 ;
      RECT 622.287 566.730 622.305 566.784 ;
    END
  END r0_rd_out[360]
  PIN r0_rd_out[361]
    DIRECTION OUTPUT ;
    USE SIGNAL ;
    SHAPE ABUTMENT ;
    PORT
      LAYER M3 ;
      RECT 624.015 566.730 624.033 566.784 ;
    END
  END r0_rd_out[361]
  PIN r0_rd_out[362]
    DIRECTION OUTPUT ;
    USE SIGNAL ;
    SHAPE ABUTMENT ;
    PORT
      LAYER M3 ;
      RECT 625.743 566.730 625.761 566.784 ;
    END
  END r0_rd_out[362]
  PIN r0_rd_out[363]
    DIRECTION OUTPUT ;
    USE SIGNAL ;
    SHAPE ABUTMENT ;
    PORT
      LAYER M3 ;
      RECT 627.471 566.730 627.489 566.784 ;
    END
  END r0_rd_out[363]
  PIN r0_rd_out[364]
    DIRECTION OUTPUT ;
    USE SIGNAL ;
    SHAPE ABUTMENT ;
    PORT
      LAYER M3 ;
      RECT 629.199 566.730 629.217 566.784 ;
    END
  END r0_rd_out[364]
  PIN r0_rd_out[365]
    DIRECTION OUTPUT ;
    USE SIGNAL ;
    SHAPE ABUTMENT ;
    PORT
      LAYER M3 ;
      RECT 630.927 566.730 630.945 566.784 ;
    END
  END r0_rd_out[365]
  PIN r0_rd_out[366]
    DIRECTION OUTPUT ;
    USE SIGNAL ;
    SHAPE ABUTMENT ;
    PORT
      LAYER M3 ;
      RECT 632.655 566.730 632.673 566.784 ;
    END
  END r0_rd_out[366]
  PIN r0_rd_out[367]
    DIRECTION OUTPUT ;
    USE SIGNAL ;
    SHAPE ABUTMENT ;
    PORT
      LAYER M3 ;
      RECT 634.383 566.730 634.401 566.784 ;
    END
  END r0_rd_out[367]
  PIN r0_rd_out[368]
    DIRECTION OUTPUT ;
    USE SIGNAL ;
    SHAPE ABUTMENT ;
    PORT
      LAYER M3 ;
      RECT 636.111 566.730 636.129 566.784 ;
    END
  END r0_rd_out[368]
  PIN r0_rd_out[369]
    DIRECTION OUTPUT ;
    USE SIGNAL ;
    SHAPE ABUTMENT ;
    PORT
      LAYER M3 ;
      RECT 637.839 566.730 637.857 566.784 ;
    END
  END r0_rd_out[369]
  PIN r0_rd_out[370]
    DIRECTION OUTPUT ;
    USE SIGNAL ;
    SHAPE ABUTMENT ;
    PORT
      LAYER M3 ;
      RECT 639.567 566.730 639.585 566.784 ;
    END
  END r0_rd_out[370]
  PIN r0_rd_out[371]
    DIRECTION OUTPUT ;
    USE SIGNAL ;
    SHAPE ABUTMENT ;
    PORT
      LAYER M3 ;
      RECT 641.295 566.730 641.313 566.784 ;
    END
  END r0_rd_out[371]
  PIN r0_rd_out[372]
    DIRECTION OUTPUT ;
    USE SIGNAL ;
    SHAPE ABUTMENT ;
    PORT
      LAYER M3 ;
      RECT 643.023 566.730 643.041 566.784 ;
    END
  END r0_rd_out[372]
  PIN r0_rd_out[373]
    DIRECTION OUTPUT ;
    USE SIGNAL ;
    SHAPE ABUTMENT ;
    PORT
      LAYER M3 ;
      RECT 644.751 566.730 644.769 566.784 ;
    END
  END r0_rd_out[373]
  PIN r0_rd_out[374]
    DIRECTION OUTPUT ;
    USE SIGNAL ;
    SHAPE ABUTMENT ;
    PORT
      LAYER M3 ;
      RECT 646.479 566.730 646.497 566.784 ;
    END
  END r0_rd_out[374]
  PIN r0_rd_out[375]
    DIRECTION OUTPUT ;
    USE SIGNAL ;
    SHAPE ABUTMENT ;
    PORT
      LAYER M3 ;
      RECT 648.207 566.730 648.225 566.784 ;
    END
  END r0_rd_out[375]
  PIN r0_rd_out[376]
    DIRECTION OUTPUT ;
    USE SIGNAL ;
    SHAPE ABUTMENT ;
    PORT
      LAYER M3 ;
      RECT 649.935 566.730 649.953 566.784 ;
    END
  END r0_rd_out[376]
  PIN r0_rd_out[377]
    DIRECTION OUTPUT ;
    USE SIGNAL ;
    SHAPE ABUTMENT ;
    PORT
      LAYER M3 ;
      RECT 651.663 566.730 651.681 566.784 ;
    END
  END r0_rd_out[377]
  PIN r0_rd_out[378]
    DIRECTION OUTPUT ;
    USE SIGNAL ;
    SHAPE ABUTMENT ;
    PORT
      LAYER M3 ;
      RECT 653.391 566.730 653.409 566.784 ;
    END
  END r0_rd_out[378]
  PIN r0_rd_out[379]
    DIRECTION OUTPUT ;
    USE SIGNAL ;
    SHAPE ABUTMENT ;
    PORT
      LAYER M3 ;
      RECT 655.119 566.730 655.137 566.784 ;
    END
  END r0_rd_out[379]
  PIN r0_rd_out[380]
    DIRECTION OUTPUT ;
    USE SIGNAL ;
    SHAPE ABUTMENT ;
    PORT
      LAYER M3 ;
      RECT 656.847 566.730 656.865 566.784 ;
    END
  END r0_rd_out[380]
  PIN r0_rd_out[381]
    DIRECTION OUTPUT ;
    USE SIGNAL ;
    SHAPE ABUTMENT ;
    PORT
      LAYER M3 ;
      RECT 658.575 566.730 658.593 566.784 ;
    END
  END r0_rd_out[381]
  PIN r0_rd_out[382]
    DIRECTION OUTPUT ;
    USE SIGNAL ;
    SHAPE ABUTMENT ;
    PORT
      LAYER M3 ;
      RECT 660.303 566.730 660.321 566.784 ;
    END
  END r0_rd_out[382]
  PIN r0_rd_out[383]
    DIRECTION OUTPUT ;
    USE SIGNAL ;
    SHAPE ABUTMENT ;
    PORT
      LAYER M3 ;
      RECT 662.031 566.730 662.049 566.784 ;
    END
  END r0_rd_out[383]
  PIN r0_rd_out[384]
    DIRECTION OUTPUT ;
    USE SIGNAL ;
    SHAPE ABUTMENT ;
    PORT
      LAYER M3 ;
      RECT 663.759 566.730 663.777 566.784 ;
    END
  END r0_rd_out[384]
  PIN r0_rd_out[385]
    DIRECTION OUTPUT ;
    USE SIGNAL ;
    SHAPE ABUTMENT ;
    PORT
      LAYER M3 ;
      RECT 665.487 566.730 665.505 566.784 ;
    END
  END r0_rd_out[385]
  PIN r0_rd_out[386]
    DIRECTION OUTPUT ;
    USE SIGNAL ;
    SHAPE ABUTMENT ;
    PORT
      LAYER M3 ;
      RECT 667.215 566.730 667.233 566.784 ;
    END
  END r0_rd_out[386]
  PIN r0_rd_out[387]
    DIRECTION OUTPUT ;
    USE SIGNAL ;
    SHAPE ABUTMENT ;
    PORT
      LAYER M3 ;
      RECT 668.943 566.730 668.961 566.784 ;
    END
  END r0_rd_out[387]
  PIN r0_rd_out[388]
    DIRECTION OUTPUT ;
    USE SIGNAL ;
    SHAPE ABUTMENT ;
    PORT
      LAYER M3 ;
      RECT 670.671 566.730 670.689 566.784 ;
    END
  END r0_rd_out[388]
  PIN r0_rd_out[389]
    DIRECTION OUTPUT ;
    USE SIGNAL ;
    SHAPE ABUTMENT ;
    PORT
      LAYER M3 ;
      RECT 672.399 566.730 672.417 566.784 ;
    END
  END r0_rd_out[389]
  PIN r0_rd_out[390]
    DIRECTION OUTPUT ;
    USE SIGNAL ;
    SHAPE ABUTMENT ;
    PORT
      LAYER M3 ;
      RECT 674.127 566.730 674.145 566.784 ;
    END
  END r0_rd_out[390]
  PIN r0_rd_out[391]
    DIRECTION OUTPUT ;
    USE SIGNAL ;
    SHAPE ABUTMENT ;
    PORT
      LAYER M3 ;
      RECT 675.855 566.730 675.873 566.784 ;
    END
  END r0_rd_out[391]
  PIN r0_rd_out[392]
    DIRECTION OUTPUT ;
    USE SIGNAL ;
    SHAPE ABUTMENT ;
    PORT
      LAYER M3 ;
      RECT 677.583 566.730 677.601 566.784 ;
    END
  END r0_rd_out[392]
  PIN r0_rd_out[393]
    DIRECTION OUTPUT ;
    USE SIGNAL ;
    SHAPE ABUTMENT ;
    PORT
      LAYER M3 ;
      RECT 679.311 566.730 679.329 566.784 ;
    END
  END r0_rd_out[393]
  PIN r0_rd_out[394]
    DIRECTION OUTPUT ;
    USE SIGNAL ;
    SHAPE ABUTMENT ;
    PORT
      LAYER M3 ;
      RECT 681.039 566.730 681.057 566.784 ;
    END
  END r0_rd_out[394]
  PIN r0_rd_out[395]
    DIRECTION OUTPUT ;
    USE SIGNAL ;
    SHAPE ABUTMENT ;
    PORT
      LAYER M3 ;
      RECT 682.767 566.730 682.785 566.784 ;
    END
  END r0_rd_out[395]
  PIN r0_rd_out[396]
    DIRECTION OUTPUT ;
    USE SIGNAL ;
    SHAPE ABUTMENT ;
    PORT
      LAYER M3 ;
      RECT 684.495 566.730 684.513 566.784 ;
    END
  END r0_rd_out[396]
  PIN r0_rd_out[397]
    DIRECTION OUTPUT ;
    USE SIGNAL ;
    SHAPE ABUTMENT ;
    PORT
      LAYER M3 ;
      RECT 686.223 566.730 686.241 566.784 ;
    END
  END r0_rd_out[397]
  PIN r0_rd_out[398]
    DIRECTION OUTPUT ;
    USE SIGNAL ;
    SHAPE ABUTMENT ;
    PORT
      LAYER M3 ;
      RECT 687.951 566.730 687.969 566.784 ;
    END
  END r0_rd_out[398]
  PIN r0_rd_out[399]
    DIRECTION OUTPUT ;
    USE SIGNAL ;
    SHAPE ABUTMENT ;
    PORT
      LAYER M3 ;
      RECT 689.679 566.730 689.697 566.784 ;
    END
  END r0_rd_out[399]
  PIN r0_rd_out[400]
    DIRECTION OUTPUT ;
    USE SIGNAL ;
    SHAPE ABUTMENT ;
    PORT
      LAYER M3 ;
      RECT 691.407 566.730 691.425 566.784 ;
    END
  END r0_rd_out[400]
  PIN r0_rd_out[401]
    DIRECTION OUTPUT ;
    USE SIGNAL ;
    SHAPE ABUTMENT ;
    PORT
      LAYER M3 ;
      RECT 693.135 566.730 693.153 566.784 ;
    END
  END r0_rd_out[401]
  PIN r0_rd_out[402]
    DIRECTION OUTPUT ;
    USE SIGNAL ;
    SHAPE ABUTMENT ;
    PORT
      LAYER M3 ;
      RECT 694.863 566.730 694.881 566.784 ;
    END
  END r0_rd_out[402]
  PIN r0_rd_out[403]
    DIRECTION OUTPUT ;
    USE SIGNAL ;
    SHAPE ABUTMENT ;
    PORT
      LAYER M3 ;
      RECT 696.591 566.730 696.609 566.784 ;
    END
  END r0_rd_out[403]
  PIN r0_rd_out[404]
    DIRECTION OUTPUT ;
    USE SIGNAL ;
    SHAPE ABUTMENT ;
    PORT
      LAYER M3 ;
      RECT 698.319 566.730 698.337 566.784 ;
    END
  END r0_rd_out[404]
  PIN r0_rd_out[405]
    DIRECTION OUTPUT ;
    USE SIGNAL ;
    SHAPE ABUTMENT ;
    PORT
      LAYER M3 ;
      RECT 700.047 566.730 700.065 566.784 ;
    END
  END r0_rd_out[405]
  PIN r0_rd_out[406]
    DIRECTION OUTPUT ;
    USE SIGNAL ;
    SHAPE ABUTMENT ;
    PORT
      LAYER M3 ;
      RECT 701.775 566.730 701.793 566.784 ;
    END
  END r0_rd_out[406]
  PIN r0_rd_out[407]
    DIRECTION OUTPUT ;
    USE SIGNAL ;
    SHAPE ABUTMENT ;
    PORT
      LAYER M3 ;
      RECT 703.503 566.730 703.521 566.784 ;
    END
  END r0_rd_out[407]
  PIN r0_rd_out[408]
    DIRECTION OUTPUT ;
    USE SIGNAL ;
    SHAPE ABUTMENT ;
    PORT
      LAYER M3 ;
      RECT 705.231 566.730 705.249 566.784 ;
    END
  END r0_rd_out[408]
  PIN r0_rd_out[409]
    DIRECTION OUTPUT ;
    USE SIGNAL ;
    SHAPE ABUTMENT ;
    PORT
      LAYER M3 ;
      RECT 706.959 566.730 706.977 566.784 ;
    END
  END r0_rd_out[409]
  PIN r0_rd_out[410]
    DIRECTION OUTPUT ;
    USE SIGNAL ;
    SHAPE ABUTMENT ;
    PORT
      LAYER M3 ;
      RECT 708.687 566.730 708.705 566.784 ;
    END
  END r0_rd_out[410]
  PIN r0_rd_out[411]
    DIRECTION OUTPUT ;
    USE SIGNAL ;
    SHAPE ABUTMENT ;
    PORT
      LAYER M3 ;
      RECT 710.415 566.730 710.433 566.784 ;
    END
  END r0_rd_out[411]
  PIN r0_rd_out[412]
    DIRECTION OUTPUT ;
    USE SIGNAL ;
    SHAPE ABUTMENT ;
    PORT
      LAYER M3 ;
      RECT 712.143 566.730 712.161 566.784 ;
    END
  END r0_rd_out[412]
  PIN r0_rd_out[413]
    DIRECTION OUTPUT ;
    USE SIGNAL ;
    SHAPE ABUTMENT ;
    PORT
      LAYER M3 ;
      RECT 713.871 566.730 713.889 566.784 ;
    END
  END r0_rd_out[413]
  PIN r0_rd_out[414]
    DIRECTION OUTPUT ;
    USE SIGNAL ;
    SHAPE ABUTMENT ;
    PORT
      LAYER M3 ;
      RECT 715.599 566.730 715.617 566.784 ;
    END
  END r0_rd_out[414]
  PIN r0_rd_out[415]
    DIRECTION OUTPUT ;
    USE SIGNAL ;
    SHAPE ABUTMENT ;
    PORT
      LAYER M3 ;
      RECT 717.327 566.730 717.345 566.784 ;
    END
  END r0_rd_out[415]
  PIN r0_rd_out[416]
    DIRECTION OUTPUT ;
    USE SIGNAL ;
    SHAPE ABUTMENT ;
    PORT
      LAYER M3 ;
      RECT 719.055 566.730 719.073 566.784 ;
    END
  END r0_rd_out[416]
  PIN r0_rd_out[417]
    DIRECTION OUTPUT ;
    USE SIGNAL ;
    SHAPE ABUTMENT ;
    PORT
      LAYER M3 ;
      RECT 720.783 566.730 720.801 566.784 ;
    END
  END r0_rd_out[417]
  PIN r0_rd_out[418]
    DIRECTION OUTPUT ;
    USE SIGNAL ;
    SHAPE ABUTMENT ;
    PORT
      LAYER M3 ;
      RECT 722.511 566.730 722.529 566.784 ;
    END
  END r0_rd_out[418]
  PIN r0_rd_out[419]
    DIRECTION OUTPUT ;
    USE SIGNAL ;
    SHAPE ABUTMENT ;
    PORT
      LAYER M3 ;
      RECT 724.239 566.730 724.257 566.784 ;
    END
  END r0_rd_out[419]
  PIN r0_rd_out[420]
    DIRECTION OUTPUT ;
    USE SIGNAL ;
    SHAPE ABUTMENT ;
    PORT
      LAYER M3 ;
      RECT 725.967 566.730 725.985 566.784 ;
    END
  END r0_rd_out[420]
  PIN r0_rd_out[421]
    DIRECTION OUTPUT ;
    USE SIGNAL ;
    SHAPE ABUTMENT ;
    PORT
      LAYER M3 ;
      RECT 727.695 566.730 727.713 566.784 ;
    END
  END r0_rd_out[421]
  PIN r0_rd_out[422]
    DIRECTION OUTPUT ;
    USE SIGNAL ;
    SHAPE ABUTMENT ;
    PORT
      LAYER M3 ;
      RECT 729.423 566.730 729.441 566.784 ;
    END
  END r0_rd_out[422]
  PIN r0_rd_out[423]
    DIRECTION OUTPUT ;
    USE SIGNAL ;
    SHAPE ABUTMENT ;
    PORT
      LAYER M3 ;
      RECT 731.151 566.730 731.169 566.784 ;
    END
  END r0_rd_out[423]
  PIN r0_rd_out[424]
    DIRECTION OUTPUT ;
    USE SIGNAL ;
    SHAPE ABUTMENT ;
    PORT
      LAYER M3 ;
      RECT 732.879 566.730 732.897 566.784 ;
    END
  END r0_rd_out[424]
  PIN r0_rd_out[425]
    DIRECTION OUTPUT ;
    USE SIGNAL ;
    SHAPE ABUTMENT ;
    PORT
      LAYER M3 ;
      RECT 734.607 566.730 734.625 566.784 ;
    END
  END r0_rd_out[425]
  PIN r0_rd_out[426]
    DIRECTION OUTPUT ;
    USE SIGNAL ;
    SHAPE ABUTMENT ;
    PORT
      LAYER M3 ;
      RECT 736.335 566.730 736.353 566.784 ;
    END
  END r0_rd_out[426]
  PIN r0_rd_out[427]
    DIRECTION OUTPUT ;
    USE SIGNAL ;
    SHAPE ABUTMENT ;
    PORT
      LAYER M3 ;
      RECT 738.063 566.730 738.081 566.784 ;
    END
  END r0_rd_out[427]
  PIN r0_rd_out[428]
    DIRECTION OUTPUT ;
    USE SIGNAL ;
    SHAPE ABUTMENT ;
    PORT
      LAYER M3 ;
      RECT 739.791 566.730 739.809 566.784 ;
    END
  END r0_rd_out[428]
  PIN r0_rd_out[429]
    DIRECTION OUTPUT ;
    USE SIGNAL ;
    SHAPE ABUTMENT ;
    PORT
      LAYER M3 ;
      RECT 741.519 566.730 741.537 566.784 ;
    END
  END r0_rd_out[429]
  PIN r0_rd_out[430]
    DIRECTION OUTPUT ;
    USE SIGNAL ;
    SHAPE ABUTMENT ;
    PORT
      LAYER M3 ;
      RECT 743.247 566.730 743.265 566.784 ;
    END
  END r0_rd_out[430]
  PIN r0_rd_out[431]
    DIRECTION OUTPUT ;
    USE SIGNAL ;
    SHAPE ABUTMENT ;
    PORT
      LAYER M3 ;
      RECT 744.975 566.730 744.993 566.784 ;
    END
  END r0_rd_out[431]
  PIN r0_rd_out[432]
    DIRECTION OUTPUT ;
    USE SIGNAL ;
    SHAPE ABUTMENT ;
    PORT
      LAYER M3 ;
      RECT 746.703 566.730 746.721 566.784 ;
    END
  END r0_rd_out[432]
  PIN r0_rd_out[433]
    DIRECTION OUTPUT ;
    USE SIGNAL ;
    SHAPE ABUTMENT ;
    PORT
      LAYER M3 ;
      RECT 748.431 566.730 748.449 566.784 ;
    END
  END r0_rd_out[433]
  PIN r0_rd_out[434]
    DIRECTION OUTPUT ;
    USE SIGNAL ;
    SHAPE ABUTMENT ;
    PORT
      LAYER M3 ;
      RECT 750.159 566.730 750.177 566.784 ;
    END
  END r0_rd_out[434]
  PIN r0_rd_out[435]
    DIRECTION OUTPUT ;
    USE SIGNAL ;
    SHAPE ABUTMENT ;
    PORT
      LAYER M3 ;
      RECT 751.887 566.730 751.905 566.784 ;
    END
  END r0_rd_out[435]
  PIN r0_rd_out[436]
    DIRECTION OUTPUT ;
    USE SIGNAL ;
    SHAPE ABUTMENT ;
    PORT
      LAYER M3 ;
      RECT 753.615 566.730 753.633 566.784 ;
    END
  END r0_rd_out[436]
  PIN r0_rd_out[437]
    DIRECTION OUTPUT ;
    USE SIGNAL ;
    SHAPE ABUTMENT ;
    PORT
      LAYER M3 ;
      RECT 755.343 566.730 755.361 566.784 ;
    END
  END r0_rd_out[437]
  PIN r0_rd_out[438]
    DIRECTION OUTPUT ;
    USE SIGNAL ;
    SHAPE ABUTMENT ;
    PORT
      LAYER M3 ;
      RECT 757.071 566.730 757.089 566.784 ;
    END
  END r0_rd_out[438]
  PIN r0_rd_out[439]
    DIRECTION OUTPUT ;
    USE SIGNAL ;
    SHAPE ABUTMENT ;
    PORT
      LAYER M3 ;
      RECT 758.799 566.730 758.817 566.784 ;
    END
  END r0_rd_out[439]
  PIN r0_rd_out[440]
    DIRECTION OUTPUT ;
    USE SIGNAL ;
    SHAPE ABUTMENT ;
    PORT
      LAYER M3 ;
      RECT 760.527 566.730 760.545 566.784 ;
    END
  END r0_rd_out[440]
  PIN r0_rd_out[441]
    DIRECTION OUTPUT ;
    USE SIGNAL ;
    SHAPE ABUTMENT ;
    PORT
      LAYER M3 ;
      RECT 762.255 566.730 762.273 566.784 ;
    END
  END r0_rd_out[441]
  PIN r0_rd_out[442]
    DIRECTION OUTPUT ;
    USE SIGNAL ;
    SHAPE ABUTMENT ;
    PORT
      LAYER M3 ;
      RECT 763.983 566.730 764.001 566.784 ;
    END
  END r0_rd_out[442]
  PIN r0_rd_out[443]
    DIRECTION OUTPUT ;
    USE SIGNAL ;
    SHAPE ABUTMENT ;
    PORT
      LAYER M3 ;
      RECT 765.711 566.730 765.729 566.784 ;
    END
  END r0_rd_out[443]
  PIN r0_rd_out[444]
    DIRECTION OUTPUT ;
    USE SIGNAL ;
    SHAPE ABUTMENT ;
    PORT
      LAYER M3 ;
      RECT 767.439 566.730 767.457 566.784 ;
    END
  END r0_rd_out[444]
  PIN r0_rd_out[445]
    DIRECTION OUTPUT ;
    USE SIGNAL ;
    SHAPE ABUTMENT ;
    PORT
      LAYER M3 ;
      RECT 769.167 566.730 769.185 566.784 ;
    END
  END r0_rd_out[445]
  PIN r0_rd_out[446]
    DIRECTION OUTPUT ;
    USE SIGNAL ;
    SHAPE ABUTMENT ;
    PORT
      LAYER M3 ;
      RECT 770.895 566.730 770.913 566.784 ;
    END
  END r0_rd_out[446]
  PIN r0_rd_out[447]
    DIRECTION OUTPUT ;
    USE SIGNAL ;
    SHAPE ABUTMENT ;
    PORT
      LAYER M3 ;
      RECT 772.623 566.730 772.641 566.784 ;
    END
  END r0_rd_out[447]
  PIN r0_rd_out[448]
    DIRECTION OUTPUT ;
    USE SIGNAL ;
    SHAPE ABUTMENT ;
    PORT
      LAYER M3 ;
      RECT 774.351 566.730 774.369 566.784 ;
    END
  END r0_rd_out[448]
  PIN r0_rd_out[449]
    DIRECTION OUTPUT ;
    USE SIGNAL ;
    SHAPE ABUTMENT ;
    PORT
      LAYER M3 ;
      RECT 776.079 566.730 776.097 566.784 ;
    END
  END r0_rd_out[449]
  PIN r0_rd_out[450]
    DIRECTION OUTPUT ;
    USE SIGNAL ;
    SHAPE ABUTMENT ;
    PORT
      LAYER M3 ;
      RECT 777.807 566.730 777.825 566.784 ;
    END
  END r0_rd_out[450]
  PIN r0_rd_out[451]
    DIRECTION OUTPUT ;
    USE SIGNAL ;
    SHAPE ABUTMENT ;
    PORT
      LAYER M3 ;
      RECT 779.535 566.730 779.553 566.784 ;
    END
  END r0_rd_out[451]
  PIN r0_rd_out[452]
    DIRECTION OUTPUT ;
    USE SIGNAL ;
    SHAPE ABUTMENT ;
    PORT
      LAYER M3 ;
      RECT 781.263 566.730 781.281 566.784 ;
    END
  END r0_rd_out[452]
  PIN r0_rd_out[453]
    DIRECTION OUTPUT ;
    USE SIGNAL ;
    SHAPE ABUTMENT ;
    PORT
      LAYER M3 ;
      RECT 782.991 566.730 783.009 566.784 ;
    END
  END r0_rd_out[453]
  PIN r0_rd_out[454]
    DIRECTION OUTPUT ;
    USE SIGNAL ;
    SHAPE ABUTMENT ;
    PORT
      LAYER M3 ;
      RECT 784.719 566.730 784.737 566.784 ;
    END
  END r0_rd_out[454]
  PIN r0_rd_out[455]
    DIRECTION OUTPUT ;
    USE SIGNAL ;
    SHAPE ABUTMENT ;
    PORT
      LAYER M3 ;
      RECT 786.447 566.730 786.465 566.784 ;
    END
  END r0_rd_out[455]
  PIN r0_rd_out[456]
    DIRECTION OUTPUT ;
    USE SIGNAL ;
    SHAPE ABUTMENT ;
    PORT
      LAYER M3 ;
      RECT 788.175 566.730 788.193 566.784 ;
    END
  END r0_rd_out[456]
  PIN r0_rd_out[457]
    DIRECTION OUTPUT ;
    USE SIGNAL ;
    SHAPE ABUTMENT ;
    PORT
      LAYER M3 ;
      RECT 789.903 566.730 789.921 566.784 ;
    END
  END r0_rd_out[457]
  PIN r0_rd_out[458]
    DIRECTION OUTPUT ;
    USE SIGNAL ;
    SHAPE ABUTMENT ;
    PORT
      LAYER M3 ;
      RECT 791.631 566.730 791.649 566.784 ;
    END
  END r0_rd_out[458]
  PIN r0_rd_out[459]
    DIRECTION OUTPUT ;
    USE SIGNAL ;
    SHAPE ABUTMENT ;
    PORT
      LAYER M3 ;
      RECT 793.359 566.730 793.377 566.784 ;
    END
  END r0_rd_out[459]
  PIN r0_rd_out[460]
    DIRECTION OUTPUT ;
    USE SIGNAL ;
    SHAPE ABUTMENT ;
    PORT
      LAYER M3 ;
      RECT 795.087 566.730 795.105 566.784 ;
    END
  END r0_rd_out[460]
  PIN r0_rd_out[461]
    DIRECTION OUTPUT ;
    USE SIGNAL ;
    SHAPE ABUTMENT ;
    PORT
      LAYER M3 ;
      RECT 796.815 566.730 796.833 566.784 ;
    END
  END r0_rd_out[461]
  PIN r0_rd_out[462]
    DIRECTION OUTPUT ;
    USE SIGNAL ;
    SHAPE ABUTMENT ;
    PORT
      LAYER M3 ;
      RECT 798.543 566.730 798.561 566.784 ;
    END
  END r0_rd_out[462]
  PIN r0_rd_out[463]
    DIRECTION OUTPUT ;
    USE SIGNAL ;
    SHAPE ABUTMENT ;
    PORT
      LAYER M3 ;
      RECT 800.271 566.730 800.289 566.784 ;
    END
  END r0_rd_out[463]
  PIN r0_rd_out[464]
    DIRECTION OUTPUT ;
    USE SIGNAL ;
    SHAPE ABUTMENT ;
    PORT
      LAYER M3 ;
      RECT 801.999 566.730 802.017 566.784 ;
    END
  END r0_rd_out[464]
  PIN r0_rd_out[465]
    DIRECTION OUTPUT ;
    USE SIGNAL ;
    SHAPE ABUTMENT ;
    PORT
      LAYER M3 ;
      RECT 803.727 566.730 803.745 566.784 ;
    END
  END r0_rd_out[465]
  PIN r0_rd_out[466]
    DIRECTION OUTPUT ;
    USE SIGNAL ;
    SHAPE ABUTMENT ;
    PORT
      LAYER M3 ;
      RECT 805.455 566.730 805.473 566.784 ;
    END
  END r0_rd_out[466]
  PIN r0_rd_out[467]
    DIRECTION OUTPUT ;
    USE SIGNAL ;
    SHAPE ABUTMENT ;
    PORT
      LAYER M3 ;
      RECT 807.183 566.730 807.201 566.784 ;
    END
  END r0_rd_out[467]
  PIN r0_rd_out[468]
    DIRECTION OUTPUT ;
    USE SIGNAL ;
    SHAPE ABUTMENT ;
    PORT
      LAYER M3 ;
      RECT 808.911 566.730 808.929 566.784 ;
    END
  END r0_rd_out[468]
  PIN r0_rd_out[469]
    DIRECTION OUTPUT ;
    USE SIGNAL ;
    SHAPE ABUTMENT ;
    PORT
      LAYER M3 ;
      RECT 810.639 566.730 810.657 566.784 ;
    END
  END r0_rd_out[469]
  PIN r0_rd_out[470]
    DIRECTION OUTPUT ;
    USE SIGNAL ;
    SHAPE ABUTMENT ;
    PORT
      LAYER M3 ;
      RECT 812.367 566.730 812.385 566.784 ;
    END
  END r0_rd_out[470]
  PIN r0_rd_out[471]
    DIRECTION OUTPUT ;
    USE SIGNAL ;
    SHAPE ABUTMENT ;
    PORT
      LAYER M3 ;
      RECT 814.095 566.730 814.113 566.784 ;
    END
  END r0_rd_out[471]
  PIN r0_rd_out[472]
    DIRECTION OUTPUT ;
    USE SIGNAL ;
    SHAPE ABUTMENT ;
    PORT
      LAYER M3 ;
      RECT 815.823 566.730 815.841 566.784 ;
    END
  END r0_rd_out[472]
  PIN r0_rd_out[473]
    DIRECTION OUTPUT ;
    USE SIGNAL ;
    SHAPE ABUTMENT ;
    PORT
      LAYER M3 ;
      RECT 817.551 566.730 817.569 566.784 ;
    END
  END r0_rd_out[473]
  PIN r0_rd_out[474]
    DIRECTION OUTPUT ;
    USE SIGNAL ;
    SHAPE ABUTMENT ;
    PORT
      LAYER M3 ;
      RECT 819.279 566.730 819.297 566.784 ;
    END
  END r0_rd_out[474]
  PIN r0_rd_out[475]
    DIRECTION OUTPUT ;
    USE SIGNAL ;
    SHAPE ABUTMENT ;
    PORT
      LAYER M3 ;
      RECT 821.007 566.730 821.025 566.784 ;
    END
  END r0_rd_out[475]
  PIN r0_rd_out[476]
    DIRECTION OUTPUT ;
    USE SIGNAL ;
    SHAPE ABUTMENT ;
    PORT
      LAYER M3 ;
      RECT 822.735 566.730 822.753 566.784 ;
    END
  END r0_rd_out[476]
  PIN r0_rd_out[477]
    DIRECTION OUTPUT ;
    USE SIGNAL ;
    SHAPE ABUTMENT ;
    PORT
      LAYER M3 ;
      RECT 824.463 566.730 824.481 566.784 ;
    END
  END r0_rd_out[477]
  PIN r0_rd_out[478]
    DIRECTION OUTPUT ;
    USE SIGNAL ;
    SHAPE ABUTMENT ;
    PORT
      LAYER M3 ;
      RECT 826.191 566.730 826.209 566.784 ;
    END
  END r0_rd_out[478]
  PIN r0_rd_out[479]
    DIRECTION OUTPUT ;
    USE SIGNAL ;
    SHAPE ABUTMENT ;
    PORT
      LAYER M3 ;
      RECT 827.919 566.730 827.937 566.784 ;
    END
  END r0_rd_out[479]
  PIN r0_rd_out[480]
    DIRECTION OUTPUT ;
    USE SIGNAL ;
    SHAPE ABUTMENT ;
    PORT
      LAYER M3 ;
      RECT 829.647 566.730 829.665 566.784 ;
    END
  END r0_rd_out[480]
  PIN r0_rd_out[481]
    DIRECTION OUTPUT ;
    USE SIGNAL ;
    SHAPE ABUTMENT ;
    PORT
      LAYER M3 ;
      RECT 831.375 566.730 831.393 566.784 ;
    END
  END r0_rd_out[481]
  PIN r0_rd_out[482]
    DIRECTION OUTPUT ;
    USE SIGNAL ;
    SHAPE ABUTMENT ;
    PORT
      LAYER M3 ;
      RECT 833.103 566.730 833.121 566.784 ;
    END
  END r0_rd_out[482]
  PIN r0_rd_out[483]
    DIRECTION OUTPUT ;
    USE SIGNAL ;
    SHAPE ABUTMENT ;
    PORT
      LAYER M3 ;
      RECT 834.831 566.730 834.849 566.784 ;
    END
  END r0_rd_out[483]
  PIN r0_rd_out[484]
    DIRECTION OUTPUT ;
    USE SIGNAL ;
    SHAPE ABUTMENT ;
    PORT
      LAYER M3 ;
      RECT 836.559 566.730 836.577 566.784 ;
    END
  END r0_rd_out[484]
  PIN r0_rd_out[485]
    DIRECTION OUTPUT ;
    USE SIGNAL ;
    SHAPE ABUTMENT ;
    PORT
      LAYER M3 ;
      RECT 838.287 566.730 838.305 566.784 ;
    END
  END r0_rd_out[485]
  PIN r0_rd_out[486]
    DIRECTION OUTPUT ;
    USE SIGNAL ;
    SHAPE ABUTMENT ;
    PORT
      LAYER M3 ;
      RECT 840.015 566.730 840.033 566.784 ;
    END
  END r0_rd_out[486]
  PIN r0_rd_out[487]
    DIRECTION OUTPUT ;
    USE SIGNAL ;
    SHAPE ABUTMENT ;
    PORT
      LAYER M3 ;
      RECT 841.743 566.730 841.761 566.784 ;
    END
  END r0_rd_out[487]
  PIN r0_rd_out[488]
    DIRECTION OUTPUT ;
    USE SIGNAL ;
    SHAPE ABUTMENT ;
    PORT
      LAYER M3 ;
      RECT 843.471 566.730 843.489 566.784 ;
    END
  END r0_rd_out[488]
  PIN r0_rd_out[489]
    DIRECTION OUTPUT ;
    USE SIGNAL ;
    SHAPE ABUTMENT ;
    PORT
      LAYER M3 ;
      RECT 845.199 566.730 845.217 566.784 ;
    END
  END r0_rd_out[489]
  PIN r0_rd_out[490]
    DIRECTION OUTPUT ;
    USE SIGNAL ;
    SHAPE ABUTMENT ;
    PORT
      LAYER M3 ;
      RECT 846.927 566.730 846.945 566.784 ;
    END
  END r0_rd_out[490]
  PIN r0_rd_out[491]
    DIRECTION OUTPUT ;
    USE SIGNAL ;
    SHAPE ABUTMENT ;
    PORT
      LAYER M3 ;
      RECT 848.655 566.730 848.673 566.784 ;
    END
  END r0_rd_out[491]
  PIN r0_rd_out[492]
    DIRECTION OUTPUT ;
    USE SIGNAL ;
    SHAPE ABUTMENT ;
    PORT
      LAYER M3 ;
      RECT 850.383 566.730 850.401 566.784 ;
    END
  END r0_rd_out[492]
  PIN r0_rd_out[493]
    DIRECTION OUTPUT ;
    USE SIGNAL ;
    SHAPE ABUTMENT ;
    PORT
      LAYER M3 ;
      RECT 852.111 566.730 852.129 566.784 ;
    END
  END r0_rd_out[493]
  PIN r0_rd_out[494]
    DIRECTION OUTPUT ;
    USE SIGNAL ;
    SHAPE ABUTMENT ;
    PORT
      LAYER M3 ;
      RECT 853.839 566.730 853.857 566.784 ;
    END
  END r0_rd_out[494]
  PIN r0_rd_out[495]
    DIRECTION OUTPUT ;
    USE SIGNAL ;
    SHAPE ABUTMENT ;
    PORT
      LAYER M3 ;
      RECT 855.567 566.730 855.585 566.784 ;
    END
  END r0_rd_out[495]
  PIN r0_rd_out[496]
    DIRECTION OUTPUT ;
    USE SIGNAL ;
    SHAPE ABUTMENT ;
    PORT
      LAYER M3 ;
      RECT 857.295 566.730 857.313 566.784 ;
    END
  END r0_rd_out[496]
  PIN r0_rd_out[497]
    DIRECTION OUTPUT ;
    USE SIGNAL ;
    SHAPE ABUTMENT ;
    PORT
      LAYER M3 ;
      RECT 859.023 566.730 859.041 566.784 ;
    END
  END r0_rd_out[497]
  PIN r0_rd_out[498]
    DIRECTION OUTPUT ;
    USE SIGNAL ;
    SHAPE ABUTMENT ;
    PORT
      LAYER M3 ;
      RECT 860.751 566.730 860.769 566.784 ;
    END
  END r0_rd_out[498]
  PIN r0_rd_out[499]
    DIRECTION OUTPUT ;
    USE SIGNAL ;
    SHAPE ABUTMENT ;
    PORT
      LAYER M3 ;
      RECT 862.479 566.730 862.497 566.784 ;
    END
  END r0_rd_out[499]
  PIN r0_rd_out[500]
    DIRECTION OUTPUT ;
    USE SIGNAL ;
    SHAPE ABUTMENT ;
    PORT
      LAYER M3 ;
      RECT 864.207 566.730 864.225 566.784 ;
    END
  END r0_rd_out[500]
  PIN r0_rd_out[501]
    DIRECTION OUTPUT ;
    USE SIGNAL ;
    SHAPE ABUTMENT ;
    PORT
      LAYER M3 ;
      RECT 865.935 566.730 865.953 566.784 ;
    END
  END r0_rd_out[501]
  PIN r0_rd_out[502]
    DIRECTION OUTPUT ;
    USE SIGNAL ;
    SHAPE ABUTMENT ;
    PORT
      LAYER M3 ;
      RECT 867.663 566.730 867.681 566.784 ;
    END
  END r0_rd_out[502]
  PIN r0_rd_out[503]
    DIRECTION OUTPUT ;
    USE SIGNAL ;
    SHAPE ABUTMENT ;
    PORT
      LAYER M3 ;
      RECT 869.391 566.730 869.409 566.784 ;
    END
  END r0_rd_out[503]
  PIN r0_rd_out[504]
    DIRECTION OUTPUT ;
    USE SIGNAL ;
    SHAPE ABUTMENT ;
    PORT
      LAYER M3 ;
      RECT 871.119 566.730 871.137 566.784 ;
    END
  END r0_rd_out[504]
  PIN r0_rd_out[505]
    DIRECTION OUTPUT ;
    USE SIGNAL ;
    SHAPE ABUTMENT ;
    PORT
      LAYER M3 ;
      RECT 872.847 566.730 872.865 566.784 ;
    END
  END r0_rd_out[505]
  PIN r0_rd_out[506]
    DIRECTION OUTPUT ;
    USE SIGNAL ;
    SHAPE ABUTMENT ;
    PORT
      LAYER M3 ;
      RECT 874.575 566.730 874.593 566.784 ;
    END
  END r0_rd_out[506]
  PIN r0_rd_out[507]
    DIRECTION OUTPUT ;
    USE SIGNAL ;
    SHAPE ABUTMENT ;
    PORT
      LAYER M3 ;
      RECT 876.303 566.730 876.321 566.784 ;
    END
  END r0_rd_out[507]
  PIN r0_rd_out[508]
    DIRECTION OUTPUT ;
    USE SIGNAL ;
    SHAPE ABUTMENT ;
    PORT
      LAYER M3 ;
      RECT 878.031 566.730 878.049 566.784 ;
    END
  END r0_rd_out[508]
  PIN r0_rd_out[509]
    DIRECTION OUTPUT ;
    USE SIGNAL ;
    SHAPE ABUTMENT ;
    PORT
      LAYER M3 ;
      RECT 879.759 566.730 879.777 566.784 ;
    END
  END r0_rd_out[509]
  PIN r0_rd_out[510]
    DIRECTION OUTPUT ;
    USE SIGNAL ;
    SHAPE ABUTMENT ;
    PORT
      LAYER M3 ;
      RECT 881.487 566.730 881.505 566.784 ;
    END
  END r0_rd_out[510]
  PIN r0_rd_out[511]
    DIRECTION OUTPUT ;
    USE SIGNAL ;
    SHAPE ABUTMENT ;
    PORT
      LAYER M3 ;
      RECT 883.215 566.730 883.233 566.784 ;
    END
  END r0_rd_out[511]
  PIN w0_addr_in[0]
    DIRECTION INPUT ;
    USE SIGNAL ;
    SHAPE ABUTMENT ;
    PORT
      LAYER M4 ;
      RECT 0.000 540.948 0.072 540.972 ;
    END
  END w0_addr_in[0]
  PIN w0_addr_in[1]
    DIRECTION INPUT ;
    USE SIGNAL ;
    SHAPE ABUTMENT ;
    PORT
      LAYER M4 ;
      RECT 0.000 543.060 0.072 543.084 ;
    END
  END w0_addr_in[1]
  PIN w0_addr_in[2]
    DIRECTION INPUT ;
    USE SIGNAL ;
    SHAPE ABUTMENT ;
    PORT
      LAYER M4 ;
      RECT 0.000 545.172 0.072 545.196 ;
    END
  END w0_addr_in[2]
  PIN w0_addr_in[3]
    DIRECTION INPUT ;
    USE SIGNAL ;
    SHAPE ABUTMENT ;
    PORT
      LAYER M4 ;
      RECT 0.000 547.284 0.072 547.308 ;
    END
  END w0_addr_in[3]
  PIN w0_addr_in[4]
    DIRECTION INPUT ;
    USE SIGNAL ;
    SHAPE ABUTMENT ;
    PORT
      LAYER M4 ;
      RECT 0.000 549.396 0.072 549.420 ;
    END
  END w0_addr_in[4]
  PIN w0_addr_in[5]
    DIRECTION INPUT ;
    USE SIGNAL ;
    SHAPE ABUTMENT ;
    PORT
      LAYER M4 ;
      RECT 0.000 551.508 0.072 551.532 ;
    END
  END w0_addr_in[5]
  PIN w0_addr_in[6]
    DIRECTION INPUT ;
    USE SIGNAL ;
    SHAPE ABUTMENT ;
    PORT
      LAYER M4 ;
      RECT 906.783 540.948 906.855 540.972 ;
    END
  END w0_addr_in[6]
  PIN w0_addr_in[7]
    DIRECTION INPUT ;
    USE SIGNAL ;
    SHAPE ABUTMENT ;
    PORT
      LAYER M4 ;
      RECT 906.783 543.060 906.855 543.084 ;
    END
  END w0_addr_in[7]
  PIN w0_addr_in[8]
    DIRECTION INPUT ;
    USE SIGNAL ;
    SHAPE ABUTMENT ;
    PORT
      LAYER M4 ;
      RECT 906.783 545.172 906.855 545.196 ;
    END
  END w0_addr_in[8]
  PIN w0_addr_in[9]
    DIRECTION INPUT ;
    USE SIGNAL ;
    SHAPE ABUTMENT ;
    PORT
      LAYER M4 ;
      RECT 906.783 547.284 906.855 547.308 ;
    END
  END w0_addr_in[9]
  PIN w0_addr_in[10]
    DIRECTION INPUT ;
    USE SIGNAL ;
    SHAPE ABUTMENT ;
    PORT
      LAYER M4 ;
      RECT 906.783 549.396 906.855 549.420 ;
    END
  END w0_addr_in[10]
  PIN r0_addr_in[0]
    DIRECTION INPUT ;
    USE SIGNAL ;
    SHAPE ABUTMENT ;
    PORT
      LAYER M4 ;
      RECT 0.000 553.620 0.072 553.644 ;
    END
  END r0_addr_in[0]
  PIN r0_addr_in[1]
    DIRECTION INPUT ;
    USE SIGNAL ;
    SHAPE ABUTMENT ;
    PORT
      LAYER M4 ;
      RECT 0.000 555.732 0.072 555.756 ;
    END
  END r0_addr_in[1]
  PIN r0_addr_in[2]
    DIRECTION INPUT ;
    USE SIGNAL ;
    SHAPE ABUTMENT ;
    PORT
      LAYER M4 ;
      RECT 0.000 557.844 0.072 557.868 ;
    END
  END r0_addr_in[2]
  PIN r0_addr_in[3]
    DIRECTION INPUT ;
    USE SIGNAL ;
    SHAPE ABUTMENT ;
    PORT
      LAYER M4 ;
      RECT 0.000 559.956 0.072 559.980 ;
    END
  END r0_addr_in[3]
  PIN r0_addr_in[4]
    DIRECTION INPUT ;
    USE SIGNAL ;
    SHAPE ABUTMENT ;
    PORT
      LAYER M4 ;
      RECT 0.000 562.068 0.072 562.092 ;
    END
  END r0_addr_in[4]
  PIN r0_addr_in[5]
    DIRECTION INPUT ;
    USE SIGNAL ;
    SHAPE ABUTMENT ;
    PORT
      LAYER M4 ;
      RECT 0.000 564.180 0.072 564.204 ;
    END
  END r0_addr_in[5]
  PIN r0_addr_in[6]
    DIRECTION INPUT ;
    USE SIGNAL ;
    SHAPE ABUTMENT ;
    PORT
      LAYER M4 ;
      RECT 906.783 551.508 906.855 551.532 ;
    END
  END r0_addr_in[6]
  PIN r0_addr_in[7]
    DIRECTION INPUT ;
    USE SIGNAL ;
    SHAPE ABUTMENT ;
    PORT
      LAYER M4 ;
      RECT 906.783 553.620 906.855 553.644 ;
    END
  END r0_addr_in[7]
  PIN r0_addr_in[8]
    DIRECTION INPUT ;
    USE SIGNAL ;
    SHAPE ABUTMENT ;
    PORT
      LAYER M4 ;
      RECT 906.783 555.732 906.855 555.756 ;
    END
  END r0_addr_in[8]
  PIN r0_addr_in[9]
    DIRECTION INPUT ;
    USE SIGNAL ;
    SHAPE ABUTMENT ;
    PORT
      LAYER M4 ;
      RECT 906.783 557.844 906.855 557.868 ;
    END
  END r0_addr_in[9]
  PIN r0_addr_in[10]
    DIRECTION INPUT ;
    USE SIGNAL ;
    SHAPE ABUTMENT ;
    PORT
      LAYER M4 ;
      RECT 906.783 559.956 906.855 559.980 ;
    END
  END r0_addr_in[10]
  PIN w0_we_in
    DIRECTION INPUT ;
    USE SIGNAL ;
    SHAPE ABUTMENT ;
    PORT
      LAYER M3 ;
      RECT 884.943 566.730 884.961 566.784 ;
    END
  END w0_we_in
  PIN w0_ce_in
    DIRECTION INPUT ;
    USE SIGNAL ;
    SHAPE ABUTMENT ;
    PORT
      LAYER M3 ;
      RECT 886.671 566.730 886.689 566.784 ;
    END
  END w0_ce_in
  PIN w0_clk
    DIRECTION INPUT ;
    USE SIGNAL ;
    SHAPE ABUTMENT ;
    PORT
      LAYER M3 ;
      RECT 888.399 566.730 888.417 566.784 ;
    END
  END w0_clk
  PIN r0_ce_in
    DIRECTION INPUT ;
    USE SIGNAL ;
    SHAPE ABUTMENT ;
    PORT
      LAYER M3 ;
      RECT 890.127 566.730 890.145 566.784 ;
    END
  END r0_ce_in
  PIN r0_clk
    DIRECTION INPUT ;
    USE SIGNAL ;
    SHAPE ABUTMENT ;
    PORT
      LAYER M3 ;
      RECT 891.855 566.730 891.873 566.784 ;
    END
  END r0_clk
  PIN VSS
    DIRECTION INOUT ;
    USE GROUND ;
    PORT
      LAYER M4 ;
      RECT 0.216 0.240 906.639 0.336 ;
      RECT 0.216 1.008 906.639 1.104 ;
      RECT 0.216 1.776 906.639 1.872 ;
      RECT 0.216 2.544 906.639 2.640 ;
      RECT 0.216 3.312 906.639 3.408 ;
      RECT 0.216 4.080 906.639 4.176 ;
      RECT 0.216 4.848 906.639 4.944 ;
      RECT 0.216 5.616 906.639 5.712 ;
      RECT 0.216 6.384 906.639 6.480 ;
      RECT 0.216 7.152 906.639 7.248 ;
      RECT 0.216 7.920 906.639 8.016 ;
      RECT 0.216 8.688 906.639 8.784 ;
      RECT 0.216 9.456 906.639 9.552 ;
      RECT 0.216 10.224 906.639 10.320 ;
      RECT 0.216 10.992 906.639 11.088 ;
      RECT 0.216 11.760 906.639 11.856 ;
      RECT 0.216 12.528 906.639 12.624 ;
      RECT 0.216 13.296 906.639 13.392 ;
      RECT 0.216 14.064 906.639 14.160 ;
      RECT 0.216 14.832 906.639 14.928 ;
      RECT 0.216 15.600 906.639 15.696 ;
      RECT 0.216 16.368 906.639 16.464 ;
      RECT 0.216 17.136 906.639 17.232 ;
      RECT 0.216 17.904 906.639 18.000 ;
      RECT 0.216 18.672 906.639 18.768 ;
      RECT 0.216 19.440 906.639 19.536 ;
      RECT 0.216 20.208 906.639 20.304 ;
      RECT 0.216 20.976 906.639 21.072 ;
      RECT 0.216 21.744 906.639 21.840 ;
      RECT 0.216 22.512 906.639 22.608 ;
      RECT 0.216 23.280 906.639 23.376 ;
      RECT 0.216 24.048 906.639 24.144 ;
      RECT 0.216 24.816 906.639 24.912 ;
      RECT 0.216 25.584 906.639 25.680 ;
      RECT 0.216 26.352 906.639 26.448 ;
      RECT 0.216 27.120 906.639 27.216 ;
      RECT 0.216 27.888 906.639 27.984 ;
      RECT 0.216 28.656 906.639 28.752 ;
      RECT 0.216 29.424 906.639 29.520 ;
      RECT 0.216 30.192 906.639 30.288 ;
      RECT 0.216 30.960 906.639 31.056 ;
      RECT 0.216 31.728 906.639 31.824 ;
      RECT 0.216 32.496 906.639 32.592 ;
      RECT 0.216 33.264 906.639 33.360 ;
      RECT 0.216 34.032 906.639 34.128 ;
      RECT 0.216 34.800 906.639 34.896 ;
      RECT 0.216 35.568 906.639 35.664 ;
      RECT 0.216 36.336 906.639 36.432 ;
      RECT 0.216 37.104 906.639 37.200 ;
      RECT 0.216 37.872 906.639 37.968 ;
      RECT 0.216 38.640 906.639 38.736 ;
      RECT 0.216 39.408 906.639 39.504 ;
      RECT 0.216 40.176 906.639 40.272 ;
      RECT 0.216 40.944 906.639 41.040 ;
      RECT 0.216 41.712 906.639 41.808 ;
      RECT 0.216 42.480 906.639 42.576 ;
      RECT 0.216 43.248 906.639 43.344 ;
      RECT 0.216 44.016 906.639 44.112 ;
      RECT 0.216 44.784 906.639 44.880 ;
      RECT 0.216 45.552 906.639 45.648 ;
      RECT 0.216 46.320 906.639 46.416 ;
      RECT 0.216 47.088 906.639 47.184 ;
      RECT 0.216 47.856 906.639 47.952 ;
      RECT 0.216 48.624 906.639 48.720 ;
      RECT 0.216 49.392 906.639 49.488 ;
      RECT 0.216 50.160 906.639 50.256 ;
      RECT 0.216 50.928 906.639 51.024 ;
      RECT 0.216 51.696 906.639 51.792 ;
      RECT 0.216 52.464 906.639 52.560 ;
      RECT 0.216 53.232 906.639 53.328 ;
      RECT 0.216 54.000 906.639 54.096 ;
      RECT 0.216 54.768 906.639 54.864 ;
      RECT 0.216 55.536 906.639 55.632 ;
      RECT 0.216 56.304 906.639 56.400 ;
      RECT 0.216 57.072 906.639 57.168 ;
      RECT 0.216 57.840 906.639 57.936 ;
      RECT 0.216 58.608 906.639 58.704 ;
      RECT 0.216 59.376 906.639 59.472 ;
      RECT 0.216 60.144 906.639 60.240 ;
      RECT 0.216 60.912 906.639 61.008 ;
      RECT 0.216 61.680 906.639 61.776 ;
      RECT 0.216 62.448 906.639 62.544 ;
      RECT 0.216 63.216 906.639 63.312 ;
      RECT 0.216 63.984 906.639 64.080 ;
      RECT 0.216 64.752 906.639 64.848 ;
      RECT 0.216 65.520 906.639 65.616 ;
      RECT 0.216 66.288 906.639 66.384 ;
      RECT 0.216 67.056 906.639 67.152 ;
      RECT 0.216 67.824 906.639 67.920 ;
      RECT 0.216 68.592 906.639 68.688 ;
      RECT 0.216 69.360 906.639 69.456 ;
      RECT 0.216 70.128 906.639 70.224 ;
      RECT 0.216 70.896 906.639 70.992 ;
      RECT 0.216 71.664 906.639 71.760 ;
      RECT 0.216 72.432 906.639 72.528 ;
      RECT 0.216 73.200 906.639 73.296 ;
      RECT 0.216 73.968 906.639 74.064 ;
      RECT 0.216 74.736 906.639 74.832 ;
      RECT 0.216 75.504 906.639 75.600 ;
      RECT 0.216 76.272 906.639 76.368 ;
      RECT 0.216 77.040 906.639 77.136 ;
      RECT 0.216 77.808 906.639 77.904 ;
      RECT 0.216 78.576 906.639 78.672 ;
      RECT 0.216 79.344 906.639 79.440 ;
      RECT 0.216 80.112 906.639 80.208 ;
      RECT 0.216 80.880 906.639 80.976 ;
      RECT 0.216 81.648 906.639 81.744 ;
      RECT 0.216 82.416 906.639 82.512 ;
      RECT 0.216 83.184 906.639 83.280 ;
      RECT 0.216 83.952 906.639 84.048 ;
      RECT 0.216 84.720 906.639 84.816 ;
      RECT 0.216 85.488 906.639 85.584 ;
      RECT 0.216 86.256 906.639 86.352 ;
      RECT 0.216 87.024 906.639 87.120 ;
      RECT 0.216 87.792 906.639 87.888 ;
      RECT 0.216 88.560 906.639 88.656 ;
      RECT 0.216 89.328 906.639 89.424 ;
      RECT 0.216 90.096 906.639 90.192 ;
      RECT 0.216 90.864 906.639 90.960 ;
      RECT 0.216 91.632 906.639 91.728 ;
      RECT 0.216 92.400 906.639 92.496 ;
      RECT 0.216 93.168 906.639 93.264 ;
      RECT 0.216 93.936 906.639 94.032 ;
      RECT 0.216 94.704 906.639 94.800 ;
      RECT 0.216 95.472 906.639 95.568 ;
      RECT 0.216 96.240 906.639 96.336 ;
      RECT 0.216 97.008 906.639 97.104 ;
      RECT 0.216 97.776 906.639 97.872 ;
      RECT 0.216 98.544 906.639 98.640 ;
      RECT 0.216 99.312 906.639 99.408 ;
      RECT 0.216 100.080 906.639 100.176 ;
      RECT 0.216 100.848 906.639 100.944 ;
      RECT 0.216 101.616 906.639 101.712 ;
      RECT 0.216 102.384 906.639 102.480 ;
      RECT 0.216 103.152 906.639 103.248 ;
      RECT 0.216 103.920 906.639 104.016 ;
      RECT 0.216 104.688 906.639 104.784 ;
      RECT 0.216 105.456 906.639 105.552 ;
      RECT 0.216 106.224 906.639 106.320 ;
      RECT 0.216 106.992 906.639 107.088 ;
      RECT 0.216 107.760 906.639 107.856 ;
      RECT 0.216 108.528 906.639 108.624 ;
      RECT 0.216 109.296 906.639 109.392 ;
      RECT 0.216 110.064 906.639 110.160 ;
      RECT 0.216 110.832 906.639 110.928 ;
      RECT 0.216 111.600 906.639 111.696 ;
      RECT 0.216 112.368 906.639 112.464 ;
      RECT 0.216 113.136 906.639 113.232 ;
      RECT 0.216 113.904 906.639 114.000 ;
      RECT 0.216 114.672 906.639 114.768 ;
      RECT 0.216 115.440 906.639 115.536 ;
      RECT 0.216 116.208 906.639 116.304 ;
      RECT 0.216 116.976 906.639 117.072 ;
      RECT 0.216 117.744 906.639 117.840 ;
      RECT 0.216 118.512 906.639 118.608 ;
      RECT 0.216 119.280 906.639 119.376 ;
      RECT 0.216 120.048 906.639 120.144 ;
      RECT 0.216 120.816 906.639 120.912 ;
      RECT 0.216 121.584 906.639 121.680 ;
      RECT 0.216 122.352 906.639 122.448 ;
      RECT 0.216 123.120 906.639 123.216 ;
      RECT 0.216 123.888 906.639 123.984 ;
      RECT 0.216 124.656 906.639 124.752 ;
      RECT 0.216 125.424 906.639 125.520 ;
      RECT 0.216 126.192 906.639 126.288 ;
      RECT 0.216 126.960 906.639 127.056 ;
      RECT 0.216 127.728 906.639 127.824 ;
      RECT 0.216 128.496 906.639 128.592 ;
      RECT 0.216 129.264 906.639 129.360 ;
      RECT 0.216 130.032 906.639 130.128 ;
      RECT 0.216 130.800 906.639 130.896 ;
      RECT 0.216 131.568 906.639 131.664 ;
      RECT 0.216 132.336 906.639 132.432 ;
      RECT 0.216 133.104 906.639 133.200 ;
      RECT 0.216 133.872 906.639 133.968 ;
      RECT 0.216 134.640 906.639 134.736 ;
      RECT 0.216 135.408 906.639 135.504 ;
      RECT 0.216 136.176 906.639 136.272 ;
      RECT 0.216 136.944 906.639 137.040 ;
      RECT 0.216 137.712 906.639 137.808 ;
      RECT 0.216 138.480 906.639 138.576 ;
      RECT 0.216 139.248 906.639 139.344 ;
      RECT 0.216 140.016 906.639 140.112 ;
      RECT 0.216 140.784 906.639 140.880 ;
      RECT 0.216 141.552 906.639 141.648 ;
      RECT 0.216 142.320 906.639 142.416 ;
      RECT 0.216 143.088 906.639 143.184 ;
      RECT 0.216 143.856 906.639 143.952 ;
      RECT 0.216 144.624 906.639 144.720 ;
      RECT 0.216 145.392 906.639 145.488 ;
      RECT 0.216 146.160 906.639 146.256 ;
      RECT 0.216 146.928 906.639 147.024 ;
      RECT 0.216 147.696 906.639 147.792 ;
      RECT 0.216 148.464 906.639 148.560 ;
      RECT 0.216 149.232 906.639 149.328 ;
      RECT 0.216 150.000 906.639 150.096 ;
      RECT 0.216 150.768 906.639 150.864 ;
      RECT 0.216 151.536 906.639 151.632 ;
      RECT 0.216 152.304 906.639 152.400 ;
      RECT 0.216 153.072 906.639 153.168 ;
      RECT 0.216 153.840 906.639 153.936 ;
      RECT 0.216 154.608 906.639 154.704 ;
      RECT 0.216 155.376 906.639 155.472 ;
      RECT 0.216 156.144 906.639 156.240 ;
      RECT 0.216 156.912 906.639 157.008 ;
      RECT 0.216 157.680 906.639 157.776 ;
      RECT 0.216 158.448 906.639 158.544 ;
      RECT 0.216 159.216 906.639 159.312 ;
      RECT 0.216 159.984 906.639 160.080 ;
      RECT 0.216 160.752 906.639 160.848 ;
      RECT 0.216 161.520 906.639 161.616 ;
      RECT 0.216 162.288 906.639 162.384 ;
      RECT 0.216 163.056 906.639 163.152 ;
      RECT 0.216 163.824 906.639 163.920 ;
      RECT 0.216 164.592 906.639 164.688 ;
      RECT 0.216 165.360 906.639 165.456 ;
      RECT 0.216 166.128 906.639 166.224 ;
      RECT 0.216 166.896 906.639 166.992 ;
      RECT 0.216 167.664 906.639 167.760 ;
      RECT 0.216 168.432 906.639 168.528 ;
      RECT 0.216 169.200 906.639 169.296 ;
      RECT 0.216 169.968 906.639 170.064 ;
      RECT 0.216 170.736 906.639 170.832 ;
      RECT 0.216 171.504 906.639 171.600 ;
      RECT 0.216 172.272 906.639 172.368 ;
      RECT 0.216 173.040 906.639 173.136 ;
      RECT 0.216 173.808 906.639 173.904 ;
      RECT 0.216 174.576 906.639 174.672 ;
      RECT 0.216 175.344 906.639 175.440 ;
      RECT 0.216 176.112 906.639 176.208 ;
      RECT 0.216 176.880 906.639 176.976 ;
      RECT 0.216 177.648 906.639 177.744 ;
      RECT 0.216 178.416 906.639 178.512 ;
      RECT 0.216 179.184 906.639 179.280 ;
      RECT 0.216 179.952 906.639 180.048 ;
      RECT 0.216 180.720 906.639 180.816 ;
      RECT 0.216 181.488 906.639 181.584 ;
      RECT 0.216 182.256 906.639 182.352 ;
      RECT 0.216 183.024 906.639 183.120 ;
      RECT 0.216 183.792 906.639 183.888 ;
      RECT 0.216 184.560 906.639 184.656 ;
      RECT 0.216 185.328 906.639 185.424 ;
      RECT 0.216 186.096 906.639 186.192 ;
      RECT 0.216 186.864 906.639 186.960 ;
      RECT 0.216 187.632 906.639 187.728 ;
      RECT 0.216 188.400 906.639 188.496 ;
      RECT 0.216 189.168 906.639 189.264 ;
      RECT 0.216 189.936 906.639 190.032 ;
      RECT 0.216 190.704 906.639 190.800 ;
      RECT 0.216 191.472 906.639 191.568 ;
      RECT 0.216 192.240 906.639 192.336 ;
      RECT 0.216 193.008 906.639 193.104 ;
      RECT 0.216 193.776 906.639 193.872 ;
      RECT 0.216 194.544 906.639 194.640 ;
      RECT 0.216 195.312 906.639 195.408 ;
      RECT 0.216 196.080 906.639 196.176 ;
      RECT 0.216 196.848 906.639 196.944 ;
      RECT 0.216 197.616 906.639 197.712 ;
      RECT 0.216 198.384 906.639 198.480 ;
      RECT 0.216 199.152 906.639 199.248 ;
      RECT 0.216 199.920 906.639 200.016 ;
      RECT 0.216 200.688 906.639 200.784 ;
      RECT 0.216 201.456 906.639 201.552 ;
      RECT 0.216 202.224 906.639 202.320 ;
      RECT 0.216 202.992 906.639 203.088 ;
      RECT 0.216 203.760 906.639 203.856 ;
      RECT 0.216 204.528 906.639 204.624 ;
      RECT 0.216 205.296 906.639 205.392 ;
      RECT 0.216 206.064 906.639 206.160 ;
      RECT 0.216 206.832 906.639 206.928 ;
      RECT 0.216 207.600 906.639 207.696 ;
      RECT 0.216 208.368 906.639 208.464 ;
      RECT 0.216 209.136 906.639 209.232 ;
      RECT 0.216 209.904 906.639 210.000 ;
      RECT 0.216 210.672 906.639 210.768 ;
      RECT 0.216 211.440 906.639 211.536 ;
      RECT 0.216 212.208 906.639 212.304 ;
      RECT 0.216 212.976 906.639 213.072 ;
      RECT 0.216 213.744 906.639 213.840 ;
      RECT 0.216 214.512 906.639 214.608 ;
      RECT 0.216 215.280 906.639 215.376 ;
      RECT 0.216 216.048 906.639 216.144 ;
      RECT 0.216 216.816 906.639 216.912 ;
      RECT 0.216 217.584 906.639 217.680 ;
      RECT 0.216 218.352 906.639 218.448 ;
      RECT 0.216 219.120 906.639 219.216 ;
      RECT 0.216 219.888 906.639 219.984 ;
      RECT 0.216 220.656 906.639 220.752 ;
      RECT 0.216 221.424 906.639 221.520 ;
      RECT 0.216 222.192 906.639 222.288 ;
      RECT 0.216 222.960 906.639 223.056 ;
      RECT 0.216 223.728 906.639 223.824 ;
      RECT 0.216 224.496 906.639 224.592 ;
      RECT 0.216 225.264 906.639 225.360 ;
      RECT 0.216 226.032 906.639 226.128 ;
      RECT 0.216 226.800 906.639 226.896 ;
      RECT 0.216 227.568 906.639 227.664 ;
      RECT 0.216 228.336 906.639 228.432 ;
      RECT 0.216 229.104 906.639 229.200 ;
      RECT 0.216 229.872 906.639 229.968 ;
      RECT 0.216 230.640 906.639 230.736 ;
      RECT 0.216 231.408 906.639 231.504 ;
      RECT 0.216 232.176 906.639 232.272 ;
      RECT 0.216 232.944 906.639 233.040 ;
      RECT 0.216 233.712 906.639 233.808 ;
      RECT 0.216 234.480 906.639 234.576 ;
      RECT 0.216 235.248 906.639 235.344 ;
      RECT 0.216 236.016 906.639 236.112 ;
      RECT 0.216 236.784 906.639 236.880 ;
      RECT 0.216 237.552 906.639 237.648 ;
      RECT 0.216 238.320 906.639 238.416 ;
      RECT 0.216 239.088 906.639 239.184 ;
      RECT 0.216 239.856 906.639 239.952 ;
      RECT 0.216 240.624 906.639 240.720 ;
      RECT 0.216 241.392 906.639 241.488 ;
      RECT 0.216 242.160 906.639 242.256 ;
      RECT 0.216 242.928 906.639 243.024 ;
      RECT 0.216 243.696 906.639 243.792 ;
      RECT 0.216 244.464 906.639 244.560 ;
      RECT 0.216 245.232 906.639 245.328 ;
      RECT 0.216 246.000 906.639 246.096 ;
      RECT 0.216 246.768 906.639 246.864 ;
      RECT 0.216 247.536 906.639 247.632 ;
      RECT 0.216 248.304 906.639 248.400 ;
      RECT 0.216 249.072 906.639 249.168 ;
      RECT 0.216 249.840 906.639 249.936 ;
      RECT 0.216 250.608 906.639 250.704 ;
      RECT 0.216 251.376 906.639 251.472 ;
      RECT 0.216 252.144 906.639 252.240 ;
      RECT 0.216 252.912 906.639 253.008 ;
      RECT 0.216 253.680 906.639 253.776 ;
      RECT 0.216 254.448 906.639 254.544 ;
      RECT 0.216 255.216 906.639 255.312 ;
      RECT 0.216 255.984 906.639 256.080 ;
      RECT 0.216 256.752 906.639 256.848 ;
      RECT 0.216 257.520 906.639 257.616 ;
      RECT 0.216 258.288 906.639 258.384 ;
      RECT 0.216 259.056 906.639 259.152 ;
      RECT 0.216 259.824 906.639 259.920 ;
      RECT 0.216 260.592 906.639 260.688 ;
      RECT 0.216 261.360 906.639 261.456 ;
      RECT 0.216 262.128 906.639 262.224 ;
      RECT 0.216 262.896 906.639 262.992 ;
      RECT 0.216 263.664 906.639 263.760 ;
      RECT 0.216 264.432 906.639 264.528 ;
      RECT 0.216 265.200 906.639 265.296 ;
      RECT 0.216 265.968 906.639 266.064 ;
      RECT 0.216 266.736 906.639 266.832 ;
      RECT 0.216 267.504 906.639 267.600 ;
      RECT 0.216 268.272 906.639 268.368 ;
      RECT 0.216 269.040 906.639 269.136 ;
      RECT 0.216 269.808 906.639 269.904 ;
      RECT 0.216 270.576 906.639 270.672 ;
      RECT 0.216 271.344 906.639 271.440 ;
      RECT 0.216 272.112 906.639 272.208 ;
      RECT 0.216 272.880 906.639 272.976 ;
      RECT 0.216 273.648 906.639 273.744 ;
      RECT 0.216 274.416 906.639 274.512 ;
      RECT 0.216 275.184 906.639 275.280 ;
      RECT 0.216 275.952 906.639 276.048 ;
      RECT 0.216 276.720 906.639 276.816 ;
      RECT 0.216 277.488 906.639 277.584 ;
      RECT 0.216 278.256 906.639 278.352 ;
      RECT 0.216 279.024 906.639 279.120 ;
      RECT 0.216 279.792 906.639 279.888 ;
      RECT 0.216 280.560 906.639 280.656 ;
      RECT 0.216 281.328 906.639 281.424 ;
      RECT 0.216 282.096 906.639 282.192 ;
      RECT 0.216 282.864 906.639 282.960 ;
      RECT 0.216 283.632 906.639 283.728 ;
      RECT 0.216 284.400 906.639 284.496 ;
      RECT 0.216 285.168 906.639 285.264 ;
      RECT 0.216 285.936 906.639 286.032 ;
      RECT 0.216 286.704 906.639 286.800 ;
      RECT 0.216 287.472 906.639 287.568 ;
      RECT 0.216 288.240 906.639 288.336 ;
      RECT 0.216 289.008 906.639 289.104 ;
      RECT 0.216 289.776 906.639 289.872 ;
      RECT 0.216 290.544 906.639 290.640 ;
      RECT 0.216 291.312 906.639 291.408 ;
      RECT 0.216 292.080 906.639 292.176 ;
      RECT 0.216 292.848 906.639 292.944 ;
      RECT 0.216 293.616 906.639 293.712 ;
      RECT 0.216 294.384 906.639 294.480 ;
      RECT 0.216 295.152 906.639 295.248 ;
      RECT 0.216 295.920 906.639 296.016 ;
      RECT 0.216 296.688 906.639 296.784 ;
      RECT 0.216 297.456 906.639 297.552 ;
      RECT 0.216 298.224 906.639 298.320 ;
      RECT 0.216 298.992 906.639 299.088 ;
      RECT 0.216 299.760 906.639 299.856 ;
      RECT 0.216 300.528 906.639 300.624 ;
      RECT 0.216 301.296 906.639 301.392 ;
      RECT 0.216 302.064 906.639 302.160 ;
      RECT 0.216 302.832 906.639 302.928 ;
      RECT 0.216 303.600 906.639 303.696 ;
      RECT 0.216 304.368 906.639 304.464 ;
      RECT 0.216 305.136 906.639 305.232 ;
      RECT 0.216 305.904 906.639 306.000 ;
      RECT 0.216 306.672 906.639 306.768 ;
      RECT 0.216 307.440 906.639 307.536 ;
      RECT 0.216 308.208 906.639 308.304 ;
      RECT 0.216 308.976 906.639 309.072 ;
      RECT 0.216 309.744 906.639 309.840 ;
      RECT 0.216 310.512 906.639 310.608 ;
      RECT 0.216 311.280 906.639 311.376 ;
      RECT 0.216 312.048 906.639 312.144 ;
      RECT 0.216 312.816 906.639 312.912 ;
      RECT 0.216 313.584 906.639 313.680 ;
      RECT 0.216 314.352 906.639 314.448 ;
      RECT 0.216 315.120 906.639 315.216 ;
      RECT 0.216 315.888 906.639 315.984 ;
      RECT 0.216 316.656 906.639 316.752 ;
      RECT 0.216 317.424 906.639 317.520 ;
      RECT 0.216 318.192 906.639 318.288 ;
      RECT 0.216 318.960 906.639 319.056 ;
      RECT 0.216 319.728 906.639 319.824 ;
      RECT 0.216 320.496 906.639 320.592 ;
      RECT 0.216 321.264 906.639 321.360 ;
      RECT 0.216 322.032 906.639 322.128 ;
      RECT 0.216 322.800 906.639 322.896 ;
      RECT 0.216 323.568 906.639 323.664 ;
      RECT 0.216 324.336 906.639 324.432 ;
      RECT 0.216 325.104 906.639 325.200 ;
      RECT 0.216 325.872 906.639 325.968 ;
      RECT 0.216 326.640 906.639 326.736 ;
      RECT 0.216 327.408 906.639 327.504 ;
      RECT 0.216 328.176 906.639 328.272 ;
      RECT 0.216 328.944 906.639 329.040 ;
      RECT 0.216 329.712 906.639 329.808 ;
      RECT 0.216 330.480 906.639 330.576 ;
      RECT 0.216 331.248 906.639 331.344 ;
      RECT 0.216 332.016 906.639 332.112 ;
      RECT 0.216 332.784 906.639 332.880 ;
      RECT 0.216 333.552 906.639 333.648 ;
      RECT 0.216 334.320 906.639 334.416 ;
      RECT 0.216 335.088 906.639 335.184 ;
      RECT 0.216 335.856 906.639 335.952 ;
      RECT 0.216 336.624 906.639 336.720 ;
      RECT 0.216 337.392 906.639 337.488 ;
      RECT 0.216 338.160 906.639 338.256 ;
      RECT 0.216 338.928 906.639 339.024 ;
      RECT 0.216 339.696 906.639 339.792 ;
      RECT 0.216 340.464 906.639 340.560 ;
      RECT 0.216 341.232 906.639 341.328 ;
      RECT 0.216 342.000 906.639 342.096 ;
      RECT 0.216 342.768 906.639 342.864 ;
      RECT 0.216 343.536 906.639 343.632 ;
      RECT 0.216 344.304 906.639 344.400 ;
      RECT 0.216 345.072 906.639 345.168 ;
      RECT 0.216 345.840 906.639 345.936 ;
      RECT 0.216 346.608 906.639 346.704 ;
      RECT 0.216 347.376 906.639 347.472 ;
      RECT 0.216 348.144 906.639 348.240 ;
      RECT 0.216 348.912 906.639 349.008 ;
      RECT 0.216 349.680 906.639 349.776 ;
      RECT 0.216 350.448 906.639 350.544 ;
      RECT 0.216 351.216 906.639 351.312 ;
      RECT 0.216 351.984 906.639 352.080 ;
      RECT 0.216 352.752 906.639 352.848 ;
      RECT 0.216 353.520 906.639 353.616 ;
      RECT 0.216 354.288 906.639 354.384 ;
      RECT 0.216 355.056 906.639 355.152 ;
      RECT 0.216 355.824 906.639 355.920 ;
      RECT 0.216 356.592 906.639 356.688 ;
      RECT 0.216 357.360 906.639 357.456 ;
      RECT 0.216 358.128 906.639 358.224 ;
      RECT 0.216 358.896 906.639 358.992 ;
      RECT 0.216 359.664 906.639 359.760 ;
      RECT 0.216 360.432 906.639 360.528 ;
      RECT 0.216 361.200 906.639 361.296 ;
      RECT 0.216 361.968 906.639 362.064 ;
      RECT 0.216 362.736 906.639 362.832 ;
      RECT 0.216 363.504 906.639 363.600 ;
      RECT 0.216 364.272 906.639 364.368 ;
      RECT 0.216 365.040 906.639 365.136 ;
      RECT 0.216 365.808 906.639 365.904 ;
      RECT 0.216 366.576 906.639 366.672 ;
      RECT 0.216 367.344 906.639 367.440 ;
      RECT 0.216 368.112 906.639 368.208 ;
      RECT 0.216 368.880 906.639 368.976 ;
      RECT 0.216 369.648 906.639 369.744 ;
      RECT 0.216 370.416 906.639 370.512 ;
      RECT 0.216 371.184 906.639 371.280 ;
      RECT 0.216 371.952 906.639 372.048 ;
      RECT 0.216 372.720 906.639 372.816 ;
      RECT 0.216 373.488 906.639 373.584 ;
      RECT 0.216 374.256 906.639 374.352 ;
      RECT 0.216 375.024 906.639 375.120 ;
      RECT 0.216 375.792 906.639 375.888 ;
      RECT 0.216 376.560 906.639 376.656 ;
      RECT 0.216 377.328 906.639 377.424 ;
      RECT 0.216 378.096 906.639 378.192 ;
      RECT 0.216 378.864 906.639 378.960 ;
      RECT 0.216 379.632 906.639 379.728 ;
      RECT 0.216 380.400 906.639 380.496 ;
      RECT 0.216 381.168 906.639 381.264 ;
      RECT 0.216 381.936 906.639 382.032 ;
      RECT 0.216 382.704 906.639 382.800 ;
      RECT 0.216 383.472 906.639 383.568 ;
      RECT 0.216 384.240 906.639 384.336 ;
      RECT 0.216 385.008 906.639 385.104 ;
      RECT 0.216 385.776 906.639 385.872 ;
      RECT 0.216 386.544 906.639 386.640 ;
      RECT 0.216 387.312 906.639 387.408 ;
      RECT 0.216 388.080 906.639 388.176 ;
      RECT 0.216 388.848 906.639 388.944 ;
      RECT 0.216 389.616 906.639 389.712 ;
      RECT 0.216 390.384 906.639 390.480 ;
      RECT 0.216 391.152 906.639 391.248 ;
      RECT 0.216 391.920 906.639 392.016 ;
      RECT 0.216 392.688 906.639 392.784 ;
      RECT 0.216 393.456 906.639 393.552 ;
      RECT 0.216 394.224 906.639 394.320 ;
      RECT 0.216 394.992 906.639 395.088 ;
      RECT 0.216 395.760 906.639 395.856 ;
      RECT 0.216 396.528 906.639 396.624 ;
      RECT 0.216 397.296 906.639 397.392 ;
      RECT 0.216 398.064 906.639 398.160 ;
      RECT 0.216 398.832 906.639 398.928 ;
      RECT 0.216 399.600 906.639 399.696 ;
      RECT 0.216 400.368 906.639 400.464 ;
      RECT 0.216 401.136 906.639 401.232 ;
      RECT 0.216 401.904 906.639 402.000 ;
      RECT 0.216 402.672 906.639 402.768 ;
      RECT 0.216 403.440 906.639 403.536 ;
      RECT 0.216 404.208 906.639 404.304 ;
      RECT 0.216 404.976 906.639 405.072 ;
      RECT 0.216 405.744 906.639 405.840 ;
      RECT 0.216 406.512 906.639 406.608 ;
      RECT 0.216 407.280 906.639 407.376 ;
      RECT 0.216 408.048 906.639 408.144 ;
      RECT 0.216 408.816 906.639 408.912 ;
      RECT 0.216 409.584 906.639 409.680 ;
      RECT 0.216 410.352 906.639 410.448 ;
      RECT 0.216 411.120 906.639 411.216 ;
      RECT 0.216 411.888 906.639 411.984 ;
      RECT 0.216 412.656 906.639 412.752 ;
      RECT 0.216 413.424 906.639 413.520 ;
      RECT 0.216 414.192 906.639 414.288 ;
      RECT 0.216 414.960 906.639 415.056 ;
      RECT 0.216 415.728 906.639 415.824 ;
      RECT 0.216 416.496 906.639 416.592 ;
      RECT 0.216 417.264 906.639 417.360 ;
      RECT 0.216 418.032 906.639 418.128 ;
      RECT 0.216 418.800 906.639 418.896 ;
      RECT 0.216 419.568 906.639 419.664 ;
      RECT 0.216 420.336 906.639 420.432 ;
      RECT 0.216 421.104 906.639 421.200 ;
      RECT 0.216 421.872 906.639 421.968 ;
      RECT 0.216 422.640 906.639 422.736 ;
      RECT 0.216 423.408 906.639 423.504 ;
      RECT 0.216 424.176 906.639 424.272 ;
      RECT 0.216 424.944 906.639 425.040 ;
      RECT 0.216 425.712 906.639 425.808 ;
      RECT 0.216 426.480 906.639 426.576 ;
      RECT 0.216 427.248 906.639 427.344 ;
      RECT 0.216 428.016 906.639 428.112 ;
      RECT 0.216 428.784 906.639 428.880 ;
      RECT 0.216 429.552 906.639 429.648 ;
      RECT 0.216 430.320 906.639 430.416 ;
      RECT 0.216 431.088 906.639 431.184 ;
      RECT 0.216 431.856 906.639 431.952 ;
      RECT 0.216 432.624 906.639 432.720 ;
      RECT 0.216 433.392 906.639 433.488 ;
      RECT 0.216 434.160 906.639 434.256 ;
      RECT 0.216 434.928 906.639 435.024 ;
      RECT 0.216 435.696 906.639 435.792 ;
      RECT 0.216 436.464 906.639 436.560 ;
      RECT 0.216 437.232 906.639 437.328 ;
      RECT 0.216 438.000 906.639 438.096 ;
      RECT 0.216 438.768 906.639 438.864 ;
      RECT 0.216 439.536 906.639 439.632 ;
      RECT 0.216 440.304 906.639 440.400 ;
      RECT 0.216 441.072 906.639 441.168 ;
      RECT 0.216 441.840 906.639 441.936 ;
      RECT 0.216 442.608 906.639 442.704 ;
      RECT 0.216 443.376 906.639 443.472 ;
      RECT 0.216 444.144 906.639 444.240 ;
      RECT 0.216 444.912 906.639 445.008 ;
      RECT 0.216 445.680 906.639 445.776 ;
      RECT 0.216 446.448 906.639 446.544 ;
      RECT 0.216 447.216 906.639 447.312 ;
      RECT 0.216 447.984 906.639 448.080 ;
      RECT 0.216 448.752 906.639 448.848 ;
      RECT 0.216 449.520 906.639 449.616 ;
      RECT 0.216 450.288 906.639 450.384 ;
      RECT 0.216 451.056 906.639 451.152 ;
      RECT 0.216 451.824 906.639 451.920 ;
      RECT 0.216 452.592 906.639 452.688 ;
      RECT 0.216 453.360 906.639 453.456 ;
      RECT 0.216 454.128 906.639 454.224 ;
      RECT 0.216 454.896 906.639 454.992 ;
      RECT 0.216 455.664 906.639 455.760 ;
      RECT 0.216 456.432 906.639 456.528 ;
      RECT 0.216 457.200 906.639 457.296 ;
      RECT 0.216 457.968 906.639 458.064 ;
      RECT 0.216 458.736 906.639 458.832 ;
      RECT 0.216 459.504 906.639 459.600 ;
      RECT 0.216 460.272 906.639 460.368 ;
      RECT 0.216 461.040 906.639 461.136 ;
      RECT 0.216 461.808 906.639 461.904 ;
      RECT 0.216 462.576 906.639 462.672 ;
      RECT 0.216 463.344 906.639 463.440 ;
      RECT 0.216 464.112 906.639 464.208 ;
      RECT 0.216 464.880 906.639 464.976 ;
      RECT 0.216 465.648 906.639 465.744 ;
      RECT 0.216 466.416 906.639 466.512 ;
      RECT 0.216 467.184 906.639 467.280 ;
      RECT 0.216 467.952 906.639 468.048 ;
      RECT 0.216 468.720 906.639 468.816 ;
      RECT 0.216 469.488 906.639 469.584 ;
      RECT 0.216 470.256 906.639 470.352 ;
      RECT 0.216 471.024 906.639 471.120 ;
      RECT 0.216 471.792 906.639 471.888 ;
      RECT 0.216 472.560 906.639 472.656 ;
      RECT 0.216 473.328 906.639 473.424 ;
      RECT 0.216 474.096 906.639 474.192 ;
      RECT 0.216 474.864 906.639 474.960 ;
      RECT 0.216 475.632 906.639 475.728 ;
      RECT 0.216 476.400 906.639 476.496 ;
      RECT 0.216 477.168 906.639 477.264 ;
      RECT 0.216 477.936 906.639 478.032 ;
      RECT 0.216 478.704 906.639 478.800 ;
      RECT 0.216 479.472 906.639 479.568 ;
      RECT 0.216 480.240 906.639 480.336 ;
      RECT 0.216 481.008 906.639 481.104 ;
      RECT 0.216 481.776 906.639 481.872 ;
      RECT 0.216 482.544 906.639 482.640 ;
      RECT 0.216 483.312 906.639 483.408 ;
      RECT 0.216 484.080 906.639 484.176 ;
      RECT 0.216 484.848 906.639 484.944 ;
      RECT 0.216 485.616 906.639 485.712 ;
      RECT 0.216 486.384 906.639 486.480 ;
      RECT 0.216 487.152 906.639 487.248 ;
      RECT 0.216 487.920 906.639 488.016 ;
      RECT 0.216 488.688 906.639 488.784 ;
      RECT 0.216 489.456 906.639 489.552 ;
      RECT 0.216 490.224 906.639 490.320 ;
      RECT 0.216 490.992 906.639 491.088 ;
      RECT 0.216 491.760 906.639 491.856 ;
      RECT 0.216 492.528 906.639 492.624 ;
      RECT 0.216 493.296 906.639 493.392 ;
      RECT 0.216 494.064 906.639 494.160 ;
      RECT 0.216 494.832 906.639 494.928 ;
      RECT 0.216 495.600 906.639 495.696 ;
      RECT 0.216 496.368 906.639 496.464 ;
      RECT 0.216 497.136 906.639 497.232 ;
      RECT 0.216 497.904 906.639 498.000 ;
      RECT 0.216 498.672 906.639 498.768 ;
      RECT 0.216 499.440 906.639 499.536 ;
      RECT 0.216 500.208 906.639 500.304 ;
      RECT 0.216 500.976 906.639 501.072 ;
      RECT 0.216 501.744 906.639 501.840 ;
      RECT 0.216 502.512 906.639 502.608 ;
      RECT 0.216 503.280 906.639 503.376 ;
      RECT 0.216 504.048 906.639 504.144 ;
      RECT 0.216 504.816 906.639 504.912 ;
      RECT 0.216 505.584 906.639 505.680 ;
      RECT 0.216 506.352 906.639 506.448 ;
      RECT 0.216 507.120 906.639 507.216 ;
      RECT 0.216 507.888 906.639 507.984 ;
      RECT 0.216 508.656 906.639 508.752 ;
      RECT 0.216 509.424 906.639 509.520 ;
      RECT 0.216 510.192 906.639 510.288 ;
      RECT 0.216 510.960 906.639 511.056 ;
      RECT 0.216 511.728 906.639 511.824 ;
      RECT 0.216 512.496 906.639 512.592 ;
      RECT 0.216 513.264 906.639 513.360 ;
      RECT 0.216 514.032 906.639 514.128 ;
      RECT 0.216 514.800 906.639 514.896 ;
      RECT 0.216 515.568 906.639 515.664 ;
      RECT 0.216 516.336 906.639 516.432 ;
      RECT 0.216 517.104 906.639 517.200 ;
      RECT 0.216 517.872 906.639 517.968 ;
      RECT 0.216 518.640 906.639 518.736 ;
      RECT 0.216 519.408 906.639 519.504 ;
      RECT 0.216 520.176 906.639 520.272 ;
      RECT 0.216 520.944 906.639 521.040 ;
      RECT 0.216 521.712 906.639 521.808 ;
      RECT 0.216 522.480 906.639 522.576 ;
      RECT 0.216 523.248 906.639 523.344 ;
      RECT 0.216 524.016 906.639 524.112 ;
      RECT 0.216 524.784 906.639 524.880 ;
      RECT 0.216 525.552 906.639 525.648 ;
      RECT 0.216 526.320 906.639 526.416 ;
      RECT 0.216 527.088 906.639 527.184 ;
      RECT 0.216 527.856 906.639 527.952 ;
      RECT 0.216 528.624 906.639 528.720 ;
      RECT 0.216 529.392 906.639 529.488 ;
      RECT 0.216 530.160 906.639 530.256 ;
      RECT 0.216 530.928 906.639 531.024 ;
      RECT 0.216 531.696 906.639 531.792 ;
      RECT 0.216 532.464 906.639 532.560 ;
      RECT 0.216 533.232 906.639 533.328 ;
      RECT 0.216 534.000 906.639 534.096 ;
      RECT 0.216 534.768 906.639 534.864 ;
      RECT 0.216 535.536 906.639 535.632 ;
      RECT 0.216 536.304 906.639 536.400 ;
      RECT 0.216 537.072 906.639 537.168 ;
      RECT 0.216 537.840 906.639 537.936 ;
      RECT 0.216 538.608 906.639 538.704 ;
      RECT 0.216 539.376 906.639 539.472 ;
      RECT 0.216 540.144 906.639 540.240 ;
      RECT 0.216 540.912 906.639 541.008 ;
      RECT 0.216 541.680 906.639 541.776 ;
      RECT 0.216 542.448 906.639 542.544 ;
      RECT 0.216 543.216 906.639 543.312 ;
      RECT 0.216 543.984 906.639 544.080 ;
      RECT 0.216 544.752 906.639 544.848 ;
      RECT 0.216 545.520 906.639 545.616 ;
      RECT 0.216 546.288 906.639 546.384 ;
      RECT 0.216 547.056 906.639 547.152 ;
      RECT 0.216 547.824 906.639 547.920 ;
      RECT 0.216 548.592 906.639 548.688 ;
      RECT 0.216 549.360 906.639 549.456 ;
      RECT 0.216 550.128 906.639 550.224 ;
      RECT 0.216 550.896 906.639 550.992 ;
      RECT 0.216 551.664 906.639 551.760 ;
      RECT 0.216 552.432 906.639 552.528 ;
      RECT 0.216 553.200 906.639 553.296 ;
      RECT 0.216 553.968 906.639 554.064 ;
      RECT 0.216 554.736 906.639 554.832 ;
      RECT 0.216 555.504 906.639 555.600 ;
      RECT 0.216 556.272 906.639 556.368 ;
      RECT 0.216 557.040 906.639 557.136 ;
      RECT 0.216 557.808 906.639 557.904 ;
      RECT 0.216 558.576 906.639 558.672 ;
      RECT 0.216 559.344 906.639 559.440 ;
      RECT 0.216 560.112 906.639 560.208 ;
      RECT 0.216 560.880 906.639 560.976 ;
      RECT 0.216 561.648 906.639 561.744 ;
      RECT 0.216 562.416 906.639 562.512 ;
      RECT 0.216 563.184 906.639 563.280 ;
      RECT 0.216 563.952 906.639 564.048 ;
      RECT 0.216 564.720 906.639 564.816 ;
      RECT 0.216 565.488 906.639 565.584 ;
      RECT 0.216 566.256 906.639 566.352 ;
    END
  END VSS
  PIN VDD
    DIRECTION INOUT ;
    USE POWER ;
    PORT
      LAYER M4 ;
      RECT 0.216 0.624 906.639 0.720 ;
      RECT 0.216 1.392 906.639 1.488 ;
      RECT 0.216 2.160 906.639 2.256 ;
      RECT 0.216 2.928 906.639 3.024 ;
      RECT 0.216 3.696 906.639 3.792 ;
      RECT 0.216 4.464 906.639 4.560 ;
      RECT 0.216 5.232 906.639 5.328 ;
      RECT 0.216 6.000 906.639 6.096 ;
      RECT 0.216 6.768 906.639 6.864 ;
      RECT 0.216 7.536 906.639 7.632 ;
      RECT 0.216 8.304 906.639 8.400 ;
      RECT 0.216 9.072 906.639 9.168 ;
      RECT 0.216 9.840 906.639 9.936 ;
      RECT 0.216 10.608 906.639 10.704 ;
      RECT 0.216 11.376 906.639 11.472 ;
      RECT 0.216 12.144 906.639 12.240 ;
      RECT 0.216 12.912 906.639 13.008 ;
      RECT 0.216 13.680 906.639 13.776 ;
      RECT 0.216 14.448 906.639 14.544 ;
      RECT 0.216 15.216 906.639 15.312 ;
      RECT 0.216 15.984 906.639 16.080 ;
      RECT 0.216 16.752 906.639 16.848 ;
      RECT 0.216 17.520 906.639 17.616 ;
      RECT 0.216 18.288 906.639 18.384 ;
      RECT 0.216 19.056 906.639 19.152 ;
      RECT 0.216 19.824 906.639 19.920 ;
      RECT 0.216 20.592 906.639 20.688 ;
      RECT 0.216 21.360 906.639 21.456 ;
      RECT 0.216 22.128 906.639 22.224 ;
      RECT 0.216 22.896 906.639 22.992 ;
      RECT 0.216 23.664 906.639 23.760 ;
      RECT 0.216 24.432 906.639 24.528 ;
      RECT 0.216 25.200 906.639 25.296 ;
      RECT 0.216 25.968 906.639 26.064 ;
      RECT 0.216 26.736 906.639 26.832 ;
      RECT 0.216 27.504 906.639 27.600 ;
      RECT 0.216 28.272 906.639 28.368 ;
      RECT 0.216 29.040 906.639 29.136 ;
      RECT 0.216 29.808 906.639 29.904 ;
      RECT 0.216 30.576 906.639 30.672 ;
      RECT 0.216 31.344 906.639 31.440 ;
      RECT 0.216 32.112 906.639 32.208 ;
      RECT 0.216 32.880 906.639 32.976 ;
      RECT 0.216 33.648 906.639 33.744 ;
      RECT 0.216 34.416 906.639 34.512 ;
      RECT 0.216 35.184 906.639 35.280 ;
      RECT 0.216 35.952 906.639 36.048 ;
      RECT 0.216 36.720 906.639 36.816 ;
      RECT 0.216 37.488 906.639 37.584 ;
      RECT 0.216 38.256 906.639 38.352 ;
      RECT 0.216 39.024 906.639 39.120 ;
      RECT 0.216 39.792 906.639 39.888 ;
      RECT 0.216 40.560 906.639 40.656 ;
      RECT 0.216 41.328 906.639 41.424 ;
      RECT 0.216 42.096 906.639 42.192 ;
      RECT 0.216 42.864 906.639 42.960 ;
      RECT 0.216 43.632 906.639 43.728 ;
      RECT 0.216 44.400 906.639 44.496 ;
      RECT 0.216 45.168 906.639 45.264 ;
      RECT 0.216 45.936 906.639 46.032 ;
      RECT 0.216 46.704 906.639 46.800 ;
      RECT 0.216 47.472 906.639 47.568 ;
      RECT 0.216 48.240 906.639 48.336 ;
      RECT 0.216 49.008 906.639 49.104 ;
      RECT 0.216 49.776 906.639 49.872 ;
      RECT 0.216 50.544 906.639 50.640 ;
      RECT 0.216 51.312 906.639 51.408 ;
      RECT 0.216 52.080 906.639 52.176 ;
      RECT 0.216 52.848 906.639 52.944 ;
      RECT 0.216 53.616 906.639 53.712 ;
      RECT 0.216 54.384 906.639 54.480 ;
      RECT 0.216 55.152 906.639 55.248 ;
      RECT 0.216 55.920 906.639 56.016 ;
      RECT 0.216 56.688 906.639 56.784 ;
      RECT 0.216 57.456 906.639 57.552 ;
      RECT 0.216 58.224 906.639 58.320 ;
      RECT 0.216 58.992 906.639 59.088 ;
      RECT 0.216 59.760 906.639 59.856 ;
      RECT 0.216 60.528 906.639 60.624 ;
      RECT 0.216 61.296 906.639 61.392 ;
      RECT 0.216 62.064 906.639 62.160 ;
      RECT 0.216 62.832 906.639 62.928 ;
      RECT 0.216 63.600 906.639 63.696 ;
      RECT 0.216 64.368 906.639 64.464 ;
      RECT 0.216 65.136 906.639 65.232 ;
      RECT 0.216 65.904 906.639 66.000 ;
      RECT 0.216 66.672 906.639 66.768 ;
      RECT 0.216 67.440 906.639 67.536 ;
      RECT 0.216 68.208 906.639 68.304 ;
      RECT 0.216 68.976 906.639 69.072 ;
      RECT 0.216 69.744 906.639 69.840 ;
      RECT 0.216 70.512 906.639 70.608 ;
      RECT 0.216 71.280 906.639 71.376 ;
      RECT 0.216 72.048 906.639 72.144 ;
      RECT 0.216 72.816 906.639 72.912 ;
      RECT 0.216 73.584 906.639 73.680 ;
      RECT 0.216 74.352 906.639 74.448 ;
      RECT 0.216 75.120 906.639 75.216 ;
      RECT 0.216 75.888 906.639 75.984 ;
      RECT 0.216 76.656 906.639 76.752 ;
      RECT 0.216 77.424 906.639 77.520 ;
      RECT 0.216 78.192 906.639 78.288 ;
      RECT 0.216 78.960 906.639 79.056 ;
      RECT 0.216 79.728 906.639 79.824 ;
      RECT 0.216 80.496 906.639 80.592 ;
      RECT 0.216 81.264 906.639 81.360 ;
      RECT 0.216 82.032 906.639 82.128 ;
      RECT 0.216 82.800 906.639 82.896 ;
      RECT 0.216 83.568 906.639 83.664 ;
      RECT 0.216 84.336 906.639 84.432 ;
      RECT 0.216 85.104 906.639 85.200 ;
      RECT 0.216 85.872 906.639 85.968 ;
      RECT 0.216 86.640 906.639 86.736 ;
      RECT 0.216 87.408 906.639 87.504 ;
      RECT 0.216 88.176 906.639 88.272 ;
      RECT 0.216 88.944 906.639 89.040 ;
      RECT 0.216 89.712 906.639 89.808 ;
      RECT 0.216 90.480 906.639 90.576 ;
      RECT 0.216 91.248 906.639 91.344 ;
      RECT 0.216 92.016 906.639 92.112 ;
      RECT 0.216 92.784 906.639 92.880 ;
      RECT 0.216 93.552 906.639 93.648 ;
      RECT 0.216 94.320 906.639 94.416 ;
      RECT 0.216 95.088 906.639 95.184 ;
      RECT 0.216 95.856 906.639 95.952 ;
      RECT 0.216 96.624 906.639 96.720 ;
      RECT 0.216 97.392 906.639 97.488 ;
      RECT 0.216 98.160 906.639 98.256 ;
      RECT 0.216 98.928 906.639 99.024 ;
      RECT 0.216 99.696 906.639 99.792 ;
      RECT 0.216 100.464 906.639 100.560 ;
      RECT 0.216 101.232 906.639 101.328 ;
      RECT 0.216 102.000 906.639 102.096 ;
      RECT 0.216 102.768 906.639 102.864 ;
      RECT 0.216 103.536 906.639 103.632 ;
      RECT 0.216 104.304 906.639 104.400 ;
      RECT 0.216 105.072 906.639 105.168 ;
      RECT 0.216 105.840 906.639 105.936 ;
      RECT 0.216 106.608 906.639 106.704 ;
      RECT 0.216 107.376 906.639 107.472 ;
      RECT 0.216 108.144 906.639 108.240 ;
      RECT 0.216 108.912 906.639 109.008 ;
      RECT 0.216 109.680 906.639 109.776 ;
      RECT 0.216 110.448 906.639 110.544 ;
      RECT 0.216 111.216 906.639 111.312 ;
      RECT 0.216 111.984 906.639 112.080 ;
      RECT 0.216 112.752 906.639 112.848 ;
      RECT 0.216 113.520 906.639 113.616 ;
      RECT 0.216 114.288 906.639 114.384 ;
      RECT 0.216 115.056 906.639 115.152 ;
      RECT 0.216 115.824 906.639 115.920 ;
      RECT 0.216 116.592 906.639 116.688 ;
      RECT 0.216 117.360 906.639 117.456 ;
      RECT 0.216 118.128 906.639 118.224 ;
      RECT 0.216 118.896 906.639 118.992 ;
      RECT 0.216 119.664 906.639 119.760 ;
      RECT 0.216 120.432 906.639 120.528 ;
      RECT 0.216 121.200 906.639 121.296 ;
      RECT 0.216 121.968 906.639 122.064 ;
      RECT 0.216 122.736 906.639 122.832 ;
      RECT 0.216 123.504 906.639 123.600 ;
      RECT 0.216 124.272 906.639 124.368 ;
      RECT 0.216 125.040 906.639 125.136 ;
      RECT 0.216 125.808 906.639 125.904 ;
      RECT 0.216 126.576 906.639 126.672 ;
      RECT 0.216 127.344 906.639 127.440 ;
      RECT 0.216 128.112 906.639 128.208 ;
      RECT 0.216 128.880 906.639 128.976 ;
      RECT 0.216 129.648 906.639 129.744 ;
      RECT 0.216 130.416 906.639 130.512 ;
      RECT 0.216 131.184 906.639 131.280 ;
      RECT 0.216 131.952 906.639 132.048 ;
      RECT 0.216 132.720 906.639 132.816 ;
      RECT 0.216 133.488 906.639 133.584 ;
      RECT 0.216 134.256 906.639 134.352 ;
      RECT 0.216 135.024 906.639 135.120 ;
      RECT 0.216 135.792 906.639 135.888 ;
      RECT 0.216 136.560 906.639 136.656 ;
      RECT 0.216 137.328 906.639 137.424 ;
      RECT 0.216 138.096 906.639 138.192 ;
      RECT 0.216 138.864 906.639 138.960 ;
      RECT 0.216 139.632 906.639 139.728 ;
      RECT 0.216 140.400 906.639 140.496 ;
      RECT 0.216 141.168 906.639 141.264 ;
      RECT 0.216 141.936 906.639 142.032 ;
      RECT 0.216 142.704 906.639 142.800 ;
      RECT 0.216 143.472 906.639 143.568 ;
      RECT 0.216 144.240 906.639 144.336 ;
      RECT 0.216 145.008 906.639 145.104 ;
      RECT 0.216 145.776 906.639 145.872 ;
      RECT 0.216 146.544 906.639 146.640 ;
      RECT 0.216 147.312 906.639 147.408 ;
      RECT 0.216 148.080 906.639 148.176 ;
      RECT 0.216 148.848 906.639 148.944 ;
      RECT 0.216 149.616 906.639 149.712 ;
      RECT 0.216 150.384 906.639 150.480 ;
      RECT 0.216 151.152 906.639 151.248 ;
      RECT 0.216 151.920 906.639 152.016 ;
      RECT 0.216 152.688 906.639 152.784 ;
      RECT 0.216 153.456 906.639 153.552 ;
      RECT 0.216 154.224 906.639 154.320 ;
      RECT 0.216 154.992 906.639 155.088 ;
      RECT 0.216 155.760 906.639 155.856 ;
      RECT 0.216 156.528 906.639 156.624 ;
      RECT 0.216 157.296 906.639 157.392 ;
      RECT 0.216 158.064 906.639 158.160 ;
      RECT 0.216 158.832 906.639 158.928 ;
      RECT 0.216 159.600 906.639 159.696 ;
      RECT 0.216 160.368 906.639 160.464 ;
      RECT 0.216 161.136 906.639 161.232 ;
      RECT 0.216 161.904 906.639 162.000 ;
      RECT 0.216 162.672 906.639 162.768 ;
      RECT 0.216 163.440 906.639 163.536 ;
      RECT 0.216 164.208 906.639 164.304 ;
      RECT 0.216 164.976 906.639 165.072 ;
      RECT 0.216 165.744 906.639 165.840 ;
      RECT 0.216 166.512 906.639 166.608 ;
      RECT 0.216 167.280 906.639 167.376 ;
      RECT 0.216 168.048 906.639 168.144 ;
      RECT 0.216 168.816 906.639 168.912 ;
      RECT 0.216 169.584 906.639 169.680 ;
      RECT 0.216 170.352 906.639 170.448 ;
      RECT 0.216 171.120 906.639 171.216 ;
      RECT 0.216 171.888 906.639 171.984 ;
      RECT 0.216 172.656 906.639 172.752 ;
      RECT 0.216 173.424 906.639 173.520 ;
      RECT 0.216 174.192 906.639 174.288 ;
      RECT 0.216 174.960 906.639 175.056 ;
      RECT 0.216 175.728 906.639 175.824 ;
      RECT 0.216 176.496 906.639 176.592 ;
      RECT 0.216 177.264 906.639 177.360 ;
      RECT 0.216 178.032 906.639 178.128 ;
      RECT 0.216 178.800 906.639 178.896 ;
      RECT 0.216 179.568 906.639 179.664 ;
      RECT 0.216 180.336 906.639 180.432 ;
      RECT 0.216 181.104 906.639 181.200 ;
      RECT 0.216 181.872 906.639 181.968 ;
      RECT 0.216 182.640 906.639 182.736 ;
      RECT 0.216 183.408 906.639 183.504 ;
      RECT 0.216 184.176 906.639 184.272 ;
      RECT 0.216 184.944 906.639 185.040 ;
      RECT 0.216 185.712 906.639 185.808 ;
      RECT 0.216 186.480 906.639 186.576 ;
      RECT 0.216 187.248 906.639 187.344 ;
      RECT 0.216 188.016 906.639 188.112 ;
      RECT 0.216 188.784 906.639 188.880 ;
      RECT 0.216 189.552 906.639 189.648 ;
      RECT 0.216 190.320 906.639 190.416 ;
      RECT 0.216 191.088 906.639 191.184 ;
      RECT 0.216 191.856 906.639 191.952 ;
      RECT 0.216 192.624 906.639 192.720 ;
      RECT 0.216 193.392 906.639 193.488 ;
      RECT 0.216 194.160 906.639 194.256 ;
      RECT 0.216 194.928 906.639 195.024 ;
      RECT 0.216 195.696 906.639 195.792 ;
      RECT 0.216 196.464 906.639 196.560 ;
      RECT 0.216 197.232 906.639 197.328 ;
      RECT 0.216 198.000 906.639 198.096 ;
      RECT 0.216 198.768 906.639 198.864 ;
      RECT 0.216 199.536 906.639 199.632 ;
      RECT 0.216 200.304 906.639 200.400 ;
      RECT 0.216 201.072 906.639 201.168 ;
      RECT 0.216 201.840 906.639 201.936 ;
      RECT 0.216 202.608 906.639 202.704 ;
      RECT 0.216 203.376 906.639 203.472 ;
      RECT 0.216 204.144 906.639 204.240 ;
      RECT 0.216 204.912 906.639 205.008 ;
      RECT 0.216 205.680 906.639 205.776 ;
      RECT 0.216 206.448 906.639 206.544 ;
      RECT 0.216 207.216 906.639 207.312 ;
      RECT 0.216 207.984 906.639 208.080 ;
      RECT 0.216 208.752 906.639 208.848 ;
      RECT 0.216 209.520 906.639 209.616 ;
      RECT 0.216 210.288 906.639 210.384 ;
      RECT 0.216 211.056 906.639 211.152 ;
      RECT 0.216 211.824 906.639 211.920 ;
      RECT 0.216 212.592 906.639 212.688 ;
      RECT 0.216 213.360 906.639 213.456 ;
      RECT 0.216 214.128 906.639 214.224 ;
      RECT 0.216 214.896 906.639 214.992 ;
      RECT 0.216 215.664 906.639 215.760 ;
      RECT 0.216 216.432 906.639 216.528 ;
      RECT 0.216 217.200 906.639 217.296 ;
      RECT 0.216 217.968 906.639 218.064 ;
      RECT 0.216 218.736 906.639 218.832 ;
      RECT 0.216 219.504 906.639 219.600 ;
      RECT 0.216 220.272 906.639 220.368 ;
      RECT 0.216 221.040 906.639 221.136 ;
      RECT 0.216 221.808 906.639 221.904 ;
      RECT 0.216 222.576 906.639 222.672 ;
      RECT 0.216 223.344 906.639 223.440 ;
      RECT 0.216 224.112 906.639 224.208 ;
      RECT 0.216 224.880 906.639 224.976 ;
      RECT 0.216 225.648 906.639 225.744 ;
      RECT 0.216 226.416 906.639 226.512 ;
      RECT 0.216 227.184 906.639 227.280 ;
      RECT 0.216 227.952 906.639 228.048 ;
      RECT 0.216 228.720 906.639 228.816 ;
      RECT 0.216 229.488 906.639 229.584 ;
      RECT 0.216 230.256 906.639 230.352 ;
      RECT 0.216 231.024 906.639 231.120 ;
      RECT 0.216 231.792 906.639 231.888 ;
      RECT 0.216 232.560 906.639 232.656 ;
      RECT 0.216 233.328 906.639 233.424 ;
      RECT 0.216 234.096 906.639 234.192 ;
      RECT 0.216 234.864 906.639 234.960 ;
      RECT 0.216 235.632 906.639 235.728 ;
      RECT 0.216 236.400 906.639 236.496 ;
      RECT 0.216 237.168 906.639 237.264 ;
      RECT 0.216 237.936 906.639 238.032 ;
      RECT 0.216 238.704 906.639 238.800 ;
      RECT 0.216 239.472 906.639 239.568 ;
      RECT 0.216 240.240 906.639 240.336 ;
      RECT 0.216 241.008 906.639 241.104 ;
      RECT 0.216 241.776 906.639 241.872 ;
      RECT 0.216 242.544 906.639 242.640 ;
      RECT 0.216 243.312 906.639 243.408 ;
      RECT 0.216 244.080 906.639 244.176 ;
      RECT 0.216 244.848 906.639 244.944 ;
      RECT 0.216 245.616 906.639 245.712 ;
      RECT 0.216 246.384 906.639 246.480 ;
      RECT 0.216 247.152 906.639 247.248 ;
      RECT 0.216 247.920 906.639 248.016 ;
      RECT 0.216 248.688 906.639 248.784 ;
      RECT 0.216 249.456 906.639 249.552 ;
      RECT 0.216 250.224 906.639 250.320 ;
      RECT 0.216 250.992 906.639 251.088 ;
      RECT 0.216 251.760 906.639 251.856 ;
      RECT 0.216 252.528 906.639 252.624 ;
      RECT 0.216 253.296 906.639 253.392 ;
      RECT 0.216 254.064 906.639 254.160 ;
      RECT 0.216 254.832 906.639 254.928 ;
      RECT 0.216 255.600 906.639 255.696 ;
      RECT 0.216 256.368 906.639 256.464 ;
      RECT 0.216 257.136 906.639 257.232 ;
      RECT 0.216 257.904 906.639 258.000 ;
      RECT 0.216 258.672 906.639 258.768 ;
      RECT 0.216 259.440 906.639 259.536 ;
      RECT 0.216 260.208 906.639 260.304 ;
      RECT 0.216 260.976 906.639 261.072 ;
      RECT 0.216 261.744 906.639 261.840 ;
      RECT 0.216 262.512 906.639 262.608 ;
      RECT 0.216 263.280 906.639 263.376 ;
      RECT 0.216 264.048 906.639 264.144 ;
      RECT 0.216 264.816 906.639 264.912 ;
      RECT 0.216 265.584 906.639 265.680 ;
      RECT 0.216 266.352 906.639 266.448 ;
      RECT 0.216 267.120 906.639 267.216 ;
      RECT 0.216 267.888 906.639 267.984 ;
      RECT 0.216 268.656 906.639 268.752 ;
      RECT 0.216 269.424 906.639 269.520 ;
      RECT 0.216 270.192 906.639 270.288 ;
      RECT 0.216 270.960 906.639 271.056 ;
      RECT 0.216 271.728 906.639 271.824 ;
      RECT 0.216 272.496 906.639 272.592 ;
      RECT 0.216 273.264 906.639 273.360 ;
      RECT 0.216 274.032 906.639 274.128 ;
      RECT 0.216 274.800 906.639 274.896 ;
      RECT 0.216 275.568 906.639 275.664 ;
      RECT 0.216 276.336 906.639 276.432 ;
      RECT 0.216 277.104 906.639 277.200 ;
      RECT 0.216 277.872 906.639 277.968 ;
      RECT 0.216 278.640 906.639 278.736 ;
      RECT 0.216 279.408 906.639 279.504 ;
      RECT 0.216 280.176 906.639 280.272 ;
      RECT 0.216 280.944 906.639 281.040 ;
      RECT 0.216 281.712 906.639 281.808 ;
      RECT 0.216 282.480 906.639 282.576 ;
      RECT 0.216 283.248 906.639 283.344 ;
      RECT 0.216 284.016 906.639 284.112 ;
      RECT 0.216 284.784 906.639 284.880 ;
      RECT 0.216 285.552 906.639 285.648 ;
      RECT 0.216 286.320 906.639 286.416 ;
      RECT 0.216 287.088 906.639 287.184 ;
      RECT 0.216 287.856 906.639 287.952 ;
      RECT 0.216 288.624 906.639 288.720 ;
      RECT 0.216 289.392 906.639 289.488 ;
      RECT 0.216 290.160 906.639 290.256 ;
      RECT 0.216 290.928 906.639 291.024 ;
      RECT 0.216 291.696 906.639 291.792 ;
      RECT 0.216 292.464 906.639 292.560 ;
      RECT 0.216 293.232 906.639 293.328 ;
      RECT 0.216 294.000 906.639 294.096 ;
      RECT 0.216 294.768 906.639 294.864 ;
      RECT 0.216 295.536 906.639 295.632 ;
      RECT 0.216 296.304 906.639 296.400 ;
      RECT 0.216 297.072 906.639 297.168 ;
      RECT 0.216 297.840 906.639 297.936 ;
      RECT 0.216 298.608 906.639 298.704 ;
      RECT 0.216 299.376 906.639 299.472 ;
      RECT 0.216 300.144 906.639 300.240 ;
      RECT 0.216 300.912 906.639 301.008 ;
      RECT 0.216 301.680 906.639 301.776 ;
      RECT 0.216 302.448 906.639 302.544 ;
      RECT 0.216 303.216 906.639 303.312 ;
      RECT 0.216 303.984 906.639 304.080 ;
      RECT 0.216 304.752 906.639 304.848 ;
      RECT 0.216 305.520 906.639 305.616 ;
      RECT 0.216 306.288 906.639 306.384 ;
      RECT 0.216 307.056 906.639 307.152 ;
      RECT 0.216 307.824 906.639 307.920 ;
      RECT 0.216 308.592 906.639 308.688 ;
      RECT 0.216 309.360 906.639 309.456 ;
      RECT 0.216 310.128 906.639 310.224 ;
      RECT 0.216 310.896 906.639 310.992 ;
      RECT 0.216 311.664 906.639 311.760 ;
      RECT 0.216 312.432 906.639 312.528 ;
      RECT 0.216 313.200 906.639 313.296 ;
      RECT 0.216 313.968 906.639 314.064 ;
      RECT 0.216 314.736 906.639 314.832 ;
      RECT 0.216 315.504 906.639 315.600 ;
      RECT 0.216 316.272 906.639 316.368 ;
      RECT 0.216 317.040 906.639 317.136 ;
      RECT 0.216 317.808 906.639 317.904 ;
      RECT 0.216 318.576 906.639 318.672 ;
      RECT 0.216 319.344 906.639 319.440 ;
      RECT 0.216 320.112 906.639 320.208 ;
      RECT 0.216 320.880 906.639 320.976 ;
      RECT 0.216 321.648 906.639 321.744 ;
      RECT 0.216 322.416 906.639 322.512 ;
      RECT 0.216 323.184 906.639 323.280 ;
      RECT 0.216 323.952 906.639 324.048 ;
      RECT 0.216 324.720 906.639 324.816 ;
      RECT 0.216 325.488 906.639 325.584 ;
      RECT 0.216 326.256 906.639 326.352 ;
      RECT 0.216 327.024 906.639 327.120 ;
      RECT 0.216 327.792 906.639 327.888 ;
      RECT 0.216 328.560 906.639 328.656 ;
      RECT 0.216 329.328 906.639 329.424 ;
      RECT 0.216 330.096 906.639 330.192 ;
      RECT 0.216 330.864 906.639 330.960 ;
      RECT 0.216 331.632 906.639 331.728 ;
      RECT 0.216 332.400 906.639 332.496 ;
      RECT 0.216 333.168 906.639 333.264 ;
      RECT 0.216 333.936 906.639 334.032 ;
      RECT 0.216 334.704 906.639 334.800 ;
      RECT 0.216 335.472 906.639 335.568 ;
      RECT 0.216 336.240 906.639 336.336 ;
      RECT 0.216 337.008 906.639 337.104 ;
      RECT 0.216 337.776 906.639 337.872 ;
      RECT 0.216 338.544 906.639 338.640 ;
      RECT 0.216 339.312 906.639 339.408 ;
      RECT 0.216 340.080 906.639 340.176 ;
      RECT 0.216 340.848 906.639 340.944 ;
      RECT 0.216 341.616 906.639 341.712 ;
      RECT 0.216 342.384 906.639 342.480 ;
      RECT 0.216 343.152 906.639 343.248 ;
      RECT 0.216 343.920 906.639 344.016 ;
      RECT 0.216 344.688 906.639 344.784 ;
      RECT 0.216 345.456 906.639 345.552 ;
      RECT 0.216 346.224 906.639 346.320 ;
      RECT 0.216 346.992 906.639 347.088 ;
      RECT 0.216 347.760 906.639 347.856 ;
      RECT 0.216 348.528 906.639 348.624 ;
      RECT 0.216 349.296 906.639 349.392 ;
      RECT 0.216 350.064 906.639 350.160 ;
      RECT 0.216 350.832 906.639 350.928 ;
      RECT 0.216 351.600 906.639 351.696 ;
      RECT 0.216 352.368 906.639 352.464 ;
      RECT 0.216 353.136 906.639 353.232 ;
      RECT 0.216 353.904 906.639 354.000 ;
      RECT 0.216 354.672 906.639 354.768 ;
      RECT 0.216 355.440 906.639 355.536 ;
      RECT 0.216 356.208 906.639 356.304 ;
      RECT 0.216 356.976 906.639 357.072 ;
      RECT 0.216 357.744 906.639 357.840 ;
      RECT 0.216 358.512 906.639 358.608 ;
      RECT 0.216 359.280 906.639 359.376 ;
      RECT 0.216 360.048 906.639 360.144 ;
      RECT 0.216 360.816 906.639 360.912 ;
      RECT 0.216 361.584 906.639 361.680 ;
      RECT 0.216 362.352 906.639 362.448 ;
      RECT 0.216 363.120 906.639 363.216 ;
      RECT 0.216 363.888 906.639 363.984 ;
      RECT 0.216 364.656 906.639 364.752 ;
      RECT 0.216 365.424 906.639 365.520 ;
      RECT 0.216 366.192 906.639 366.288 ;
      RECT 0.216 366.960 906.639 367.056 ;
      RECT 0.216 367.728 906.639 367.824 ;
      RECT 0.216 368.496 906.639 368.592 ;
      RECT 0.216 369.264 906.639 369.360 ;
      RECT 0.216 370.032 906.639 370.128 ;
      RECT 0.216 370.800 906.639 370.896 ;
      RECT 0.216 371.568 906.639 371.664 ;
      RECT 0.216 372.336 906.639 372.432 ;
      RECT 0.216 373.104 906.639 373.200 ;
      RECT 0.216 373.872 906.639 373.968 ;
      RECT 0.216 374.640 906.639 374.736 ;
      RECT 0.216 375.408 906.639 375.504 ;
      RECT 0.216 376.176 906.639 376.272 ;
      RECT 0.216 376.944 906.639 377.040 ;
      RECT 0.216 377.712 906.639 377.808 ;
      RECT 0.216 378.480 906.639 378.576 ;
      RECT 0.216 379.248 906.639 379.344 ;
      RECT 0.216 380.016 906.639 380.112 ;
      RECT 0.216 380.784 906.639 380.880 ;
      RECT 0.216 381.552 906.639 381.648 ;
      RECT 0.216 382.320 906.639 382.416 ;
      RECT 0.216 383.088 906.639 383.184 ;
      RECT 0.216 383.856 906.639 383.952 ;
      RECT 0.216 384.624 906.639 384.720 ;
      RECT 0.216 385.392 906.639 385.488 ;
      RECT 0.216 386.160 906.639 386.256 ;
      RECT 0.216 386.928 906.639 387.024 ;
      RECT 0.216 387.696 906.639 387.792 ;
      RECT 0.216 388.464 906.639 388.560 ;
      RECT 0.216 389.232 906.639 389.328 ;
      RECT 0.216 390.000 906.639 390.096 ;
      RECT 0.216 390.768 906.639 390.864 ;
      RECT 0.216 391.536 906.639 391.632 ;
      RECT 0.216 392.304 906.639 392.400 ;
      RECT 0.216 393.072 906.639 393.168 ;
      RECT 0.216 393.840 906.639 393.936 ;
      RECT 0.216 394.608 906.639 394.704 ;
      RECT 0.216 395.376 906.639 395.472 ;
      RECT 0.216 396.144 906.639 396.240 ;
      RECT 0.216 396.912 906.639 397.008 ;
      RECT 0.216 397.680 906.639 397.776 ;
      RECT 0.216 398.448 906.639 398.544 ;
      RECT 0.216 399.216 906.639 399.312 ;
      RECT 0.216 399.984 906.639 400.080 ;
      RECT 0.216 400.752 906.639 400.848 ;
      RECT 0.216 401.520 906.639 401.616 ;
      RECT 0.216 402.288 906.639 402.384 ;
      RECT 0.216 403.056 906.639 403.152 ;
      RECT 0.216 403.824 906.639 403.920 ;
      RECT 0.216 404.592 906.639 404.688 ;
      RECT 0.216 405.360 906.639 405.456 ;
      RECT 0.216 406.128 906.639 406.224 ;
      RECT 0.216 406.896 906.639 406.992 ;
      RECT 0.216 407.664 906.639 407.760 ;
      RECT 0.216 408.432 906.639 408.528 ;
      RECT 0.216 409.200 906.639 409.296 ;
      RECT 0.216 409.968 906.639 410.064 ;
      RECT 0.216 410.736 906.639 410.832 ;
      RECT 0.216 411.504 906.639 411.600 ;
      RECT 0.216 412.272 906.639 412.368 ;
      RECT 0.216 413.040 906.639 413.136 ;
      RECT 0.216 413.808 906.639 413.904 ;
      RECT 0.216 414.576 906.639 414.672 ;
      RECT 0.216 415.344 906.639 415.440 ;
      RECT 0.216 416.112 906.639 416.208 ;
      RECT 0.216 416.880 906.639 416.976 ;
      RECT 0.216 417.648 906.639 417.744 ;
      RECT 0.216 418.416 906.639 418.512 ;
      RECT 0.216 419.184 906.639 419.280 ;
      RECT 0.216 419.952 906.639 420.048 ;
      RECT 0.216 420.720 906.639 420.816 ;
      RECT 0.216 421.488 906.639 421.584 ;
      RECT 0.216 422.256 906.639 422.352 ;
      RECT 0.216 423.024 906.639 423.120 ;
      RECT 0.216 423.792 906.639 423.888 ;
      RECT 0.216 424.560 906.639 424.656 ;
      RECT 0.216 425.328 906.639 425.424 ;
      RECT 0.216 426.096 906.639 426.192 ;
      RECT 0.216 426.864 906.639 426.960 ;
      RECT 0.216 427.632 906.639 427.728 ;
      RECT 0.216 428.400 906.639 428.496 ;
      RECT 0.216 429.168 906.639 429.264 ;
      RECT 0.216 429.936 906.639 430.032 ;
      RECT 0.216 430.704 906.639 430.800 ;
      RECT 0.216 431.472 906.639 431.568 ;
      RECT 0.216 432.240 906.639 432.336 ;
      RECT 0.216 433.008 906.639 433.104 ;
      RECT 0.216 433.776 906.639 433.872 ;
      RECT 0.216 434.544 906.639 434.640 ;
      RECT 0.216 435.312 906.639 435.408 ;
      RECT 0.216 436.080 906.639 436.176 ;
      RECT 0.216 436.848 906.639 436.944 ;
      RECT 0.216 437.616 906.639 437.712 ;
      RECT 0.216 438.384 906.639 438.480 ;
      RECT 0.216 439.152 906.639 439.248 ;
      RECT 0.216 439.920 906.639 440.016 ;
      RECT 0.216 440.688 906.639 440.784 ;
      RECT 0.216 441.456 906.639 441.552 ;
      RECT 0.216 442.224 906.639 442.320 ;
      RECT 0.216 442.992 906.639 443.088 ;
      RECT 0.216 443.760 906.639 443.856 ;
      RECT 0.216 444.528 906.639 444.624 ;
      RECT 0.216 445.296 906.639 445.392 ;
      RECT 0.216 446.064 906.639 446.160 ;
      RECT 0.216 446.832 906.639 446.928 ;
      RECT 0.216 447.600 906.639 447.696 ;
      RECT 0.216 448.368 906.639 448.464 ;
      RECT 0.216 449.136 906.639 449.232 ;
      RECT 0.216 449.904 906.639 450.000 ;
      RECT 0.216 450.672 906.639 450.768 ;
      RECT 0.216 451.440 906.639 451.536 ;
      RECT 0.216 452.208 906.639 452.304 ;
      RECT 0.216 452.976 906.639 453.072 ;
      RECT 0.216 453.744 906.639 453.840 ;
      RECT 0.216 454.512 906.639 454.608 ;
      RECT 0.216 455.280 906.639 455.376 ;
      RECT 0.216 456.048 906.639 456.144 ;
      RECT 0.216 456.816 906.639 456.912 ;
      RECT 0.216 457.584 906.639 457.680 ;
      RECT 0.216 458.352 906.639 458.448 ;
      RECT 0.216 459.120 906.639 459.216 ;
      RECT 0.216 459.888 906.639 459.984 ;
      RECT 0.216 460.656 906.639 460.752 ;
      RECT 0.216 461.424 906.639 461.520 ;
      RECT 0.216 462.192 906.639 462.288 ;
      RECT 0.216 462.960 906.639 463.056 ;
      RECT 0.216 463.728 906.639 463.824 ;
      RECT 0.216 464.496 906.639 464.592 ;
      RECT 0.216 465.264 906.639 465.360 ;
      RECT 0.216 466.032 906.639 466.128 ;
      RECT 0.216 466.800 906.639 466.896 ;
      RECT 0.216 467.568 906.639 467.664 ;
      RECT 0.216 468.336 906.639 468.432 ;
      RECT 0.216 469.104 906.639 469.200 ;
      RECT 0.216 469.872 906.639 469.968 ;
      RECT 0.216 470.640 906.639 470.736 ;
      RECT 0.216 471.408 906.639 471.504 ;
      RECT 0.216 472.176 906.639 472.272 ;
      RECT 0.216 472.944 906.639 473.040 ;
      RECT 0.216 473.712 906.639 473.808 ;
      RECT 0.216 474.480 906.639 474.576 ;
      RECT 0.216 475.248 906.639 475.344 ;
      RECT 0.216 476.016 906.639 476.112 ;
      RECT 0.216 476.784 906.639 476.880 ;
      RECT 0.216 477.552 906.639 477.648 ;
      RECT 0.216 478.320 906.639 478.416 ;
      RECT 0.216 479.088 906.639 479.184 ;
      RECT 0.216 479.856 906.639 479.952 ;
      RECT 0.216 480.624 906.639 480.720 ;
      RECT 0.216 481.392 906.639 481.488 ;
      RECT 0.216 482.160 906.639 482.256 ;
      RECT 0.216 482.928 906.639 483.024 ;
      RECT 0.216 483.696 906.639 483.792 ;
      RECT 0.216 484.464 906.639 484.560 ;
      RECT 0.216 485.232 906.639 485.328 ;
      RECT 0.216 486.000 906.639 486.096 ;
      RECT 0.216 486.768 906.639 486.864 ;
      RECT 0.216 487.536 906.639 487.632 ;
      RECT 0.216 488.304 906.639 488.400 ;
      RECT 0.216 489.072 906.639 489.168 ;
      RECT 0.216 489.840 906.639 489.936 ;
      RECT 0.216 490.608 906.639 490.704 ;
      RECT 0.216 491.376 906.639 491.472 ;
      RECT 0.216 492.144 906.639 492.240 ;
      RECT 0.216 492.912 906.639 493.008 ;
      RECT 0.216 493.680 906.639 493.776 ;
      RECT 0.216 494.448 906.639 494.544 ;
      RECT 0.216 495.216 906.639 495.312 ;
      RECT 0.216 495.984 906.639 496.080 ;
      RECT 0.216 496.752 906.639 496.848 ;
      RECT 0.216 497.520 906.639 497.616 ;
      RECT 0.216 498.288 906.639 498.384 ;
      RECT 0.216 499.056 906.639 499.152 ;
      RECT 0.216 499.824 906.639 499.920 ;
      RECT 0.216 500.592 906.639 500.688 ;
      RECT 0.216 501.360 906.639 501.456 ;
      RECT 0.216 502.128 906.639 502.224 ;
      RECT 0.216 502.896 906.639 502.992 ;
      RECT 0.216 503.664 906.639 503.760 ;
      RECT 0.216 504.432 906.639 504.528 ;
      RECT 0.216 505.200 906.639 505.296 ;
      RECT 0.216 505.968 906.639 506.064 ;
      RECT 0.216 506.736 906.639 506.832 ;
      RECT 0.216 507.504 906.639 507.600 ;
      RECT 0.216 508.272 906.639 508.368 ;
      RECT 0.216 509.040 906.639 509.136 ;
      RECT 0.216 509.808 906.639 509.904 ;
      RECT 0.216 510.576 906.639 510.672 ;
      RECT 0.216 511.344 906.639 511.440 ;
      RECT 0.216 512.112 906.639 512.208 ;
      RECT 0.216 512.880 906.639 512.976 ;
      RECT 0.216 513.648 906.639 513.744 ;
      RECT 0.216 514.416 906.639 514.512 ;
      RECT 0.216 515.184 906.639 515.280 ;
      RECT 0.216 515.952 906.639 516.048 ;
      RECT 0.216 516.720 906.639 516.816 ;
      RECT 0.216 517.488 906.639 517.584 ;
      RECT 0.216 518.256 906.639 518.352 ;
      RECT 0.216 519.024 906.639 519.120 ;
      RECT 0.216 519.792 906.639 519.888 ;
      RECT 0.216 520.560 906.639 520.656 ;
      RECT 0.216 521.328 906.639 521.424 ;
      RECT 0.216 522.096 906.639 522.192 ;
      RECT 0.216 522.864 906.639 522.960 ;
      RECT 0.216 523.632 906.639 523.728 ;
      RECT 0.216 524.400 906.639 524.496 ;
      RECT 0.216 525.168 906.639 525.264 ;
      RECT 0.216 525.936 906.639 526.032 ;
      RECT 0.216 526.704 906.639 526.800 ;
      RECT 0.216 527.472 906.639 527.568 ;
      RECT 0.216 528.240 906.639 528.336 ;
      RECT 0.216 529.008 906.639 529.104 ;
      RECT 0.216 529.776 906.639 529.872 ;
      RECT 0.216 530.544 906.639 530.640 ;
      RECT 0.216 531.312 906.639 531.408 ;
      RECT 0.216 532.080 906.639 532.176 ;
      RECT 0.216 532.848 906.639 532.944 ;
      RECT 0.216 533.616 906.639 533.712 ;
      RECT 0.216 534.384 906.639 534.480 ;
      RECT 0.216 535.152 906.639 535.248 ;
      RECT 0.216 535.920 906.639 536.016 ;
      RECT 0.216 536.688 906.639 536.784 ;
      RECT 0.216 537.456 906.639 537.552 ;
      RECT 0.216 538.224 906.639 538.320 ;
      RECT 0.216 538.992 906.639 539.088 ;
      RECT 0.216 539.760 906.639 539.856 ;
      RECT 0.216 540.528 906.639 540.624 ;
      RECT 0.216 541.296 906.639 541.392 ;
      RECT 0.216 542.064 906.639 542.160 ;
      RECT 0.216 542.832 906.639 542.928 ;
      RECT 0.216 543.600 906.639 543.696 ;
      RECT 0.216 544.368 906.639 544.464 ;
      RECT 0.216 545.136 906.639 545.232 ;
      RECT 0.216 545.904 906.639 546.000 ;
      RECT 0.216 546.672 906.639 546.768 ;
      RECT 0.216 547.440 906.639 547.536 ;
      RECT 0.216 548.208 906.639 548.304 ;
      RECT 0.216 548.976 906.639 549.072 ;
      RECT 0.216 549.744 906.639 549.840 ;
      RECT 0.216 550.512 906.639 550.608 ;
      RECT 0.216 551.280 906.639 551.376 ;
      RECT 0.216 552.048 906.639 552.144 ;
      RECT 0.216 552.816 906.639 552.912 ;
      RECT 0.216 553.584 906.639 553.680 ;
      RECT 0.216 554.352 906.639 554.448 ;
      RECT 0.216 555.120 906.639 555.216 ;
      RECT 0.216 555.888 906.639 555.984 ;
      RECT 0.216 556.656 906.639 556.752 ;
      RECT 0.216 557.424 906.639 557.520 ;
      RECT 0.216 558.192 906.639 558.288 ;
      RECT 0.216 558.960 906.639 559.056 ;
      RECT 0.216 559.728 906.639 559.824 ;
      RECT 0.216 560.496 906.639 560.592 ;
      RECT 0.216 561.264 906.639 561.360 ;
      RECT 0.216 562.032 906.639 562.128 ;
      RECT 0.216 562.800 906.639 562.896 ;
      RECT 0.216 563.568 906.639 563.664 ;
      RECT 0.216 564.336 906.639 564.432 ;
      RECT 0.216 565.104 906.639 565.200 ;
      RECT 0.216 565.872 906.639 565.968 ;
      RECT 0.216 566.640 906.639 566.736 ;
    END
  END VDD
  OBS
    LAYER M1 ;
    RECT 0 0 906.855 566.784 ;
    LAYER M2 ;
    RECT 0 0 906.855 566.784 ;
    LAYER M3 ;
    RECT 0 0 906.855 566.784 ;
    LAYER M4 ;
    RECT 0 0 906.855 566.784 ;
  END
END fakeram_512x2048_1r1w

END LIBRARY
